VERSION 5.8 ;
BUSBITCHARS "[]" ;
DIVIDERCHAR "/" ;
UNITS
    DATABASE MICRONS 1000 ;
END UNITS

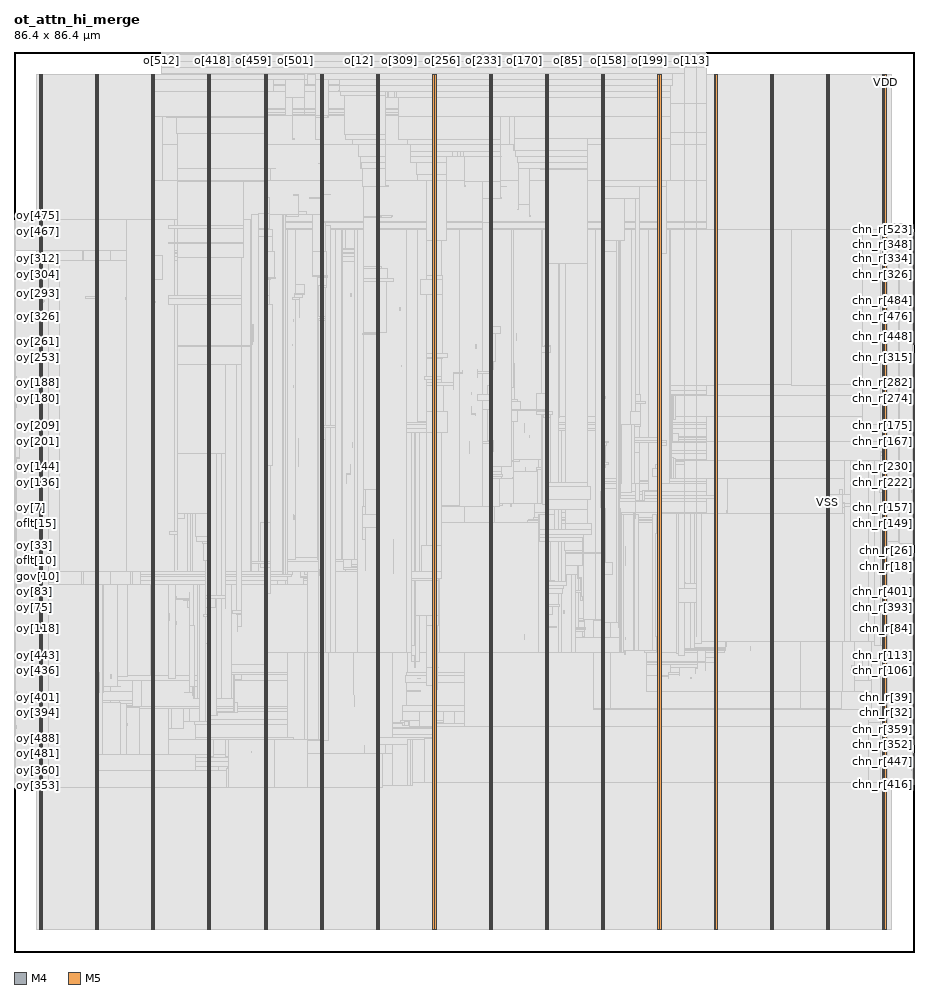
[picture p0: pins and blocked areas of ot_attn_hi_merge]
MACRO ot_attn_hi_merge
  FOREIGN ot_attn_hi_merge 0 0 ;
  CLASS BLOCK ;
  SIZE 86.4 BY 86.4 ;
  PIN chn_r[0]
    DIRECTION INPUT ;
    USE SIGNAL ;
    PORT
      LAYER M4 ;
        RECT  86.316 35.28 86.4 35.304 ;
    END
  END chn_r[0]
  PIN chn_r[100]
    DIRECTION INPUT ;
    USE SIGNAL ;
    PORT
      LAYER M4 ;
        RECT  86.316 26.448 86.4 26.472 ;
    END
  END chn_r[100]
  PIN chn_r[101]
    DIRECTION INPUT ;
    USE SIGNAL ;
    PORT
      LAYER M4 ;
        RECT  86.316 26.544 86.4 26.568 ;
    END
  END chn_r[101]
  PIN chn_r[102]
    DIRECTION INPUT ;
    USE SIGNAL ;
    PORT
      LAYER M4 ;
        RECT  86.316 26.64 86.4 26.664 ;
    END
  END chn_r[102]
  PIN chn_r[103]
    DIRECTION INPUT ;
    USE SIGNAL ;
    PORT
      LAYER M4 ;
        RECT  86.316 26.736 86.4 26.76 ;
    END
  END chn_r[103]
  PIN chn_r[104]
    DIRECTION INPUT ;
    USE SIGNAL ;
    PORT
      LAYER M4 ;
        RECT  86.316 26.832 86.4 26.856 ;
    END
  END chn_r[104]
  PIN chn_r[105]
    DIRECTION INPUT ;
    USE SIGNAL ;
    PORT
      LAYER M4 ;
        RECT  86.316 26.928 86.4 26.952 ;
    END
  END chn_r[105]
  PIN chn_r[106]
    DIRECTION INPUT ;
    USE SIGNAL ;
    PORT
      LAYER M4 ;
        RECT  86.316 27.024 86.4 27.048 ;
    END
  END chn_r[106]
  PIN chn_r[107]
    DIRECTION INPUT ;
    USE SIGNAL ;
    PORT
      LAYER M4 ;
        RECT  86.316 27.12 86.4 27.144 ;
    END
  END chn_r[107]
  PIN chn_r[108]
    DIRECTION INPUT ;
    USE SIGNAL ;
    PORT
      LAYER M4 ;
        RECT  86.316 27.216 86.4 27.24 ;
    END
  END chn_r[108]
  PIN chn_r[109]
    DIRECTION INPUT ;
    USE SIGNAL ;
    PORT
      LAYER M4 ;
        RECT  86.316 27.312 86.4 27.336 ;
    END
  END chn_r[109]
  PIN chn_r[10]
    DIRECTION INPUT ;
    USE SIGNAL ;
    PORT
      LAYER M4 ;
        RECT  86.316 36.24 86.4 36.264 ;
    END
  END chn_r[10]
  PIN chn_r[110]
    DIRECTION INPUT ;
    USE SIGNAL ;
    PORT
      LAYER M4 ;
        RECT  86.316 27.408 86.4 27.432 ;
    END
  END chn_r[110]
  PIN chn_r[111]
    DIRECTION INPUT ;
    USE SIGNAL ;
    PORT
      LAYER M4 ;
        RECT  86.316 27.504 86.4 27.528 ;
    END
  END chn_r[111]
  PIN chn_r[112]
    DIRECTION INPUT ;
    USE SIGNAL ;
    PORT
      LAYER M4 ;
        RECT  86.316 27.6 86.4 27.624 ;
    END
  END chn_r[112]
  PIN chn_r[113]
    DIRECTION INPUT ;
    USE SIGNAL ;
    PORT
      LAYER M4 ;
        RECT  86.316 27.696 86.4 27.72 ;
    END
  END chn_r[113]
  PIN chn_r[114]
    DIRECTION INPUT ;
    USE SIGNAL ;
    PORT
      LAYER M4 ;
        RECT  86.316 27.792 86.4 27.816 ;
    END
  END chn_r[114]
  PIN chn_r[115]
    DIRECTION INPUT ;
    USE SIGNAL ;
    PORT
      LAYER M4 ;
        RECT  86.316 27.888 86.4 27.912 ;
    END
  END chn_r[115]
  PIN chn_r[116]
    DIRECTION INPUT ;
    USE SIGNAL ;
    PORT
      LAYER M4 ;
        RECT  86.316 27.984 86.4 28.008 ;
    END
  END chn_r[116]
  PIN chn_r[117]
    DIRECTION INPUT ;
    USE SIGNAL ;
    PORT
      LAYER M4 ;
        RECT  86.316 28.08 86.4 28.104 ;
    END
  END chn_r[117]
  PIN chn_r[118]
    DIRECTION INPUT ;
    USE SIGNAL ;
    PORT
      LAYER M4 ;
        RECT  86.316 28.176 86.4 28.2 ;
    END
  END chn_r[118]
  PIN chn_r[119]
    DIRECTION INPUT ;
    USE SIGNAL ;
    PORT
      LAYER M4 ;
        RECT  86.316 28.272 86.4 28.296 ;
    END
  END chn_r[119]
  PIN chn_r[11]
    DIRECTION INPUT ;
    USE SIGNAL ;
    PORT
      LAYER M4 ;
        RECT  86.316 36.336 86.4 36.36 ;
    END
  END chn_r[11]
  PIN chn_r[120]
    DIRECTION INPUT ;
    USE SIGNAL ;
    PORT
      LAYER M4 ;
        RECT  86.316 28.368 86.4 28.392 ;
    END
  END chn_r[120]
  PIN chn_r[121]
    DIRECTION INPUT ;
    USE SIGNAL ;
    PORT
      LAYER M4 ;
        RECT  86.316 28.464 86.4 28.488 ;
    END
  END chn_r[121]
  PIN chn_r[122]
    DIRECTION INPUT ;
    USE SIGNAL ;
    PORT
      LAYER M4 ;
        RECT  86.316 28.56 86.4 28.584 ;
    END
  END chn_r[122]
  PIN chn_r[123]
    DIRECTION INPUT ;
    USE SIGNAL ;
    PORT
      LAYER M4 ;
        RECT  86.316 28.656 86.4 28.68 ;
    END
  END chn_r[123]
  PIN chn_r[124]
    DIRECTION INPUT ;
    USE SIGNAL ;
    PORT
      LAYER M4 ;
        RECT  86.316 28.752 86.4 28.776 ;
    END
  END chn_r[124]
  PIN chn_r[125]
    DIRECTION INPUT ;
    USE SIGNAL ;
    PORT
      LAYER M4 ;
        RECT  86.316 28.848 86.4 28.872 ;
    END
  END chn_r[125]
  PIN chn_r[126]
    DIRECTION INPUT ;
    USE SIGNAL ;
    PORT
      LAYER M4 ;
        RECT  86.316 28.944 86.4 28.968 ;
    END
  END chn_r[126]
  PIN chn_r[127]
    DIRECTION INPUT ;
    USE SIGNAL ;
    PORT
      LAYER M4 ;
        RECT  86.316 29.04 86.4 29.064 ;
    END
  END chn_r[127]
  PIN chn_r[128]
    DIRECTION INPUT ;
    USE SIGNAL ;
    PORT
      LAYER M4 ;
        RECT  86.316 39.12 86.4 39.144 ;
    END
  END chn_r[128]
  PIN chn_r[129]
    DIRECTION INPUT ;
    USE SIGNAL ;
    PORT
      LAYER M4 ;
        RECT  86.316 39.216 86.4 39.24 ;
    END
  END chn_r[129]
  PIN chn_r[12]
    DIRECTION INPUT ;
    USE SIGNAL ;
    PORT
      LAYER M4 ;
        RECT  86.316 36.432 86.4 36.456 ;
    END
  END chn_r[12]
  PIN chn_r[130]
    DIRECTION INPUT ;
    USE SIGNAL ;
    PORT
      LAYER M4 ;
        RECT  86.316 39.312 86.4 39.336 ;
    END
  END chn_r[130]
  PIN chn_r[131]
    DIRECTION INPUT ;
    USE SIGNAL ;
    PORT
      LAYER M4 ;
        RECT  86.316 39.408 86.4 39.432 ;
    END
  END chn_r[131]
  PIN chn_r[132]
    DIRECTION INPUT ;
    USE SIGNAL ;
    PORT
      LAYER M4 ;
        RECT  86.316 39.504 86.4 39.528 ;
    END
  END chn_r[132]
  PIN chn_r[133]
    DIRECTION INPUT ;
    USE SIGNAL ;
    PORT
      LAYER M4 ;
        RECT  86.316 39.6 86.4 39.624 ;
    END
  END chn_r[133]
  PIN chn_r[134]
    DIRECTION INPUT ;
    USE SIGNAL ;
    PORT
      LAYER M4 ;
        RECT  86.316 39.696 86.4 39.72 ;
    END
  END chn_r[134]
  PIN chn_r[135]
    DIRECTION INPUT ;
    USE SIGNAL ;
    PORT
      LAYER M4 ;
        RECT  86.316 39.792 86.4 39.816 ;
    END
  END chn_r[135]
  PIN chn_r[136]
    DIRECTION INPUT ;
    USE SIGNAL ;
    PORT
      LAYER M4 ;
        RECT  86.316 39.888 86.4 39.912 ;
    END
  END chn_r[136]
  PIN chn_r[137]
    DIRECTION INPUT ;
    USE SIGNAL ;
    PORT
      LAYER M4 ;
        RECT  86.316 39.984 86.4 40.008 ;
    END
  END chn_r[137]
  PIN chn_r[138]
    DIRECTION INPUT ;
    USE SIGNAL ;
    PORT
      LAYER M4 ;
        RECT  86.316 40.08 86.4 40.104 ;
    END
  END chn_r[138]
  PIN chn_r[139]
    DIRECTION INPUT ;
    USE SIGNAL ;
    PORT
      LAYER M4 ;
        RECT  86.316 40.176 86.4 40.2 ;
    END
  END chn_r[139]
  PIN chn_r[13]
    DIRECTION INPUT ;
    USE SIGNAL ;
    PORT
      LAYER M4 ;
        RECT  86.316 36.528 86.4 36.552 ;
    END
  END chn_r[13]
  PIN chn_r[140]
    DIRECTION INPUT ;
    USE SIGNAL ;
    PORT
      LAYER M4 ;
        RECT  86.316 40.272 86.4 40.296 ;
    END
  END chn_r[140]
  PIN chn_r[141]
    DIRECTION INPUT ;
    USE SIGNAL ;
    PORT
      LAYER M4 ;
        RECT  86.316 40.368 86.4 40.392 ;
    END
  END chn_r[141]
  PIN chn_r[142]
    DIRECTION INPUT ;
    USE SIGNAL ;
    PORT
      LAYER M4 ;
        RECT  86.316 40.464 86.4 40.488 ;
    END
  END chn_r[142]
  PIN chn_r[143]
    DIRECTION INPUT ;
    USE SIGNAL ;
    PORT
      LAYER M4 ;
        RECT  86.316 40.56 86.4 40.584 ;
    END
  END chn_r[143]
  PIN chn_r[144]
    DIRECTION INPUT ;
    USE SIGNAL ;
    PORT
      LAYER M4 ;
        RECT  86.316 40.656 86.4 40.68 ;
    END
  END chn_r[144]
  PIN chn_r[145]
    DIRECTION INPUT ;
    USE SIGNAL ;
    PORT
      LAYER M4 ;
        RECT  86.316 40.752 86.4 40.776 ;
    END
  END chn_r[145]
  PIN chn_r[146]
    DIRECTION INPUT ;
    USE SIGNAL ;
    PORT
      LAYER M4 ;
        RECT  86.316 40.848 86.4 40.872 ;
    END
  END chn_r[146]
  PIN chn_r[147]
    DIRECTION INPUT ;
    USE SIGNAL ;
    PORT
      LAYER M4 ;
        RECT  86.316 40.944 86.4 40.968 ;
    END
  END chn_r[147]
  PIN chn_r[148]
    DIRECTION INPUT ;
    USE SIGNAL ;
    PORT
      LAYER M4 ;
        RECT  86.316 41.04 86.4 41.064 ;
    END
  END chn_r[148]
  PIN chn_r[149]
    DIRECTION INPUT ;
    USE SIGNAL ;
    PORT
      LAYER M4 ;
        RECT  86.316 41.136 86.4 41.16 ;
    END
  END chn_r[149]
  PIN chn_r[14]
    DIRECTION INPUT ;
    USE SIGNAL ;
    PORT
      LAYER M4 ;
        RECT  86.316 36.624 86.4 36.648 ;
    END
  END chn_r[14]
  PIN chn_r[150]
    DIRECTION INPUT ;
    USE SIGNAL ;
    PORT
      LAYER M4 ;
        RECT  86.316 41.232 86.4 41.256 ;
    END
  END chn_r[150]
  PIN chn_r[151]
    DIRECTION INPUT ;
    USE SIGNAL ;
    PORT
      LAYER M4 ;
        RECT  86.316 41.328 86.4 41.352 ;
    END
  END chn_r[151]
  PIN chn_r[152]
    DIRECTION INPUT ;
    USE SIGNAL ;
    PORT
      LAYER M4 ;
        RECT  86.316 41.424 86.4 41.448 ;
    END
  END chn_r[152]
  PIN chn_r[153]
    DIRECTION INPUT ;
    USE SIGNAL ;
    PORT
      LAYER M4 ;
        RECT  86.316 41.52 86.4 41.544 ;
    END
  END chn_r[153]
  PIN chn_r[154]
    DIRECTION INPUT ;
    USE SIGNAL ;
    PORT
      LAYER M4 ;
        RECT  86.316 41.616 86.4 41.64 ;
    END
  END chn_r[154]
  PIN chn_r[155]
    DIRECTION INPUT ;
    USE SIGNAL ;
    PORT
      LAYER M4 ;
        RECT  86.316 41.712 86.4 41.736 ;
    END
  END chn_r[155]
  PIN chn_r[156]
    DIRECTION INPUT ;
    USE SIGNAL ;
    PORT
      LAYER M4 ;
        RECT  86.316 41.808 86.4 41.832 ;
    END
  END chn_r[156]
  PIN chn_r[157]
    DIRECTION INPUT ;
    USE SIGNAL ;
    PORT
      LAYER M4 ;
        RECT  86.316 41.904 86.4 41.928 ;
    END
  END chn_r[157]
  PIN chn_r[158]
    DIRECTION INPUT ;
    USE SIGNAL ;
    PORT
      LAYER M4 ;
        RECT  86.316 42 86.4 42.024 ;
    END
  END chn_r[158]
  PIN chn_r[159]
    DIRECTION INPUT ;
    USE SIGNAL ;
    PORT
      LAYER M4 ;
        RECT  86.316 42.096 86.4 42.12 ;
    END
  END chn_r[159]
  PIN chn_r[15]
    DIRECTION INPUT ;
    USE SIGNAL ;
    PORT
      LAYER M4 ;
        RECT  86.316 36.72 86.4 36.744 ;
    END
  END chn_r[15]
  PIN chn_r[160]
    DIRECTION INPUT ;
    USE SIGNAL ;
    PORT
      LAYER M4 ;
        RECT  86.316 48.336 86.4 48.36 ;
    END
  END chn_r[160]
  PIN chn_r[161]
    DIRECTION INPUT ;
    USE SIGNAL ;
    PORT
      LAYER M4 ;
        RECT  86.316 48.432 86.4 48.456 ;
    END
  END chn_r[161]
  PIN chn_r[162]
    DIRECTION INPUT ;
    USE SIGNAL ;
    PORT
      LAYER M4 ;
        RECT  86.316 48.528 86.4 48.552 ;
    END
  END chn_r[162]
  PIN chn_r[163]
    DIRECTION INPUT ;
    USE SIGNAL ;
    PORT
      LAYER M4 ;
        RECT  86.316 48.624 86.4 48.648 ;
    END
  END chn_r[163]
  PIN chn_r[164]
    DIRECTION INPUT ;
    USE SIGNAL ;
    PORT
      LAYER M4 ;
        RECT  86.316 48.72 86.4 48.744 ;
    END
  END chn_r[164]
  PIN chn_r[165]
    DIRECTION INPUT ;
    USE SIGNAL ;
    PORT
      LAYER M4 ;
        RECT  86.316 48.816 86.4 48.84 ;
    END
  END chn_r[165]
  PIN chn_r[166]
    DIRECTION INPUT ;
    USE SIGNAL ;
    PORT
      LAYER M4 ;
        RECT  86.316 48.912 86.4 48.936 ;
    END
  END chn_r[166]
  PIN chn_r[167]
    DIRECTION INPUT ;
    USE SIGNAL ;
    PORT
      LAYER M4 ;
        RECT  86.316 49.008 86.4 49.032 ;
    END
  END chn_r[167]
  PIN chn_r[168]
    DIRECTION INPUT ;
    USE SIGNAL ;
    PORT
      LAYER M4 ;
        RECT  86.316 49.104 86.4 49.128 ;
    END
  END chn_r[168]
  PIN chn_r[169]
    DIRECTION INPUT ;
    USE SIGNAL ;
    PORT
      LAYER M4 ;
        RECT  86.316 49.2 86.4 49.224 ;
    END
  END chn_r[169]
  PIN chn_r[16]
    DIRECTION INPUT ;
    USE SIGNAL ;
    PORT
      LAYER M4 ;
        RECT  86.316 36.816 86.4 36.84 ;
    END
  END chn_r[16]
  PIN chn_r[170]
    DIRECTION INPUT ;
    USE SIGNAL ;
    PORT
      LAYER M4 ;
        RECT  86.316 49.296 86.4 49.32 ;
    END
  END chn_r[170]
  PIN chn_r[171]
    DIRECTION INPUT ;
    USE SIGNAL ;
    PORT
      LAYER M4 ;
        RECT  86.316 49.392 86.4 49.416 ;
    END
  END chn_r[171]
  PIN chn_r[172]
    DIRECTION INPUT ;
    USE SIGNAL ;
    PORT
      LAYER M4 ;
        RECT  86.316 49.488 86.4 49.512 ;
    END
  END chn_r[172]
  PIN chn_r[173]
    DIRECTION INPUT ;
    USE SIGNAL ;
    PORT
      LAYER M4 ;
        RECT  86.316 49.584 86.4 49.608 ;
    END
  END chn_r[173]
  PIN chn_r[174]
    DIRECTION INPUT ;
    USE SIGNAL ;
    PORT
      LAYER M4 ;
        RECT  86.316 49.68 86.4 49.704 ;
    END
  END chn_r[174]
  PIN chn_r[175]
    DIRECTION INPUT ;
    USE SIGNAL ;
    PORT
      LAYER M4 ;
        RECT  86.316 49.776 86.4 49.8 ;
    END
  END chn_r[175]
  PIN chn_r[176]
    DIRECTION INPUT ;
    USE SIGNAL ;
    PORT
      LAYER M4 ;
        RECT  86.316 49.872 86.4 49.896 ;
    END
  END chn_r[176]
  PIN chn_r[177]
    DIRECTION INPUT ;
    USE SIGNAL ;
    PORT
      LAYER M4 ;
        RECT  86.316 49.968 86.4 49.992 ;
    END
  END chn_r[177]
  PIN chn_r[178]
    DIRECTION INPUT ;
    USE SIGNAL ;
    PORT
      LAYER M4 ;
        RECT  86.316 50.064 86.4 50.088 ;
    END
  END chn_r[178]
  PIN chn_r[179]
    DIRECTION INPUT ;
    USE SIGNAL ;
    PORT
      LAYER M4 ;
        RECT  86.316 50.16 86.4 50.184 ;
    END
  END chn_r[179]
  PIN chn_r[17]
    DIRECTION INPUT ;
    USE SIGNAL ;
    PORT
      LAYER M4 ;
        RECT  86.316 36.912 86.4 36.936 ;
    END
  END chn_r[17]
  PIN chn_r[180]
    DIRECTION INPUT ;
    USE SIGNAL ;
    PORT
      LAYER M4 ;
        RECT  86.316 50.256 86.4 50.28 ;
    END
  END chn_r[180]
  PIN chn_r[181]
    DIRECTION INPUT ;
    USE SIGNAL ;
    PORT
      LAYER M4 ;
        RECT  86.316 50.352 86.4 50.376 ;
    END
  END chn_r[181]
  PIN chn_r[182]
    DIRECTION INPUT ;
    USE SIGNAL ;
    PORT
      LAYER M4 ;
        RECT  86.316 50.448 86.4 50.472 ;
    END
  END chn_r[182]
  PIN chn_r[183]
    DIRECTION INPUT ;
    USE SIGNAL ;
    PORT
      LAYER M4 ;
        RECT  86.316 50.544 86.4 50.568 ;
    END
  END chn_r[183]
  PIN chn_r[184]
    DIRECTION INPUT ;
    USE SIGNAL ;
    PORT
      LAYER M4 ;
        RECT  86.316 50.64 86.4 50.664 ;
    END
  END chn_r[184]
  PIN chn_r[185]
    DIRECTION INPUT ;
    USE SIGNAL ;
    PORT
      LAYER M4 ;
        RECT  86.316 50.736 86.4 50.76 ;
    END
  END chn_r[185]
  PIN chn_r[186]
    DIRECTION INPUT ;
    USE SIGNAL ;
    PORT
      LAYER M4 ;
        RECT  86.316 50.832 86.4 50.856 ;
    END
  END chn_r[186]
  PIN chn_r[187]
    DIRECTION INPUT ;
    USE SIGNAL ;
    PORT
      LAYER M4 ;
        RECT  86.316 50.928 86.4 50.952 ;
    END
  END chn_r[187]
  PIN chn_r[188]
    DIRECTION INPUT ;
    USE SIGNAL ;
    PORT
      LAYER M4 ;
        RECT  86.316 51.024 86.4 51.048 ;
    END
  END chn_r[188]
  PIN chn_r[189]
    DIRECTION INPUT ;
    USE SIGNAL ;
    PORT
      LAYER M4 ;
        RECT  86.316 51.12 86.4 51.144 ;
    END
  END chn_r[189]
  PIN chn_r[18]
    DIRECTION INPUT ;
    USE SIGNAL ;
    PORT
      LAYER M4 ;
        RECT  86.316 37.008 86.4 37.032 ;
    END
  END chn_r[18]
  PIN chn_r[190]
    DIRECTION INPUT ;
    USE SIGNAL ;
    PORT
      LAYER M4 ;
        RECT  86.316 51.216 86.4 51.24 ;
    END
  END chn_r[190]
  PIN chn_r[191]
    DIRECTION INPUT ;
    USE SIGNAL ;
    PORT
      LAYER M4 ;
        RECT  86.316 51.312 86.4 51.336 ;
    END
  END chn_r[191]
  PIN chn_r[192]
    DIRECTION INPUT ;
    USE SIGNAL ;
    PORT
      LAYER M4 ;
        RECT  86.316 42.192 86.4 42.216 ;
    END
  END chn_r[192]
  PIN chn_r[193]
    DIRECTION INPUT ;
    USE SIGNAL ;
    PORT
      LAYER M4 ;
        RECT  86.316 42.288 86.4 42.312 ;
    END
  END chn_r[193]
  PIN chn_r[194]
    DIRECTION INPUT ;
    USE SIGNAL ;
    PORT
      LAYER M4 ;
        RECT  86.316 42.384 86.4 42.408 ;
    END
  END chn_r[194]
  PIN chn_r[195]
    DIRECTION INPUT ;
    USE SIGNAL ;
    PORT
      LAYER M4 ;
        RECT  86.316 42.48 86.4 42.504 ;
    END
  END chn_r[195]
  PIN chn_r[196]
    DIRECTION INPUT ;
    USE SIGNAL ;
    PORT
      LAYER M4 ;
        RECT  86.316 42.576 86.4 42.6 ;
    END
  END chn_r[196]
  PIN chn_r[197]
    DIRECTION INPUT ;
    USE SIGNAL ;
    PORT
      LAYER M4 ;
        RECT  86.316 42.672 86.4 42.696 ;
    END
  END chn_r[197]
  PIN chn_r[198]
    DIRECTION INPUT ;
    USE SIGNAL ;
    PORT
      LAYER M4 ;
        RECT  86.316 42.768 86.4 42.792 ;
    END
  END chn_r[198]
  PIN chn_r[199]
    DIRECTION INPUT ;
    USE SIGNAL ;
    PORT
      LAYER M4 ;
        RECT  86.316 42.864 86.4 42.888 ;
    END
  END chn_r[199]
  PIN chn_r[19]
    DIRECTION INPUT ;
    USE SIGNAL ;
    PORT
      LAYER M4 ;
        RECT  86.316 37.104 86.4 37.128 ;
    END
  END chn_r[19]
  PIN chn_r[1]
    DIRECTION INPUT ;
    USE SIGNAL ;
    PORT
      LAYER M4 ;
        RECT  86.316 35.376 86.4 35.4 ;
    END
  END chn_r[1]
  PIN chn_r[200]
    DIRECTION INPUT ;
    USE SIGNAL ;
    PORT
      LAYER M4 ;
        RECT  86.316 42.96 86.4 42.984 ;
    END
  END chn_r[200]
  PIN chn_r[201]
    DIRECTION INPUT ;
    USE SIGNAL ;
    PORT
      LAYER M4 ;
        RECT  86.316 43.056 86.4 43.08 ;
    END
  END chn_r[201]
  PIN chn_r[202]
    DIRECTION INPUT ;
    USE SIGNAL ;
    PORT
      LAYER M4 ;
        RECT  86.316 43.152 86.4 43.176 ;
    END
  END chn_r[202]
  PIN chn_r[203]
    DIRECTION INPUT ;
    USE SIGNAL ;
    PORT
      LAYER M4 ;
        RECT  86.316 43.248 86.4 43.272 ;
    END
  END chn_r[203]
  PIN chn_r[204]
    DIRECTION INPUT ;
    USE SIGNAL ;
    PORT
      LAYER M4 ;
        RECT  86.316 43.344 86.4 43.368 ;
    END
  END chn_r[204]
  PIN chn_r[205]
    DIRECTION INPUT ;
    USE SIGNAL ;
    PORT
      LAYER M4 ;
        RECT  86.316 43.44 86.4 43.464 ;
    END
  END chn_r[205]
  PIN chn_r[206]
    DIRECTION INPUT ;
    USE SIGNAL ;
    PORT
      LAYER M4 ;
        RECT  86.316 43.536 86.4 43.56 ;
    END
  END chn_r[206]
  PIN chn_r[207]
    DIRECTION INPUT ;
    USE SIGNAL ;
    PORT
      LAYER M4 ;
        RECT  86.316 43.632 86.4 43.656 ;
    END
  END chn_r[207]
  PIN chn_r[208]
    DIRECTION INPUT ;
    USE SIGNAL ;
    PORT
      LAYER M4 ;
        RECT  86.316 43.728 86.4 43.752 ;
    END
  END chn_r[208]
  PIN chn_r[209]
    DIRECTION INPUT ;
    USE SIGNAL ;
    PORT
      LAYER M4 ;
        RECT  86.316 43.824 86.4 43.848 ;
    END
  END chn_r[209]
  PIN chn_r[20]
    DIRECTION INPUT ;
    USE SIGNAL ;
    PORT
      LAYER M4 ;
        RECT  86.316 37.2 86.4 37.224 ;
    END
  END chn_r[20]
  PIN chn_r[210]
    DIRECTION INPUT ;
    USE SIGNAL ;
    PORT
      LAYER M4 ;
        RECT  86.316 43.92 86.4 43.944 ;
    END
  END chn_r[210]
  PIN chn_r[211]
    DIRECTION INPUT ;
    USE SIGNAL ;
    PORT
      LAYER M4 ;
        RECT  86.316 44.016 86.4 44.04 ;
    END
  END chn_r[211]
  PIN chn_r[212]
    DIRECTION INPUT ;
    USE SIGNAL ;
    PORT
      LAYER M4 ;
        RECT  86.316 44.112 86.4 44.136 ;
    END
  END chn_r[212]
  PIN chn_r[213]
    DIRECTION INPUT ;
    USE SIGNAL ;
    PORT
      LAYER M4 ;
        RECT  86.316 44.208 86.4 44.232 ;
    END
  END chn_r[213]
  PIN chn_r[214]
    DIRECTION INPUT ;
    USE SIGNAL ;
    PORT
      LAYER M4 ;
        RECT  86.316 44.304 86.4 44.328 ;
    END
  END chn_r[214]
  PIN chn_r[215]
    DIRECTION INPUT ;
    USE SIGNAL ;
    PORT
      LAYER M4 ;
        RECT  86.316 44.4 86.4 44.424 ;
    END
  END chn_r[215]
  PIN chn_r[216]
    DIRECTION INPUT ;
    USE SIGNAL ;
    PORT
      LAYER M4 ;
        RECT  86.316 44.496 86.4 44.52 ;
    END
  END chn_r[216]
  PIN chn_r[217]
    DIRECTION INPUT ;
    USE SIGNAL ;
    PORT
      LAYER M4 ;
        RECT  86.316 44.592 86.4 44.616 ;
    END
  END chn_r[217]
  PIN chn_r[218]
    DIRECTION INPUT ;
    USE SIGNAL ;
    PORT
      LAYER M4 ;
        RECT  86.316 44.688 86.4 44.712 ;
    END
  END chn_r[218]
  PIN chn_r[219]
    DIRECTION INPUT ;
    USE SIGNAL ;
    PORT
      LAYER M4 ;
        RECT  86.316 44.784 86.4 44.808 ;
    END
  END chn_r[219]
  PIN chn_r[21]
    DIRECTION INPUT ;
    USE SIGNAL ;
    PORT
      LAYER M4 ;
        RECT  86.316 37.296 86.4 37.32 ;
    END
  END chn_r[21]
  PIN chn_r[220]
    DIRECTION INPUT ;
    USE SIGNAL ;
    PORT
      LAYER M4 ;
        RECT  86.316 44.88 86.4 44.904 ;
    END
  END chn_r[220]
  PIN chn_r[221]
    DIRECTION INPUT ;
    USE SIGNAL ;
    PORT
      LAYER M4 ;
        RECT  86.316 44.976 86.4 45 ;
    END
  END chn_r[221]
  PIN chn_r[222]
    DIRECTION INPUT ;
    USE SIGNAL ;
    PORT
      LAYER M4 ;
        RECT  86.316 45.072 86.4 45.096 ;
    END
  END chn_r[222]
  PIN chn_r[223]
    DIRECTION INPUT ;
    USE SIGNAL ;
    PORT
      LAYER M4 ;
        RECT  86.316 45.168 86.4 45.192 ;
    END
  END chn_r[223]
  PIN chn_r[224]
    DIRECTION INPUT ;
    USE SIGNAL ;
    PORT
      LAYER M4 ;
        RECT  86.316 45.264 86.4 45.288 ;
    END
  END chn_r[224]
  PIN chn_r[225]
    DIRECTION INPUT ;
    USE SIGNAL ;
    PORT
      LAYER M4 ;
        RECT  86.316 45.36 86.4 45.384 ;
    END
  END chn_r[225]
  PIN chn_r[226]
    DIRECTION INPUT ;
    USE SIGNAL ;
    PORT
      LAYER M4 ;
        RECT  86.316 45.456 86.4 45.48 ;
    END
  END chn_r[226]
  PIN chn_r[227]
    DIRECTION INPUT ;
    USE SIGNAL ;
    PORT
      LAYER M4 ;
        RECT  86.316 45.552 86.4 45.576 ;
    END
  END chn_r[227]
  PIN chn_r[228]
    DIRECTION INPUT ;
    USE SIGNAL ;
    PORT
      LAYER M4 ;
        RECT  86.316 45.648 86.4 45.672 ;
    END
  END chn_r[228]
  PIN chn_r[229]
    DIRECTION INPUT ;
    USE SIGNAL ;
    PORT
      LAYER M4 ;
        RECT  86.316 45.744 86.4 45.768 ;
    END
  END chn_r[229]
  PIN chn_r[22]
    DIRECTION INPUT ;
    USE SIGNAL ;
    PORT
      LAYER M4 ;
        RECT  86.316 37.392 86.4 37.416 ;
    END
  END chn_r[22]
  PIN chn_r[230]
    DIRECTION INPUT ;
    USE SIGNAL ;
    PORT
      LAYER M4 ;
        RECT  86.316 45.84 86.4 45.864 ;
    END
  END chn_r[230]
  PIN chn_r[231]
    DIRECTION INPUT ;
    USE SIGNAL ;
    PORT
      LAYER M4 ;
        RECT  86.316 45.936 86.4 45.96 ;
    END
  END chn_r[231]
  PIN chn_r[232]
    DIRECTION INPUT ;
    USE SIGNAL ;
    PORT
      LAYER M4 ;
        RECT  86.316 46.032 86.4 46.056 ;
    END
  END chn_r[232]
  PIN chn_r[233]
    DIRECTION INPUT ;
    USE SIGNAL ;
    PORT
      LAYER M4 ;
        RECT  86.316 46.128 86.4 46.152 ;
    END
  END chn_r[233]
  PIN chn_r[234]
    DIRECTION INPUT ;
    USE SIGNAL ;
    PORT
      LAYER M4 ;
        RECT  86.316 46.224 86.4 46.248 ;
    END
  END chn_r[234]
  PIN chn_r[235]
    DIRECTION INPUT ;
    USE SIGNAL ;
    PORT
      LAYER M4 ;
        RECT  86.316 46.32 86.4 46.344 ;
    END
  END chn_r[235]
  PIN chn_r[236]
    DIRECTION INPUT ;
    USE SIGNAL ;
    PORT
      LAYER M4 ;
        RECT  86.316 46.416 86.4 46.44 ;
    END
  END chn_r[236]
  PIN chn_r[237]
    DIRECTION INPUT ;
    USE SIGNAL ;
    PORT
      LAYER M4 ;
        RECT  86.316 46.512 86.4 46.536 ;
    END
  END chn_r[237]
  PIN chn_r[238]
    DIRECTION INPUT ;
    USE SIGNAL ;
    PORT
      LAYER M4 ;
        RECT  86.316 46.608 86.4 46.632 ;
    END
  END chn_r[238]
  PIN chn_r[239]
    DIRECTION INPUT ;
    USE SIGNAL ;
    PORT
      LAYER M4 ;
        RECT  86.316 46.704 86.4 46.728 ;
    END
  END chn_r[239]
  PIN chn_r[23]
    DIRECTION INPUT ;
    USE SIGNAL ;
    PORT
      LAYER M4 ;
        RECT  86.316 37.488 86.4 37.512 ;
    END
  END chn_r[23]
  PIN chn_r[240]
    DIRECTION INPUT ;
    USE SIGNAL ;
    PORT
      LAYER M4 ;
        RECT  86.316 46.8 86.4 46.824 ;
    END
  END chn_r[240]
  PIN chn_r[241]
    DIRECTION INPUT ;
    USE SIGNAL ;
    PORT
      LAYER M4 ;
        RECT  86.316 46.896 86.4 46.92 ;
    END
  END chn_r[241]
  PIN chn_r[242]
    DIRECTION INPUT ;
    USE SIGNAL ;
    PORT
      LAYER M4 ;
        RECT  86.316 46.992 86.4 47.016 ;
    END
  END chn_r[242]
  PIN chn_r[243]
    DIRECTION INPUT ;
    USE SIGNAL ;
    PORT
      LAYER M4 ;
        RECT  86.316 47.088 86.4 47.112 ;
    END
  END chn_r[243]
  PIN chn_r[244]
    DIRECTION INPUT ;
    USE SIGNAL ;
    PORT
      LAYER M4 ;
        RECT  86.316 47.184 86.4 47.208 ;
    END
  END chn_r[244]
  PIN chn_r[245]
    DIRECTION INPUT ;
    USE SIGNAL ;
    PORT
      LAYER M4 ;
        RECT  86.316 47.28 86.4 47.304 ;
    END
  END chn_r[245]
  PIN chn_r[246]
    DIRECTION INPUT ;
    USE SIGNAL ;
    PORT
      LAYER M4 ;
        RECT  86.316 47.376 86.4 47.4 ;
    END
  END chn_r[246]
  PIN chn_r[247]
    DIRECTION INPUT ;
    USE SIGNAL ;
    PORT
      LAYER M4 ;
        RECT  86.316 47.472 86.4 47.496 ;
    END
  END chn_r[247]
  PIN chn_r[248]
    DIRECTION INPUT ;
    USE SIGNAL ;
    PORT
      LAYER M4 ;
        RECT  86.316 47.568 86.4 47.592 ;
    END
  END chn_r[248]
  PIN chn_r[249]
    DIRECTION INPUT ;
    USE SIGNAL ;
    PORT
      LAYER M4 ;
        RECT  86.316 47.664 86.4 47.688 ;
    END
  END chn_r[249]
  PIN chn_r[24]
    DIRECTION INPUT ;
    USE SIGNAL ;
    PORT
      LAYER M4 ;
        RECT  86.316 37.584 86.4 37.608 ;
    END
  END chn_r[24]
  PIN chn_r[250]
    DIRECTION INPUT ;
    USE SIGNAL ;
    PORT
      LAYER M4 ;
        RECT  86.316 47.76 86.4 47.784 ;
    END
  END chn_r[250]
  PIN chn_r[251]
    DIRECTION INPUT ;
    USE SIGNAL ;
    PORT
      LAYER M4 ;
        RECT  86.316 47.856 86.4 47.88 ;
    END
  END chn_r[251]
  PIN chn_r[252]
    DIRECTION INPUT ;
    USE SIGNAL ;
    PORT
      LAYER M4 ;
        RECT  86.316 47.952 86.4 47.976 ;
    END
  END chn_r[252]
  PIN chn_r[253]
    DIRECTION INPUT ;
    USE SIGNAL ;
    PORT
      LAYER M4 ;
        RECT  86.316 48.048 86.4 48.072 ;
    END
  END chn_r[253]
  PIN chn_r[254]
    DIRECTION INPUT ;
    USE SIGNAL ;
    PORT
      LAYER M4 ;
        RECT  86.316 48.144 86.4 48.168 ;
    END
  END chn_r[254]
  PIN chn_r[255]
    DIRECTION INPUT ;
    USE SIGNAL ;
    PORT
      LAYER M4 ;
        RECT  86.316 48.24 86.4 48.264 ;
    END
  END chn_r[255]
  PIN chn_r[256]
    DIRECTION INPUT ;
    USE SIGNAL ;
    PORT
      LAYER M4 ;
        RECT  86.316 51.408 86.4 51.432 ;
    END
  END chn_r[256]
  PIN chn_r[257]
    DIRECTION INPUT ;
    USE SIGNAL ;
    PORT
      LAYER M4 ;
        RECT  86.316 51.504 86.4 51.528 ;
    END
  END chn_r[257]
  PIN chn_r[258]
    DIRECTION INPUT ;
    USE SIGNAL ;
    PORT
      LAYER M4 ;
        RECT  86.316 51.6 86.4 51.624 ;
    END
  END chn_r[258]
  PIN chn_r[259]
    DIRECTION INPUT ;
    USE SIGNAL ;
    PORT
      LAYER M4 ;
        RECT  86.316 51.696 86.4 51.72 ;
    END
  END chn_r[259]
  PIN chn_r[25]
    DIRECTION INPUT ;
    USE SIGNAL ;
    PORT
      LAYER M4 ;
        RECT  86.316 37.68 86.4 37.704 ;
    END
  END chn_r[25]
  PIN chn_r[260]
    DIRECTION INPUT ;
    USE SIGNAL ;
    PORT
      LAYER M4 ;
        RECT  86.316 51.792 86.4 51.816 ;
    END
  END chn_r[260]
  PIN chn_r[261]
    DIRECTION INPUT ;
    USE SIGNAL ;
    PORT
      LAYER M4 ;
        RECT  86.316 51.888 86.4 51.912 ;
    END
  END chn_r[261]
  PIN chn_r[262]
    DIRECTION INPUT ;
    USE SIGNAL ;
    PORT
      LAYER M4 ;
        RECT  86.316 51.984 86.4 52.008 ;
    END
  END chn_r[262]
  PIN chn_r[263]
    DIRECTION INPUT ;
    USE SIGNAL ;
    PORT
      LAYER M4 ;
        RECT  86.316 52.08 86.4 52.104 ;
    END
  END chn_r[263]
  PIN chn_r[264]
    DIRECTION INPUT ;
    USE SIGNAL ;
    PORT
      LAYER M4 ;
        RECT  86.316 52.176 86.4 52.2 ;
    END
  END chn_r[264]
  PIN chn_r[265]
    DIRECTION INPUT ;
    USE SIGNAL ;
    PORT
      LAYER M4 ;
        RECT  86.316 52.272 86.4 52.296 ;
    END
  END chn_r[265]
  PIN chn_r[266]
    DIRECTION INPUT ;
    USE SIGNAL ;
    PORT
      LAYER M4 ;
        RECT  86.316 52.368 86.4 52.392 ;
    END
  END chn_r[266]
  PIN chn_r[267]
    DIRECTION INPUT ;
    USE SIGNAL ;
    PORT
      LAYER M4 ;
        RECT  86.316 52.464 86.4 52.488 ;
    END
  END chn_r[267]
  PIN chn_r[268]
    DIRECTION INPUT ;
    USE SIGNAL ;
    PORT
      LAYER M4 ;
        RECT  86.316 52.56 86.4 52.584 ;
    END
  END chn_r[268]
  PIN chn_r[269]
    DIRECTION INPUT ;
    USE SIGNAL ;
    PORT
      LAYER M4 ;
        RECT  86.316 52.656 86.4 52.68 ;
    END
  END chn_r[269]
  PIN chn_r[26]
    DIRECTION INPUT ;
    USE SIGNAL ;
    PORT
      LAYER M4 ;
        RECT  86.316 37.776 86.4 37.8 ;
    END
  END chn_r[26]
  PIN chn_r[270]
    DIRECTION INPUT ;
    USE SIGNAL ;
    PORT
      LAYER M4 ;
        RECT  86.316 52.752 86.4 52.776 ;
    END
  END chn_r[270]
  PIN chn_r[271]
    DIRECTION INPUT ;
    USE SIGNAL ;
    PORT
      LAYER M4 ;
        RECT  86.316 52.848 86.4 52.872 ;
    END
  END chn_r[271]
  PIN chn_r[272]
    DIRECTION INPUT ;
    USE SIGNAL ;
    PORT
      LAYER M4 ;
        RECT  86.316 52.944 86.4 52.968 ;
    END
  END chn_r[272]
  PIN chn_r[273]
    DIRECTION INPUT ;
    USE SIGNAL ;
    PORT
      LAYER M4 ;
        RECT  86.316 53.04 86.4 53.064 ;
    END
  END chn_r[273]
  PIN chn_r[274]
    DIRECTION INPUT ;
    USE SIGNAL ;
    PORT
      LAYER M4 ;
        RECT  86.316 53.136 86.4 53.16 ;
    END
  END chn_r[274]
  PIN chn_r[275]
    DIRECTION INPUT ;
    USE SIGNAL ;
    PORT
      LAYER M4 ;
        RECT  86.316 53.232 86.4 53.256 ;
    END
  END chn_r[275]
  PIN chn_r[276]
    DIRECTION INPUT ;
    USE SIGNAL ;
    PORT
      LAYER M4 ;
        RECT  86.316 53.328 86.4 53.352 ;
    END
  END chn_r[276]
  PIN chn_r[277]
    DIRECTION INPUT ;
    USE SIGNAL ;
    PORT
      LAYER M4 ;
        RECT  86.316 53.424 86.4 53.448 ;
    END
  END chn_r[277]
  PIN chn_r[278]
    DIRECTION INPUT ;
    USE SIGNAL ;
    PORT
      LAYER M4 ;
        RECT  86.316 53.52 86.4 53.544 ;
    END
  END chn_r[278]
  PIN chn_r[279]
    DIRECTION INPUT ;
    USE SIGNAL ;
    PORT
      LAYER M4 ;
        RECT  86.316 53.616 86.4 53.64 ;
    END
  END chn_r[279]
  PIN chn_r[27]
    DIRECTION INPUT ;
    USE SIGNAL ;
    PORT
      LAYER M4 ;
        RECT  86.316 37.872 86.4 37.896 ;
    END
  END chn_r[27]
  PIN chn_r[280]
    DIRECTION INPUT ;
    USE SIGNAL ;
    PORT
      LAYER M4 ;
        RECT  86.316 53.712 86.4 53.736 ;
    END
  END chn_r[280]
  PIN chn_r[281]
    DIRECTION INPUT ;
    USE SIGNAL ;
    PORT
      LAYER M4 ;
        RECT  86.316 53.808 86.4 53.832 ;
    END
  END chn_r[281]
  PIN chn_r[282]
    DIRECTION INPUT ;
    USE SIGNAL ;
    PORT
      LAYER M4 ;
        RECT  86.316 53.904 86.4 53.928 ;
    END
  END chn_r[282]
  PIN chn_r[283]
    DIRECTION INPUT ;
    USE SIGNAL ;
    PORT
      LAYER M4 ;
        RECT  86.316 54 86.4 54.024 ;
    END
  END chn_r[283]
  PIN chn_r[284]
    DIRECTION INPUT ;
    USE SIGNAL ;
    PORT
      LAYER M4 ;
        RECT  86.316 54.096 86.4 54.12 ;
    END
  END chn_r[284]
  PIN chn_r[285]
    DIRECTION INPUT ;
    USE SIGNAL ;
    PORT
      LAYER M4 ;
        RECT  86.316 54.192 86.4 54.216 ;
    END
  END chn_r[285]
  PIN chn_r[286]
    DIRECTION INPUT ;
    USE SIGNAL ;
    PORT
      LAYER M4 ;
        RECT  86.316 54.288 86.4 54.312 ;
    END
  END chn_r[286]
  PIN chn_r[287]
    DIRECTION INPUT ;
    USE SIGNAL ;
    PORT
      LAYER M4 ;
        RECT  86.316 54.384 86.4 54.408 ;
    END
  END chn_r[287]
  PIN chn_r[288]
    DIRECTION INPUT ;
    USE SIGNAL ;
    PORT
      LAYER M4 ;
        RECT  86.316 54.48 86.4 54.504 ;
    END
  END chn_r[288]
  PIN chn_r[289]
    DIRECTION INPUT ;
    USE SIGNAL ;
    PORT
      LAYER M4 ;
        RECT  86.316 54.576 86.4 54.6 ;
    END
  END chn_r[289]
  PIN chn_r[28]
    DIRECTION INPUT ;
    USE SIGNAL ;
    PORT
      LAYER M4 ;
        RECT  86.316 37.968 86.4 37.992 ;
    END
  END chn_r[28]
  PIN chn_r[290]
    DIRECTION INPUT ;
    USE SIGNAL ;
    PORT
      LAYER M4 ;
        RECT  86.316 54.672 86.4 54.696 ;
    END
  END chn_r[290]
  PIN chn_r[291]
    DIRECTION INPUT ;
    USE SIGNAL ;
    PORT
      LAYER M4 ;
        RECT  86.316 54.768 86.4 54.792 ;
    END
  END chn_r[291]
  PIN chn_r[292]
    DIRECTION INPUT ;
    USE SIGNAL ;
    PORT
      LAYER M4 ;
        RECT  86.316 54.864 86.4 54.888 ;
    END
  END chn_r[292]
  PIN chn_r[293]
    DIRECTION INPUT ;
    USE SIGNAL ;
    PORT
      LAYER M4 ;
        RECT  86.316 54.96 86.4 54.984 ;
    END
  END chn_r[293]
  PIN chn_r[294]
    DIRECTION INPUT ;
    USE SIGNAL ;
    PORT
      LAYER M4 ;
        RECT  86.316 55.056 86.4 55.08 ;
    END
  END chn_r[294]
  PIN chn_r[295]
    DIRECTION INPUT ;
    USE SIGNAL ;
    PORT
      LAYER M4 ;
        RECT  86.316 55.152 86.4 55.176 ;
    END
  END chn_r[295]
  PIN chn_r[296]
    DIRECTION INPUT ;
    USE SIGNAL ;
    PORT
      LAYER M4 ;
        RECT  86.316 55.248 86.4 55.272 ;
    END
  END chn_r[296]
  PIN chn_r[297]
    DIRECTION INPUT ;
    USE SIGNAL ;
    PORT
      LAYER M4 ;
        RECT  86.316 55.344 86.4 55.368 ;
    END
  END chn_r[297]
  PIN chn_r[298]
    DIRECTION INPUT ;
    USE SIGNAL ;
    PORT
      LAYER M4 ;
        RECT  86.316 55.44 86.4 55.464 ;
    END
  END chn_r[298]
  PIN chn_r[299]
    DIRECTION INPUT ;
    USE SIGNAL ;
    PORT
      LAYER M4 ;
        RECT  86.316 55.536 86.4 55.56 ;
    END
  END chn_r[299]
  PIN chn_r[29]
    DIRECTION INPUT ;
    USE SIGNAL ;
    PORT
      LAYER M4 ;
        RECT  86.316 38.064 86.4 38.088 ;
    END
  END chn_r[29]
  PIN chn_r[2]
    DIRECTION INPUT ;
    USE SIGNAL ;
    PORT
      LAYER M4 ;
        RECT  86.316 35.472 86.4 35.496 ;
    END
  END chn_r[2]
  PIN chn_r[300]
    DIRECTION INPUT ;
    USE SIGNAL ;
    PORT
      LAYER M4 ;
        RECT  86.316 55.632 86.4 55.656 ;
    END
  END chn_r[300]
  PIN chn_r[301]
    DIRECTION INPUT ;
    USE SIGNAL ;
    PORT
      LAYER M4 ;
        RECT  86.316 55.728 86.4 55.752 ;
    END
  END chn_r[301]
  PIN chn_r[302]
    DIRECTION INPUT ;
    USE SIGNAL ;
    PORT
      LAYER M4 ;
        RECT  86.316 55.824 86.4 55.848 ;
    END
  END chn_r[302]
  PIN chn_r[303]
    DIRECTION INPUT ;
    USE SIGNAL ;
    PORT
      LAYER M4 ;
        RECT  86.316 55.92 86.4 55.944 ;
    END
  END chn_r[303]
  PIN chn_r[304]
    DIRECTION INPUT ;
    USE SIGNAL ;
    PORT
      LAYER M4 ;
        RECT  86.316 56.016 86.4 56.04 ;
    END
  END chn_r[304]
  PIN chn_r[305]
    DIRECTION INPUT ;
    USE SIGNAL ;
    PORT
      LAYER M4 ;
        RECT  86.316 56.112 86.4 56.136 ;
    END
  END chn_r[305]
  PIN chn_r[306]
    DIRECTION INPUT ;
    USE SIGNAL ;
    PORT
      LAYER M4 ;
        RECT  86.316 56.208 86.4 56.232 ;
    END
  END chn_r[306]
  PIN chn_r[307]
    DIRECTION INPUT ;
    USE SIGNAL ;
    PORT
      LAYER M4 ;
        RECT  86.316 56.304 86.4 56.328 ;
    END
  END chn_r[307]
  PIN chn_r[308]
    DIRECTION INPUT ;
    USE SIGNAL ;
    PORT
      LAYER M4 ;
        RECT  86.316 56.4 86.4 56.424 ;
    END
  END chn_r[308]
  PIN chn_r[309]
    DIRECTION INPUT ;
    USE SIGNAL ;
    PORT
      LAYER M4 ;
        RECT  86.316 56.496 86.4 56.52 ;
    END
  END chn_r[309]
  PIN chn_r[30]
    DIRECTION INPUT ;
    USE SIGNAL ;
    PORT
      LAYER M4 ;
        RECT  86.316 38.16 86.4 38.184 ;
    END
  END chn_r[30]
  PIN chn_r[310]
    DIRECTION INPUT ;
    USE SIGNAL ;
    PORT
      LAYER M4 ;
        RECT  86.316 56.592 86.4 56.616 ;
    END
  END chn_r[310]
  PIN chn_r[311]
    DIRECTION INPUT ;
    USE SIGNAL ;
    PORT
      LAYER M4 ;
        RECT  86.316 56.688 86.4 56.712 ;
    END
  END chn_r[311]
  PIN chn_r[312]
    DIRECTION INPUT ;
    USE SIGNAL ;
    PORT
      LAYER M4 ;
        RECT  86.316 56.784 86.4 56.808 ;
    END
  END chn_r[312]
  PIN chn_r[313]
    DIRECTION INPUT ;
    USE SIGNAL ;
    PORT
      LAYER M4 ;
        RECT  86.316 56.88 86.4 56.904 ;
    END
  END chn_r[313]
  PIN chn_r[314]
    DIRECTION INPUT ;
    USE SIGNAL ;
    PORT
      LAYER M4 ;
        RECT  86.316 56.976 86.4 57 ;
    END
  END chn_r[314]
  PIN chn_r[315]
    DIRECTION INPUT ;
    USE SIGNAL ;
    PORT
      LAYER M4 ;
        RECT  86.316 57.072 86.4 57.096 ;
    END
  END chn_r[315]
  PIN chn_r[316]
    DIRECTION INPUT ;
    USE SIGNAL ;
    PORT
      LAYER M4 ;
        RECT  86.316 57.168 86.4 57.192 ;
    END
  END chn_r[316]
  PIN chn_r[317]
    DIRECTION INPUT ;
    USE SIGNAL ;
    PORT
      LAYER M4 ;
        RECT  86.316 57.264 86.4 57.288 ;
    END
  END chn_r[317]
  PIN chn_r[318]
    DIRECTION INPUT ;
    USE SIGNAL ;
    PORT
      LAYER M4 ;
        RECT  86.316 57.36 86.4 57.384 ;
    END
  END chn_r[318]
  PIN chn_r[319]
    DIRECTION INPUT ;
    USE SIGNAL ;
    PORT
      LAYER M4 ;
        RECT  86.316 57.456 86.4 57.48 ;
    END
  END chn_r[319]
  PIN chn_r[31]
    DIRECTION INPUT ;
    USE SIGNAL ;
    PORT
      LAYER M4 ;
        RECT  86.316 38.256 86.4 38.28 ;
    END
  END chn_r[31]
  PIN chn_r[320]
    DIRECTION INPUT ;
    USE SIGNAL ;
    PORT
      LAYER M4 ;
        RECT  86.316 64.464 86.4 64.488 ;
    END
  END chn_r[320]
  PIN chn_r[321]
    DIRECTION INPUT ;
    USE SIGNAL ;
    PORT
      LAYER M4 ;
        RECT  86.316 64.56 86.4 64.584 ;
    END
  END chn_r[321]
  PIN chn_r[322]
    DIRECTION INPUT ;
    USE SIGNAL ;
    PORT
      LAYER M4 ;
        RECT  86.316 64.656 86.4 64.68 ;
    END
  END chn_r[322]
  PIN chn_r[323]
    DIRECTION INPUT ;
    USE SIGNAL ;
    PORT
      LAYER M4 ;
        RECT  86.316 64.752 86.4 64.776 ;
    END
  END chn_r[323]
  PIN chn_r[324]
    DIRECTION INPUT ;
    USE SIGNAL ;
    PORT
      LAYER M4 ;
        RECT  86.316 64.848 86.4 64.872 ;
    END
  END chn_r[324]
  PIN chn_r[325]
    DIRECTION INPUT ;
    USE SIGNAL ;
    PORT
      LAYER M4 ;
        RECT  86.316 64.944 86.4 64.968 ;
    END
  END chn_r[325]
  PIN chn_r[326]
    DIRECTION INPUT ;
    USE SIGNAL ;
    PORT
      LAYER M4 ;
        RECT  86.316 65.04 86.4 65.064 ;
    END
  END chn_r[326]
  PIN chn_r[327]
    DIRECTION INPUT ;
    USE SIGNAL ;
    PORT
      LAYER M4 ;
        RECT  86.316 65.136 86.4 65.16 ;
    END
  END chn_r[327]
  PIN chn_r[328]
    DIRECTION INPUT ;
    USE SIGNAL ;
    PORT
      LAYER M4 ;
        RECT  86.316 65.232 86.4 65.256 ;
    END
  END chn_r[328]
  PIN chn_r[329]
    DIRECTION INPUT ;
    USE SIGNAL ;
    PORT
      LAYER M4 ;
        RECT  86.316 65.328 86.4 65.352 ;
    END
  END chn_r[329]
  PIN chn_r[32]
    DIRECTION INPUT ;
    USE SIGNAL ;
    PORT
      LAYER M4 ;
        RECT  86.316 22.992 86.4 23.016 ;
    END
  END chn_r[32]
  PIN chn_r[330]
    DIRECTION INPUT ;
    USE SIGNAL ;
    PORT
      LAYER M4 ;
        RECT  86.316 65.424 86.4 65.448 ;
    END
  END chn_r[330]
  PIN chn_r[331]
    DIRECTION INPUT ;
    USE SIGNAL ;
    PORT
      LAYER M4 ;
        RECT  86.316 65.52 86.4 65.544 ;
    END
  END chn_r[331]
  PIN chn_r[332]
    DIRECTION INPUT ;
    USE SIGNAL ;
    PORT
      LAYER M4 ;
        RECT  86.316 65.616 86.4 65.64 ;
    END
  END chn_r[332]
  PIN chn_r[333]
    DIRECTION INPUT ;
    USE SIGNAL ;
    PORT
      LAYER M4 ;
        RECT  86.316 65.712 86.4 65.736 ;
    END
  END chn_r[333]
  PIN chn_r[334]
    DIRECTION INPUT ;
    USE SIGNAL ;
    PORT
      LAYER M4 ;
        RECT  86.316 65.808 86.4 65.832 ;
    END
  END chn_r[334]
  PIN chn_r[335]
    DIRECTION INPUT ;
    USE SIGNAL ;
    PORT
      LAYER M4 ;
        RECT  86.316 65.904 86.4 65.928 ;
    END
  END chn_r[335]
  PIN chn_r[336]
    DIRECTION INPUT ;
    USE SIGNAL ;
    PORT
      LAYER M4 ;
        RECT  86.316 66 86.4 66.024 ;
    END
  END chn_r[336]
  PIN chn_r[337]
    DIRECTION INPUT ;
    USE SIGNAL ;
    PORT
      LAYER M4 ;
        RECT  86.316 66.096 86.4 66.12 ;
    END
  END chn_r[337]
  PIN chn_r[338]
    DIRECTION INPUT ;
    USE SIGNAL ;
    PORT
      LAYER M4 ;
        RECT  86.316 66.192 86.4 66.216 ;
    END
  END chn_r[338]
  PIN chn_r[339]
    DIRECTION INPUT ;
    USE SIGNAL ;
    PORT
      LAYER M4 ;
        RECT  86.316 66.288 86.4 66.312 ;
    END
  END chn_r[339]
  PIN chn_r[33]
    DIRECTION INPUT ;
    USE SIGNAL ;
    PORT
      LAYER M4 ;
        RECT  86.316 23.088 86.4 23.112 ;
    END
  END chn_r[33]
  PIN chn_r[340]
    DIRECTION INPUT ;
    USE SIGNAL ;
    PORT
      LAYER M4 ;
        RECT  86.316 66.384 86.4 66.408 ;
    END
  END chn_r[340]
  PIN chn_r[341]
    DIRECTION INPUT ;
    USE SIGNAL ;
    PORT
      LAYER M4 ;
        RECT  86.316 66.48 86.4 66.504 ;
    END
  END chn_r[341]
  PIN chn_r[342]
    DIRECTION INPUT ;
    USE SIGNAL ;
    PORT
      LAYER M4 ;
        RECT  86.316 66.576 86.4 66.6 ;
    END
  END chn_r[342]
  PIN chn_r[343]
    DIRECTION INPUT ;
    USE SIGNAL ;
    PORT
      LAYER M4 ;
        RECT  86.316 66.672 86.4 66.696 ;
    END
  END chn_r[343]
  PIN chn_r[344]
    DIRECTION INPUT ;
    USE SIGNAL ;
    PORT
      LAYER M4 ;
        RECT  86.316 66.768 86.4 66.792 ;
    END
  END chn_r[344]
  PIN chn_r[345]
    DIRECTION INPUT ;
    USE SIGNAL ;
    PORT
      LAYER M4 ;
        RECT  86.316 66.864 86.4 66.888 ;
    END
  END chn_r[345]
  PIN chn_r[346]
    DIRECTION INPUT ;
    USE SIGNAL ;
    PORT
      LAYER M4 ;
        RECT  86.316 66.96 86.4 66.984 ;
    END
  END chn_r[346]
  PIN chn_r[347]
    DIRECTION INPUT ;
    USE SIGNAL ;
    PORT
      LAYER M4 ;
        RECT  86.316 67.056 86.4 67.08 ;
    END
  END chn_r[347]
  PIN chn_r[348]
    DIRECTION INPUT ;
    USE SIGNAL ;
    PORT
      LAYER M4 ;
        RECT  86.316 67.152 86.4 67.176 ;
    END
  END chn_r[348]
  PIN chn_r[349]
    DIRECTION INPUT ;
    USE SIGNAL ;
    PORT
      LAYER M4 ;
        RECT  86.316 67.248 86.4 67.272 ;
    END
  END chn_r[349]
  PIN chn_r[34]
    DIRECTION INPUT ;
    USE SIGNAL ;
    PORT
      LAYER M4 ;
        RECT  86.316 23.184 86.4 23.208 ;
    END
  END chn_r[34]
  PIN chn_r[350]
    DIRECTION INPUT ;
    USE SIGNAL ;
    PORT
      LAYER M4 ;
        RECT  86.316 67.344 86.4 67.368 ;
    END
  END chn_r[350]
  PIN chn_r[351]
    DIRECTION INPUT ;
    USE SIGNAL ;
    PORT
      LAYER M4 ;
        RECT  86.316 67.44 86.4 67.464 ;
    END
  END chn_r[351]
  PIN chn_r[352]
    DIRECTION INPUT ;
    USE SIGNAL ;
    PORT
      LAYER M4 ;
        RECT  86.316 19.92 86.4 19.944 ;
    END
  END chn_r[352]
  PIN chn_r[353]
    DIRECTION INPUT ;
    USE SIGNAL ;
    PORT
      LAYER M4 ;
        RECT  86.316 20.016 86.4 20.04 ;
    END
  END chn_r[353]
  PIN chn_r[354]
    DIRECTION INPUT ;
    USE SIGNAL ;
    PORT
      LAYER M4 ;
        RECT  86.316 20.112 86.4 20.136 ;
    END
  END chn_r[354]
  PIN chn_r[355]
    DIRECTION INPUT ;
    USE SIGNAL ;
    PORT
      LAYER M4 ;
        RECT  86.316 20.208 86.4 20.232 ;
    END
  END chn_r[355]
  PIN chn_r[356]
    DIRECTION INPUT ;
    USE SIGNAL ;
    PORT
      LAYER M4 ;
        RECT  86.316 20.304 86.4 20.328 ;
    END
  END chn_r[356]
  PIN chn_r[357]
    DIRECTION INPUT ;
    USE SIGNAL ;
    PORT
      LAYER M4 ;
        RECT  86.316 20.4 86.4 20.424 ;
    END
  END chn_r[357]
  PIN chn_r[358]
    DIRECTION INPUT ;
    USE SIGNAL ;
    PORT
      LAYER M4 ;
        RECT  86.316 20.496 86.4 20.52 ;
    END
  END chn_r[358]
  PIN chn_r[359]
    DIRECTION INPUT ;
    USE SIGNAL ;
    PORT
      LAYER M4 ;
        RECT  86.316 20.592 86.4 20.616 ;
    END
  END chn_r[359]
  PIN chn_r[35]
    DIRECTION INPUT ;
    USE SIGNAL ;
    PORT
      LAYER M4 ;
        RECT  86.316 23.28 86.4 23.304 ;
    END
  END chn_r[35]
  PIN chn_r[360]
    DIRECTION INPUT ;
    USE SIGNAL ;
    PORT
      LAYER M4 ;
        RECT  86.316 20.688 86.4 20.712 ;
    END
  END chn_r[360]
  PIN chn_r[361]
    DIRECTION INPUT ;
    USE SIGNAL ;
    PORT
      LAYER M4 ;
        RECT  86.316 20.784 86.4 20.808 ;
    END
  END chn_r[361]
  PIN chn_r[362]
    DIRECTION INPUT ;
    USE SIGNAL ;
    PORT
      LAYER M4 ;
        RECT  86.316 20.88 86.4 20.904 ;
    END
  END chn_r[362]
  PIN chn_r[363]
    DIRECTION INPUT ;
    USE SIGNAL ;
    PORT
      LAYER M4 ;
        RECT  86.316 20.976 86.4 21 ;
    END
  END chn_r[363]
  PIN chn_r[364]
    DIRECTION INPUT ;
    USE SIGNAL ;
    PORT
      LAYER M4 ;
        RECT  86.316 21.072 86.4 21.096 ;
    END
  END chn_r[364]
  PIN chn_r[365]
    DIRECTION INPUT ;
    USE SIGNAL ;
    PORT
      LAYER M4 ;
        RECT  86.316 21.168 86.4 21.192 ;
    END
  END chn_r[365]
  PIN chn_r[366]
    DIRECTION INPUT ;
    USE SIGNAL ;
    PORT
      LAYER M4 ;
        RECT  86.316 21.264 86.4 21.288 ;
    END
  END chn_r[366]
  PIN chn_r[367]
    DIRECTION INPUT ;
    USE SIGNAL ;
    PORT
      LAYER M4 ;
        RECT  86.316 21.36 86.4 21.384 ;
    END
  END chn_r[367]
  PIN chn_r[368]
    DIRECTION INPUT ;
    USE SIGNAL ;
    PORT
      LAYER M4 ;
        RECT  86.316 21.456 86.4 21.48 ;
    END
  END chn_r[368]
  PIN chn_r[369]
    DIRECTION INPUT ;
    USE SIGNAL ;
    PORT
      LAYER M4 ;
        RECT  86.316 21.552 86.4 21.576 ;
    END
  END chn_r[369]
  PIN chn_r[36]
    DIRECTION INPUT ;
    USE SIGNAL ;
    PORT
      LAYER M4 ;
        RECT  86.316 23.376 86.4 23.4 ;
    END
  END chn_r[36]
  PIN chn_r[370]
    DIRECTION INPUT ;
    USE SIGNAL ;
    PORT
      LAYER M4 ;
        RECT  86.316 21.648 86.4 21.672 ;
    END
  END chn_r[370]
  PIN chn_r[371]
    DIRECTION INPUT ;
    USE SIGNAL ;
    PORT
      LAYER M4 ;
        RECT  86.316 21.744 86.4 21.768 ;
    END
  END chn_r[371]
  PIN chn_r[372]
    DIRECTION INPUT ;
    USE SIGNAL ;
    PORT
      LAYER M4 ;
        RECT  86.316 21.84 86.4 21.864 ;
    END
  END chn_r[372]
  PIN chn_r[373]
    DIRECTION INPUT ;
    USE SIGNAL ;
    PORT
      LAYER M4 ;
        RECT  86.316 21.936 86.4 21.96 ;
    END
  END chn_r[373]
  PIN chn_r[374]
    DIRECTION INPUT ;
    USE SIGNAL ;
    PORT
      LAYER M4 ;
        RECT  86.316 22.032 86.4 22.056 ;
    END
  END chn_r[374]
  PIN chn_r[375]
    DIRECTION INPUT ;
    USE SIGNAL ;
    PORT
      LAYER M4 ;
        RECT  86.316 22.128 86.4 22.152 ;
    END
  END chn_r[375]
  PIN chn_r[376]
    DIRECTION INPUT ;
    USE SIGNAL ;
    PORT
      LAYER M4 ;
        RECT  86.316 22.224 86.4 22.248 ;
    END
  END chn_r[376]
  PIN chn_r[377]
    DIRECTION INPUT ;
    USE SIGNAL ;
    PORT
      LAYER M4 ;
        RECT  86.316 22.32 86.4 22.344 ;
    END
  END chn_r[377]
  PIN chn_r[378]
    DIRECTION INPUT ;
    USE SIGNAL ;
    PORT
      LAYER M4 ;
        RECT  86.316 22.416 86.4 22.44 ;
    END
  END chn_r[378]
  PIN chn_r[379]
    DIRECTION INPUT ;
    USE SIGNAL ;
    PORT
      LAYER M4 ;
        RECT  86.316 22.512 86.4 22.536 ;
    END
  END chn_r[379]
  PIN chn_r[37]
    DIRECTION INPUT ;
    USE SIGNAL ;
    PORT
      LAYER M4 ;
        RECT  86.316 23.472 86.4 23.496 ;
    END
  END chn_r[37]
  PIN chn_r[380]
    DIRECTION INPUT ;
    USE SIGNAL ;
    PORT
      LAYER M4 ;
        RECT  86.316 22.608 86.4 22.632 ;
    END
  END chn_r[380]
  PIN chn_r[381]
    DIRECTION INPUT ;
    USE SIGNAL ;
    PORT
      LAYER M4 ;
        RECT  86.316 22.704 86.4 22.728 ;
    END
  END chn_r[381]
  PIN chn_r[382]
    DIRECTION INPUT ;
    USE SIGNAL ;
    PORT
      LAYER M4 ;
        RECT  86.316 22.8 86.4 22.824 ;
    END
  END chn_r[382]
  PIN chn_r[383]
    DIRECTION INPUT ;
    USE SIGNAL ;
    PORT
      LAYER M4 ;
        RECT  86.316 22.896 86.4 22.92 ;
    END
  END chn_r[383]
  PIN chn_r[384]
    DIRECTION INPUT ;
    USE SIGNAL ;
    PORT
      LAYER M4 ;
        RECT  86.316 32.208 86.4 32.232 ;
    END
  END chn_r[384]
  PIN chn_r[385]
    DIRECTION INPUT ;
    USE SIGNAL ;
    PORT
      LAYER M4 ;
        RECT  86.316 32.304 86.4 32.328 ;
    END
  END chn_r[385]
  PIN chn_r[386]
    DIRECTION INPUT ;
    USE SIGNAL ;
    PORT
      LAYER M4 ;
        RECT  86.316 32.4 86.4 32.424 ;
    END
  END chn_r[386]
  PIN chn_r[387]
    DIRECTION INPUT ;
    USE SIGNAL ;
    PORT
      LAYER M4 ;
        RECT  86.316 32.496 86.4 32.52 ;
    END
  END chn_r[387]
  PIN chn_r[388]
    DIRECTION INPUT ;
    USE SIGNAL ;
    PORT
      LAYER M4 ;
        RECT  86.316 32.592 86.4 32.616 ;
    END
  END chn_r[388]
  PIN chn_r[389]
    DIRECTION INPUT ;
    USE SIGNAL ;
    PORT
      LAYER M4 ;
        RECT  86.316 32.688 86.4 32.712 ;
    END
  END chn_r[389]
  PIN chn_r[38]
    DIRECTION INPUT ;
    USE SIGNAL ;
    PORT
      LAYER M4 ;
        RECT  86.316 23.568 86.4 23.592 ;
    END
  END chn_r[38]
  PIN chn_r[390]
    DIRECTION INPUT ;
    USE SIGNAL ;
    PORT
      LAYER M4 ;
        RECT  86.316 32.784 86.4 32.808 ;
    END
  END chn_r[390]
  PIN chn_r[391]
    DIRECTION INPUT ;
    USE SIGNAL ;
    PORT
      LAYER M4 ;
        RECT  86.316 32.88 86.4 32.904 ;
    END
  END chn_r[391]
  PIN chn_r[392]
    DIRECTION INPUT ;
    USE SIGNAL ;
    PORT
      LAYER M4 ;
        RECT  86.316 32.976 86.4 33 ;
    END
  END chn_r[392]
  PIN chn_r[393]
    DIRECTION INPUT ;
    USE SIGNAL ;
    PORT
      LAYER M4 ;
        RECT  86.316 33.072 86.4 33.096 ;
    END
  END chn_r[393]
  PIN chn_r[394]
    DIRECTION INPUT ;
    USE SIGNAL ;
    PORT
      LAYER M4 ;
        RECT  86.316 33.168 86.4 33.192 ;
    END
  END chn_r[394]
  PIN chn_r[395]
    DIRECTION INPUT ;
    USE SIGNAL ;
    PORT
      LAYER M4 ;
        RECT  86.316 33.264 86.4 33.288 ;
    END
  END chn_r[395]
  PIN chn_r[396]
    DIRECTION INPUT ;
    USE SIGNAL ;
    PORT
      LAYER M4 ;
        RECT  86.316 33.36 86.4 33.384 ;
    END
  END chn_r[396]
  PIN chn_r[397]
    DIRECTION INPUT ;
    USE SIGNAL ;
    PORT
      LAYER M4 ;
        RECT  86.316 33.456 86.4 33.48 ;
    END
  END chn_r[397]
  PIN chn_r[398]
    DIRECTION INPUT ;
    USE SIGNAL ;
    PORT
      LAYER M4 ;
        RECT  86.316 33.552 86.4 33.576 ;
    END
  END chn_r[398]
  PIN chn_r[399]
    DIRECTION INPUT ;
    USE SIGNAL ;
    PORT
      LAYER M4 ;
        RECT  86.316 33.648 86.4 33.672 ;
    END
  END chn_r[399]
  PIN chn_r[39]
    DIRECTION INPUT ;
    USE SIGNAL ;
    PORT
      LAYER M4 ;
        RECT  86.316 23.664 86.4 23.688 ;
    END
  END chn_r[39]
  PIN chn_r[3]
    DIRECTION INPUT ;
    USE SIGNAL ;
    PORT
      LAYER M4 ;
        RECT  86.316 35.568 86.4 35.592 ;
    END
  END chn_r[3]
  PIN chn_r[400]
    DIRECTION INPUT ;
    USE SIGNAL ;
    PORT
      LAYER M4 ;
        RECT  86.316 33.744 86.4 33.768 ;
    END
  END chn_r[400]
  PIN chn_r[401]
    DIRECTION INPUT ;
    USE SIGNAL ;
    PORT
      LAYER M4 ;
        RECT  86.316 33.84 86.4 33.864 ;
    END
  END chn_r[401]
  PIN chn_r[402]
    DIRECTION INPUT ;
    USE SIGNAL ;
    PORT
      LAYER M4 ;
        RECT  86.316 33.936 86.4 33.96 ;
    END
  END chn_r[402]
  PIN chn_r[403]
    DIRECTION INPUT ;
    USE SIGNAL ;
    PORT
      LAYER M4 ;
        RECT  86.316 34.032 86.4 34.056 ;
    END
  END chn_r[403]
  PIN chn_r[404]
    DIRECTION INPUT ;
    USE SIGNAL ;
    PORT
      LAYER M4 ;
        RECT  86.316 34.128 86.4 34.152 ;
    END
  END chn_r[404]
  PIN chn_r[405]
    DIRECTION INPUT ;
    USE SIGNAL ;
    PORT
      LAYER M4 ;
        RECT  86.316 34.224 86.4 34.248 ;
    END
  END chn_r[405]
  PIN chn_r[406]
    DIRECTION INPUT ;
    USE SIGNAL ;
    PORT
      LAYER M4 ;
        RECT  86.316 34.32 86.4 34.344 ;
    END
  END chn_r[406]
  PIN chn_r[407]
    DIRECTION INPUT ;
    USE SIGNAL ;
    PORT
      LAYER M4 ;
        RECT  86.316 34.416 86.4 34.44 ;
    END
  END chn_r[407]
  PIN chn_r[408]
    DIRECTION INPUT ;
    USE SIGNAL ;
    PORT
      LAYER M4 ;
        RECT  86.316 34.512 86.4 34.536 ;
    END
  END chn_r[408]
  PIN chn_r[409]
    DIRECTION INPUT ;
    USE SIGNAL ;
    PORT
      LAYER M4 ;
        RECT  86.316 34.608 86.4 34.632 ;
    END
  END chn_r[409]
  PIN chn_r[40]
    DIRECTION INPUT ;
    USE SIGNAL ;
    PORT
      LAYER M4 ;
        RECT  86.316 23.76 86.4 23.784 ;
    END
  END chn_r[40]
  PIN chn_r[410]
    DIRECTION INPUT ;
    USE SIGNAL ;
    PORT
      LAYER M4 ;
        RECT  86.316 34.704 86.4 34.728 ;
    END
  END chn_r[410]
  PIN chn_r[411]
    DIRECTION INPUT ;
    USE SIGNAL ;
    PORT
      LAYER M4 ;
        RECT  86.316 34.8 86.4 34.824 ;
    END
  END chn_r[411]
  PIN chn_r[412]
    DIRECTION INPUT ;
    USE SIGNAL ;
    PORT
      LAYER M4 ;
        RECT  86.316 34.896 86.4 34.92 ;
    END
  END chn_r[412]
  PIN chn_r[413]
    DIRECTION INPUT ;
    USE SIGNAL ;
    PORT
      LAYER M4 ;
        RECT  86.316 34.992 86.4 35.016 ;
    END
  END chn_r[413]
  PIN chn_r[414]
    DIRECTION INPUT ;
    USE SIGNAL ;
    PORT
      LAYER M4 ;
        RECT  86.316 35.088 86.4 35.112 ;
    END
  END chn_r[414]
  PIN chn_r[415]
    DIRECTION INPUT ;
    USE SIGNAL ;
    PORT
      LAYER M4 ;
        RECT  86.316 35.184 86.4 35.208 ;
    END
  END chn_r[415]
  PIN chn_r[416]
    DIRECTION INPUT ;
    USE SIGNAL ;
    PORT
      LAYER M4 ;
        RECT  86.316 16.08 86.4 16.104 ;
    END
  END chn_r[416]
  PIN chn_r[417]
    DIRECTION INPUT ;
    USE SIGNAL ;
    PORT
      LAYER M4 ;
        RECT  86.316 16.176 86.4 16.2 ;
    END
  END chn_r[417]
  PIN chn_r[418]
    DIRECTION INPUT ;
    USE SIGNAL ;
    PORT
      LAYER M4 ;
        RECT  86.316 16.272 86.4 16.296 ;
    END
  END chn_r[418]
  PIN chn_r[419]
    DIRECTION INPUT ;
    USE SIGNAL ;
    PORT
      LAYER M4 ;
        RECT  86.316 16.368 86.4 16.392 ;
    END
  END chn_r[419]
  PIN chn_r[41]
    DIRECTION INPUT ;
    USE SIGNAL ;
    PORT
      LAYER M4 ;
        RECT  86.316 23.856 86.4 23.88 ;
    END
  END chn_r[41]
  PIN chn_r[420]
    DIRECTION INPUT ;
    USE SIGNAL ;
    PORT
      LAYER M4 ;
        RECT  86.316 16.464 86.4 16.488 ;
    END
  END chn_r[420]
  PIN chn_r[421]
    DIRECTION INPUT ;
    USE SIGNAL ;
    PORT
      LAYER M4 ;
        RECT  86.316 16.56 86.4 16.584 ;
    END
  END chn_r[421]
  PIN chn_r[422]
    DIRECTION INPUT ;
    USE SIGNAL ;
    PORT
      LAYER M4 ;
        RECT  86.316 16.656 86.4 16.68 ;
    END
  END chn_r[422]
  PIN chn_r[423]
    DIRECTION INPUT ;
    USE SIGNAL ;
    PORT
      LAYER M4 ;
        RECT  86.316 16.752 86.4 16.776 ;
    END
  END chn_r[423]
  PIN chn_r[424]
    DIRECTION INPUT ;
    USE SIGNAL ;
    PORT
      LAYER M4 ;
        RECT  86.316 16.848 86.4 16.872 ;
    END
  END chn_r[424]
  PIN chn_r[425]
    DIRECTION INPUT ;
    USE SIGNAL ;
    PORT
      LAYER M4 ;
        RECT  86.316 16.944 86.4 16.968 ;
    END
  END chn_r[425]
  PIN chn_r[426]
    DIRECTION INPUT ;
    USE SIGNAL ;
    PORT
      LAYER M4 ;
        RECT  86.316 17.04 86.4 17.064 ;
    END
  END chn_r[426]
  PIN chn_r[427]
    DIRECTION INPUT ;
    USE SIGNAL ;
    PORT
      LAYER M4 ;
        RECT  86.316 17.136 86.4 17.16 ;
    END
  END chn_r[427]
  PIN chn_r[428]
    DIRECTION INPUT ;
    USE SIGNAL ;
    PORT
      LAYER M4 ;
        RECT  86.316 17.232 86.4 17.256 ;
    END
  END chn_r[428]
  PIN chn_r[429]
    DIRECTION INPUT ;
    USE SIGNAL ;
    PORT
      LAYER M4 ;
        RECT  86.316 17.328 86.4 17.352 ;
    END
  END chn_r[429]
  PIN chn_r[42]
    DIRECTION INPUT ;
    USE SIGNAL ;
    PORT
      LAYER M4 ;
        RECT  86.316 23.952 86.4 23.976 ;
    END
  END chn_r[42]
  PIN chn_r[430]
    DIRECTION INPUT ;
    USE SIGNAL ;
    PORT
      LAYER M4 ;
        RECT  86.316 17.424 86.4 17.448 ;
    END
  END chn_r[430]
  PIN chn_r[431]
    DIRECTION INPUT ;
    USE SIGNAL ;
    PORT
      LAYER M4 ;
        RECT  86.316 17.52 86.4 17.544 ;
    END
  END chn_r[431]
  PIN chn_r[432]
    DIRECTION INPUT ;
    USE SIGNAL ;
    PORT
      LAYER M4 ;
        RECT  86.316 17.616 86.4 17.64 ;
    END
  END chn_r[432]
  PIN chn_r[433]
    DIRECTION INPUT ;
    USE SIGNAL ;
    PORT
      LAYER M4 ;
        RECT  86.316 17.712 86.4 17.736 ;
    END
  END chn_r[433]
  PIN chn_r[434]
    DIRECTION INPUT ;
    USE SIGNAL ;
    PORT
      LAYER M4 ;
        RECT  86.316 17.808 86.4 17.832 ;
    END
  END chn_r[434]
  PIN chn_r[435]
    DIRECTION INPUT ;
    USE SIGNAL ;
    PORT
      LAYER M4 ;
        RECT  86.316 17.904 86.4 17.928 ;
    END
  END chn_r[435]
  PIN chn_r[436]
    DIRECTION INPUT ;
    USE SIGNAL ;
    PORT
      LAYER M4 ;
        RECT  86.316 18 86.4 18.024 ;
    END
  END chn_r[436]
  PIN chn_r[437]
    DIRECTION INPUT ;
    USE SIGNAL ;
    PORT
      LAYER M4 ;
        RECT  86.316 18.096 86.4 18.12 ;
    END
  END chn_r[437]
  PIN chn_r[438]
    DIRECTION INPUT ;
    USE SIGNAL ;
    PORT
      LAYER M4 ;
        RECT  86.316 18.192 86.4 18.216 ;
    END
  END chn_r[438]
  PIN chn_r[439]
    DIRECTION INPUT ;
    USE SIGNAL ;
    PORT
      LAYER M4 ;
        RECT  86.316 18.288 86.4 18.312 ;
    END
  END chn_r[439]
  PIN chn_r[43]
    DIRECTION INPUT ;
    USE SIGNAL ;
    PORT
      LAYER M4 ;
        RECT  86.316 24.048 86.4 24.072 ;
    END
  END chn_r[43]
  PIN chn_r[440]
    DIRECTION INPUT ;
    USE SIGNAL ;
    PORT
      LAYER M4 ;
        RECT  86.316 18.384 86.4 18.408 ;
    END
  END chn_r[440]
  PIN chn_r[441]
    DIRECTION INPUT ;
    USE SIGNAL ;
    PORT
      LAYER M4 ;
        RECT  86.316 18.48 86.4 18.504 ;
    END
  END chn_r[441]
  PIN chn_r[442]
    DIRECTION INPUT ;
    USE SIGNAL ;
    PORT
      LAYER M4 ;
        RECT  86.316 18.576 86.4 18.6 ;
    END
  END chn_r[442]
  PIN chn_r[443]
    DIRECTION INPUT ;
    USE SIGNAL ;
    PORT
      LAYER M4 ;
        RECT  86.316 18.672 86.4 18.696 ;
    END
  END chn_r[443]
  PIN chn_r[444]
    DIRECTION INPUT ;
    USE SIGNAL ;
    PORT
      LAYER M4 ;
        RECT  86.316 18.768 86.4 18.792 ;
    END
  END chn_r[444]
  PIN chn_r[445]
    DIRECTION INPUT ;
    USE SIGNAL ;
    PORT
      LAYER M4 ;
        RECT  86.316 18.864 86.4 18.888 ;
    END
  END chn_r[445]
  PIN chn_r[446]
    DIRECTION INPUT ;
    USE SIGNAL ;
    PORT
      LAYER M4 ;
        RECT  86.316 18.96 86.4 18.984 ;
    END
  END chn_r[446]
  PIN chn_r[447]
    DIRECTION INPUT ;
    USE SIGNAL ;
    PORT
      LAYER M4 ;
        RECT  86.316 19.056 86.4 19.08 ;
    END
  END chn_r[447]
  PIN chn_r[448]
    DIRECTION INPUT ;
    USE SIGNAL ;
    PORT
      LAYER M4 ;
        RECT  86.316 58.32 86.4 58.344 ;
    END
  END chn_r[448]
  PIN chn_r[449]
    DIRECTION INPUT ;
    USE SIGNAL ;
    PORT
      LAYER M4 ;
        RECT  86.316 58.416 86.4 58.44 ;
    END
  END chn_r[449]
  PIN chn_r[44]
    DIRECTION INPUT ;
    USE SIGNAL ;
    PORT
      LAYER M4 ;
        RECT  86.316 24.144 86.4 24.168 ;
    END
  END chn_r[44]
  PIN chn_r[450]
    DIRECTION INPUT ;
    USE SIGNAL ;
    PORT
      LAYER M4 ;
        RECT  86.316 58.512 86.4 58.536 ;
    END
  END chn_r[450]
  PIN chn_r[451]
    DIRECTION INPUT ;
    USE SIGNAL ;
    PORT
      LAYER M4 ;
        RECT  86.316 58.608 86.4 58.632 ;
    END
  END chn_r[451]
  PIN chn_r[452]
    DIRECTION INPUT ;
    USE SIGNAL ;
    PORT
      LAYER M4 ;
        RECT  86.316 58.704 86.4 58.728 ;
    END
  END chn_r[452]
  PIN chn_r[453]
    DIRECTION INPUT ;
    USE SIGNAL ;
    PORT
      LAYER M4 ;
        RECT  86.316 58.8 86.4 58.824 ;
    END
  END chn_r[453]
  PIN chn_r[454]
    DIRECTION INPUT ;
    USE SIGNAL ;
    PORT
      LAYER M4 ;
        RECT  86.316 58.896 86.4 58.92 ;
    END
  END chn_r[454]
  PIN chn_r[455]
    DIRECTION INPUT ;
    USE SIGNAL ;
    PORT
      LAYER M4 ;
        RECT  86.316 58.992 86.4 59.016 ;
    END
  END chn_r[455]
  PIN chn_r[456]
    DIRECTION INPUT ;
    USE SIGNAL ;
    PORT
      LAYER M4 ;
        RECT  86.316 59.088 86.4 59.112 ;
    END
  END chn_r[456]
  PIN chn_r[457]
    DIRECTION INPUT ;
    USE SIGNAL ;
    PORT
      LAYER M4 ;
        RECT  86.316 59.184 86.4 59.208 ;
    END
  END chn_r[457]
  PIN chn_r[458]
    DIRECTION INPUT ;
    USE SIGNAL ;
    PORT
      LAYER M4 ;
        RECT  86.316 59.28 86.4 59.304 ;
    END
  END chn_r[458]
  PIN chn_r[459]
    DIRECTION INPUT ;
    USE SIGNAL ;
    PORT
      LAYER M4 ;
        RECT  86.316 59.376 86.4 59.4 ;
    END
  END chn_r[459]
  PIN chn_r[45]
    DIRECTION INPUT ;
    USE SIGNAL ;
    PORT
      LAYER M4 ;
        RECT  86.316 24.24 86.4 24.264 ;
    END
  END chn_r[45]
  PIN chn_r[460]
    DIRECTION INPUT ;
    USE SIGNAL ;
    PORT
      LAYER M4 ;
        RECT  86.316 59.472 86.4 59.496 ;
    END
  END chn_r[460]
  PIN chn_r[461]
    DIRECTION INPUT ;
    USE SIGNAL ;
    PORT
      LAYER M4 ;
        RECT  86.316 59.568 86.4 59.592 ;
    END
  END chn_r[461]
  PIN chn_r[462]
    DIRECTION INPUT ;
    USE SIGNAL ;
    PORT
      LAYER M4 ;
        RECT  86.316 59.664 86.4 59.688 ;
    END
  END chn_r[462]
  PIN chn_r[463]
    DIRECTION INPUT ;
    USE SIGNAL ;
    PORT
      LAYER M4 ;
        RECT  86.316 59.76 86.4 59.784 ;
    END
  END chn_r[463]
  PIN chn_r[464]
    DIRECTION INPUT ;
    USE SIGNAL ;
    PORT
      LAYER M4 ;
        RECT  86.316 59.856 86.4 59.88 ;
    END
  END chn_r[464]
  PIN chn_r[465]
    DIRECTION INPUT ;
    USE SIGNAL ;
    PORT
      LAYER M4 ;
        RECT  86.316 59.952 86.4 59.976 ;
    END
  END chn_r[465]
  PIN chn_r[466]
    DIRECTION INPUT ;
    USE SIGNAL ;
    PORT
      LAYER M4 ;
        RECT  86.316 60.048 86.4 60.072 ;
    END
  END chn_r[466]
  PIN chn_r[467]
    DIRECTION INPUT ;
    USE SIGNAL ;
    PORT
      LAYER M4 ;
        RECT  86.316 60.144 86.4 60.168 ;
    END
  END chn_r[467]
  PIN chn_r[468]
    DIRECTION INPUT ;
    USE SIGNAL ;
    PORT
      LAYER M4 ;
        RECT  86.316 60.24 86.4 60.264 ;
    END
  END chn_r[468]
  PIN chn_r[469]
    DIRECTION INPUT ;
    USE SIGNAL ;
    PORT
      LAYER M4 ;
        RECT  86.316 60.336 86.4 60.36 ;
    END
  END chn_r[469]
  PIN chn_r[46]
    DIRECTION INPUT ;
    USE SIGNAL ;
    PORT
      LAYER M4 ;
        RECT  86.316 24.336 86.4 24.36 ;
    END
  END chn_r[46]
  PIN chn_r[470]
    DIRECTION INPUT ;
    USE SIGNAL ;
    PORT
      LAYER M4 ;
        RECT  86.316 60.432 86.4 60.456 ;
    END
  END chn_r[470]
  PIN chn_r[471]
    DIRECTION INPUT ;
    USE SIGNAL ;
    PORT
      LAYER M4 ;
        RECT  86.316 60.528 86.4 60.552 ;
    END
  END chn_r[471]
  PIN chn_r[472]
    DIRECTION INPUT ;
    USE SIGNAL ;
    PORT
      LAYER M4 ;
        RECT  86.316 60.624 86.4 60.648 ;
    END
  END chn_r[472]
  PIN chn_r[473]
    DIRECTION INPUT ;
    USE SIGNAL ;
    PORT
      LAYER M4 ;
        RECT  86.316 60.72 86.4 60.744 ;
    END
  END chn_r[473]
  PIN chn_r[474]
    DIRECTION INPUT ;
    USE SIGNAL ;
    PORT
      LAYER M4 ;
        RECT  86.316 60.816 86.4 60.84 ;
    END
  END chn_r[474]
  PIN chn_r[475]
    DIRECTION INPUT ;
    USE SIGNAL ;
    PORT
      LAYER M4 ;
        RECT  86.316 60.912 86.4 60.936 ;
    END
  END chn_r[475]
  PIN chn_r[476]
    DIRECTION INPUT ;
    USE SIGNAL ;
    PORT
      LAYER M4 ;
        RECT  86.316 61.008 86.4 61.032 ;
    END
  END chn_r[476]
  PIN chn_r[477]
    DIRECTION INPUT ;
    USE SIGNAL ;
    PORT
      LAYER M4 ;
        RECT  86.316 61.104 86.4 61.128 ;
    END
  END chn_r[477]
  PIN chn_r[478]
    DIRECTION INPUT ;
    USE SIGNAL ;
    PORT
      LAYER M4 ;
        RECT  86.316 61.2 86.4 61.224 ;
    END
  END chn_r[478]
  PIN chn_r[479]
    DIRECTION INPUT ;
    USE SIGNAL ;
    PORT
      LAYER M4 ;
        RECT  86.316 61.296 86.4 61.32 ;
    END
  END chn_r[479]
  PIN chn_r[47]
    DIRECTION INPUT ;
    USE SIGNAL ;
    PORT
      LAYER M4 ;
        RECT  86.316 24.432 86.4 24.456 ;
    END
  END chn_r[47]
  PIN chn_r[480]
    DIRECTION INPUT ;
    USE SIGNAL ;
    PORT
      LAYER M4 ;
        RECT  86.316 61.392 86.4 61.416 ;
    END
  END chn_r[480]
  PIN chn_r[481]
    DIRECTION INPUT ;
    USE SIGNAL ;
    PORT
      LAYER M4 ;
        RECT  86.316 61.488 86.4 61.512 ;
    END
  END chn_r[481]
  PIN chn_r[482]
    DIRECTION INPUT ;
    USE SIGNAL ;
    PORT
      LAYER M4 ;
        RECT  86.316 61.584 86.4 61.608 ;
    END
  END chn_r[482]
  PIN chn_r[483]
    DIRECTION INPUT ;
    USE SIGNAL ;
    PORT
      LAYER M4 ;
        RECT  86.316 61.68 86.4 61.704 ;
    END
  END chn_r[483]
  PIN chn_r[484]
    DIRECTION INPUT ;
    USE SIGNAL ;
    PORT
      LAYER M4 ;
        RECT  86.316 61.776 86.4 61.8 ;
    END
  END chn_r[484]
  PIN chn_r[485]
    DIRECTION INPUT ;
    USE SIGNAL ;
    PORT
      LAYER M4 ;
        RECT  86.316 61.872 86.4 61.896 ;
    END
  END chn_r[485]
  PIN chn_r[486]
    DIRECTION INPUT ;
    USE SIGNAL ;
    PORT
      LAYER M4 ;
        RECT  86.316 61.968 86.4 61.992 ;
    END
  END chn_r[486]
  PIN chn_r[487]
    DIRECTION INPUT ;
    USE SIGNAL ;
    PORT
      LAYER M4 ;
        RECT  86.316 62.064 86.4 62.088 ;
    END
  END chn_r[487]
  PIN chn_r[488]
    DIRECTION INPUT ;
    USE SIGNAL ;
    PORT
      LAYER M4 ;
        RECT  86.316 62.16 86.4 62.184 ;
    END
  END chn_r[488]
  PIN chn_r[489]
    DIRECTION INPUT ;
    USE SIGNAL ;
    PORT
      LAYER M4 ;
        RECT  86.316 62.256 86.4 62.28 ;
    END
  END chn_r[489]
  PIN chn_r[48]
    DIRECTION INPUT ;
    USE SIGNAL ;
    PORT
      LAYER M4 ;
        RECT  86.316 24.528 86.4 24.552 ;
    END
  END chn_r[48]
  PIN chn_r[490]
    DIRECTION INPUT ;
    USE SIGNAL ;
    PORT
      LAYER M4 ;
        RECT  86.316 62.352 86.4 62.376 ;
    END
  END chn_r[490]
  PIN chn_r[491]
    DIRECTION INPUT ;
    USE SIGNAL ;
    PORT
      LAYER M4 ;
        RECT  86.316 62.448 86.4 62.472 ;
    END
  END chn_r[491]
  PIN chn_r[492]
    DIRECTION INPUT ;
    USE SIGNAL ;
    PORT
      LAYER M4 ;
        RECT  86.316 62.544 86.4 62.568 ;
    END
  END chn_r[492]
  PIN chn_r[493]
    DIRECTION INPUT ;
    USE SIGNAL ;
    PORT
      LAYER M4 ;
        RECT  86.316 62.64 86.4 62.664 ;
    END
  END chn_r[493]
  PIN chn_r[494]
    DIRECTION INPUT ;
    USE SIGNAL ;
    PORT
      LAYER M4 ;
        RECT  86.316 62.736 86.4 62.76 ;
    END
  END chn_r[494]
  PIN chn_r[495]
    DIRECTION INPUT ;
    USE SIGNAL ;
    PORT
      LAYER M4 ;
        RECT  86.316 62.832 86.4 62.856 ;
    END
  END chn_r[495]
  PIN chn_r[496]
    DIRECTION INPUT ;
    USE SIGNAL ;
    PORT
      LAYER M4 ;
        RECT  86.316 62.928 86.4 62.952 ;
    END
  END chn_r[496]
  PIN chn_r[497]
    DIRECTION INPUT ;
    USE SIGNAL ;
    PORT
      LAYER M4 ;
        RECT  86.316 63.024 86.4 63.048 ;
    END
  END chn_r[497]
  PIN chn_r[498]
    DIRECTION INPUT ;
    USE SIGNAL ;
    PORT
      LAYER M4 ;
        RECT  86.316 63.12 86.4 63.144 ;
    END
  END chn_r[498]
  PIN chn_r[499]
    DIRECTION INPUT ;
    USE SIGNAL ;
    PORT
      LAYER M4 ;
        RECT  86.316 63.216 86.4 63.24 ;
    END
  END chn_r[499]
  PIN chn_r[49]
    DIRECTION INPUT ;
    USE SIGNAL ;
    PORT
      LAYER M4 ;
        RECT  86.316 24.624 86.4 24.648 ;
    END
  END chn_r[49]
  PIN chn_r[4]
    DIRECTION INPUT ;
    USE SIGNAL ;
    PORT
      LAYER M4 ;
        RECT  86.316 35.664 86.4 35.688 ;
    END
  END chn_r[4]
  PIN chn_r[500]
    DIRECTION INPUT ;
    USE SIGNAL ;
    PORT
      LAYER M4 ;
        RECT  86.316 63.312 86.4 63.336 ;
    END
  END chn_r[500]
  PIN chn_r[501]
    DIRECTION INPUT ;
    USE SIGNAL ;
    PORT
      LAYER M4 ;
        RECT  86.316 63.408 86.4 63.432 ;
    END
  END chn_r[501]
  PIN chn_r[502]
    DIRECTION INPUT ;
    USE SIGNAL ;
    PORT
      LAYER M4 ;
        RECT  86.316 63.504 86.4 63.528 ;
    END
  END chn_r[502]
  PIN chn_r[503]
    DIRECTION INPUT ;
    USE SIGNAL ;
    PORT
      LAYER M4 ;
        RECT  86.316 63.6 86.4 63.624 ;
    END
  END chn_r[503]
  PIN chn_r[504]
    DIRECTION INPUT ;
    USE SIGNAL ;
    PORT
      LAYER M4 ;
        RECT  86.316 63.696 86.4 63.72 ;
    END
  END chn_r[504]
  PIN chn_r[505]
    DIRECTION INPUT ;
    USE SIGNAL ;
    PORT
      LAYER M4 ;
        RECT  86.316 63.792 86.4 63.816 ;
    END
  END chn_r[505]
  PIN chn_r[506]
    DIRECTION INPUT ;
    USE SIGNAL ;
    PORT
      LAYER M4 ;
        RECT  86.316 63.888 86.4 63.912 ;
    END
  END chn_r[506]
  PIN chn_r[507]
    DIRECTION INPUT ;
    USE SIGNAL ;
    PORT
      LAYER M4 ;
        RECT  86.316 63.984 86.4 64.008 ;
    END
  END chn_r[507]
  PIN chn_r[508]
    DIRECTION INPUT ;
    USE SIGNAL ;
    PORT
      LAYER M4 ;
        RECT  86.316 64.08 86.4 64.104 ;
    END
  END chn_r[508]
  PIN chn_r[509]
    DIRECTION INPUT ;
    USE SIGNAL ;
    PORT
      LAYER M4 ;
        RECT  86.316 64.176 86.4 64.2 ;
    END
  END chn_r[509]
  PIN chn_r[50]
    DIRECTION INPUT ;
    USE SIGNAL ;
    PORT
      LAYER M4 ;
        RECT  86.316 24.72 86.4 24.744 ;
    END
  END chn_r[50]
  PIN chn_r[510]
    DIRECTION INPUT ;
    USE SIGNAL ;
    PORT
      LAYER M4 ;
        RECT  86.316 64.272 86.4 64.296 ;
    END
  END chn_r[510]
  PIN chn_r[511]
    DIRECTION INPUT ;
    USE SIGNAL ;
    PORT
      LAYER M4 ;
        RECT  86.316 64.368 86.4 64.392 ;
    END
  END chn_r[511]
  PIN chn_r[512]
    DIRECTION INPUT ;
    USE SIGNAL ;
    PORT
      LAYER M4 ;
        RECT  86.316 67.536 86.4 67.56 ;
    END
  END chn_r[512]
  PIN chn_r[513]
    DIRECTION INPUT ;
    USE SIGNAL ;
    PORT
      LAYER M4 ;
        RECT  86.316 67.632 86.4 67.656 ;
    END
  END chn_r[513]
  PIN chn_r[514]
    DIRECTION INPUT ;
    USE SIGNAL ;
    PORT
      LAYER M4 ;
        RECT  86.316 67.728 86.4 67.752 ;
    END
  END chn_r[514]
  PIN chn_r[515]
    DIRECTION INPUT ;
    USE SIGNAL ;
    PORT
      LAYER M4 ;
        RECT  86.316 67.824 86.4 67.848 ;
    END
  END chn_r[515]
  PIN chn_r[516]
    DIRECTION INPUT ;
    USE SIGNAL ;
    PORT
      LAYER M4 ;
        RECT  86.316 67.92 86.4 67.944 ;
    END
  END chn_r[516]
  PIN chn_r[517]
    DIRECTION INPUT ;
    USE SIGNAL ;
    PORT
      LAYER M4 ;
        RECT  86.316 68.016 86.4 68.04 ;
    END
  END chn_r[517]
  PIN chn_r[518]
    DIRECTION INPUT ;
    USE SIGNAL ;
    PORT
      LAYER M4 ;
        RECT  86.316 68.112 86.4 68.136 ;
    END
  END chn_r[518]
  PIN chn_r[519]
    DIRECTION INPUT ;
    USE SIGNAL ;
    PORT
      LAYER M4 ;
        RECT  86.316 68.208 86.4 68.232 ;
    END
  END chn_r[519]
  PIN chn_r[51]
    DIRECTION INPUT ;
    USE SIGNAL ;
    PORT
      LAYER M4 ;
        RECT  86.316 24.816 86.4 24.84 ;
    END
  END chn_r[51]
  PIN chn_r[520]
    DIRECTION INPUT ;
    USE SIGNAL ;
    PORT
      LAYER M4 ;
        RECT  86.316 68.304 86.4 68.328 ;
    END
  END chn_r[520]
  PIN chn_r[521]
    DIRECTION INPUT ;
    USE SIGNAL ;
    PORT
      LAYER M4 ;
        RECT  86.316 68.4 86.4 68.424 ;
    END
  END chn_r[521]
  PIN chn_r[522]
    DIRECTION INPUT ;
    USE SIGNAL ;
    PORT
      LAYER M4 ;
        RECT  86.316 68.496 86.4 68.52 ;
    END
  END chn_r[522]
  PIN chn_r[523]
    DIRECTION INPUT ;
    USE SIGNAL ;
    PORT
      LAYER M4 ;
        RECT  86.316 68.592 86.4 68.616 ;
    END
  END chn_r[523]
  PIN chn_r[524]
    DIRECTION INPUT ;
    USE SIGNAL ;
    PORT
      LAYER M4 ;
        RECT  86.316 68.688 86.4 68.712 ;
    END
  END chn_r[524]
  PIN chn_r[525]
    DIRECTION INPUT ;
    USE SIGNAL ;
    PORT
      LAYER M4 ;
        RECT  86.316 68.784 86.4 68.808 ;
    END
  END chn_r[525]
  PIN chn_r[526]
    DIRECTION INPUT ;
    USE SIGNAL ;
    PORT
      LAYER M4 ;
        RECT  86.316 68.88 86.4 68.904 ;
    END
  END chn_r[526]
  PIN chn_r[527]
    DIRECTION INPUT ;
    USE SIGNAL ;
    PORT
      LAYER M4 ;
        RECT  86.316 68.976 86.4 69 ;
    END
  END chn_r[527]
  PIN chn_r[528]
    DIRECTION INPUT ;
    USE SIGNAL ;
    PORT
      LAYER M4 ;
        RECT  86.316 69.072 86.4 69.096 ;
    END
  END chn_r[528]
  PIN chn_r[52]
    DIRECTION INPUT ;
    USE SIGNAL ;
    PORT
      LAYER M4 ;
        RECT  86.316 24.912 86.4 24.936 ;
    END
  END chn_r[52]
  PIN chn_r[53]
    DIRECTION INPUT ;
    USE SIGNAL ;
    PORT
      LAYER M4 ;
        RECT  86.316 25.008 86.4 25.032 ;
    END
  END chn_r[53]
  PIN chn_r[54]
    DIRECTION INPUT ;
    USE SIGNAL ;
    PORT
      LAYER M4 ;
        RECT  86.316 25.104 86.4 25.128 ;
    END
  END chn_r[54]
  PIN chn_r[55]
    DIRECTION INPUT ;
    USE SIGNAL ;
    PORT
      LAYER M4 ;
        RECT  86.316 25.2 86.4 25.224 ;
    END
  END chn_r[55]
  PIN chn_r[56]
    DIRECTION INPUT ;
    USE SIGNAL ;
    PORT
      LAYER M4 ;
        RECT  86.316 25.296 86.4 25.32 ;
    END
  END chn_r[56]
  PIN chn_r[57]
    DIRECTION INPUT ;
    USE SIGNAL ;
    PORT
      LAYER M4 ;
        RECT  86.316 25.392 86.4 25.416 ;
    END
  END chn_r[57]
  PIN chn_r[58]
    DIRECTION INPUT ;
    USE SIGNAL ;
    PORT
      LAYER M4 ;
        RECT  86.316 25.488 86.4 25.512 ;
    END
  END chn_r[58]
  PIN chn_r[59]
    DIRECTION INPUT ;
    USE SIGNAL ;
    PORT
      LAYER M4 ;
        RECT  86.316 25.584 86.4 25.608 ;
    END
  END chn_r[59]
  PIN chn_r[5]
    DIRECTION INPUT ;
    USE SIGNAL ;
    PORT
      LAYER M4 ;
        RECT  86.316 35.76 86.4 35.784 ;
    END
  END chn_r[5]
  PIN chn_r[60]
    DIRECTION INPUT ;
    USE SIGNAL ;
    PORT
      LAYER M4 ;
        RECT  86.316 25.68 86.4 25.704 ;
    END
  END chn_r[60]
  PIN chn_r[61]
    DIRECTION INPUT ;
    USE SIGNAL ;
    PORT
      LAYER M4 ;
        RECT  86.316 25.776 86.4 25.8 ;
    END
  END chn_r[61]
  PIN chn_r[62]
    DIRECTION INPUT ;
    USE SIGNAL ;
    PORT
      LAYER M4 ;
        RECT  86.316 25.872 86.4 25.896 ;
    END
  END chn_r[62]
  PIN chn_r[63]
    DIRECTION INPUT ;
    USE SIGNAL ;
    PORT
      LAYER M4 ;
        RECT  86.316 25.968 86.4 25.992 ;
    END
  END chn_r[63]
  PIN chn_r[64]
    DIRECTION INPUT ;
    USE SIGNAL ;
    PORT
      LAYER M4 ;
        RECT  86.316 29.136 86.4 29.16 ;
    END
  END chn_r[64]
  PIN chn_r[65]
    DIRECTION INPUT ;
    USE SIGNAL ;
    PORT
      LAYER M4 ;
        RECT  86.316 29.232 86.4 29.256 ;
    END
  END chn_r[65]
  PIN chn_r[66]
    DIRECTION INPUT ;
    USE SIGNAL ;
    PORT
      LAYER M4 ;
        RECT  86.316 29.328 86.4 29.352 ;
    END
  END chn_r[66]
  PIN chn_r[67]
    DIRECTION INPUT ;
    USE SIGNAL ;
    PORT
      LAYER M4 ;
        RECT  86.316 29.424 86.4 29.448 ;
    END
  END chn_r[67]
  PIN chn_r[68]
    DIRECTION INPUT ;
    USE SIGNAL ;
    PORT
      LAYER M4 ;
        RECT  86.316 29.52 86.4 29.544 ;
    END
  END chn_r[68]
  PIN chn_r[69]
    DIRECTION INPUT ;
    USE SIGNAL ;
    PORT
      LAYER M4 ;
        RECT  86.316 29.616 86.4 29.64 ;
    END
  END chn_r[69]
  PIN chn_r[6]
    DIRECTION INPUT ;
    USE SIGNAL ;
    PORT
      LAYER M4 ;
        RECT  86.316 35.856 86.4 35.88 ;
    END
  END chn_r[6]
  PIN chn_r[70]
    DIRECTION INPUT ;
    USE SIGNAL ;
    PORT
      LAYER M4 ;
        RECT  86.316 29.712 86.4 29.736 ;
    END
  END chn_r[70]
  PIN chn_r[71]
    DIRECTION INPUT ;
    USE SIGNAL ;
    PORT
      LAYER M4 ;
        RECT  86.316 29.808 86.4 29.832 ;
    END
  END chn_r[71]
  PIN chn_r[72]
    DIRECTION INPUT ;
    USE SIGNAL ;
    PORT
      LAYER M4 ;
        RECT  86.316 29.904 86.4 29.928 ;
    END
  END chn_r[72]
  PIN chn_r[73]
    DIRECTION INPUT ;
    USE SIGNAL ;
    PORT
      LAYER M4 ;
        RECT  86.316 30 86.4 30.024 ;
    END
  END chn_r[73]
  PIN chn_r[74]
    DIRECTION INPUT ;
    USE SIGNAL ;
    PORT
      LAYER M4 ;
        RECT  86.316 30.096 86.4 30.12 ;
    END
  END chn_r[74]
  PIN chn_r[75]
    DIRECTION INPUT ;
    USE SIGNAL ;
    PORT
      LAYER M4 ;
        RECT  86.316 30.192 86.4 30.216 ;
    END
  END chn_r[75]
  PIN chn_r[76]
    DIRECTION INPUT ;
    USE SIGNAL ;
    PORT
      LAYER M4 ;
        RECT  86.316 30.288 86.4 30.312 ;
    END
  END chn_r[76]
  PIN chn_r[77]
    DIRECTION INPUT ;
    USE SIGNAL ;
    PORT
      LAYER M4 ;
        RECT  86.316 30.384 86.4 30.408 ;
    END
  END chn_r[77]
  PIN chn_r[78]
    DIRECTION INPUT ;
    USE SIGNAL ;
    PORT
      LAYER M4 ;
        RECT  86.316 30.48 86.4 30.504 ;
    END
  END chn_r[78]
  PIN chn_r[79]
    DIRECTION INPUT ;
    USE SIGNAL ;
    PORT
      LAYER M4 ;
        RECT  86.316 30.576 86.4 30.6 ;
    END
  END chn_r[79]
  PIN chn_r[7]
    DIRECTION INPUT ;
    USE SIGNAL ;
    PORT
      LAYER M4 ;
        RECT  86.316 35.952 86.4 35.976 ;
    END
  END chn_r[7]
  PIN chn_r[80]
    DIRECTION INPUT ;
    USE SIGNAL ;
    PORT
      LAYER M4 ;
        RECT  86.316 30.672 86.4 30.696 ;
    END
  END chn_r[80]
  PIN chn_r[81]
    DIRECTION INPUT ;
    USE SIGNAL ;
    PORT
      LAYER M4 ;
        RECT  86.316 30.768 86.4 30.792 ;
    END
  END chn_r[81]
  PIN chn_r[82]
    DIRECTION INPUT ;
    USE SIGNAL ;
    PORT
      LAYER M4 ;
        RECT  86.316 30.864 86.4 30.888 ;
    END
  END chn_r[82]
  PIN chn_r[83]
    DIRECTION INPUT ;
    USE SIGNAL ;
    PORT
      LAYER M4 ;
        RECT  86.316 30.96 86.4 30.984 ;
    END
  END chn_r[83]
  PIN chn_r[84]
    DIRECTION INPUT ;
    USE SIGNAL ;
    PORT
      LAYER M4 ;
        RECT  86.316 31.056 86.4 31.08 ;
    END
  END chn_r[84]
  PIN chn_r[85]
    DIRECTION INPUT ;
    USE SIGNAL ;
    PORT
      LAYER M4 ;
        RECT  86.316 31.152 86.4 31.176 ;
    END
  END chn_r[85]
  PIN chn_r[86]
    DIRECTION INPUT ;
    USE SIGNAL ;
    PORT
      LAYER M4 ;
        RECT  86.316 31.248 86.4 31.272 ;
    END
  END chn_r[86]
  PIN chn_r[87]
    DIRECTION INPUT ;
    USE SIGNAL ;
    PORT
      LAYER M4 ;
        RECT  86.316 31.344 86.4 31.368 ;
    END
  END chn_r[87]
  PIN chn_r[88]
    DIRECTION INPUT ;
    USE SIGNAL ;
    PORT
      LAYER M4 ;
        RECT  86.316 31.44 86.4 31.464 ;
    END
  END chn_r[88]
  PIN chn_r[89]
    DIRECTION INPUT ;
    USE SIGNAL ;
    PORT
      LAYER M4 ;
        RECT  86.316 31.536 86.4 31.56 ;
    END
  END chn_r[89]
  PIN chn_r[8]
    DIRECTION INPUT ;
    USE SIGNAL ;
    PORT
      LAYER M4 ;
        RECT  86.316 36.048 86.4 36.072 ;
    END
  END chn_r[8]
  PIN chn_r[90]
    DIRECTION INPUT ;
    USE SIGNAL ;
    PORT
      LAYER M4 ;
        RECT  86.316 31.632 86.4 31.656 ;
    END
  END chn_r[90]
  PIN chn_r[91]
    DIRECTION INPUT ;
    USE SIGNAL ;
    PORT
      LAYER M4 ;
        RECT  86.316 31.728 86.4 31.752 ;
    END
  END chn_r[91]
  PIN chn_r[92]
    DIRECTION INPUT ;
    USE SIGNAL ;
    PORT
      LAYER M4 ;
        RECT  86.316 31.824 86.4 31.848 ;
    END
  END chn_r[92]
  PIN chn_r[93]
    DIRECTION INPUT ;
    USE SIGNAL ;
    PORT
      LAYER M4 ;
        RECT  86.316 31.92 86.4 31.944 ;
    END
  END chn_r[93]
  PIN chn_r[94]
    DIRECTION INPUT ;
    USE SIGNAL ;
    PORT
      LAYER M4 ;
        RECT  86.316 32.016 86.4 32.04 ;
    END
  END chn_r[94]
  PIN chn_r[95]
    DIRECTION INPUT ;
    USE SIGNAL ;
    PORT
      LAYER M4 ;
        RECT  86.316 32.112 86.4 32.136 ;
    END
  END chn_r[95]
  PIN chn_r[96]
    DIRECTION INPUT ;
    USE SIGNAL ;
    PORT
      LAYER M4 ;
        RECT  86.316 26.064 86.4 26.088 ;
    END
  END chn_r[96]
  PIN chn_r[97]
    DIRECTION INPUT ;
    USE SIGNAL ;
    PORT
      LAYER M4 ;
        RECT  86.316 26.16 86.4 26.184 ;
    END
  END chn_r[97]
  PIN chn_r[98]
    DIRECTION INPUT ;
    USE SIGNAL ;
    PORT
      LAYER M4 ;
        RECT  86.316 26.256 86.4 26.28 ;
    END
  END chn_r[98]
  PIN chn_r[99]
    DIRECTION INPUT ;
    USE SIGNAL ;
    PORT
      LAYER M4 ;
        RECT  86.316 26.352 86.4 26.376 ;
    END
  END chn_r[99]
  PIN chn_r[9]
    DIRECTION INPUT ;
    USE SIGNAL ;
    PORT
      LAYER M4 ;
        RECT  86.316 36.144 86.4 36.168 ;
    END
  END chn_r[9]
  PIN clk
    DIRECTION INPUT ;
    USE SIGNAL ;
    PORT
      LAYER M4 ;
        RECT  0 34.992 0.084 35.016 ;
    END
  END clk
  PIN gov[0]
    DIRECTION INPUT ;
    USE SIGNAL ;
    PORT
      LAYER M4 ;
        RECT  0 35.088 0.084 35.112 ;
    END
  END gov[0]
  PIN gov[10]
    DIRECTION INPUT ;
    USE SIGNAL ;
    PORT
      LAYER M4 ;
        RECT  0 36.048 0.084 36.072 ;
    END
  END gov[10]
  PIN gov[11]
    DIRECTION INPUT ;
    USE SIGNAL ;
    PORT
      LAYER M4 ;
        RECT  0 36.144 0.084 36.168 ;
    END
  END gov[11]
  PIN gov[12]
    DIRECTION INPUT ;
    USE SIGNAL ;
    PORT
      LAYER M4 ;
        RECT  0 36.24 0.084 36.264 ;
    END
  END gov[12]
  PIN gov[13]
    DIRECTION INPUT ;
    USE SIGNAL ;
    PORT
      LAYER M4 ;
        RECT  0 36.336 0.084 36.36 ;
    END
  END gov[13]
  PIN gov[14]
    DIRECTION INPUT ;
    USE SIGNAL ;
    PORT
      LAYER M4 ;
        RECT  0 36.432 0.084 36.456 ;
    END
  END gov[14]
  PIN gov[15]
    DIRECTION INPUT ;
    USE SIGNAL ;
    PORT
      LAYER M4 ;
        RECT  0 36.528 0.084 36.552 ;
    END
  END gov[15]
  PIN gov[1]
    DIRECTION INPUT ;
    USE SIGNAL ;
    PORT
      LAYER M4 ;
        RECT  0 35.184 0.084 35.208 ;
    END
  END gov[1]
  PIN gov[2]
    DIRECTION INPUT ;
    USE SIGNAL ;
    PORT
      LAYER M4 ;
        RECT  0 35.28 0.084 35.304 ;
    END
  END gov[2]
  PIN gov[3]
    DIRECTION INPUT ;
    USE SIGNAL ;
    PORT
      LAYER M4 ;
        RECT  0 35.376 0.084 35.4 ;
    END
  END gov[3]
  PIN gov[4]
    DIRECTION INPUT ;
    USE SIGNAL ;
    PORT
      LAYER M4 ;
        RECT  0 35.472 0.084 35.496 ;
    END
  END gov[4]
  PIN gov[5]
    DIRECTION INPUT ;
    USE SIGNAL ;
    PORT
      LAYER M4 ;
        RECT  0 35.568 0.084 35.592 ;
    END
  END gov[5]
  PIN gov[6]
    DIRECTION INPUT ;
    USE SIGNAL ;
    PORT
      LAYER M4 ;
        RECT  0 35.664 0.084 35.688 ;
    END
  END gov[6]
  PIN gov[7]
    DIRECTION INPUT ;
    USE SIGNAL ;
    PORT
      LAYER M4 ;
        RECT  0 35.76 0.084 35.784 ;
    END
  END gov[7]
  PIN gov[8]
    DIRECTION INPUT ;
    USE SIGNAL ;
    PORT
      LAYER M4 ;
        RECT  0 35.856 0.084 35.88 ;
    END
  END gov[8]
  PIN gov[9]
    DIRECTION INPUT ;
    USE SIGNAL ;
    PORT
      LAYER M4 ;
        RECT  0 35.952 0.084 35.976 ;
    END
  END gov[9]
  PIN o[0]
    DIRECTION OUTPUT ;
    USE SIGNAL ;
    PORT
      LAYER M5 ;
        RECT  31.92 86.316 31.944 86.4 ;
    END
  END o[0]
  PIN o[100]
    DIRECTION OUTPUT ;
    USE SIGNAL ;
    PORT
      LAYER M5 ;
        RECT  63.792 86.316 63.816 86.4 ;
    END
  END o[100]
  PIN o[101]
    DIRECTION OUTPUT ;
    USE SIGNAL ;
    PORT
      LAYER M5 ;
        RECT  63.888 86.316 63.912 86.4 ;
    END
  END o[101]
  PIN o[102]
    DIRECTION OUTPUT ;
    USE SIGNAL ;
    PORT
      LAYER M5 ;
        RECT  63.984 86.316 64.008 86.4 ;
    END
  END o[102]
  PIN o[103]
    DIRECTION OUTPUT ;
    USE SIGNAL ;
    PORT
      LAYER M5 ;
        RECT  64.08 86.316 64.104 86.4 ;
    END
  END o[103]
  PIN o[104]
    DIRECTION OUTPUT ;
    USE SIGNAL ;
    PORT
      LAYER M5 ;
        RECT  64.176 86.316 64.2 86.4 ;
    END
  END o[104]
  PIN o[105]
    DIRECTION OUTPUT ;
    USE SIGNAL ;
    PORT
      LAYER M5 ;
        RECT  64.272 86.316 64.296 86.4 ;
    END
  END o[105]
  PIN o[106]
    DIRECTION OUTPUT ;
    USE SIGNAL ;
    PORT
      LAYER M5 ;
        RECT  64.368 86.316 64.392 86.4 ;
    END
  END o[106]
  PIN o[107]
    DIRECTION OUTPUT ;
    USE SIGNAL ;
    PORT
      LAYER M5 ;
        RECT  64.464 86.316 64.488 86.4 ;
    END
  END o[107]
  PIN o[108]
    DIRECTION OUTPUT ;
    USE SIGNAL ;
    PORT
      LAYER M5 ;
        RECT  64.56 86.316 64.584 86.4 ;
    END
  END o[108]
  PIN o[109]
    DIRECTION OUTPUT ;
    USE SIGNAL ;
    PORT
      LAYER M5 ;
        RECT  64.656 86.316 64.68 86.4 ;
    END
  END o[109]
  PIN o[10]
    DIRECTION OUTPUT ;
    USE SIGNAL ;
    PORT
      LAYER M5 ;
        RECT  32.88 86.316 32.904 86.4 ;
    END
  END o[10]
  PIN o[110]
    DIRECTION OUTPUT ;
    USE SIGNAL ;
    PORT
      LAYER M5 ;
        RECT  64.752 86.316 64.776 86.4 ;
    END
  END o[110]
  PIN o[111]
    DIRECTION OUTPUT ;
    USE SIGNAL ;
    PORT
      LAYER M5 ;
        RECT  64.848 86.316 64.872 86.4 ;
    END
  END o[111]
  PIN o[112]
    DIRECTION OUTPUT ;
    USE SIGNAL ;
    PORT
      LAYER M5 ;
        RECT  64.944 86.316 64.968 86.4 ;
    END
  END o[112]
  PIN o[113]
    DIRECTION OUTPUT ;
    USE SIGNAL ;
    PORT
      LAYER M5 ;
        RECT  65.04 86.316 65.064 86.4 ;
    END
  END o[113]
  PIN o[114]
    DIRECTION OUTPUT ;
    USE SIGNAL ;
    PORT
      LAYER M5 ;
        RECT  65.136 86.316 65.16 86.4 ;
    END
  END o[114]
  PIN o[115]
    DIRECTION OUTPUT ;
    USE SIGNAL ;
    PORT
      LAYER M5 ;
        RECT  65.232 86.316 65.256 86.4 ;
    END
  END o[115]
  PIN o[116]
    DIRECTION OUTPUT ;
    USE SIGNAL ;
    PORT
      LAYER M5 ;
        RECT  65.328 86.316 65.352 86.4 ;
    END
  END o[116]
  PIN o[117]
    DIRECTION OUTPUT ;
    USE SIGNAL ;
    PORT
      LAYER M5 ;
        RECT  65.424 86.316 65.448 86.4 ;
    END
  END o[117]
  PIN o[118]
    DIRECTION OUTPUT ;
    USE SIGNAL ;
    PORT
      LAYER M5 ;
        RECT  65.52 86.316 65.544 86.4 ;
    END
  END o[118]
  PIN o[119]
    DIRECTION OUTPUT ;
    USE SIGNAL ;
    PORT
      LAYER M5 ;
        RECT  65.616 86.316 65.64 86.4 ;
    END
  END o[119]
  PIN o[11]
    DIRECTION OUTPUT ;
    USE SIGNAL ;
    PORT
      LAYER M5 ;
        RECT  32.976 86.316 33 86.4 ;
    END
  END o[11]
  PIN o[120]
    DIRECTION OUTPUT ;
    USE SIGNAL ;
    PORT
      LAYER M5 ;
        RECT  65.712 86.316 65.736 86.4 ;
    END
  END o[120]
  PIN o[121]
    DIRECTION OUTPUT ;
    USE SIGNAL ;
    PORT
      LAYER M5 ;
        RECT  65.808 86.316 65.832 86.4 ;
    END
  END o[121]
  PIN o[122]
    DIRECTION OUTPUT ;
    USE SIGNAL ;
    PORT
      LAYER M5 ;
        RECT  65.904 86.316 65.928 86.4 ;
    END
  END o[122]
  PIN o[123]
    DIRECTION OUTPUT ;
    USE SIGNAL ;
    PORT
      LAYER M5 ;
        RECT  66 86.316 66.024 86.4 ;
    END
  END o[123]
  PIN o[124]
    DIRECTION OUTPUT ;
    USE SIGNAL ;
    PORT
      LAYER M5 ;
        RECT  66.096 86.316 66.12 86.4 ;
    END
  END o[124]
  PIN o[125]
    DIRECTION OUTPUT ;
    USE SIGNAL ;
    PORT
      LAYER M5 ;
        RECT  66.192 86.316 66.216 86.4 ;
    END
  END o[125]
  PIN o[126]
    DIRECTION OUTPUT ;
    USE SIGNAL ;
    PORT
      LAYER M5 ;
        RECT  66.288 86.316 66.312 86.4 ;
    END
  END o[126]
  PIN o[127]
    DIRECTION OUTPUT ;
    USE SIGNAL ;
    PORT
      LAYER M5 ;
        RECT  66.384 86.316 66.408 86.4 ;
    END
  END o[127]
  PIN o[128]
    DIRECTION OUTPUT ;
    USE SIGNAL ;
    PORT
      LAYER M5 ;
        RECT  54.192 86.316 54.216 86.4 ;
    END
  END o[128]
  PIN o[129]
    DIRECTION OUTPUT ;
    USE SIGNAL ;
    PORT
      LAYER M5 ;
        RECT  54.288 86.316 54.312 86.4 ;
    END
  END o[129]
  PIN o[12]
    DIRECTION OUTPUT ;
    USE SIGNAL ;
    PORT
      LAYER M5 ;
        RECT  33.072 86.316 33.096 86.4 ;
    END
  END o[12]
  PIN o[130]
    DIRECTION OUTPUT ;
    USE SIGNAL ;
    PORT
      LAYER M5 ;
        RECT  54.384 86.316 54.408 86.4 ;
    END
  END o[130]
  PIN o[131]
    DIRECTION OUTPUT ;
    USE SIGNAL ;
    PORT
      LAYER M5 ;
        RECT  54.48 86.316 54.504 86.4 ;
    END
  END o[131]
  PIN o[132]
    DIRECTION OUTPUT ;
    USE SIGNAL ;
    PORT
      LAYER M5 ;
        RECT  54.576 86.316 54.6 86.4 ;
    END
  END o[132]
  PIN o[133]
    DIRECTION OUTPUT ;
    USE SIGNAL ;
    PORT
      LAYER M5 ;
        RECT  54.672 86.316 54.696 86.4 ;
    END
  END o[133]
  PIN o[134]
    DIRECTION OUTPUT ;
    USE SIGNAL ;
    PORT
      LAYER M5 ;
        RECT  54.768 86.316 54.792 86.4 ;
    END
  END o[134]
  PIN o[135]
    DIRECTION OUTPUT ;
    USE SIGNAL ;
    PORT
      LAYER M5 ;
        RECT  54.864 86.316 54.888 86.4 ;
    END
  END o[135]
  PIN o[136]
    DIRECTION OUTPUT ;
    USE SIGNAL ;
    PORT
      LAYER M5 ;
        RECT  54.96 86.316 54.984 86.4 ;
    END
  END o[136]
  PIN o[137]
    DIRECTION OUTPUT ;
    USE SIGNAL ;
    PORT
      LAYER M5 ;
        RECT  55.056 86.316 55.08 86.4 ;
    END
  END o[137]
  PIN o[138]
    DIRECTION OUTPUT ;
    USE SIGNAL ;
    PORT
      LAYER M5 ;
        RECT  55.152 86.316 55.176 86.4 ;
    END
  END o[138]
  PIN o[139]
    DIRECTION OUTPUT ;
    USE SIGNAL ;
    PORT
      LAYER M5 ;
        RECT  55.248 86.316 55.272 86.4 ;
    END
  END o[139]
  PIN o[13]
    DIRECTION OUTPUT ;
    USE SIGNAL ;
    PORT
      LAYER M5 ;
        RECT  33.168 86.316 33.192 86.4 ;
    END
  END o[13]
  PIN o[140]
    DIRECTION OUTPUT ;
    USE SIGNAL ;
    PORT
      LAYER M5 ;
        RECT  55.344 86.316 55.368 86.4 ;
    END
  END o[140]
  PIN o[141]
    DIRECTION OUTPUT ;
    USE SIGNAL ;
    PORT
      LAYER M5 ;
        RECT  55.44 86.316 55.464 86.4 ;
    END
  END o[141]
  PIN o[142]
    DIRECTION OUTPUT ;
    USE SIGNAL ;
    PORT
      LAYER M5 ;
        RECT  55.536 86.316 55.56 86.4 ;
    END
  END o[142]
  PIN o[143]
    DIRECTION OUTPUT ;
    USE SIGNAL ;
    PORT
      LAYER M5 ;
        RECT  55.632 86.316 55.656 86.4 ;
    END
  END o[143]
  PIN o[144]
    DIRECTION OUTPUT ;
    USE SIGNAL ;
    PORT
      LAYER M5 ;
        RECT  55.728 86.316 55.752 86.4 ;
    END
  END o[144]
  PIN o[145]
    DIRECTION OUTPUT ;
    USE SIGNAL ;
    PORT
      LAYER M5 ;
        RECT  55.824 86.316 55.848 86.4 ;
    END
  END o[145]
  PIN o[146]
    DIRECTION OUTPUT ;
    USE SIGNAL ;
    PORT
      LAYER M5 ;
        RECT  55.92 86.316 55.944 86.4 ;
    END
  END o[146]
  PIN o[147]
    DIRECTION OUTPUT ;
    USE SIGNAL ;
    PORT
      LAYER M5 ;
        RECT  56.016 86.316 56.04 86.4 ;
    END
  END o[147]
  PIN o[148]
    DIRECTION OUTPUT ;
    USE SIGNAL ;
    PORT
      LAYER M5 ;
        RECT  56.112 86.316 56.136 86.4 ;
    END
  END o[148]
  PIN o[149]
    DIRECTION OUTPUT ;
    USE SIGNAL ;
    PORT
      LAYER M5 ;
        RECT  56.208 86.316 56.232 86.4 ;
    END
  END o[149]
  PIN o[14]
    DIRECTION OUTPUT ;
    USE SIGNAL ;
    PORT
      LAYER M5 ;
        RECT  33.264 86.316 33.288 86.4 ;
    END
  END o[14]
  PIN o[150]
    DIRECTION OUTPUT ;
    USE SIGNAL ;
    PORT
      LAYER M5 ;
        RECT  56.304 86.316 56.328 86.4 ;
    END
  END o[150]
  PIN o[151]
    DIRECTION OUTPUT ;
    USE SIGNAL ;
    PORT
      LAYER M5 ;
        RECT  56.4 86.316 56.424 86.4 ;
    END
  END o[151]
  PIN o[152]
    DIRECTION OUTPUT ;
    USE SIGNAL ;
    PORT
      LAYER M5 ;
        RECT  56.496 86.316 56.52 86.4 ;
    END
  END o[152]
  PIN o[153]
    DIRECTION OUTPUT ;
    USE SIGNAL ;
    PORT
      LAYER M5 ;
        RECT  56.592 86.316 56.616 86.4 ;
    END
  END o[153]
  PIN o[154]
    DIRECTION OUTPUT ;
    USE SIGNAL ;
    PORT
      LAYER M5 ;
        RECT  56.688 86.316 56.712 86.4 ;
    END
  END o[154]
  PIN o[155]
    DIRECTION OUTPUT ;
    USE SIGNAL ;
    PORT
      LAYER M5 ;
        RECT  56.784 86.316 56.808 86.4 ;
    END
  END o[155]
  PIN o[156]
    DIRECTION OUTPUT ;
    USE SIGNAL ;
    PORT
      LAYER M5 ;
        RECT  56.88 86.316 56.904 86.4 ;
    END
  END o[156]
  PIN o[157]
    DIRECTION OUTPUT ;
    USE SIGNAL ;
    PORT
      LAYER M5 ;
        RECT  56.976 86.316 57 86.4 ;
    END
  END o[157]
  PIN o[158]
    DIRECTION OUTPUT ;
    USE SIGNAL ;
    PORT
      LAYER M5 ;
        RECT  57.072 86.316 57.096 86.4 ;
    END
  END o[158]
  PIN o[159]
    DIRECTION OUTPUT ;
    USE SIGNAL ;
    PORT
      LAYER M5 ;
        RECT  57.168 86.316 57.192 86.4 ;
    END
  END o[159]
  PIN o[15]
    DIRECTION OUTPUT ;
    USE SIGNAL ;
    PORT
      LAYER M5 ;
        RECT  33.36 86.316 33.384 86.4 ;
    END
  END o[15]
  PIN o[160]
    DIRECTION OUTPUT ;
    USE SIGNAL ;
    PORT
      LAYER M5 ;
        RECT  48.048 86.316 48.072 86.4 ;
    END
  END o[160]
  PIN o[161]
    DIRECTION OUTPUT ;
    USE SIGNAL ;
    PORT
      LAYER M5 ;
        RECT  48.144 86.316 48.168 86.4 ;
    END
  END o[161]
  PIN o[162]
    DIRECTION OUTPUT ;
    USE SIGNAL ;
    PORT
      LAYER M5 ;
        RECT  48.24 86.316 48.264 86.4 ;
    END
  END o[162]
  PIN o[163]
    DIRECTION OUTPUT ;
    USE SIGNAL ;
    PORT
      LAYER M5 ;
        RECT  48.336 86.316 48.36 86.4 ;
    END
  END o[163]
  PIN o[164]
    DIRECTION OUTPUT ;
    USE SIGNAL ;
    PORT
      LAYER M5 ;
        RECT  48.432 86.316 48.456 86.4 ;
    END
  END o[164]
  PIN o[165]
    DIRECTION OUTPUT ;
    USE SIGNAL ;
    PORT
      LAYER M5 ;
        RECT  48.528 86.316 48.552 86.4 ;
    END
  END o[165]
  PIN o[166]
    DIRECTION OUTPUT ;
    USE SIGNAL ;
    PORT
      LAYER M5 ;
        RECT  48.624 86.316 48.648 86.4 ;
    END
  END o[166]
  PIN o[167]
    DIRECTION OUTPUT ;
    USE SIGNAL ;
    PORT
      LAYER M5 ;
        RECT  48.72 86.316 48.744 86.4 ;
    END
  END o[167]
  PIN o[168]
    DIRECTION OUTPUT ;
    USE SIGNAL ;
    PORT
      LAYER M5 ;
        RECT  48.816 86.316 48.84 86.4 ;
    END
  END o[168]
  PIN o[169]
    DIRECTION OUTPUT ;
    USE SIGNAL ;
    PORT
      LAYER M5 ;
        RECT  48.912 86.316 48.936 86.4 ;
    END
  END o[169]
  PIN o[16]
    DIRECTION OUTPUT ;
    USE SIGNAL ;
    PORT
      LAYER M5 ;
        RECT  33.456 86.316 33.48 86.4 ;
    END
  END o[16]
  PIN o[170]
    DIRECTION OUTPUT ;
    USE SIGNAL ;
    PORT
      LAYER M5 ;
        RECT  49.008 86.316 49.032 86.4 ;
    END
  END o[170]
  PIN o[171]
    DIRECTION OUTPUT ;
    USE SIGNAL ;
    PORT
      LAYER M5 ;
        RECT  49.104 86.316 49.128 86.4 ;
    END
  END o[171]
  PIN o[172]
    DIRECTION OUTPUT ;
    USE SIGNAL ;
    PORT
      LAYER M5 ;
        RECT  49.2 86.316 49.224 86.4 ;
    END
  END o[172]
  PIN o[173]
    DIRECTION OUTPUT ;
    USE SIGNAL ;
    PORT
      LAYER M5 ;
        RECT  49.296 86.316 49.32 86.4 ;
    END
  END o[173]
  PIN o[174]
    DIRECTION OUTPUT ;
    USE SIGNAL ;
    PORT
      LAYER M5 ;
        RECT  49.392 86.316 49.416 86.4 ;
    END
  END o[174]
  PIN o[175]
    DIRECTION OUTPUT ;
    USE SIGNAL ;
    PORT
      LAYER M5 ;
        RECT  49.488 86.316 49.512 86.4 ;
    END
  END o[175]
  PIN o[176]
    DIRECTION OUTPUT ;
    USE SIGNAL ;
    PORT
      LAYER M5 ;
        RECT  49.584 86.316 49.608 86.4 ;
    END
  END o[176]
  PIN o[177]
    DIRECTION OUTPUT ;
    USE SIGNAL ;
    PORT
      LAYER M5 ;
        RECT  49.68 86.316 49.704 86.4 ;
    END
  END o[177]
  PIN o[178]
    DIRECTION OUTPUT ;
    USE SIGNAL ;
    PORT
      LAYER M5 ;
        RECT  49.776 86.316 49.8 86.4 ;
    END
  END o[178]
  PIN o[179]
    DIRECTION OUTPUT ;
    USE SIGNAL ;
    PORT
      LAYER M5 ;
        RECT  49.872 86.316 49.896 86.4 ;
    END
  END o[179]
  PIN o[17]
    DIRECTION OUTPUT ;
    USE SIGNAL ;
    PORT
      LAYER M5 ;
        RECT  33.552 86.316 33.576 86.4 ;
    END
  END o[17]
  PIN o[180]
    DIRECTION OUTPUT ;
    USE SIGNAL ;
    PORT
      LAYER M5 ;
        RECT  49.968 86.316 49.992 86.4 ;
    END
  END o[180]
  PIN o[181]
    DIRECTION OUTPUT ;
    USE SIGNAL ;
    PORT
      LAYER M5 ;
        RECT  50.064 86.316 50.088 86.4 ;
    END
  END o[181]
  PIN o[182]
    DIRECTION OUTPUT ;
    USE SIGNAL ;
    PORT
      LAYER M5 ;
        RECT  50.16 86.316 50.184 86.4 ;
    END
  END o[182]
  PIN o[183]
    DIRECTION OUTPUT ;
    USE SIGNAL ;
    PORT
      LAYER M5 ;
        RECT  50.256 86.316 50.28 86.4 ;
    END
  END o[183]
  PIN o[184]
    DIRECTION OUTPUT ;
    USE SIGNAL ;
    PORT
      LAYER M5 ;
        RECT  50.352 86.316 50.376 86.4 ;
    END
  END o[184]
  PIN o[185]
    DIRECTION OUTPUT ;
    USE SIGNAL ;
    PORT
      LAYER M5 ;
        RECT  50.448 86.316 50.472 86.4 ;
    END
  END o[185]
  PIN o[186]
    DIRECTION OUTPUT ;
    USE SIGNAL ;
    PORT
      LAYER M5 ;
        RECT  50.544 86.316 50.568 86.4 ;
    END
  END o[186]
  PIN o[187]
    DIRECTION OUTPUT ;
    USE SIGNAL ;
    PORT
      LAYER M5 ;
        RECT  50.64 86.316 50.664 86.4 ;
    END
  END o[187]
  PIN o[188]
    DIRECTION OUTPUT ;
    USE SIGNAL ;
    PORT
      LAYER M5 ;
        RECT  50.736 86.316 50.76 86.4 ;
    END
  END o[188]
  PIN o[189]
    DIRECTION OUTPUT ;
    USE SIGNAL ;
    PORT
      LAYER M5 ;
        RECT  50.832 86.316 50.856 86.4 ;
    END
  END o[189]
  PIN o[18]
    DIRECTION OUTPUT ;
    USE SIGNAL ;
    PORT
      LAYER M5 ;
        RECT  33.648 86.316 33.672 86.4 ;
    END
  END o[18]
  PIN o[190]
    DIRECTION OUTPUT ;
    USE SIGNAL ;
    PORT
      LAYER M5 ;
        RECT  50.928 86.316 50.952 86.4 ;
    END
  END o[190]
  PIN o[191]
    DIRECTION OUTPUT ;
    USE SIGNAL ;
    PORT
      LAYER M5 ;
        RECT  51.024 86.316 51.048 86.4 ;
    END
  END o[191]
  PIN o[192]
    DIRECTION OUTPUT ;
    USE SIGNAL ;
    PORT
      LAYER M5 ;
        RECT  60.336 86.316 60.36 86.4 ;
    END
  END o[192]
  PIN o[193]
    DIRECTION OUTPUT ;
    USE SIGNAL ;
    PORT
      LAYER M5 ;
        RECT  60.432 86.316 60.456 86.4 ;
    END
  END o[193]
  PIN o[194]
    DIRECTION OUTPUT ;
    USE SIGNAL ;
    PORT
      LAYER M5 ;
        RECT  60.528 86.316 60.552 86.4 ;
    END
  END o[194]
  PIN o[195]
    DIRECTION OUTPUT ;
    USE SIGNAL ;
    PORT
      LAYER M5 ;
        RECT  60.624 86.316 60.648 86.4 ;
    END
  END o[195]
  PIN o[196]
    DIRECTION OUTPUT ;
    USE SIGNAL ;
    PORT
      LAYER M5 ;
        RECT  60.72 86.316 60.744 86.4 ;
    END
  END o[196]
  PIN o[197]
    DIRECTION OUTPUT ;
    USE SIGNAL ;
    PORT
      LAYER M5 ;
        RECT  60.816 86.316 60.84 86.4 ;
    END
  END o[197]
  PIN o[198]
    DIRECTION OUTPUT ;
    USE SIGNAL ;
    PORT
      LAYER M5 ;
        RECT  60.912 86.316 60.936 86.4 ;
    END
  END o[198]
  PIN o[199]
    DIRECTION OUTPUT ;
    USE SIGNAL ;
    PORT
      LAYER M5 ;
        RECT  61.008 86.316 61.032 86.4 ;
    END
  END o[199]
  PIN o[19]
    DIRECTION OUTPUT ;
    USE SIGNAL ;
    PORT
      LAYER M5 ;
        RECT  33.744 86.316 33.768 86.4 ;
    END
  END o[19]
  PIN o[1]
    DIRECTION OUTPUT ;
    USE SIGNAL ;
    PORT
      LAYER M5 ;
        RECT  32.016 86.316 32.04 86.4 ;
    END
  END o[1]
  PIN o[200]
    DIRECTION OUTPUT ;
    USE SIGNAL ;
    PORT
      LAYER M5 ;
        RECT  61.104 86.316 61.128 86.4 ;
    END
  END o[200]
  PIN o[201]
    DIRECTION OUTPUT ;
    USE SIGNAL ;
    PORT
      LAYER M5 ;
        RECT  61.2 86.316 61.224 86.4 ;
    END
  END o[201]
  PIN o[202]
    DIRECTION OUTPUT ;
    USE SIGNAL ;
    PORT
      LAYER M5 ;
        RECT  61.296 86.316 61.32 86.4 ;
    END
  END o[202]
  PIN o[203]
    DIRECTION OUTPUT ;
    USE SIGNAL ;
    PORT
      LAYER M5 ;
        RECT  61.392 86.316 61.416 86.4 ;
    END
  END o[203]
  PIN o[204]
    DIRECTION OUTPUT ;
    USE SIGNAL ;
    PORT
      LAYER M5 ;
        RECT  61.488 86.316 61.512 86.4 ;
    END
  END o[204]
  PIN o[205]
    DIRECTION OUTPUT ;
    USE SIGNAL ;
    PORT
      LAYER M5 ;
        RECT  61.584 86.316 61.608 86.4 ;
    END
  END o[205]
  PIN o[206]
    DIRECTION OUTPUT ;
    USE SIGNAL ;
    PORT
      LAYER M5 ;
        RECT  61.68 86.316 61.704 86.4 ;
    END
  END o[206]
  PIN o[207]
    DIRECTION OUTPUT ;
    USE SIGNAL ;
    PORT
      LAYER M5 ;
        RECT  61.776 86.316 61.8 86.4 ;
    END
  END o[207]
  PIN o[208]
    DIRECTION OUTPUT ;
    USE SIGNAL ;
    PORT
      LAYER M5 ;
        RECT  61.872 86.316 61.896 86.4 ;
    END
  END o[208]
  PIN o[209]
    DIRECTION OUTPUT ;
    USE SIGNAL ;
    PORT
      LAYER M5 ;
        RECT  61.968 86.316 61.992 86.4 ;
    END
  END o[209]
  PIN o[20]
    DIRECTION OUTPUT ;
    USE SIGNAL ;
    PORT
      LAYER M5 ;
        RECT  33.84 86.316 33.864 86.4 ;
    END
  END o[20]
  PIN o[210]
    DIRECTION OUTPUT ;
    USE SIGNAL ;
    PORT
      LAYER M5 ;
        RECT  62.064 86.316 62.088 86.4 ;
    END
  END o[210]
  PIN o[211]
    DIRECTION OUTPUT ;
    USE SIGNAL ;
    PORT
      LAYER M5 ;
        RECT  62.16 86.316 62.184 86.4 ;
    END
  END o[211]
  PIN o[212]
    DIRECTION OUTPUT ;
    USE SIGNAL ;
    PORT
      LAYER M5 ;
        RECT  62.256 86.316 62.28 86.4 ;
    END
  END o[212]
  PIN o[213]
    DIRECTION OUTPUT ;
    USE SIGNAL ;
    PORT
      LAYER M5 ;
        RECT  62.352 86.316 62.376 86.4 ;
    END
  END o[213]
  PIN o[214]
    DIRECTION OUTPUT ;
    USE SIGNAL ;
    PORT
      LAYER M5 ;
        RECT  62.448 86.316 62.472 86.4 ;
    END
  END o[214]
  PIN o[215]
    DIRECTION OUTPUT ;
    USE SIGNAL ;
    PORT
      LAYER M5 ;
        RECT  62.544 86.316 62.568 86.4 ;
    END
  END o[215]
  PIN o[216]
    DIRECTION OUTPUT ;
    USE SIGNAL ;
    PORT
      LAYER M5 ;
        RECT  62.64 86.316 62.664 86.4 ;
    END
  END o[216]
  PIN o[217]
    DIRECTION OUTPUT ;
    USE SIGNAL ;
    PORT
      LAYER M5 ;
        RECT  62.736 86.316 62.76 86.4 ;
    END
  END o[217]
  PIN o[218]
    DIRECTION OUTPUT ;
    USE SIGNAL ;
    PORT
      LAYER M5 ;
        RECT  62.832 86.316 62.856 86.4 ;
    END
  END o[218]
  PIN o[219]
    DIRECTION OUTPUT ;
    USE SIGNAL ;
    PORT
      LAYER M5 ;
        RECT  62.928 86.316 62.952 86.4 ;
    END
  END o[219]
  PIN o[21]
    DIRECTION OUTPUT ;
    USE SIGNAL ;
    PORT
      LAYER M5 ;
        RECT  33.936 86.316 33.96 86.4 ;
    END
  END o[21]
  PIN o[220]
    DIRECTION OUTPUT ;
    USE SIGNAL ;
    PORT
      LAYER M5 ;
        RECT  63.024 86.316 63.048 86.4 ;
    END
  END o[220]
  PIN o[221]
    DIRECTION OUTPUT ;
    USE SIGNAL ;
    PORT
      LAYER M5 ;
        RECT  63.12 86.316 63.144 86.4 ;
    END
  END o[221]
  PIN o[222]
    DIRECTION OUTPUT ;
    USE SIGNAL ;
    PORT
      LAYER M5 ;
        RECT  63.216 86.316 63.24 86.4 ;
    END
  END o[222]
  PIN o[223]
    DIRECTION OUTPUT ;
    USE SIGNAL ;
    PORT
      LAYER M5 ;
        RECT  63.312 86.316 63.336 86.4 ;
    END
  END o[223]
  PIN o[224]
    DIRECTION OUTPUT ;
    USE SIGNAL ;
    PORT
      LAYER M5 ;
        RECT  44.208 86.316 44.232 86.4 ;
    END
  END o[224]
  PIN o[225]
    DIRECTION OUTPUT ;
    USE SIGNAL ;
    PORT
      LAYER M5 ;
        RECT  44.304 86.316 44.328 86.4 ;
    END
  END o[225]
  PIN o[226]
    DIRECTION OUTPUT ;
    USE SIGNAL ;
    PORT
      LAYER M5 ;
        RECT  44.4 86.316 44.424 86.4 ;
    END
  END o[226]
  PIN o[227]
    DIRECTION OUTPUT ;
    USE SIGNAL ;
    PORT
      LAYER M5 ;
        RECT  44.496 86.316 44.52 86.4 ;
    END
  END o[227]
  PIN o[228]
    DIRECTION OUTPUT ;
    USE SIGNAL ;
    PORT
      LAYER M5 ;
        RECT  44.592 86.316 44.616 86.4 ;
    END
  END o[228]
  PIN o[229]
    DIRECTION OUTPUT ;
    USE SIGNAL ;
    PORT
      LAYER M5 ;
        RECT  44.688 86.316 44.712 86.4 ;
    END
  END o[229]
  PIN o[22]
    DIRECTION OUTPUT ;
    USE SIGNAL ;
    PORT
      LAYER M5 ;
        RECT  34.032 86.316 34.056 86.4 ;
    END
  END o[22]
  PIN o[230]
    DIRECTION OUTPUT ;
    USE SIGNAL ;
    PORT
      LAYER M5 ;
        RECT  44.784 86.316 44.808 86.4 ;
    END
  END o[230]
  PIN o[231]
    DIRECTION OUTPUT ;
    USE SIGNAL ;
    PORT
      LAYER M5 ;
        RECT  44.88 86.316 44.904 86.4 ;
    END
  END o[231]
  PIN o[232]
    DIRECTION OUTPUT ;
    USE SIGNAL ;
    PORT
      LAYER M5 ;
        RECT  44.976 86.316 45 86.4 ;
    END
  END o[232]
  PIN o[233]
    DIRECTION OUTPUT ;
    USE SIGNAL ;
    PORT
      LAYER M5 ;
        RECT  45.072 86.316 45.096 86.4 ;
    END
  END o[233]
  PIN o[234]
    DIRECTION OUTPUT ;
    USE SIGNAL ;
    PORT
      LAYER M5 ;
        RECT  45.168 86.316 45.192 86.4 ;
    END
  END o[234]
  PIN o[235]
    DIRECTION OUTPUT ;
    USE SIGNAL ;
    PORT
      LAYER M5 ;
        RECT  45.264 86.316 45.288 86.4 ;
    END
  END o[235]
  PIN o[236]
    DIRECTION OUTPUT ;
    USE SIGNAL ;
    PORT
      LAYER M5 ;
        RECT  45.36 86.316 45.384 86.4 ;
    END
  END o[236]
  PIN o[237]
    DIRECTION OUTPUT ;
    USE SIGNAL ;
    PORT
      LAYER M5 ;
        RECT  45.456 86.316 45.48 86.4 ;
    END
  END o[237]
  PIN o[238]
    DIRECTION OUTPUT ;
    USE SIGNAL ;
    PORT
      LAYER M5 ;
        RECT  45.552 86.316 45.576 86.4 ;
    END
  END o[238]
  PIN o[239]
    DIRECTION OUTPUT ;
    USE SIGNAL ;
    PORT
      LAYER M5 ;
        RECT  45.648 86.316 45.672 86.4 ;
    END
  END o[239]
  PIN o[23]
    DIRECTION OUTPUT ;
    USE SIGNAL ;
    PORT
      LAYER M5 ;
        RECT  34.128 86.316 34.152 86.4 ;
    END
  END o[23]
  PIN o[240]
    DIRECTION OUTPUT ;
    USE SIGNAL ;
    PORT
      LAYER M5 ;
        RECT  45.744 86.316 45.768 86.4 ;
    END
  END o[240]
  PIN o[241]
    DIRECTION OUTPUT ;
    USE SIGNAL ;
    PORT
      LAYER M5 ;
        RECT  45.84 86.316 45.864 86.4 ;
    END
  END o[241]
  PIN o[242]
    DIRECTION OUTPUT ;
    USE SIGNAL ;
    PORT
      LAYER M5 ;
        RECT  45.936 86.316 45.96 86.4 ;
    END
  END o[242]
  PIN o[243]
    DIRECTION OUTPUT ;
    USE SIGNAL ;
    PORT
      LAYER M5 ;
        RECT  46.032 86.316 46.056 86.4 ;
    END
  END o[243]
  PIN o[244]
    DIRECTION OUTPUT ;
    USE SIGNAL ;
    PORT
      LAYER M5 ;
        RECT  46.128 86.316 46.152 86.4 ;
    END
  END o[244]
  PIN o[245]
    DIRECTION OUTPUT ;
    USE SIGNAL ;
    PORT
      LAYER M5 ;
        RECT  46.224 86.316 46.248 86.4 ;
    END
  END o[245]
  PIN o[246]
    DIRECTION OUTPUT ;
    USE SIGNAL ;
    PORT
      LAYER M5 ;
        RECT  46.32 86.316 46.344 86.4 ;
    END
  END o[246]
  PIN o[247]
    DIRECTION OUTPUT ;
    USE SIGNAL ;
    PORT
      LAYER M5 ;
        RECT  46.416 86.316 46.44 86.4 ;
    END
  END o[247]
  PIN o[248]
    DIRECTION OUTPUT ;
    USE SIGNAL ;
    PORT
      LAYER M5 ;
        RECT  46.512 86.316 46.536 86.4 ;
    END
  END o[248]
  PIN o[249]
    DIRECTION OUTPUT ;
    USE SIGNAL ;
    PORT
      LAYER M5 ;
        RECT  46.608 86.316 46.632 86.4 ;
    END
  END o[249]
  PIN o[24]
    DIRECTION OUTPUT ;
    USE SIGNAL ;
    PORT
      LAYER M5 ;
        RECT  34.224 86.316 34.248 86.4 ;
    END
  END o[24]
  PIN o[250]
    DIRECTION OUTPUT ;
    USE SIGNAL ;
    PORT
      LAYER M5 ;
        RECT  46.704 86.316 46.728 86.4 ;
    END
  END o[250]
  PIN o[251]
    DIRECTION OUTPUT ;
    USE SIGNAL ;
    PORT
      LAYER M5 ;
        RECT  46.8 86.316 46.824 86.4 ;
    END
  END o[251]
  PIN o[252]
    DIRECTION OUTPUT ;
    USE SIGNAL ;
    PORT
      LAYER M5 ;
        RECT  46.896 86.316 46.92 86.4 ;
    END
  END o[252]
  PIN o[253]
    DIRECTION OUTPUT ;
    USE SIGNAL ;
    PORT
      LAYER M5 ;
        RECT  46.992 86.316 47.016 86.4 ;
    END
  END o[253]
  PIN o[254]
    DIRECTION OUTPUT ;
    USE SIGNAL ;
    PORT
      LAYER M5 ;
        RECT  47.088 86.316 47.112 86.4 ;
    END
  END o[254]
  PIN o[255]
    DIRECTION OUTPUT ;
    USE SIGNAL ;
    PORT
      LAYER M5 ;
        RECT  47.184 86.316 47.208 86.4 ;
    END
  END o[255]
  PIN o[256]
    DIRECTION OUTPUT ;
    USE SIGNAL ;
    PORT
      LAYER M5 ;
        RECT  41.136 86.316 41.16 86.4 ;
    END
  END o[256]
  PIN o[257]
    DIRECTION OUTPUT ;
    USE SIGNAL ;
    PORT
      LAYER M5 ;
        RECT  41.232 86.316 41.256 86.4 ;
    END
  END o[257]
  PIN o[258]
    DIRECTION OUTPUT ;
    USE SIGNAL ;
    PORT
      LAYER M5 ;
        RECT  41.328 86.316 41.352 86.4 ;
    END
  END o[258]
  PIN o[259]
    DIRECTION OUTPUT ;
    USE SIGNAL ;
    PORT
      LAYER M5 ;
        RECT  41.424 86.316 41.448 86.4 ;
    END
  END o[259]
  PIN o[25]
    DIRECTION OUTPUT ;
    USE SIGNAL ;
    PORT
      LAYER M5 ;
        RECT  34.32 86.316 34.344 86.4 ;
    END
  END o[25]
  PIN o[260]
    DIRECTION OUTPUT ;
    USE SIGNAL ;
    PORT
      LAYER M5 ;
        RECT  41.52 86.316 41.544 86.4 ;
    END
  END o[260]
  PIN o[261]
    DIRECTION OUTPUT ;
    USE SIGNAL ;
    PORT
      LAYER M5 ;
        RECT  41.616 86.316 41.64 86.4 ;
    END
  END o[261]
  PIN o[262]
    DIRECTION OUTPUT ;
    USE SIGNAL ;
    PORT
      LAYER M5 ;
        RECT  41.712 86.316 41.736 86.4 ;
    END
  END o[262]
  PIN o[263]
    DIRECTION OUTPUT ;
    USE SIGNAL ;
    PORT
      LAYER M5 ;
        RECT  41.808 86.316 41.832 86.4 ;
    END
  END o[263]
  PIN o[264]
    DIRECTION OUTPUT ;
    USE SIGNAL ;
    PORT
      LAYER M5 ;
        RECT  41.904 86.316 41.928 86.4 ;
    END
  END o[264]
  PIN o[265]
    DIRECTION OUTPUT ;
    USE SIGNAL ;
    PORT
      LAYER M5 ;
        RECT  42 86.316 42.024 86.4 ;
    END
  END o[265]
  PIN o[266]
    DIRECTION OUTPUT ;
    USE SIGNAL ;
    PORT
      LAYER M5 ;
        RECT  42.096 86.316 42.12 86.4 ;
    END
  END o[266]
  PIN o[267]
    DIRECTION OUTPUT ;
    USE SIGNAL ;
    PORT
      LAYER M5 ;
        RECT  42.192 86.316 42.216 86.4 ;
    END
  END o[267]
  PIN o[268]
    DIRECTION OUTPUT ;
    USE SIGNAL ;
    PORT
      LAYER M5 ;
        RECT  42.288 86.316 42.312 86.4 ;
    END
  END o[268]
  PIN o[269]
    DIRECTION OUTPUT ;
    USE SIGNAL ;
    PORT
      LAYER M5 ;
        RECT  42.384 86.316 42.408 86.4 ;
    END
  END o[269]
  PIN o[26]
    DIRECTION OUTPUT ;
    USE SIGNAL ;
    PORT
      LAYER M5 ;
        RECT  34.416 86.316 34.44 86.4 ;
    END
  END o[26]
  PIN o[270]
    DIRECTION OUTPUT ;
    USE SIGNAL ;
    PORT
      LAYER M5 ;
        RECT  42.48 86.316 42.504 86.4 ;
    END
  END o[270]
  PIN o[271]
    DIRECTION OUTPUT ;
    USE SIGNAL ;
    PORT
      LAYER M5 ;
        RECT  42.576 86.316 42.6 86.4 ;
    END
  END o[271]
  PIN o[272]
    DIRECTION OUTPUT ;
    USE SIGNAL ;
    PORT
      LAYER M5 ;
        RECT  42.672 86.316 42.696 86.4 ;
    END
  END o[272]
  PIN o[273]
    DIRECTION OUTPUT ;
    USE SIGNAL ;
    PORT
      LAYER M5 ;
        RECT  42.768 86.316 42.792 86.4 ;
    END
  END o[273]
  PIN o[274]
    DIRECTION OUTPUT ;
    USE SIGNAL ;
    PORT
      LAYER M5 ;
        RECT  42.864 86.316 42.888 86.4 ;
    END
  END o[274]
  PIN o[275]
    DIRECTION OUTPUT ;
    USE SIGNAL ;
    PORT
      LAYER M5 ;
        RECT  42.96 86.316 42.984 86.4 ;
    END
  END o[275]
  PIN o[276]
    DIRECTION OUTPUT ;
    USE SIGNAL ;
    PORT
      LAYER M5 ;
        RECT  43.056 86.316 43.08 86.4 ;
    END
  END o[276]
  PIN o[277]
    DIRECTION OUTPUT ;
    USE SIGNAL ;
    PORT
      LAYER M5 ;
        RECT  43.152 86.316 43.176 86.4 ;
    END
  END o[277]
  PIN o[278]
    DIRECTION OUTPUT ;
    USE SIGNAL ;
    PORT
      LAYER M5 ;
        RECT  43.248 86.316 43.272 86.4 ;
    END
  END o[278]
  PIN o[279]
    DIRECTION OUTPUT ;
    USE SIGNAL ;
    PORT
      LAYER M5 ;
        RECT  43.344 86.316 43.368 86.4 ;
    END
  END o[279]
  PIN o[27]
    DIRECTION OUTPUT ;
    USE SIGNAL ;
    PORT
      LAYER M5 ;
        RECT  34.512 86.316 34.536 86.4 ;
    END
  END o[27]
  PIN o[280]
    DIRECTION OUTPUT ;
    USE SIGNAL ;
    PORT
      LAYER M5 ;
        RECT  43.44 86.316 43.464 86.4 ;
    END
  END o[280]
  PIN o[281]
    DIRECTION OUTPUT ;
    USE SIGNAL ;
    PORT
      LAYER M5 ;
        RECT  43.536 86.316 43.56 86.4 ;
    END
  END o[281]
  PIN o[282]
    DIRECTION OUTPUT ;
    USE SIGNAL ;
    PORT
      LAYER M5 ;
        RECT  43.632 86.316 43.656 86.4 ;
    END
  END o[282]
  PIN o[283]
    DIRECTION OUTPUT ;
    USE SIGNAL ;
    PORT
      LAYER M5 ;
        RECT  43.728 86.316 43.752 86.4 ;
    END
  END o[283]
  PIN o[284]
    DIRECTION OUTPUT ;
    USE SIGNAL ;
    PORT
      LAYER M5 ;
        RECT  43.824 86.316 43.848 86.4 ;
    END
  END o[284]
  PIN o[285]
    DIRECTION OUTPUT ;
    USE SIGNAL ;
    PORT
      LAYER M5 ;
        RECT  43.92 86.316 43.944 86.4 ;
    END
  END o[285]
  PIN o[286]
    DIRECTION OUTPUT ;
    USE SIGNAL ;
    PORT
      LAYER M5 ;
        RECT  44.016 86.316 44.04 86.4 ;
    END
  END o[286]
  PIN o[287]
    DIRECTION OUTPUT ;
    USE SIGNAL ;
    PORT
      LAYER M5 ;
        RECT  44.112 86.316 44.136 86.4 ;
    END
  END o[287]
  PIN o[288]
    DIRECTION OUTPUT ;
    USE SIGNAL ;
    PORT
      LAYER M5 ;
        RECT  34.992 86.316 35.016 86.4 ;
    END
  END o[288]
  PIN o[289]
    DIRECTION OUTPUT ;
    USE SIGNAL ;
    PORT
      LAYER M5 ;
        RECT  35.088 86.316 35.112 86.4 ;
    END
  END o[289]
  PIN o[28]
    DIRECTION OUTPUT ;
    USE SIGNAL ;
    PORT
      LAYER M5 ;
        RECT  34.608 86.316 34.632 86.4 ;
    END
  END o[28]
  PIN o[290]
    DIRECTION OUTPUT ;
    USE SIGNAL ;
    PORT
      LAYER M5 ;
        RECT  35.184 86.316 35.208 86.4 ;
    END
  END o[290]
  PIN o[291]
    DIRECTION OUTPUT ;
    USE SIGNAL ;
    PORT
      LAYER M5 ;
        RECT  35.28 86.316 35.304 86.4 ;
    END
  END o[291]
  PIN o[292]
    DIRECTION OUTPUT ;
    USE SIGNAL ;
    PORT
      LAYER M5 ;
        RECT  35.376 86.316 35.4 86.4 ;
    END
  END o[292]
  PIN o[293]
    DIRECTION OUTPUT ;
    USE SIGNAL ;
    PORT
      LAYER M5 ;
        RECT  35.472 86.316 35.496 86.4 ;
    END
  END o[293]
  PIN o[294]
    DIRECTION OUTPUT ;
    USE SIGNAL ;
    PORT
      LAYER M5 ;
        RECT  35.568 86.316 35.592 86.4 ;
    END
  END o[294]
  PIN o[295]
    DIRECTION OUTPUT ;
    USE SIGNAL ;
    PORT
      LAYER M5 ;
        RECT  35.664 86.316 35.688 86.4 ;
    END
  END o[295]
  PIN o[296]
    DIRECTION OUTPUT ;
    USE SIGNAL ;
    PORT
      LAYER M5 ;
        RECT  35.76 86.316 35.784 86.4 ;
    END
  END o[296]
  PIN o[297]
    DIRECTION OUTPUT ;
    USE SIGNAL ;
    PORT
      LAYER M5 ;
        RECT  35.856 86.316 35.88 86.4 ;
    END
  END o[297]
  PIN o[298]
    DIRECTION OUTPUT ;
    USE SIGNAL ;
    PORT
      LAYER M5 ;
        RECT  35.952 86.316 35.976 86.4 ;
    END
  END o[298]
  PIN o[299]
    DIRECTION OUTPUT ;
    USE SIGNAL ;
    PORT
      LAYER M5 ;
        RECT  36.048 86.316 36.072 86.4 ;
    END
  END o[299]
  PIN o[29]
    DIRECTION OUTPUT ;
    USE SIGNAL ;
    PORT
      LAYER M5 ;
        RECT  34.704 86.316 34.728 86.4 ;
    END
  END o[29]
  PIN o[2]
    DIRECTION OUTPUT ;
    USE SIGNAL ;
    PORT
      LAYER M5 ;
        RECT  32.112 86.316 32.136 86.4 ;
    END
  END o[2]
  PIN o[300]
    DIRECTION OUTPUT ;
    USE SIGNAL ;
    PORT
      LAYER M5 ;
        RECT  36.144 86.316 36.168 86.4 ;
    END
  END o[300]
  PIN o[301]
    DIRECTION OUTPUT ;
    USE SIGNAL ;
    PORT
      LAYER M5 ;
        RECT  36.24 86.316 36.264 86.4 ;
    END
  END o[301]
  PIN o[302]
    DIRECTION OUTPUT ;
    USE SIGNAL ;
    PORT
      LAYER M5 ;
        RECT  36.336 86.316 36.36 86.4 ;
    END
  END o[302]
  PIN o[303]
    DIRECTION OUTPUT ;
    USE SIGNAL ;
    PORT
      LAYER M5 ;
        RECT  36.432 86.316 36.456 86.4 ;
    END
  END o[303]
  PIN o[304]
    DIRECTION OUTPUT ;
    USE SIGNAL ;
    PORT
      LAYER M5 ;
        RECT  36.528 86.316 36.552 86.4 ;
    END
  END o[304]
  PIN o[305]
    DIRECTION OUTPUT ;
    USE SIGNAL ;
    PORT
      LAYER M5 ;
        RECT  36.624 86.316 36.648 86.4 ;
    END
  END o[305]
  PIN o[306]
    DIRECTION OUTPUT ;
    USE SIGNAL ;
    PORT
      LAYER M5 ;
        RECT  36.72 86.316 36.744 86.4 ;
    END
  END o[306]
  PIN o[307]
    DIRECTION OUTPUT ;
    USE SIGNAL ;
    PORT
      LAYER M5 ;
        RECT  36.816 86.316 36.84 86.4 ;
    END
  END o[307]
  PIN o[308]
    DIRECTION OUTPUT ;
    USE SIGNAL ;
    PORT
      LAYER M5 ;
        RECT  36.912 86.316 36.936 86.4 ;
    END
  END o[308]
  PIN o[309]
    DIRECTION OUTPUT ;
    USE SIGNAL ;
    PORT
      LAYER M5 ;
        RECT  37.008 86.316 37.032 86.4 ;
    END
  END o[309]
  PIN o[30]
    DIRECTION OUTPUT ;
    USE SIGNAL ;
    PORT
      LAYER M5 ;
        RECT  34.8 86.316 34.824 86.4 ;
    END
  END o[30]
  PIN o[310]
    DIRECTION OUTPUT ;
    USE SIGNAL ;
    PORT
      LAYER M5 ;
        RECT  37.104 86.316 37.128 86.4 ;
    END
  END o[310]
  PIN o[311]
    DIRECTION OUTPUT ;
    USE SIGNAL ;
    PORT
      LAYER M5 ;
        RECT  37.2 86.316 37.224 86.4 ;
    END
  END o[311]
  PIN o[312]
    DIRECTION OUTPUT ;
    USE SIGNAL ;
    PORT
      LAYER M5 ;
        RECT  37.296 86.316 37.32 86.4 ;
    END
  END o[312]
  PIN o[313]
    DIRECTION OUTPUT ;
    USE SIGNAL ;
    PORT
      LAYER M5 ;
        RECT  37.392 86.316 37.416 86.4 ;
    END
  END o[313]
  PIN o[314]
    DIRECTION OUTPUT ;
    USE SIGNAL ;
    PORT
      LAYER M5 ;
        RECT  37.488 86.316 37.512 86.4 ;
    END
  END o[314]
  PIN o[315]
    DIRECTION OUTPUT ;
    USE SIGNAL ;
    PORT
      LAYER M5 ;
        RECT  37.584 86.316 37.608 86.4 ;
    END
  END o[315]
  PIN o[316]
    DIRECTION OUTPUT ;
    USE SIGNAL ;
    PORT
      LAYER M5 ;
        RECT  37.68 86.316 37.704 86.4 ;
    END
  END o[316]
  PIN o[317]
    DIRECTION OUTPUT ;
    USE SIGNAL ;
    PORT
      LAYER M5 ;
        RECT  37.776 86.316 37.8 86.4 ;
    END
  END o[317]
  PIN o[318]
    DIRECTION OUTPUT ;
    USE SIGNAL ;
    PORT
      LAYER M5 ;
        RECT  37.872 86.316 37.896 86.4 ;
    END
  END o[318]
  PIN o[319]
    DIRECTION OUTPUT ;
    USE SIGNAL ;
    PORT
      LAYER M5 ;
        RECT  37.968 86.316 37.992 86.4 ;
    END
  END o[319]
  PIN o[31]
    DIRECTION OUTPUT ;
    USE SIGNAL ;
    PORT
      LAYER M5 ;
        RECT  34.896 86.316 34.92 86.4 ;
    END
  END o[31]
  PIN o[320]
    DIRECTION OUTPUT ;
    USE SIGNAL ;
    PORT
      LAYER M5 ;
        RECT  28.848 86.316 28.872 86.4 ;
    END
  END o[320]
  PIN o[321]
    DIRECTION OUTPUT ;
    USE SIGNAL ;
    PORT
      LAYER M5 ;
        RECT  28.944 86.316 28.968 86.4 ;
    END
  END o[321]
  PIN o[322]
    DIRECTION OUTPUT ;
    USE SIGNAL ;
    PORT
      LAYER M5 ;
        RECT  29.04 86.316 29.064 86.4 ;
    END
  END o[322]
  PIN o[323]
    DIRECTION OUTPUT ;
    USE SIGNAL ;
    PORT
      LAYER M5 ;
        RECT  29.136 86.316 29.16 86.4 ;
    END
  END o[323]
  PIN o[324]
    DIRECTION OUTPUT ;
    USE SIGNAL ;
    PORT
      LAYER M5 ;
        RECT  29.232 86.316 29.256 86.4 ;
    END
  END o[324]
  PIN o[325]
    DIRECTION OUTPUT ;
    USE SIGNAL ;
    PORT
      LAYER M5 ;
        RECT  29.328 86.316 29.352 86.4 ;
    END
  END o[325]
  PIN o[326]
    DIRECTION OUTPUT ;
    USE SIGNAL ;
    PORT
      LAYER M5 ;
        RECT  29.424 86.316 29.448 86.4 ;
    END
  END o[326]
  PIN o[327]
    DIRECTION OUTPUT ;
    USE SIGNAL ;
    PORT
      LAYER M5 ;
        RECT  29.52 86.316 29.544 86.4 ;
    END
  END o[327]
  PIN o[328]
    DIRECTION OUTPUT ;
    USE SIGNAL ;
    PORT
      LAYER M5 ;
        RECT  29.616 86.316 29.64 86.4 ;
    END
  END o[328]
  PIN o[329]
    DIRECTION OUTPUT ;
    USE SIGNAL ;
    PORT
      LAYER M5 ;
        RECT  29.712 86.316 29.736 86.4 ;
    END
  END o[329]
  PIN o[32]
    DIRECTION OUTPUT ;
    USE SIGNAL ;
    PORT
      LAYER M5 ;
        RECT  57.264 86.316 57.288 86.4 ;
    END
  END o[32]
  PIN o[330]
    DIRECTION OUTPUT ;
    USE SIGNAL ;
    PORT
      LAYER M5 ;
        RECT  29.808 86.316 29.832 86.4 ;
    END
  END o[330]
  PIN o[331]
    DIRECTION OUTPUT ;
    USE SIGNAL ;
    PORT
      LAYER M5 ;
        RECT  29.904 86.316 29.928 86.4 ;
    END
  END o[331]
  PIN o[332]
    DIRECTION OUTPUT ;
    USE SIGNAL ;
    PORT
      LAYER M5 ;
        RECT  30 86.316 30.024 86.4 ;
    END
  END o[332]
  PIN o[333]
    DIRECTION OUTPUT ;
    USE SIGNAL ;
    PORT
      LAYER M5 ;
        RECT  30.096 86.316 30.12 86.4 ;
    END
  END o[333]
  PIN o[334]
    DIRECTION OUTPUT ;
    USE SIGNAL ;
    PORT
      LAYER M5 ;
        RECT  30.192 86.316 30.216 86.4 ;
    END
  END o[334]
  PIN o[335]
    DIRECTION OUTPUT ;
    USE SIGNAL ;
    PORT
      LAYER M5 ;
        RECT  30.288 86.316 30.312 86.4 ;
    END
  END o[335]
  PIN o[336]
    DIRECTION OUTPUT ;
    USE SIGNAL ;
    PORT
      LAYER M5 ;
        RECT  30.384 86.316 30.408 86.4 ;
    END
  END o[336]
  PIN o[337]
    DIRECTION OUTPUT ;
    USE SIGNAL ;
    PORT
      LAYER M5 ;
        RECT  30.48 86.316 30.504 86.4 ;
    END
  END o[337]
  PIN o[338]
    DIRECTION OUTPUT ;
    USE SIGNAL ;
    PORT
      LAYER M5 ;
        RECT  30.576 86.316 30.6 86.4 ;
    END
  END o[338]
  PIN o[339]
    DIRECTION OUTPUT ;
    USE SIGNAL ;
    PORT
      LAYER M5 ;
        RECT  30.672 86.316 30.696 86.4 ;
    END
  END o[339]
  PIN o[33]
    DIRECTION OUTPUT ;
    USE SIGNAL ;
    PORT
      LAYER M5 ;
        RECT  57.36 86.316 57.384 86.4 ;
    END
  END o[33]
  PIN o[340]
    DIRECTION OUTPUT ;
    USE SIGNAL ;
    PORT
      LAYER M5 ;
        RECT  30.768 86.316 30.792 86.4 ;
    END
  END o[340]
  PIN o[341]
    DIRECTION OUTPUT ;
    USE SIGNAL ;
    PORT
      LAYER M5 ;
        RECT  30.864 86.316 30.888 86.4 ;
    END
  END o[341]
  PIN o[342]
    DIRECTION OUTPUT ;
    USE SIGNAL ;
    PORT
      LAYER M5 ;
        RECT  30.96 86.316 30.984 86.4 ;
    END
  END o[342]
  PIN o[343]
    DIRECTION OUTPUT ;
    USE SIGNAL ;
    PORT
      LAYER M5 ;
        RECT  31.056 86.316 31.08 86.4 ;
    END
  END o[343]
  PIN o[344]
    DIRECTION OUTPUT ;
    USE SIGNAL ;
    PORT
      LAYER M5 ;
        RECT  31.152 86.316 31.176 86.4 ;
    END
  END o[344]
  PIN o[345]
    DIRECTION OUTPUT ;
    USE SIGNAL ;
    PORT
      LAYER M5 ;
        RECT  31.248 86.316 31.272 86.4 ;
    END
  END o[345]
  PIN o[346]
    DIRECTION OUTPUT ;
    USE SIGNAL ;
    PORT
      LAYER M5 ;
        RECT  31.344 86.316 31.368 86.4 ;
    END
  END o[346]
  PIN o[347]
    DIRECTION OUTPUT ;
    USE SIGNAL ;
    PORT
      LAYER M5 ;
        RECT  31.44 86.316 31.464 86.4 ;
    END
  END o[347]
  PIN o[348]
    DIRECTION OUTPUT ;
    USE SIGNAL ;
    PORT
      LAYER M5 ;
        RECT  31.536 86.316 31.56 86.4 ;
    END
  END o[348]
  PIN o[349]
    DIRECTION OUTPUT ;
    USE SIGNAL ;
    PORT
      LAYER M5 ;
        RECT  31.632 86.316 31.656 86.4 ;
    END
  END o[349]
  PIN o[34]
    DIRECTION OUTPUT ;
    USE SIGNAL ;
    PORT
      LAYER M5 ;
        RECT  57.456 86.316 57.48 86.4 ;
    END
  END o[34]
  PIN o[350]
    DIRECTION OUTPUT ;
    USE SIGNAL ;
    PORT
      LAYER M5 ;
        RECT  31.728 86.316 31.752 86.4 ;
    END
  END o[350]
  PIN o[351]
    DIRECTION OUTPUT ;
    USE SIGNAL ;
    PORT
      LAYER M5 ;
        RECT  31.824 86.316 31.848 86.4 ;
    END
  END o[351]
  PIN o[352]
    DIRECTION OUTPUT ;
    USE SIGNAL ;
    PORT
      LAYER M5 ;
        RECT  38.064 86.316 38.088 86.4 ;
    END
  END o[352]
  PIN o[353]
    DIRECTION OUTPUT ;
    USE SIGNAL ;
    PORT
      LAYER M5 ;
        RECT  38.16 86.316 38.184 86.4 ;
    END
  END o[353]
  PIN o[354]
    DIRECTION OUTPUT ;
    USE SIGNAL ;
    PORT
      LAYER M5 ;
        RECT  38.256 86.316 38.28 86.4 ;
    END
  END o[354]
  PIN o[355]
    DIRECTION OUTPUT ;
    USE SIGNAL ;
    PORT
      LAYER M5 ;
        RECT  38.352 86.316 38.376 86.4 ;
    END
  END o[355]
  PIN o[356]
    DIRECTION OUTPUT ;
    USE SIGNAL ;
    PORT
      LAYER M5 ;
        RECT  38.448 86.316 38.472 86.4 ;
    END
  END o[356]
  PIN o[357]
    DIRECTION OUTPUT ;
    USE SIGNAL ;
    PORT
      LAYER M5 ;
        RECT  38.544 86.316 38.568 86.4 ;
    END
  END o[357]
  PIN o[358]
    DIRECTION OUTPUT ;
    USE SIGNAL ;
    PORT
      LAYER M5 ;
        RECT  38.64 86.316 38.664 86.4 ;
    END
  END o[358]
  PIN o[359]
    DIRECTION OUTPUT ;
    USE SIGNAL ;
    PORT
      LAYER M5 ;
        RECT  38.736 86.316 38.76 86.4 ;
    END
  END o[359]
  PIN o[35]
    DIRECTION OUTPUT ;
    USE SIGNAL ;
    PORT
      LAYER M5 ;
        RECT  57.552 86.316 57.576 86.4 ;
    END
  END o[35]
  PIN o[360]
    DIRECTION OUTPUT ;
    USE SIGNAL ;
    PORT
      LAYER M5 ;
        RECT  38.832 86.316 38.856 86.4 ;
    END
  END o[360]
  PIN o[361]
    DIRECTION OUTPUT ;
    USE SIGNAL ;
    PORT
      LAYER M5 ;
        RECT  38.928 86.316 38.952 86.4 ;
    END
  END o[361]
  PIN o[362]
    DIRECTION OUTPUT ;
    USE SIGNAL ;
    PORT
      LAYER M5 ;
        RECT  39.024 86.316 39.048 86.4 ;
    END
  END o[362]
  PIN o[363]
    DIRECTION OUTPUT ;
    USE SIGNAL ;
    PORT
      LAYER M5 ;
        RECT  39.12 86.316 39.144 86.4 ;
    END
  END o[363]
  PIN o[364]
    DIRECTION OUTPUT ;
    USE SIGNAL ;
    PORT
      LAYER M5 ;
        RECT  39.216 86.316 39.24 86.4 ;
    END
  END o[364]
  PIN o[365]
    DIRECTION OUTPUT ;
    USE SIGNAL ;
    PORT
      LAYER M5 ;
        RECT  39.312 86.316 39.336 86.4 ;
    END
  END o[365]
  PIN o[366]
    DIRECTION OUTPUT ;
    USE SIGNAL ;
    PORT
      LAYER M5 ;
        RECT  39.408 86.316 39.432 86.4 ;
    END
  END o[366]
  PIN o[367]
    DIRECTION OUTPUT ;
    USE SIGNAL ;
    PORT
      LAYER M5 ;
        RECT  39.504 86.316 39.528 86.4 ;
    END
  END o[367]
  PIN o[368]
    DIRECTION OUTPUT ;
    USE SIGNAL ;
    PORT
      LAYER M5 ;
        RECT  39.6 86.316 39.624 86.4 ;
    END
  END o[368]
  PIN o[369]
    DIRECTION OUTPUT ;
    USE SIGNAL ;
    PORT
      LAYER M5 ;
        RECT  39.696 86.316 39.72 86.4 ;
    END
  END o[369]
  PIN o[36]
    DIRECTION OUTPUT ;
    USE SIGNAL ;
    PORT
      LAYER M5 ;
        RECT  57.648 86.316 57.672 86.4 ;
    END
  END o[36]
  PIN o[370]
    DIRECTION OUTPUT ;
    USE SIGNAL ;
    PORT
      LAYER M5 ;
        RECT  39.792 86.316 39.816 86.4 ;
    END
  END o[370]
  PIN o[371]
    DIRECTION OUTPUT ;
    USE SIGNAL ;
    PORT
      LAYER M5 ;
        RECT  39.888 86.316 39.912 86.4 ;
    END
  END o[371]
  PIN o[372]
    DIRECTION OUTPUT ;
    USE SIGNAL ;
    PORT
      LAYER M5 ;
        RECT  39.984 86.316 40.008 86.4 ;
    END
  END o[372]
  PIN o[373]
    DIRECTION OUTPUT ;
    USE SIGNAL ;
    PORT
      LAYER M5 ;
        RECT  40.08 86.316 40.104 86.4 ;
    END
  END o[373]
  PIN o[374]
    DIRECTION OUTPUT ;
    USE SIGNAL ;
    PORT
      LAYER M5 ;
        RECT  40.176 86.316 40.2 86.4 ;
    END
  END o[374]
  PIN o[375]
    DIRECTION OUTPUT ;
    USE SIGNAL ;
    PORT
      LAYER M5 ;
        RECT  40.272 86.316 40.296 86.4 ;
    END
  END o[375]
  PIN o[376]
    DIRECTION OUTPUT ;
    USE SIGNAL ;
    PORT
      LAYER M5 ;
        RECT  40.368 86.316 40.392 86.4 ;
    END
  END o[376]
  PIN o[377]
    DIRECTION OUTPUT ;
    USE SIGNAL ;
    PORT
      LAYER M5 ;
        RECT  40.464 86.316 40.488 86.4 ;
    END
  END o[377]
  PIN o[378]
    DIRECTION OUTPUT ;
    USE SIGNAL ;
    PORT
      LAYER M5 ;
        RECT  40.56 86.316 40.584 86.4 ;
    END
  END o[378]
  PIN o[379]
    DIRECTION OUTPUT ;
    USE SIGNAL ;
    PORT
      LAYER M5 ;
        RECT  40.656 86.316 40.68 86.4 ;
    END
  END o[379]
  PIN o[37]
    DIRECTION OUTPUT ;
    USE SIGNAL ;
    PORT
      LAYER M5 ;
        RECT  57.744 86.316 57.768 86.4 ;
    END
  END o[37]
  PIN o[380]
    DIRECTION OUTPUT ;
    USE SIGNAL ;
    PORT
      LAYER M5 ;
        RECT  40.752 86.316 40.776 86.4 ;
    END
  END o[380]
  PIN o[381]
    DIRECTION OUTPUT ;
    USE SIGNAL ;
    PORT
      LAYER M5 ;
        RECT  40.848 86.316 40.872 86.4 ;
    END
  END o[381]
  PIN o[382]
    DIRECTION OUTPUT ;
    USE SIGNAL ;
    PORT
      LAYER M5 ;
        RECT  40.944 86.316 40.968 86.4 ;
    END
  END o[382]
  PIN o[383]
    DIRECTION OUTPUT ;
    USE SIGNAL ;
    PORT
      LAYER M5 ;
        RECT  41.04 86.316 41.064 86.4 ;
    END
  END o[383]
  PIN o[384]
    DIRECTION OUTPUT ;
    USE SIGNAL ;
    PORT
      LAYER M5 ;
        RECT  15.792 86.316 15.816 86.4 ;
    END
  END o[384]
  PIN o[385]
    DIRECTION OUTPUT ;
    USE SIGNAL ;
    PORT
      LAYER M5 ;
        RECT  15.888 86.316 15.912 86.4 ;
    END
  END o[385]
  PIN o[386]
    DIRECTION OUTPUT ;
    USE SIGNAL ;
    PORT
      LAYER M5 ;
        RECT  15.984 86.316 16.008 86.4 ;
    END
  END o[386]
  PIN o[387]
    DIRECTION OUTPUT ;
    USE SIGNAL ;
    PORT
      LAYER M5 ;
        RECT  16.08 86.316 16.104 86.4 ;
    END
  END o[387]
  PIN o[388]
    DIRECTION OUTPUT ;
    USE SIGNAL ;
    PORT
      LAYER M5 ;
        RECT  16.176 86.316 16.2 86.4 ;
    END
  END o[388]
  PIN o[389]
    DIRECTION OUTPUT ;
    USE SIGNAL ;
    PORT
      LAYER M5 ;
        RECT  16.272 86.316 16.296 86.4 ;
    END
  END o[389]
  PIN o[38]
    DIRECTION OUTPUT ;
    USE SIGNAL ;
    PORT
      LAYER M5 ;
        RECT  57.84 86.316 57.864 86.4 ;
    END
  END o[38]
  PIN o[390]
    DIRECTION OUTPUT ;
    USE SIGNAL ;
    PORT
      LAYER M5 ;
        RECT  16.368 86.316 16.392 86.4 ;
    END
  END o[390]
  PIN o[391]
    DIRECTION OUTPUT ;
    USE SIGNAL ;
    PORT
      LAYER M5 ;
        RECT  16.464 86.316 16.488 86.4 ;
    END
  END o[391]
  PIN o[392]
    DIRECTION OUTPUT ;
    USE SIGNAL ;
    PORT
      LAYER M5 ;
        RECT  16.56 86.316 16.584 86.4 ;
    END
  END o[392]
  PIN o[393]
    DIRECTION OUTPUT ;
    USE SIGNAL ;
    PORT
      LAYER M5 ;
        RECT  16.656 86.316 16.68 86.4 ;
    END
  END o[393]
  PIN o[394]
    DIRECTION OUTPUT ;
    USE SIGNAL ;
    PORT
      LAYER M5 ;
        RECT  16.752 86.316 16.776 86.4 ;
    END
  END o[394]
  PIN o[395]
    DIRECTION OUTPUT ;
    USE SIGNAL ;
    PORT
      LAYER M5 ;
        RECT  16.848 86.316 16.872 86.4 ;
    END
  END o[395]
  PIN o[396]
    DIRECTION OUTPUT ;
    USE SIGNAL ;
    PORT
      LAYER M5 ;
        RECT  16.944 86.316 16.968 86.4 ;
    END
  END o[396]
  PIN o[397]
    DIRECTION OUTPUT ;
    USE SIGNAL ;
    PORT
      LAYER M5 ;
        RECT  17.04 86.316 17.064 86.4 ;
    END
  END o[397]
  PIN o[398]
    DIRECTION OUTPUT ;
    USE SIGNAL ;
    PORT
      LAYER M5 ;
        RECT  17.136 86.316 17.16 86.4 ;
    END
  END o[398]
  PIN o[399]
    DIRECTION OUTPUT ;
    USE SIGNAL ;
    PORT
      LAYER M5 ;
        RECT  17.232 86.316 17.256 86.4 ;
    END
  END o[399]
  PIN o[39]
    DIRECTION OUTPUT ;
    USE SIGNAL ;
    PORT
      LAYER M5 ;
        RECT  57.936 86.316 57.96 86.4 ;
    END
  END o[39]
  PIN o[3]
    DIRECTION OUTPUT ;
    USE SIGNAL ;
    PORT
      LAYER M5 ;
        RECT  32.208 86.316 32.232 86.4 ;
    END
  END o[3]
  PIN o[400]
    DIRECTION OUTPUT ;
    USE SIGNAL ;
    PORT
      LAYER M5 ;
        RECT  17.328 86.316 17.352 86.4 ;
    END
  END o[400]
  PIN o[401]
    DIRECTION OUTPUT ;
    USE SIGNAL ;
    PORT
      LAYER M5 ;
        RECT  17.424 86.316 17.448 86.4 ;
    END
  END o[401]
  PIN o[402]
    DIRECTION OUTPUT ;
    USE SIGNAL ;
    PORT
      LAYER M5 ;
        RECT  17.52 86.316 17.544 86.4 ;
    END
  END o[402]
  PIN o[403]
    DIRECTION OUTPUT ;
    USE SIGNAL ;
    PORT
      LAYER M5 ;
        RECT  17.616 86.316 17.64 86.4 ;
    END
  END o[403]
  PIN o[404]
    DIRECTION OUTPUT ;
    USE SIGNAL ;
    PORT
      LAYER M5 ;
        RECT  17.712 86.316 17.736 86.4 ;
    END
  END o[404]
  PIN o[405]
    DIRECTION OUTPUT ;
    USE SIGNAL ;
    PORT
      LAYER M5 ;
        RECT  17.808 86.316 17.832 86.4 ;
    END
  END o[405]
  PIN o[406]
    DIRECTION OUTPUT ;
    USE SIGNAL ;
    PORT
      LAYER M5 ;
        RECT  17.904 86.316 17.928 86.4 ;
    END
  END o[406]
  PIN o[407]
    DIRECTION OUTPUT ;
    USE SIGNAL ;
    PORT
      LAYER M5 ;
        RECT  18 86.316 18.024 86.4 ;
    END
  END o[407]
  PIN o[408]
    DIRECTION OUTPUT ;
    USE SIGNAL ;
    PORT
      LAYER M5 ;
        RECT  18.096 86.316 18.12 86.4 ;
    END
  END o[408]
  PIN o[409]
    DIRECTION OUTPUT ;
    USE SIGNAL ;
    PORT
      LAYER M5 ;
        RECT  18.192 86.316 18.216 86.4 ;
    END
  END o[409]
  PIN o[40]
    DIRECTION OUTPUT ;
    USE SIGNAL ;
    PORT
      LAYER M5 ;
        RECT  58.032 86.316 58.056 86.4 ;
    END
  END o[40]
  PIN o[410]
    DIRECTION OUTPUT ;
    USE SIGNAL ;
    PORT
      LAYER M5 ;
        RECT  18.288 86.316 18.312 86.4 ;
    END
  END o[410]
  PIN o[411]
    DIRECTION OUTPUT ;
    USE SIGNAL ;
    PORT
      LAYER M5 ;
        RECT  18.384 86.316 18.408 86.4 ;
    END
  END o[411]
  PIN o[412]
    DIRECTION OUTPUT ;
    USE SIGNAL ;
    PORT
      LAYER M5 ;
        RECT  18.48 86.316 18.504 86.4 ;
    END
  END o[412]
  PIN o[413]
    DIRECTION OUTPUT ;
    USE SIGNAL ;
    PORT
      LAYER M5 ;
        RECT  18.576 86.316 18.6 86.4 ;
    END
  END o[413]
  PIN o[414]
    DIRECTION OUTPUT ;
    USE SIGNAL ;
    PORT
      LAYER M5 ;
        RECT  18.672 86.316 18.696 86.4 ;
    END
  END o[414]
  PIN o[415]
    DIRECTION OUTPUT ;
    USE SIGNAL ;
    PORT
      LAYER M5 ;
        RECT  18.768 86.316 18.792 86.4 ;
    END
  END o[415]
  PIN o[416]
    DIRECTION OUTPUT ;
    USE SIGNAL ;
    PORT
      LAYER M5 ;
        RECT  18.864 86.316 18.888 86.4 ;
    END
  END o[416]
  PIN o[417]
    DIRECTION OUTPUT ;
    USE SIGNAL ;
    PORT
      LAYER M5 ;
        RECT  18.96 86.316 18.984 86.4 ;
    END
  END o[417]
  PIN o[418]
    DIRECTION OUTPUT ;
    USE SIGNAL ;
    PORT
      LAYER M5 ;
        RECT  19.056 86.316 19.08 86.4 ;
    END
  END o[418]
  PIN o[419]
    DIRECTION OUTPUT ;
    USE SIGNAL ;
    PORT
      LAYER M5 ;
        RECT  19.152 86.316 19.176 86.4 ;
    END
  END o[419]
  PIN o[41]
    DIRECTION OUTPUT ;
    USE SIGNAL ;
    PORT
      LAYER M5 ;
        RECT  58.128 86.316 58.152 86.4 ;
    END
  END o[41]
  PIN o[420]
    DIRECTION OUTPUT ;
    USE SIGNAL ;
    PORT
      LAYER M5 ;
        RECT  19.248 86.316 19.272 86.4 ;
    END
  END o[420]
  PIN o[421]
    DIRECTION OUTPUT ;
    USE SIGNAL ;
    PORT
      LAYER M5 ;
        RECT  19.344 86.316 19.368 86.4 ;
    END
  END o[421]
  PIN o[422]
    DIRECTION OUTPUT ;
    USE SIGNAL ;
    PORT
      LAYER M5 ;
        RECT  19.44 86.316 19.464 86.4 ;
    END
  END o[422]
  PIN o[423]
    DIRECTION OUTPUT ;
    USE SIGNAL ;
    PORT
      LAYER M5 ;
        RECT  19.536 86.316 19.56 86.4 ;
    END
  END o[423]
  PIN o[424]
    DIRECTION OUTPUT ;
    USE SIGNAL ;
    PORT
      LAYER M5 ;
        RECT  19.632 86.316 19.656 86.4 ;
    END
  END o[424]
  PIN o[425]
    DIRECTION OUTPUT ;
    USE SIGNAL ;
    PORT
      LAYER M5 ;
        RECT  19.728 86.316 19.752 86.4 ;
    END
  END o[425]
  PIN o[426]
    DIRECTION OUTPUT ;
    USE SIGNAL ;
    PORT
      LAYER M5 ;
        RECT  19.824 86.316 19.848 86.4 ;
    END
  END o[426]
  PIN o[427]
    DIRECTION OUTPUT ;
    USE SIGNAL ;
    PORT
      LAYER M5 ;
        RECT  19.92 86.316 19.944 86.4 ;
    END
  END o[427]
  PIN o[428]
    DIRECTION OUTPUT ;
    USE SIGNAL ;
    PORT
      LAYER M5 ;
        RECT  20.016 86.316 20.04 86.4 ;
    END
  END o[428]
  PIN o[429]
    DIRECTION OUTPUT ;
    USE SIGNAL ;
    PORT
      LAYER M5 ;
        RECT  20.112 86.316 20.136 86.4 ;
    END
  END o[429]
  PIN o[42]
    DIRECTION OUTPUT ;
    USE SIGNAL ;
    PORT
      LAYER M5 ;
        RECT  58.224 86.316 58.248 86.4 ;
    END
  END o[42]
  PIN o[430]
    DIRECTION OUTPUT ;
    USE SIGNAL ;
    PORT
      LAYER M5 ;
        RECT  20.208 86.316 20.232 86.4 ;
    END
  END o[430]
  PIN o[431]
    DIRECTION OUTPUT ;
    USE SIGNAL ;
    PORT
      LAYER M5 ;
        RECT  20.304 86.316 20.328 86.4 ;
    END
  END o[431]
  PIN o[432]
    DIRECTION OUTPUT ;
    USE SIGNAL ;
    PORT
      LAYER M5 ;
        RECT  20.4 86.316 20.424 86.4 ;
    END
  END o[432]
  PIN o[433]
    DIRECTION OUTPUT ;
    USE SIGNAL ;
    PORT
      LAYER M5 ;
        RECT  20.496 86.316 20.52 86.4 ;
    END
  END o[433]
  PIN o[434]
    DIRECTION OUTPUT ;
    USE SIGNAL ;
    PORT
      LAYER M5 ;
        RECT  20.592 86.316 20.616 86.4 ;
    END
  END o[434]
  PIN o[435]
    DIRECTION OUTPUT ;
    USE SIGNAL ;
    PORT
      LAYER M5 ;
        RECT  20.688 86.316 20.712 86.4 ;
    END
  END o[435]
  PIN o[436]
    DIRECTION OUTPUT ;
    USE SIGNAL ;
    PORT
      LAYER M5 ;
        RECT  20.784 86.316 20.808 86.4 ;
    END
  END o[436]
  PIN o[437]
    DIRECTION OUTPUT ;
    USE SIGNAL ;
    PORT
      LAYER M5 ;
        RECT  20.88 86.316 20.904 86.4 ;
    END
  END o[437]
  PIN o[438]
    DIRECTION OUTPUT ;
    USE SIGNAL ;
    PORT
      LAYER M5 ;
        RECT  20.976 86.316 21 86.4 ;
    END
  END o[438]
  PIN o[439]
    DIRECTION OUTPUT ;
    USE SIGNAL ;
    PORT
      LAYER M5 ;
        RECT  21.072 86.316 21.096 86.4 ;
    END
  END o[439]
  PIN o[43]
    DIRECTION OUTPUT ;
    USE SIGNAL ;
    PORT
      LAYER M5 ;
        RECT  58.32 86.316 58.344 86.4 ;
    END
  END o[43]
  PIN o[440]
    DIRECTION OUTPUT ;
    USE SIGNAL ;
    PORT
      LAYER M5 ;
        RECT  21.168 86.316 21.192 86.4 ;
    END
  END o[440]
  PIN o[441]
    DIRECTION OUTPUT ;
    USE SIGNAL ;
    PORT
      LAYER M5 ;
        RECT  21.264 86.316 21.288 86.4 ;
    END
  END o[441]
  PIN o[442]
    DIRECTION OUTPUT ;
    USE SIGNAL ;
    PORT
      LAYER M5 ;
        RECT  21.36 86.316 21.384 86.4 ;
    END
  END o[442]
  PIN o[443]
    DIRECTION OUTPUT ;
    USE SIGNAL ;
    PORT
      LAYER M5 ;
        RECT  21.456 86.316 21.48 86.4 ;
    END
  END o[443]
  PIN o[444]
    DIRECTION OUTPUT ;
    USE SIGNAL ;
    PORT
      LAYER M5 ;
        RECT  21.552 86.316 21.576 86.4 ;
    END
  END o[444]
  PIN o[445]
    DIRECTION OUTPUT ;
    USE SIGNAL ;
    PORT
      LAYER M5 ;
        RECT  21.648 86.316 21.672 86.4 ;
    END
  END o[445]
  PIN o[446]
    DIRECTION OUTPUT ;
    USE SIGNAL ;
    PORT
      LAYER M5 ;
        RECT  21.744 86.316 21.768 86.4 ;
    END
  END o[446]
  PIN o[447]
    DIRECTION OUTPUT ;
    USE SIGNAL ;
    PORT
      LAYER M5 ;
        RECT  21.84 86.316 21.864 86.4 ;
    END
  END o[447]
  PIN o[448]
    DIRECTION OUTPUT ;
    USE SIGNAL ;
    PORT
      LAYER M5 ;
        RECT  21.936 86.316 21.96 86.4 ;
    END
  END o[448]
  PIN o[449]
    DIRECTION OUTPUT ;
    USE SIGNAL ;
    PORT
      LAYER M5 ;
        RECT  22.032 86.316 22.056 86.4 ;
    END
  END o[449]
  PIN o[44]
    DIRECTION OUTPUT ;
    USE SIGNAL ;
    PORT
      LAYER M5 ;
        RECT  58.416 86.316 58.44 86.4 ;
    END
  END o[44]
  PIN o[450]
    DIRECTION OUTPUT ;
    USE SIGNAL ;
    PORT
      LAYER M5 ;
        RECT  22.128 86.316 22.152 86.4 ;
    END
  END o[450]
  PIN o[451]
    DIRECTION OUTPUT ;
    USE SIGNAL ;
    PORT
      LAYER M5 ;
        RECT  22.224 86.316 22.248 86.4 ;
    END
  END o[451]
  PIN o[452]
    DIRECTION OUTPUT ;
    USE SIGNAL ;
    PORT
      LAYER M5 ;
        RECT  22.32 86.316 22.344 86.4 ;
    END
  END o[452]
  PIN o[453]
    DIRECTION OUTPUT ;
    USE SIGNAL ;
    PORT
      LAYER M5 ;
        RECT  22.416 86.316 22.44 86.4 ;
    END
  END o[453]
  PIN o[454]
    DIRECTION OUTPUT ;
    USE SIGNAL ;
    PORT
      LAYER M5 ;
        RECT  22.512 86.316 22.536 86.4 ;
    END
  END o[454]
  PIN o[455]
    DIRECTION OUTPUT ;
    USE SIGNAL ;
    PORT
      LAYER M5 ;
        RECT  22.608 86.316 22.632 86.4 ;
    END
  END o[455]
  PIN o[456]
    DIRECTION OUTPUT ;
    USE SIGNAL ;
    PORT
      LAYER M5 ;
        RECT  22.704 86.316 22.728 86.4 ;
    END
  END o[456]
  PIN o[457]
    DIRECTION OUTPUT ;
    USE SIGNAL ;
    PORT
      LAYER M5 ;
        RECT  22.8 86.316 22.824 86.4 ;
    END
  END o[457]
  PIN o[458]
    DIRECTION OUTPUT ;
    USE SIGNAL ;
    PORT
      LAYER M5 ;
        RECT  22.896 86.316 22.92 86.4 ;
    END
  END o[458]
  PIN o[459]
    DIRECTION OUTPUT ;
    USE SIGNAL ;
    PORT
      LAYER M5 ;
        RECT  22.992 86.316 23.016 86.4 ;
    END
  END o[459]
  PIN o[45]
    DIRECTION OUTPUT ;
    USE SIGNAL ;
    PORT
      LAYER M5 ;
        RECT  58.512 86.316 58.536 86.4 ;
    END
  END o[45]
  PIN o[460]
    DIRECTION OUTPUT ;
    USE SIGNAL ;
    PORT
      LAYER M5 ;
        RECT  23.088 86.316 23.112 86.4 ;
    END
  END o[460]
  PIN o[461]
    DIRECTION OUTPUT ;
    USE SIGNAL ;
    PORT
      LAYER M5 ;
        RECT  23.184 86.316 23.208 86.4 ;
    END
  END o[461]
  PIN o[462]
    DIRECTION OUTPUT ;
    USE SIGNAL ;
    PORT
      LAYER M5 ;
        RECT  23.28 86.316 23.304 86.4 ;
    END
  END o[462]
  PIN o[463]
    DIRECTION OUTPUT ;
    USE SIGNAL ;
    PORT
      LAYER M5 ;
        RECT  23.376 86.316 23.4 86.4 ;
    END
  END o[463]
  PIN o[464]
    DIRECTION OUTPUT ;
    USE SIGNAL ;
    PORT
      LAYER M5 ;
        RECT  23.472 86.316 23.496 86.4 ;
    END
  END o[464]
  PIN o[465]
    DIRECTION OUTPUT ;
    USE SIGNAL ;
    PORT
      LAYER M5 ;
        RECT  23.568 86.316 23.592 86.4 ;
    END
  END o[465]
  PIN o[466]
    DIRECTION OUTPUT ;
    USE SIGNAL ;
    PORT
      LAYER M5 ;
        RECT  23.664 86.316 23.688 86.4 ;
    END
  END o[466]
  PIN o[467]
    DIRECTION OUTPUT ;
    USE SIGNAL ;
    PORT
      LAYER M5 ;
        RECT  23.76 86.316 23.784 86.4 ;
    END
  END o[467]
  PIN o[468]
    DIRECTION OUTPUT ;
    USE SIGNAL ;
    PORT
      LAYER M5 ;
        RECT  23.856 86.316 23.88 86.4 ;
    END
  END o[468]
  PIN o[469]
    DIRECTION OUTPUT ;
    USE SIGNAL ;
    PORT
      LAYER M5 ;
        RECT  23.952 86.316 23.976 86.4 ;
    END
  END o[469]
  PIN o[46]
    DIRECTION OUTPUT ;
    USE SIGNAL ;
    PORT
      LAYER M5 ;
        RECT  58.608 86.316 58.632 86.4 ;
    END
  END o[46]
  PIN o[470]
    DIRECTION OUTPUT ;
    USE SIGNAL ;
    PORT
      LAYER M5 ;
        RECT  24.048 86.316 24.072 86.4 ;
    END
  END o[470]
  PIN o[471]
    DIRECTION OUTPUT ;
    USE SIGNAL ;
    PORT
      LAYER M5 ;
        RECT  24.144 86.316 24.168 86.4 ;
    END
  END o[471]
  PIN o[472]
    DIRECTION OUTPUT ;
    USE SIGNAL ;
    PORT
      LAYER M5 ;
        RECT  24.24 86.316 24.264 86.4 ;
    END
  END o[472]
  PIN o[473]
    DIRECTION OUTPUT ;
    USE SIGNAL ;
    PORT
      LAYER M5 ;
        RECT  24.336 86.316 24.36 86.4 ;
    END
  END o[473]
  PIN o[474]
    DIRECTION OUTPUT ;
    USE SIGNAL ;
    PORT
      LAYER M5 ;
        RECT  24.432 86.316 24.456 86.4 ;
    END
  END o[474]
  PIN o[475]
    DIRECTION OUTPUT ;
    USE SIGNAL ;
    PORT
      LAYER M5 ;
        RECT  24.528 86.316 24.552 86.4 ;
    END
  END o[475]
  PIN o[476]
    DIRECTION OUTPUT ;
    USE SIGNAL ;
    PORT
      LAYER M5 ;
        RECT  24.624 86.316 24.648 86.4 ;
    END
  END o[476]
  PIN o[477]
    DIRECTION OUTPUT ;
    USE SIGNAL ;
    PORT
      LAYER M5 ;
        RECT  24.72 86.316 24.744 86.4 ;
    END
  END o[477]
  PIN o[478]
    DIRECTION OUTPUT ;
    USE SIGNAL ;
    PORT
      LAYER M5 ;
        RECT  24.816 86.316 24.84 86.4 ;
    END
  END o[478]
  PIN o[479]
    DIRECTION OUTPUT ;
    USE SIGNAL ;
    PORT
      LAYER M5 ;
        RECT  24.912 86.316 24.936 86.4 ;
    END
  END o[479]
  PIN o[47]
    DIRECTION OUTPUT ;
    USE SIGNAL ;
    PORT
      LAYER M5 ;
        RECT  58.704 86.316 58.728 86.4 ;
    END
  END o[47]
  PIN o[480]
    DIRECTION OUTPUT ;
    USE SIGNAL ;
    PORT
      LAYER M5 ;
        RECT  25.008 86.316 25.032 86.4 ;
    END
  END o[480]
  PIN o[481]
    DIRECTION OUTPUT ;
    USE SIGNAL ;
    PORT
      LAYER M5 ;
        RECT  25.104 86.316 25.128 86.4 ;
    END
  END o[481]
  PIN o[482]
    DIRECTION OUTPUT ;
    USE SIGNAL ;
    PORT
      LAYER M5 ;
        RECT  25.2 86.316 25.224 86.4 ;
    END
  END o[482]
  PIN o[483]
    DIRECTION OUTPUT ;
    USE SIGNAL ;
    PORT
      LAYER M5 ;
        RECT  25.296 86.316 25.32 86.4 ;
    END
  END o[483]
  PIN o[484]
    DIRECTION OUTPUT ;
    USE SIGNAL ;
    PORT
      LAYER M5 ;
        RECT  25.392 86.316 25.416 86.4 ;
    END
  END o[484]
  PIN o[485]
    DIRECTION OUTPUT ;
    USE SIGNAL ;
    PORT
      LAYER M5 ;
        RECT  25.488 86.316 25.512 86.4 ;
    END
  END o[485]
  PIN o[486]
    DIRECTION OUTPUT ;
    USE SIGNAL ;
    PORT
      LAYER M5 ;
        RECT  25.584 86.316 25.608 86.4 ;
    END
  END o[486]
  PIN o[487]
    DIRECTION OUTPUT ;
    USE SIGNAL ;
    PORT
      LAYER M5 ;
        RECT  25.68 86.316 25.704 86.4 ;
    END
  END o[487]
  PIN o[488]
    DIRECTION OUTPUT ;
    USE SIGNAL ;
    PORT
      LAYER M5 ;
        RECT  25.776 86.316 25.8 86.4 ;
    END
  END o[488]
  PIN o[489]
    DIRECTION OUTPUT ;
    USE SIGNAL ;
    PORT
      LAYER M5 ;
        RECT  25.872 86.316 25.896 86.4 ;
    END
  END o[489]
  PIN o[48]
    DIRECTION OUTPUT ;
    USE SIGNAL ;
    PORT
      LAYER M5 ;
        RECT  58.8 86.316 58.824 86.4 ;
    END
  END o[48]
  PIN o[490]
    DIRECTION OUTPUT ;
    USE SIGNAL ;
    PORT
      LAYER M5 ;
        RECT  25.968 86.316 25.992 86.4 ;
    END
  END o[490]
  PIN o[491]
    DIRECTION OUTPUT ;
    USE SIGNAL ;
    PORT
      LAYER M5 ;
        RECT  26.064 86.316 26.088 86.4 ;
    END
  END o[491]
  PIN o[492]
    DIRECTION OUTPUT ;
    USE SIGNAL ;
    PORT
      LAYER M5 ;
        RECT  26.16 86.316 26.184 86.4 ;
    END
  END o[492]
  PIN o[493]
    DIRECTION OUTPUT ;
    USE SIGNAL ;
    PORT
      LAYER M5 ;
        RECT  26.256 86.316 26.28 86.4 ;
    END
  END o[493]
  PIN o[494]
    DIRECTION OUTPUT ;
    USE SIGNAL ;
    PORT
      LAYER M5 ;
        RECT  26.352 86.316 26.376 86.4 ;
    END
  END o[494]
  PIN o[495]
    DIRECTION OUTPUT ;
    USE SIGNAL ;
    PORT
      LAYER M5 ;
        RECT  26.448 86.316 26.472 86.4 ;
    END
  END o[495]
  PIN o[496]
    DIRECTION OUTPUT ;
    USE SIGNAL ;
    PORT
      LAYER M5 ;
        RECT  26.544 86.316 26.568 86.4 ;
    END
  END o[496]
  PIN o[497]
    DIRECTION OUTPUT ;
    USE SIGNAL ;
    PORT
      LAYER M5 ;
        RECT  26.64 86.316 26.664 86.4 ;
    END
  END o[497]
  PIN o[498]
    DIRECTION OUTPUT ;
    USE SIGNAL ;
    PORT
      LAYER M5 ;
        RECT  26.736 86.316 26.76 86.4 ;
    END
  END o[498]
  PIN o[499]
    DIRECTION OUTPUT ;
    USE SIGNAL ;
    PORT
      LAYER M5 ;
        RECT  26.832 86.316 26.856 86.4 ;
    END
  END o[499]
  PIN o[49]
    DIRECTION OUTPUT ;
    USE SIGNAL ;
    PORT
      LAYER M5 ;
        RECT  58.896 86.316 58.92 86.4 ;
    END
  END o[49]
  PIN o[4]
    DIRECTION OUTPUT ;
    USE SIGNAL ;
    PORT
      LAYER M5 ;
        RECT  32.304 86.316 32.328 86.4 ;
    END
  END o[4]
  PIN o[500]
    DIRECTION OUTPUT ;
    USE SIGNAL ;
    PORT
      LAYER M5 ;
        RECT  26.928 86.316 26.952 86.4 ;
    END
  END o[500]
  PIN o[501]
    DIRECTION OUTPUT ;
    USE SIGNAL ;
    PORT
      LAYER M5 ;
        RECT  27.024 86.316 27.048 86.4 ;
    END
  END o[501]
  PIN o[502]
    DIRECTION OUTPUT ;
    USE SIGNAL ;
    PORT
      LAYER M5 ;
        RECT  27.12 86.316 27.144 86.4 ;
    END
  END o[502]
  PIN o[503]
    DIRECTION OUTPUT ;
    USE SIGNAL ;
    PORT
      LAYER M5 ;
        RECT  27.216 86.316 27.24 86.4 ;
    END
  END o[503]
  PIN o[504]
    DIRECTION OUTPUT ;
    USE SIGNAL ;
    PORT
      LAYER M5 ;
        RECT  27.312 86.316 27.336 86.4 ;
    END
  END o[504]
  PIN o[505]
    DIRECTION OUTPUT ;
    USE SIGNAL ;
    PORT
      LAYER M5 ;
        RECT  27.408 86.316 27.432 86.4 ;
    END
  END o[505]
  PIN o[506]
    DIRECTION OUTPUT ;
    USE SIGNAL ;
    PORT
      LAYER M5 ;
        RECT  27.504 86.316 27.528 86.4 ;
    END
  END o[506]
  PIN o[507]
    DIRECTION OUTPUT ;
    USE SIGNAL ;
    PORT
      LAYER M5 ;
        RECT  27.6 86.316 27.624 86.4 ;
    END
  END o[507]
  PIN o[508]
    DIRECTION OUTPUT ;
    USE SIGNAL ;
    PORT
      LAYER M5 ;
        RECT  27.696 86.316 27.72 86.4 ;
    END
  END o[508]
  PIN o[509]
    DIRECTION OUTPUT ;
    USE SIGNAL ;
    PORT
      LAYER M5 ;
        RECT  27.792 86.316 27.816 86.4 ;
    END
  END o[509]
  PIN o[50]
    DIRECTION OUTPUT ;
    USE SIGNAL ;
    PORT
      LAYER M5 ;
        RECT  58.992 86.316 59.016 86.4 ;
    END
  END o[50]
  PIN o[510]
    DIRECTION OUTPUT ;
    USE SIGNAL ;
    PORT
      LAYER M5 ;
        RECT  27.888 86.316 27.912 86.4 ;
    END
  END o[510]
  PIN o[511]
    DIRECTION OUTPUT ;
    USE SIGNAL ;
    PORT
      LAYER M5 ;
        RECT  27.984 86.316 28.008 86.4 ;
    END
  END o[511]
  PIN o[512]
    DIRECTION OUTPUT ;
    USE SIGNAL ;
    PORT
      LAYER M5 ;
        RECT  14.16 86.316 14.184 86.4 ;
    END
  END o[512]
  PIN o[513]
    DIRECTION OUTPUT ;
    USE SIGNAL ;
    PORT
      LAYER M5 ;
        RECT  14.256 86.316 14.28 86.4 ;
    END
  END o[513]
  PIN o[514]
    DIRECTION OUTPUT ;
    USE SIGNAL ;
    PORT
      LAYER M5 ;
        RECT  14.352 86.316 14.376 86.4 ;
    END
  END o[514]
  PIN o[515]
    DIRECTION OUTPUT ;
    USE SIGNAL ;
    PORT
      LAYER M5 ;
        RECT  14.448 86.316 14.472 86.4 ;
    END
  END o[515]
  PIN o[516]
    DIRECTION OUTPUT ;
    USE SIGNAL ;
    PORT
      LAYER M5 ;
        RECT  14.544 86.316 14.568 86.4 ;
    END
  END o[516]
  PIN o[517]
    DIRECTION OUTPUT ;
    USE SIGNAL ;
    PORT
      LAYER M5 ;
        RECT  14.64 86.316 14.664 86.4 ;
    END
  END o[517]
  PIN o[518]
    DIRECTION OUTPUT ;
    USE SIGNAL ;
    PORT
      LAYER M5 ;
        RECT  14.736 86.316 14.76 86.4 ;
    END
  END o[518]
  PIN o[519]
    DIRECTION OUTPUT ;
    USE SIGNAL ;
    PORT
      LAYER M5 ;
        RECT  14.832 86.316 14.856 86.4 ;
    END
  END o[519]
  PIN o[51]
    DIRECTION OUTPUT ;
    USE SIGNAL ;
    PORT
      LAYER M5 ;
        RECT  59.088 86.316 59.112 86.4 ;
    END
  END o[51]
  PIN o[520]
    DIRECTION OUTPUT ;
    USE SIGNAL ;
    PORT
      LAYER M5 ;
        RECT  14.928 86.316 14.952 86.4 ;
    END
  END o[520]
  PIN o[521]
    DIRECTION OUTPUT ;
    USE SIGNAL ;
    PORT
      LAYER M5 ;
        RECT  15.024 86.316 15.048 86.4 ;
    END
  END o[521]
  PIN o[522]
    DIRECTION OUTPUT ;
    USE SIGNAL ;
    PORT
      LAYER M5 ;
        RECT  15.12 86.316 15.144 86.4 ;
    END
  END o[522]
  PIN o[523]
    DIRECTION OUTPUT ;
    USE SIGNAL ;
    PORT
      LAYER M5 ;
        RECT  15.216 86.316 15.24 86.4 ;
    END
  END o[523]
  PIN o[524]
    DIRECTION OUTPUT ;
    USE SIGNAL ;
    PORT
      LAYER M5 ;
        RECT  15.312 86.316 15.336 86.4 ;
    END
  END o[524]
  PIN o[525]
    DIRECTION OUTPUT ;
    USE SIGNAL ;
    PORT
      LAYER M5 ;
        RECT  15.408 86.316 15.432 86.4 ;
    END
  END o[525]
  PIN o[526]
    DIRECTION OUTPUT ;
    USE SIGNAL ;
    PORT
      LAYER M5 ;
        RECT  15.504 86.316 15.528 86.4 ;
    END
  END o[526]
  PIN o[527]
    DIRECTION OUTPUT ;
    USE SIGNAL ;
    PORT
      LAYER M5 ;
        RECT  15.6 86.316 15.624 86.4 ;
    END
  END o[527]
  PIN o[528]
    DIRECTION OUTPUT ;
    USE SIGNAL ;
    PORT
      LAYER M5 ;
        RECT  15.696 86.316 15.72 86.4 ;
    END
  END o[528]
  PIN o[52]
    DIRECTION OUTPUT ;
    USE SIGNAL ;
    PORT
      LAYER M5 ;
        RECT  59.184 86.316 59.208 86.4 ;
    END
  END o[52]
  PIN o[53]
    DIRECTION OUTPUT ;
    USE SIGNAL ;
    PORT
      LAYER M5 ;
        RECT  59.28 86.316 59.304 86.4 ;
    END
  END o[53]
  PIN o[54]
    DIRECTION OUTPUT ;
    USE SIGNAL ;
    PORT
      LAYER M5 ;
        RECT  59.376 86.316 59.4 86.4 ;
    END
  END o[54]
  PIN o[55]
    DIRECTION OUTPUT ;
    USE SIGNAL ;
    PORT
      LAYER M5 ;
        RECT  59.472 86.316 59.496 86.4 ;
    END
  END o[55]
  PIN o[56]
    DIRECTION OUTPUT ;
    USE SIGNAL ;
    PORT
      LAYER M5 ;
        RECT  59.568 86.316 59.592 86.4 ;
    END
  END o[56]
  PIN o[57]
    DIRECTION OUTPUT ;
    USE SIGNAL ;
    PORT
      LAYER M5 ;
        RECT  59.664 86.316 59.688 86.4 ;
    END
  END o[57]
  PIN o[58]
    DIRECTION OUTPUT ;
    USE SIGNAL ;
    PORT
      LAYER M5 ;
        RECT  59.76 86.316 59.784 86.4 ;
    END
  END o[58]
  PIN o[59]
    DIRECTION OUTPUT ;
    USE SIGNAL ;
    PORT
      LAYER M5 ;
        RECT  59.856 86.316 59.88 86.4 ;
    END
  END o[59]
  PIN o[5]
    DIRECTION OUTPUT ;
    USE SIGNAL ;
    PORT
      LAYER M5 ;
        RECT  32.4 86.316 32.424 86.4 ;
    END
  END o[5]
  PIN o[60]
    DIRECTION OUTPUT ;
    USE SIGNAL ;
    PORT
      LAYER M5 ;
        RECT  59.952 86.316 59.976 86.4 ;
    END
  END o[60]
  PIN o[61]
    DIRECTION OUTPUT ;
    USE SIGNAL ;
    PORT
      LAYER M5 ;
        RECT  60.048 86.316 60.072 86.4 ;
    END
  END o[61]
  PIN o[62]
    DIRECTION OUTPUT ;
    USE SIGNAL ;
    PORT
      LAYER M5 ;
        RECT  60.144 86.316 60.168 86.4 ;
    END
  END o[62]
  PIN o[63]
    DIRECTION OUTPUT ;
    USE SIGNAL ;
    PORT
      LAYER M5 ;
        RECT  60.24 86.316 60.264 86.4 ;
    END
  END o[63]
  PIN o[64]
    DIRECTION OUTPUT ;
    USE SIGNAL ;
    PORT
      LAYER M5 ;
        RECT  51.12 86.316 51.144 86.4 ;
    END
  END o[64]
  PIN o[65]
    DIRECTION OUTPUT ;
    USE SIGNAL ;
    PORT
      LAYER M5 ;
        RECT  51.216 86.316 51.24 86.4 ;
    END
  END o[65]
  PIN o[66]
    DIRECTION OUTPUT ;
    USE SIGNAL ;
    PORT
      LAYER M5 ;
        RECT  51.312 86.316 51.336 86.4 ;
    END
  END o[66]
  PIN o[67]
    DIRECTION OUTPUT ;
    USE SIGNAL ;
    PORT
      LAYER M5 ;
        RECT  51.408 86.316 51.432 86.4 ;
    END
  END o[67]
  PIN o[68]
    DIRECTION OUTPUT ;
    USE SIGNAL ;
    PORT
      LAYER M5 ;
        RECT  51.504 86.316 51.528 86.4 ;
    END
  END o[68]
  PIN o[69]
    DIRECTION OUTPUT ;
    USE SIGNAL ;
    PORT
      LAYER M5 ;
        RECT  51.6 86.316 51.624 86.4 ;
    END
  END o[69]
  PIN o[6]
    DIRECTION OUTPUT ;
    USE SIGNAL ;
    PORT
      LAYER M5 ;
        RECT  32.496 86.316 32.52 86.4 ;
    END
  END o[6]
  PIN o[70]
    DIRECTION OUTPUT ;
    USE SIGNAL ;
    PORT
      LAYER M5 ;
        RECT  51.696 86.316 51.72 86.4 ;
    END
  END o[70]
  PIN o[71]
    DIRECTION OUTPUT ;
    USE SIGNAL ;
    PORT
      LAYER M5 ;
        RECT  51.792 86.316 51.816 86.4 ;
    END
  END o[71]
  PIN o[72]
    DIRECTION OUTPUT ;
    USE SIGNAL ;
    PORT
      LAYER M5 ;
        RECT  51.888 86.316 51.912 86.4 ;
    END
  END o[72]
  PIN o[73]
    DIRECTION OUTPUT ;
    USE SIGNAL ;
    PORT
      LAYER M5 ;
        RECT  51.984 86.316 52.008 86.4 ;
    END
  END o[73]
  PIN o[74]
    DIRECTION OUTPUT ;
    USE SIGNAL ;
    PORT
      LAYER M5 ;
        RECT  52.08 86.316 52.104 86.4 ;
    END
  END o[74]
  PIN o[75]
    DIRECTION OUTPUT ;
    USE SIGNAL ;
    PORT
      LAYER M5 ;
        RECT  52.176 86.316 52.2 86.4 ;
    END
  END o[75]
  PIN o[76]
    DIRECTION OUTPUT ;
    USE SIGNAL ;
    PORT
      LAYER M5 ;
        RECT  52.272 86.316 52.296 86.4 ;
    END
  END o[76]
  PIN o[77]
    DIRECTION OUTPUT ;
    USE SIGNAL ;
    PORT
      LAYER M5 ;
        RECT  52.368 86.316 52.392 86.4 ;
    END
  END o[77]
  PIN o[78]
    DIRECTION OUTPUT ;
    USE SIGNAL ;
    PORT
      LAYER M5 ;
        RECT  52.464 86.316 52.488 86.4 ;
    END
  END o[78]
  PIN o[79]
    DIRECTION OUTPUT ;
    USE SIGNAL ;
    PORT
      LAYER M5 ;
        RECT  52.56 86.316 52.584 86.4 ;
    END
  END o[79]
  PIN o[7]
    DIRECTION OUTPUT ;
    USE SIGNAL ;
    PORT
      LAYER M5 ;
        RECT  32.592 86.316 32.616 86.4 ;
    END
  END o[7]
  PIN o[80]
    DIRECTION OUTPUT ;
    USE SIGNAL ;
    PORT
      LAYER M5 ;
        RECT  52.656 86.316 52.68 86.4 ;
    END
  END o[80]
  PIN o[81]
    DIRECTION OUTPUT ;
    USE SIGNAL ;
    PORT
      LAYER M5 ;
        RECT  52.752 86.316 52.776 86.4 ;
    END
  END o[81]
  PIN o[82]
    DIRECTION OUTPUT ;
    USE SIGNAL ;
    PORT
      LAYER M5 ;
        RECT  52.848 86.316 52.872 86.4 ;
    END
  END o[82]
  PIN o[83]
    DIRECTION OUTPUT ;
    USE SIGNAL ;
    PORT
      LAYER M5 ;
        RECT  52.944 86.316 52.968 86.4 ;
    END
  END o[83]
  PIN o[84]
    DIRECTION OUTPUT ;
    USE SIGNAL ;
    PORT
      LAYER M5 ;
        RECT  53.04 86.316 53.064 86.4 ;
    END
  END o[84]
  PIN o[85]
    DIRECTION OUTPUT ;
    USE SIGNAL ;
    PORT
      LAYER M5 ;
        RECT  53.136 86.316 53.16 86.4 ;
    END
  END o[85]
  PIN o[86]
    DIRECTION OUTPUT ;
    USE SIGNAL ;
    PORT
      LAYER M5 ;
        RECT  53.232 86.316 53.256 86.4 ;
    END
  END o[86]
  PIN o[87]
    DIRECTION OUTPUT ;
    USE SIGNAL ;
    PORT
      LAYER M5 ;
        RECT  53.328 86.316 53.352 86.4 ;
    END
  END o[87]
  PIN o[88]
    DIRECTION OUTPUT ;
    USE SIGNAL ;
    PORT
      LAYER M5 ;
        RECT  53.424 86.316 53.448 86.4 ;
    END
  END o[88]
  PIN o[89]
    DIRECTION OUTPUT ;
    USE SIGNAL ;
    PORT
      LAYER M5 ;
        RECT  53.52 86.316 53.544 86.4 ;
    END
  END o[89]
  PIN o[8]
    DIRECTION OUTPUT ;
    USE SIGNAL ;
    PORT
      LAYER M5 ;
        RECT  32.688 86.316 32.712 86.4 ;
    END
  END o[8]
  PIN o[90]
    DIRECTION OUTPUT ;
    USE SIGNAL ;
    PORT
      LAYER M5 ;
        RECT  53.616 86.316 53.64 86.4 ;
    END
  END o[90]
  PIN o[91]
    DIRECTION OUTPUT ;
    USE SIGNAL ;
    PORT
      LAYER M5 ;
        RECT  53.712 86.316 53.736 86.4 ;
    END
  END o[91]
  PIN o[92]
    DIRECTION OUTPUT ;
    USE SIGNAL ;
    PORT
      LAYER M5 ;
        RECT  53.808 86.316 53.832 86.4 ;
    END
  END o[92]
  PIN o[93]
    DIRECTION OUTPUT ;
    USE SIGNAL ;
    PORT
      LAYER M5 ;
        RECT  53.904 86.316 53.928 86.4 ;
    END
  END o[93]
  PIN o[94]
    DIRECTION OUTPUT ;
    USE SIGNAL ;
    PORT
      LAYER M5 ;
        RECT  54 86.316 54.024 86.4 ;
    END
  END o[94]
  PIN o[95]
    DIRECTION OUTPUT ;
    USE SIGNAL ;
    PORT
      LAYER M5 ;
        RECT  54.096 86.316 54.12 86.4 ;
    END
  END o[95]
  PIN o[96]
    DIRECTION OUTPUT ;
    USE SIGNAL ;
    PORT
      LAYER M5 ;
        RECT  63.408 86.316 63.432 86.4 ;
    END
  END o[96]
  PIN o[97]
    DIRECTION OUTPUT ;
    USE SIGNAL ;
    PORT
      LAYER M5 ;
        RECT  63.504 86.316 63.528 86.4 ;
    END
  END o[97]
  PIN o[98]
    DIRECTION OUTPUT ;
    USE SIGNAL ;
    PORT
      LAYER M5 ;
        RECT  63.6 86.316 63.624 86.4 ;
    END
  END o[98]
  PIN o[99]
    DIRECTION OUTPUT ;
    USE SIGNAL ;
    PORT
      LAYER M5 ;
        RECT  63.696 86.316 63.72 86.4 ;
    END
  END o[99]
  PIN o[9]
    DIRECTION OUTPUT ;
    USE SIGNAL ;
    PORT
      LAYER M5 ;
        RECT  32.784 86.316 32.808 86.4 ;
    END
  END o[9]
  PIN oflt[0]
    DIRECTION INPUT ;
    USE SIGNAL ;
    PORT
      LAYER M4 ;
        RECT  0 36.624 0.084 36.648 ;
    END
  END oflt[0]
  PIN oflt[10]
    DIRECTION INPUT ;
    USE SIGNAL ;
    PORT
      LAYER M4 ;
        RECT  0 37.584 0.084 37.608 ;
    END
  END oflt[10]
  PIN oflt[11]
    DIRECTION INPUT ;
    USE SIGNAL ;
    PORT
      LAYER M4 ;
        RECT  0 37.68 0.084 37.704 ;
    END
  END oflt[11]
  PIN oflt[12]
    DIRECTION INPUT ;
    USE SIGNAL ;
    PORT
      LAYER M4 ;
        RECT  0 37.776 0.084 37.8 ;
    END
  END oflt[12]
  PIN oflt[13]
    DIRECTION INPUT ;
    USE SIGNAL ;
    PORT
      LAYER M4 ;
        RECT  0 37.872 0.084 37.896 ;
    END
  END oflt[13]
  PIN oflt[14]
    DIRECTION INPUT ;
    USE SIGNAL ;
    PORT
      LAYER M4 ;
        RECT  0 37.968 0.084 37.992 ;
    END
  END oflt[14]
  PIN oflt[15]
    DIRECTION INPUT ;
    USE SIGNAL ;
    PORT
      LAYER M4 ;
        RECT  0 41.136 0.084 41.16 ;
    END
  END oflt[15]
  PIN oflt[1]
    DIRECTION INPUT ;
    USE SIGNAL ;
    PORT
      LAYER M4 ;
        RECT  0 36.72 0.084 36.744 ;
    END
  END oflt[1]
  PIN oflt[2]
    DIRECTION INPUT ;
    USE SIGNAL ;
    PORT
      LAYER M4 ;
        RECT  0 36.816 0.084 36.84 ;
    END
  END oflt[2]
  PIN oflt[3]
    DIRECTION INPUT ;
    USE SIGNAL ;
    PORT
      LAYER M4 ;
        RECT  0 36.912 0.084 36.936 ;
    END
  END oflt[3]
  PIN oflt[4]
    DIRECTION INPUT ;
    USE SIGNAL ;
    PORT
      LAYER M4 ;
        RECT  0 37.008 0.084 37.032 ;
    END
  END oflt[4]
  PIN oflt[5]
    DIRECTION INPUT ;
    USE SIGNAL ;
    PORT
      LAYER M4 ;
        RECT  0 37.104 0.084 37.128 ;
    END
  END oflt[5]
  PIN oflt[6]
    DIRECTION INPUT ;
    USE SIGNAL ;
    PORT
      LAYER M4 ;
        RECT  0 37.2 0.084 37.224 ;
    END
  END oflt[6]
  PIN oflt[7]
    DIRECTION INPUT ;
    USE SIGNAL ;
    PORT
      LAYER M4 ;
        RECT  0 37.296 0.084 37.32 ;
    END
  END oflt[7]
  PIN oflt[8]
    DIRECTION INPUT ;
    USE SIGNAL ;
    PORT
      LAYER M4 ;
        RECT  0 37.392 0.084 37.416 ;
    END
  END oflt[8]
  PIN oflt[9]
    DIRECTION INPUT ;
    USE SIGNAL ;
    PORT
      LAYER M4 ;
        RECT  0 37.488 0.084 37.512 ;
    END
  END oflt[9]
  PIN oy[0]
    DIRECTION INPUT ;
    USE SIGNAL ;
    PORT
      LAYER M4 ;
        RECT  0 41.232 0.084 41.256 ;
    END
  END oy[0]
  PIN oy[100]
    DIRECTION INPUT ;
    USE SIGNAL ;
    PORT
      LAYER M4 ;
        RECT  0 29.328 0.084 29.352 ;
    END
  END oy[100]
  PIN oy[101]
    DIRECTION INPUT ;
    USE SIGNAL ;
    PORT
      LAYER M4 ;
        RECT  0 29.424 0.084 29.448 ;
    END
  END oy[101]
  PIN oy[102]
    DIRECTION INPUT ;
    USE SIGNAL ;
    PORT
      LAYER M4 ;
        RECT  0 29.52 0.084 29.544 ;
    END
  END oy[102]
  PIN oy[103]
    DIRECTION INPUT ;
    USE SIGNAL ;
    PORT
      LAYER M4 ;
        RECT  0 29.616 0.084 29.64 ;
    END
  END oy[103]
  PIN oy[104]
    DIRECTION INPUT ;
    USE SIGNAL ;
    PORT
      LAYER M4 ;
        RECT  0 29.712 0.084 29.736 ;
    END
  END oy[104]
  PIN oy[105]
    DIRECTION INPUT ;
    USE SIGNAL ;
    PORT
      LAYER M4 ;
        RECT  0 29.808 0.084 29.832 ;
    END
  END oy[105]
  PIN oy[106]
    DIRECTION INPUT ;
    USE SIGNAL ;
    PORT
      LAYER M4 ;
        RECT  0 29.904 0.084 29.928 ;
    END
  END oy[106]
  PIN oy[107]
    DIRECTION INPUT ;
    USE SIGNAL ;
    PORT
      LAYER M4 ;
        RECT  0 30 0.084 30.024 ;
    END
  END oy[107]
  PIN oy[108]
    DIRECTION INPUT ;
    USE SIGNAL ;
    PORT
      LAYER M4 ;
        RECT  0 30.096 0.084 30.12 ;
    END
  END oy[108]
  PIN oy[109]
    DIRECTION INPUT ;
    USE SIGNAL ;
    PORT
      LAYER M4 ;
        RECT  0 30.192 0.084 30.216 ;
    END
  END oy[109]
  PIN oy[10]
    DIRECTION INPUT ;
    USE SIGNAL ;
    PORT
      LAYER M4 ;
        RECT  0 42.192 0.084 42.216 ;
    END
  END oy[10]
  PIN oy[110]
    DIRECTION INPUT ;
    USE SIGNAL ;
    PORT
      LAYER M4 ;
        RECT  0 30.288 0.084 30.312 ;
    END
  END oy[110]
  PIN oy[111]
    DIRECTION INPUT ;
    USE SIGNAL ;
    PORT
      LAYER M4 ;
        RECT  0 30.384 0.084 30.408 ;
    END
  END oy[111]
  PIN oy[112]
    DIRECTION INPUT ;
    USE SIGNAL ;
    PORT
      LAYER M4 ;
        RECT  0 30.48 0.084 30.504 ;
    END
  END oy[112]
  PIN oy[113]
    DIRECTION INPUT ;
    USE SIGNAL ;
    PORT
      LAYER M4 ;
        RECT  0 30.576 0.084 30.6 ;
    END
  END oy[113]
  PIN oy[114]
    DIRECTION INPUT ;
    USE SIGNAL ;
    PORT
      LAYER M4 ;
        RECT  0 30.672 0.084 30.696 ;
    END
  END oy[114]
  PIN oy[115]
    DIRECTION INPUT ;
    USE SIGNAL ;
    PORT
      LAYER M4 ;
        RECT  0 30.768 0.084 30.792 ;
    END
  END oy[115]
  PIN oy[116]
    DIRECTION INPUT ;
    USE SIGNAL ;
    PORT
      LAYER M4 ;
        RECT  0 30.864 0.084 30.888 ;
    END
  END oy[116]
  PIN oy[117]
    DIRECTION INPUT ;
    USE SIGNAL ;
    PORT
      LAYER M4 ;
        RECT  0 30.96 0.084 30.984 ;
    END
  END oy[117]
  PIN oy[118]
    DIRECTION INPUT ;
    USE SIGNAL ;
    PORT
      LAYER M4 ;
        RECT  0 31.056 0.084 31.08 ;
    END
  END oy[118]
  PIN oy[119]
    DIRECTION INPUT ;
    USE SIGNAL ;
    PORT
      LAYER M4 ;
        RECT  0 31.152 0.084 31.176 ;
    END
  END oy[119]
  PIN oy[11]
    DIRECTION INPUT ;
    USE SIGNAL ;
    PORT
      LAYER M4 ;
        RECT  0 42.288 0.084 42.312 ;
    END
  END oy[11]
  PIN oy[120]
    DIRECTION INPUT ;
    USE SIGNAL ;
    PORT
      LAYER M4 ;
        RECT  0 31.248 0.084 31.272 ;
    END
  END oy[120]
  PIN oy[121]
    DIRECTION INPUT ;
    USE SIGNAL ;
    PORT
      LAYER M4 ;
        RECT  0 31.344 0.084 31.368 ;
    END
  END oy[121]
  PIN oy[122]
    DIRECTION INPUT ;
    USE SIGNAL ;
    PORT
      LAYER M4 ;
        RECT  0 31.44 0.084 31.464 ;
    END
  END oy[122]
  PIN oy[123]
    DIRECTION INPUT ;
    USE SIGNAL ;
    PORT
      LAYER M4 ;
        RECT  0 31.536 0.084 31.56 ;
    END
  END oy[123]
  PIN oy[124]
    DIRECTION INPUT ;
    USE SIGNAL ;
    PORT
      LAYER M4 ;
        RECT  0 31.632 0.084 31.656 ;
    END
  END oy[124]
  PIN oy[125]
    DIRECTION INPUT ;
    USE SIGNAL ;
    PORT
      LAYER M4 ;
        RECT  0 31.728 0.084 31.752 ;
    END
  END oy[125]
  PIN oy[126]
    DIRECTION INPUT ;
    USE SIGNAL ;
    PORT
      LAYER M4 ;
        RECT  0 31.824 0.084 31.848 ;
    END
  END oy[126]
  PIN oy[127]
    DIRECTION INPUT ;
    USE SIGNAL ;
    PORT
      LAYER M4 ;
        RECT  0 44.208 0.084 44.232 ;
    END
  END oy[127]
  PIN oy[128]
    DIRECTION INPUT ;
    USE SIGNAL ;
    PORT
      LAYER M4 ;
        RECT  0 44.304 0.084 44.328 ;
    END
  END oy[128]
  PIN oy[129]
    DIRECTION INPUT ;
    USE SIGNAL ;
    PORT
      LAYER M4 ;
        RECT  0 44.4 0.084 44.424 ;
    END
  END oy[129]
  PIN oy[12]
    DIRECTION INPUT ;
    USE SIGNAL ;
    PORT
      LAYER M4 ;
        RECT  0 42.384 0.084 42.408 ;
    END
  END oy[12]
  PIN oy[130]
    DIRECTION INPUT ;
    USE SIGNAL ;
    PORT
      LAYER M4 ;
        RECT  0 44.496 0.084 44.52 ;
    END
  END oy[130]
  PIN oy[131]
    DIRECTION INPUT ;
    USE SIGNAL ;
    PORT
      LAYER M4 ;
        RECT  0 44.592 0.084 44.616 ;
    END
  END oy[131]
  PIN oy[132]
    DIRECTION INPUT ;
    USE SIGNAL ;
    PORT
      LAYER M4 ;
        RECT  0 44.688 0.084 44.712 ;
    END
  END oy[132]
  PIN oy[133]
    DIRECTION INPUT ;
    USE SIGNAL ;
    PORT
      LAYER M4 ;
        RECT  0 44.784 0.084 44.808 ;
    END
  END oy[133]
  PIN oy[134]
    DIRECTION INPUT ;
    USE SIGNAL ;
    PORT
      LAYER M4 ;
        RECT  0 44.88 0.084 44.904 ;
    END
  END oy[134]
  PIN oy[135]
    DIRECTION INPUT ;
    USE SIGNAL ;
    PORT
      LAYER M4 ;
        RECT  0 44.976 0.084 45 ;
    END
  END oy[135]
  PIN oy[136]
    DIRECTION INPUT ;
    USE SIGNAL ;
    PORT
      LAYER M4 ;
        RECT  0 45.072 0.084 45.096 ;
    END
  END oy[136]
  PIN oy[137]
    DIRECTION INPUT ;
    USE SIGNAL ;
    PORT
      LAYER M4 ;
        RECT  0 45.168 0.084 45.192 ;
    END
  END oy[137]
  PIN oy[138]
    DIRECTION INPUT ;
    USE SIGNAL ;
    PORT
      LAYER M4 ;
        RECT  0 45.264 0.084 45.288 ;
    END
  END oy[138]
  PIN oy[139]
    DIRECTION INPUT ;
    USE SIGNAL ;
    PORT
      LAYER M4 ;
        RECT  0 45.36 0.084 45.384 ;
    END
  END oy[139]
  PIN oy[13]
    DIRECTION INPUT ;
    USE SIGNAL ;
    PORT
      LAYER M4 ;
        RECT  0 42.48 0.084 42.504 ;
    END
  END oy[13]
  PIN oy[140]
    DIRECTION INPUT ;
    USE SIGNAL ;
    PORT
      LAYER M4 ;
        RECT  0 45.456 0.084 45.48 ;
    END
  END oy[140]
  PIN oy[141]
    DIRECTION INPUT ;
    USE SIGNAL ;
    PORT
      LAYER M4 ;
        RECT  0 45.552 0.084 45.576 ;
    END
  END oy[141]
  PIN oy[142]
    DIRECTION INPUT ;
    USE SIGNAL ;
    PORT
      LAYER M4 ;
        RECT  0 45.648 0.084 45.672 ;
    END
  END oy[142]
  PIN oy[143]
    DIRECTION INPUT ;
    USE SIGNAL ;
    PORT
      LAYER M4 ;
        RECT  0 45.744 0.084 45.768 ;
    END
  END oy[143]
  PIN oy[144]
    DIRECTION INPUT ;
    USE SIGNAL ;
    PORT
      LAYER M4 ;
        RECT  0 45.84 0.084 45.864 ;
    END
  END oy[144]
  PIN oy[145]
    DIRECTION INPUT ;
    USE SIGNAL ;
    PORT
      LAYER M4 ;
        RECT  0 45.936 0.084 45.96 ;
    END
  END oy[145]
  PIN oy[146]
    DIRECTION INPUT ;
    USE SIGNAL ;
    PORT
      LAYER M4 ;
        RECT  0 46.032 0.084 46.056 ;
    END
  END oy[146]
  PIN oy[147]
    DIRECTION INPUT ;
    USE SIGNAL ;
    PORT
      LAYER M4 ;
        RECT  0 46.128 0.084 46.152 ;
    END
  END oy[147]
  PIN oy[148]
    DIRECTION INPUT ;
    USE SIGNAL ;
    PORT
      LAYER M4 ;
        RECT  0 46.224 0.084 46.248 ;
    END
  END oy[148]
  PIN oy[149]
    DIRECTION INPUT ;
    USE SIGNAL ;
    PORT
      LAYER M4 ;
        RECT  0 46.32 0.084 46.344 ;
    END
  END oy[149]
  PIN oy[14]
    DIRECTION INPUT ;
    USE SIGNAL ;
    PORT
      LAYER M4 ;
        RECT  0 42.576 0.084 42.6 ;
    END
  END oy[14]
  PIN oy[150]
    DIRECTION INPUT ;
    USE SIGNAL ;
    PORT
      LAYER M4 ;
        RECT  0 46.416 0.084 46.44 ;
    END
  END oy[150]
  PIN oy[151]
    DIRECTION INPUT ;
    USE SIGNAL ;
    PORT
      LAYER M4 ;
        RECT  0 46.512 0.084 46.536 ;
    END
  END oy[151]
  PIN oy[152]
    DIRECTION INPUT ;
    USE SIGNAL ;
    PORT
      LAYER M4 ;
        RECT  0 46.608 0.084 46.632 ;
    END
  END oy[152]
  PIN oy[153]
    DIRECTION INPUT ;
    USE SIGNAL ;
    PORT
      LAYER M4 ;
        RECT  0 46.704 0.084 46.728 ;
    END
  END oy[153]
  PIN oy[154]
    DIRECTION INPUT ;
    USE SIGNAL ;
    PORT
      LAYER M4 ;
        RECT  0 46.8 0.084 46.824 ;
    END
  END oy[154]
  PIN oy[155]
    DIRECTION INPUT ;
    USE SIGNAL ;
    PORT
      LAYER M4 ;
        RECT  0 46.896 0.084 46.92 ;
    END
  END oy[155]
  PIN oy[156]
    DIRECTION INPUT ;
    USE SIGNAL ;
    PORT
      LAYER M4 ;
        RECT  0 46.992 0.084 47.016 ;
    END
  END oy[156]
  PIN oy[157]
    DIRECTION INPUT ;
    USE SIGNAL ;
    PORT
      LAYER M4 ;
        RECT  0 47.088 0.084 47.112 ;
    END
  END oy[157]
  PIN oy[158]
    DIRECTION INPUT ;
    USE SIGNAL ;
    PORT
      LAYER M4 ;
        RECT  0 47.184 0.084 47.208 ;
    END
  END oy[158]
  PIN oy[159]
    DIRECTION INPUT ;
    USE SIGNAL ;
    PORT
      LAYER M4 ;
        RECT  0 51.12 0.084 51.144 ;
    END
  END oy[159]
  PIN oy[15]
    DIRECTION INPUT ;
    USE SIGNAL ;
    PORT
      LAYER M4 ;
        RECT  0 42.672 0.084 42.696 ;
    END
  END oy[15]
  PIN oy[160]
    DIRECTION INPUT ;
    USE SIGNAL ;
    PORT
      LAYER M4 ;
        RECT  0 51.216 0.084 51.24 ;
    END
  END oy[160]
  PIN oy[161]
    DIRECTION INPUT ;
    USE SIGNAL ;
    PORT
      LAYER M4 ;
        RECT  0 51.312 0.084 51.336 ;
    END
  END oy[161]
  PIN oy[162]
    DIRECTION INPUT ;
    USE SIGNAL ;
    PORT
      LAYER M4 ;
        RECT  0 51.408 0.084 51.432 ;
    END
  END oy[162]
  PIN oy[163]
    DIRECTION INPUT ;
    USE SIGNAL ;
    PORT
      LAYER M4 ;
        RECT  0 51.504 0.084 51.528 ;
    END
  END oy[163]
  PIN oy[164]
    DIRECTION INPUT ;
    USE SIGNAL ;
    PORT
      LAYER M4 ;
        RECT  0 51.6 0.084 51.624 ;
    END
  END oy[164]
  PIN oy[165]
    DIRECTION INPUT ;
    USE SIGNAL ;
    PORT
      LAYER M4 ;
        RECT  0 51.696 0.084 51.72 ;
    END
  END oy[165]
  PIN oy[166]
    DIRECTION INPUT ;
    USE SIGNAL ;
    PORT
      LAYER M4 ;
        RECT  0 51.792 0.084 51.816 ;
    END
  END oy[166]
  PIN oy[167]
    DIRECTION INPUT ;
    USE SIGNAL ;
    PORT
      LAYER M4 ;
        RECT  0 51.888 0.084 51.912 ;
    END
  END oy[167]
  PIN oy[168]
    DIRECTION INPUT ;
    USE SIGNAL ;
    PORT
      LAYER M4 ;
        RECT  0 51.984 0.084 52.008 ;
    END
  END oy[168]
  PIN oy[169]
    DIRECTION INPUT ;
    USE SIGNAL ;
    PORT
      LAYER M4 ;
        RECT  0 52.08 0.084 52.104 ;
    END
  END oy[169]
  PIN oy[16]
    DIRECTION INPUT ;
    USE SIGNAL ;
    PORT
      LAYER M4 ;
        RECT  0 42.768 0.084 42.792 ;
    END
  END oy[16]
  PIN oy[170]
    DIRECTION INPUT ;
    USE SIGNAL ;
    PORT
      LAYER M4 ;
        RECT  0 52.176 0.084 52.2 ;
    END
  END oy[170]
  PIN oy[171]
    DIRECTION INPUT ;
    USE SIGNAL ;
    PORT
      LAYER M4 ;
        RECT  0 52.272 0.084 52.296 ;
    END
  END oy[171]
  PIN oy[172]
    DIRECTION INPUT ;
    USE SIGNAL ;
    PORT
      LAYER M4 ;
        RECT  0 52.368 0.084 52.392 ;
    END
  END oy[172]
  PIN oy[173]
    DIRECTION INPUT ;
    USE SIGNAL ;
    PORT
      LAYER M4 ;
        RECT  0 52.464 0.084 52.488 ;
    END
  END oy[173]
  PIN oy[174]
    DIRECTION INPUT ;
    USE SIGNAL ;
    PORT
      LAYER M4 ;
        RECT  0 52.56 0.084 52.584 ;
    END
  END oy[174]
  PIN oy[175]
    DIRECTION INPUT ;
    USE SIGNAL ;
    PORT
      LAYER M4 ;
        RECT  0 52.656 0.084 52.68 ;
    END
  END oy[175]
  PIN oy[176]
    DIRECTION INPUT ;
    USE SIGNAL ;
    PORT
      LAYER M4 ;
        RECT  0 52.752 0.084 52.776 ;
    END
  END oy[176]
  PIN oy[177]
    DIRECTION INPUT ;
    USE SIGNAL ;
    PORT
      LAYER M4 ;
        RECT  0 52.848 0.084 52.872 ;
    END
  END oy[177]
  PIN oy[178]
    DIRECTION INPUT ;
    USE SIGNAL ;
    PORT
      LAYER M4 ;
        RECT  0 52.944 0.084 52.968 ;
    END
  END oy[178]
  PIN oy[179]
    DIRECTION INPUT ;
    USE SIGNAL ;
    PORT
      LAYER M4 ;
        RECT  0 53.04 0.084 53.064 ;
    END
  END oy[179]
  PIN oy[17]
    DIRECTION INPUT ;
    USE SIGNAL ;
    PORT
      LAYER M4 ;
        RECT  0 42.864 0.084 42.888 ;
    END
  END oy[17]
  PIN oy[180]
    DIRECTION INPUT ;
    USE SIGNAL ;
    PORT
      LAYER M4 ;
        RECT  0 53.136 0.084 53.16 ;
    END
  END oy[180]
  PIN oy[181]
    DIRECTION INPUT ;
    USE SIGNAL ;
    PORT
      LAYER M4 ;
        RECT  0 53.232 0.084 53.256 ;
    END
  END oy[181]
  PIN oy[182]
    DIRECTION INPUT ;
    USE SIGNAL ;
    PORT
      LAYER M4 ;
        RECT  0 53.328 0.084 53.352 ;
    END
  END oy[182]
  PIN oy[183]
    DIRECTION INPUT ;
    USE SIGNAL ;
    PORT
      LAYER M4 ;
        RECT  0 53.424 0.084 53.448 ;
    END
  END oy[183]
  PIN oy[184]
    DIRECTION INPUT ;
    USE SIGNAL ;
    PORT
      LAYER M4 ;
        RECT  0 53.52 0.084 53.544 ;
    END
  END oy[184]
  PIN oy[185]
    DIRECTION INPUT ;
    USE SIGNAL ;
    PORT
      LAYER M4 ;
        RECT  0 53.616 0.084 53.64 ;
    END
  END oy[185]
  PIN oy[186]
    DIRECTION INPUT ;
    USE SIGNAL ;
    PORT
      LAYER M4 ;
        RECT  0 53.712 0.084 53.736 ;
    END
  END oy[186]
  PIN oy[187]
    DIRECTION INPUT ;
    USE SIGNAL ;
    PORT
      LAYER M4 ;
        RECT  0 53.808 0.084 53.832 ;
    END
  END oy[187]
  PIN oy[188]
    DIRECTION INPUT ;
    USE SIGNAL ;
    PORT
      LAYER M4 ;
        RECT  0 53.904 0.084 53.928 ;
    END
  END oy[188]
  PIN oy[189]
    DIRECTION INPUT ;
    USE SIGNAL ;
    PORT
      LAYER M4 ;
        RECT  0 54 0.084 54.024 ;
    END
  END oy[189]
  PIN oy[18]
    DIRECTION INPUT ;
    USE SIGNAL ;
    PORT
      LAYER M4 ;
        RECT  0 42.96 0.084 42.984 ;
    END
  END oy[18]
  PIN oy[190]
    DIRECTION INPUT ;
    USE SIGNAL ;
    PORT
      LAYER M4 ;
        RECT  0 54.096 0.084 54.12 ;
    END
  END oy[190]
  PIN oy[191]
    DIRECTION INPUT ;
    USE SIGNAL ;
    PORT
      LAYER M4 ;
        RECT  0 48.048 0.084 48.072 ;
    END
  END oy[191]
  PIN oy[192]
    DIRECTION INPUT ;
    USE SIGNAL ;
    PORT
      LAYER M4 ;
        RECT  0 48.144 0.084 48.168 ;
    END
  END oy[192]
  PIN oy[193]
    DIRECTION INPUT ;
    USE SIGNAL ;
    PORT
      LAYER M4 ;
        RECT  0 48.24 0.084 48.264 ;
    END
  END oy[193]
  PIN oy[194]
    DIRECTION INPUT ;
    USE SIGNAL ;
    PORT
      LAYER M4 ;
        RECT  0 48.336 0.084 48.36 ;
    END
  END oy[194]
  PIN oy[195]
    DIRECTION INPUT ;
    USE SIGNAL ;
    PORT
      LAYER M4 ;
        RECT  0 48.432 0.084 48.456 ;
    END
  END oy[195]
  PIN oy[196]
    DIRECTION INPUT ;
    USE SIGNAL ;
    PORT
      LAYER M4 ;
        RECT  0 48.528 0.084 48.552 ;
    END
  END oy[196]
  PIN oy[197]
    DIRECTION INPUT ;
    USE SIGNAL ;
    PORT
      LAYER M4 ;
        RECT  0 48.624 0.084 48.648 ;
    END
  END oy[197]
  PIN oy[198]
    DIRECTION INPUT ;
    USE SIGNAL ;
    PORT
      LAYER M4 ;
        RECT  0 48.72 0.084 48.744 ;
    END
  END oy[198]
  PIN oy[199]
    DIRECTION INPUT ;
    USE SIGNAL ;
    PORT
      LAYER M4 ;
        RECT  0 48.816 0.084 48.84 ;
    END
  END oy[199]
  PIN oy[19]
    DIRECTION INPUT ;
    USE SIGNAL ;
    PORT
      LAYER M4 ;
        RECT  0 43.056 0.084 43.08 ;
    END
  END oy[19]
  PIN oy[1]
    DIRECTION INPUT ;
    USE SIGNAL ;
    PORT
      LAYER M4 ;
        RECT  0 41.328 0.084 41.352 ;
    END
  END oy[1]
  PIN oy[200]
    DIRECTION INPUT ;
    USE SIGNAL ;
    PORT
      LAYER M4 ;
        RECT  0 48.912 0.084 48.936 ;
    END
  END oy[200]
  PIN oy[201]
    DIRECTION INPUT ;
    USE SIGNAL ;
    PORT
      LAYER M4 ;
        RECT  0 49.008 0.084 49.032 ;
    END
  END oy[201]
  PIN oy[202]
    DIRECTION INPUT ;
    USE SIGNAL ;
    PORT
      LAYER M4 ;
        RECT  0 49.104 0.084 49.128 ;
    END
  END oy[202]
  PIN oy[203]
    DIRECTION INPUT ;
    USE SIGNAL ;
    PORT
      LAYER M4 ;
        RECT  0 49.2 0.084 49.224 ;
    END
  END oy[203]
  PIN oy[204]
    DIRECTION INPUT ;
    USE SIGNAL ;
    PORT
      LAYER M4 ;
        RECT  0 49.296 0.084 49.32 ;
    END
  END oy[204]
  PIN oy[205]
    DIRECTION INPUT ;
    USE SIGNAL ;
    PORT
      LAYER M4 ;
        RECT  0 49.392 0.084 49.416 ;
    END
  END oy[205]
  PIN oy[206]
    DIRECTION INPUT ;
    USE SIGNAL ;
    PORT
      LAYER M4 ;
        RECT  0 49.488 0.084 49.512 ;
    END
  END oy[206]
  PIN oy[207]
    DIRECTION INPUT ;
    USE SIGNAL ;
    PORT
      LAYER M4 ;
        RECT  0 49.584 0.084 49.608 ;
    END
  END oy[207]
  PIN oy[208]
    DIRECTION INPUT ;
    USE SIGNAL ;
    PORT
      LAYER M4 ;
        RECT  0 49.68 0.084 49.704 ;
    END
  END oy[208]
  PIN oy[209]
    DIRECTION INPUT ;
    USE SIGNAL ;
    PORT
      LAYER M4 ;
        RECT  0 49.776 0.084 49.8 ;
    END
  END oy[209]
  PIN oy[20]
    DIRECTION INPUT ;
    USE SIGNAL ;
    PORT
      LAYER M4 ;
        RECT  0 43.152 0.084 43.176 ;
    END
  END oy[20]
  PIN oy[210]
    DIRECTION INPUT ;
    USE SIGNAL ;
    PORT
      LAYER M4 ;
        RECT  0 49.872 0.084 49.896 ;
    END
  END oy[210]
  PIN oy[211]
    DIRECTION INPUT ;
    USE SIGNAL ;
    PORT
      LAYER M4 ;
        RECT  0 49.968 0.084 49.992 ;
    END
  END oy[211]
  PIN oy[212]
    DIRECTION INPUT ;
    USE SIGNAL ;
    PORT
      LAYER M4 ;
        RECT  0 50.064 0.084 50.088 ;
    END
  END oy[212]
  PIN oy[213]
    DIRECTION INPUT ;
    USE SIGNAL ;
    PORT
      LAYER M4 ;
        RECT  0 50.16 0.084 50.184 ;
    END
  END oy[213]
  PIN oy[214]
    DIRECTION INPUT ;
    USE SIGNAL ;
    PORT
      LAYER M4 ;
        RECT  0 50.256 0.084 50.28 ;
    END
  END oy[214]
  PIN oy[215]
    DIRECTION INPUT ;
    USE SIGNAL ;
    PORT
      LAYER M4 ;
        RECT  0 50.352 0.084 50.376 ;
    END
  END oy[215]
  PIN oy[216]
    DIRECTION INPUT ;
    USE SIGNAL ;
    PORT
      LAYER M4 ;
        RECT  0 50.448 0.084 50.472 ;
    END
  END oy[216]
  PIN oy[217]
    DIRECTION INPUT ;
    USE SIGNAL ;
    PORT
      LAYER M4 ;
        RECT  0 50.544 0.084 50.568 ;
    END
  END oy[217]
  PIN oy[218]
    DIRECTION INPUT ;
    USE SIGNAL ;
    PORT
      LAYER M4 ;
        RECT  0 50.64 0.084 50.664 ;
    END
  END oy[218]
  PIN oy[219]
    DIRECTION INPUT ;
    USE SIGNAL ;
    PORT
      LAYER M4 ;
        RECT  0 50.736 0.084 50.76 ;
    END
  END oy[219]
  PIN oy[21]
    DIRECTION INPUT ;
    USE SIGNAL ;
    PORT
      LAYER M4 ;
        RECT  0 43.248 0.084 43.272 ;
    END
  END oy[21]
  PIN oy[220]
    DIRECTION INPUT ;
    USE SIGNAL ;
    PORT
      LAYER M4 ;
        RECT  0 50.832 0.084 50.856 ;
    END
  END oy[220]
  PIN oy[221]
    DIRECTION INPUT ;
    USE SIGNAL ;
    PORT
      LAYER M4 ;
        RECT  0 50.928 0.084 50.952 ;
    END
  END oy[221]
  PIN oy[222]
    DIRECTION INPUT ;
    USE SIGNAL ;
    PORT
      LAYER M4 ;
        RECT  0 51.024 0.084 51.048 ;
    END
  END oy[222]
  PIN oy[223]
    DIRECTION INPUT ;
    USE SIGNAL ;
    PORT
      LAYER M4 ;
        RECT  0 54.192 0.084 54.216 ;
    END
  END oy[223]
  PIN oy[224]
    DIRECTION INPUT ;
    USE SIGNAL ;
    PORT
      LAYER M4 ;
        RECT  0 54.288 0.084 54.312 ;
    END
  END oy[224]
  PIN oy[225]
    DIRECTION INPUT ;
    USE SIGNAL ;
    PORT
      LAYER M4 ;
        RECT  0 54.384 0.084 54.408 ;
    END
  END oy[225]
  PIN oy[226]
    DIRECTION INPUT ;
    USE SIGNAL ;
    PORT
      LAYER M4 ;
        RECT  0 54.48 0.084 54.504 ;
    END
  END oy[226]
  PIN oy[227]
    DIRECTION INPUT ;
    USE SIGNAL ;
    PORT
      LAYER M4 ;
        RECT  0 54.576 0.084 54.6 ;
    END
  END oy[227]
  PIN oy[228]
    DIRECTION INPUT ;
    USE SIGNAL ;
    PORT
      LAYER M4 ;
        RECT  0 54.672 0.084 54.696 ;
    END
  END oy[228]
  PIN oy[229]
    DIRECTION INPUT ;
    USE SIGNAL ;
    PORT
      LAYER M4 ;
        RECT  0 54.768 0.084 54.792 ;
    END
  END oy[229]
  PIN oy[22]
    DIRECTION INPUT ;
    USE SIGNAL ;
    PORT
      LAYER M4 ;
        RECT  0 43.344 0.084 43.368 ;
    END
  END oy[22]
  PIN oy[230]
    DIRECTION INPUT ;
    USE SIGNAL ;
    PORT
      LAYER M4 ;
        RECT  0 54.864 0.084 54.888 ;
    END
  END oy[230]
  PIN oy[231]
    DIRECTION INPUT ;
    USE SIGNAL ;
    PORT
      LAYER M4 ;
        RECT  0 54.96 0.084 54.984 ;
    END
  END oy[231]
  PIN oy[232]
    DIRECTION INPUT ;
    USE SIGNAL ;
    PORT
      LAYER M4 ;
        RECT  0 55.056 0.084 55.08 ;
    END
  END oy[232]
  PIN oy[233]
    DIRECTION INPUT ;
    USE SIGNAL ;
    PORT
      LAYER M4 ;
        RECT  0 55.152 0.084 55.176 ;
    END
  END oy[233]
  PIN oy[234]
    DIRECTION INPUT ;
    USE SIGNAL ;
    PORT
      LAYER M4 ;
        RECT  0 55.248 0.084 55.272 ;
    END
  END oy[234]
  PIN oy[235]
    DIRECTION INPUT ;
    USE SIGNAL ;
    PORT
      LAYER M4 ;
        RECT  0 55.344 0.084 55.368 ;
    END
  END oy[235]
  PIN oy[236]
    DIRECTION INPUT ;
    USE SIGNAL ;
    PORT
      LAYER M4 ;
        RECT  0 55.44 0.084 55.464 ;
    END
  END oy[236]
  PIN oy[237]
    DIRECTION INPUT ;
    USE SIGNAL ;
    PORT
      LAYER M4 ;
        RECT  0 55.536 0.084 55.56 ;
    END
  END oy[237]
  PIN oy[238]
    DIRECTION INPUT ;
    USE SIGNAL ;
    PORT
      LAYER M4 ;
        RECT  0 55.632 0.084 55.656 ;
    END
  END oy[238]
  PIN oy[239]
    DIRECTION INPUT ;
    USE SIGNAL ;
    PORT
      LAYER M4 ;
        RECT  0 55.728 0.084 55.752 ;
    END
  END oy[239]
  PIN oy[23]
    DIRECTION INPUT ;
    USE SIGNAL ;
    PORT
      LAYER M4 ;
        RECT  0 43.44 0.084 43.464 ;
    END
  END oy[23]
  PIN oy[240]
    DIRECTION INPUT ;
    USE SIGNAL ;
    PORT
      LAYER M4 ;
        RECT  0 55.824 0.084 55.848 ;
    END
  END oy[240]
  PIN oy[241]
    DIRECTION INPUT ;
    USE SIGNAL ;
    PORT
      LAYER M4 ;
        RECT  0 55.92 0.084 55.944 ;
    END
  END oy[241]
  PIN oy[242]
    DIRECTION INPUT ;
    USE SIGNAL ;
    PORT
      LAYER M4 ;
        RECT  0 56.016 0.084 56.04 ;
    END
  END oy[242]
  PIN oy[243]
    DIRECTION INPUT ;
    USE SIGNAL ;
    PORT
      LAYER M4 ;
        RECT  0 56.112 0.084 56.136 ;
    END
  END oy[243]
  PIN oy[244]
    DIRECTION INPUT ;
    USE SIGNAL ;
    PORT
      LAYER M4 ;
        RECT  0 56.208 0.084 56.232 ;
    END
  END oy[244]
  PIN oy[245]
    DIRECTION INPUT ;
    USE SIGNAL ;
    PORT
      LAYER M4 ;
        RECT  0 56.304 0.084 56.328 ;
    END
  END oy[245]
  PIN oy[246]
    DIRECTION INPUT ;
    USE SIGNAL ;
    PORT
      LAYER M4 ;
        RECT  0 56.4 0.084 56.424 ;
    END
  END oy[246]
  PIN oy[247]
    DIRECTION INPUT ;
    USE SIGNAL ;
    PORT
      LAYER M4 ;
        RECT  0 56.496 0.084 56.52 ;
    END
  END oy[247]
  PIN oy[248]
    DIRECTION INPUT ;
    USE SIGNAL ;
    PORT
      LAYER M4 ;
        RECT  0 56.592 0.084 56.616 ;
    END
  END oy[248]
  PIN oy[249]
    DIRECTION INPUT ;
    USE SIGNAL ;
    PORT
      LAYER M4 ;
        RECT  0 56.688 0.084 56.712 ;
    END
  END oy[249]
  PIN oy[24]
    DIRECTION INPUT ;
    USE SIGNAL ;
    PORT
      LAYER M4 ;
        RECT  0 43.536 0.084 43.56 ;
    END
  END oy[24]
  PIN oy[250]
    DIRECTION INPUT ;
    USE SIGNAL ;
    PORT
      LAYER M4 ;
        RECT  0 56.784 0.084 56.808 ;
    END
  END oy[250]
  PIN oy[251]
    DIRECTION INPUT ;
    USE SIGNAL ;
    PORT
      LAYER M4 ;
        RECT  0 56.88 0.084 56.904 ;
    END
  END oy[251]
  PIN oy[252]
    DIRECTION INPUT ;
    USE SIGNAL ;
    PORT
      LAYER M4 ;
        RECT  0 56.976 0.084 57 ;
    END
  END oy[252]
  PIN oy[253]
    DIRECTION INPUT ;
    USE SIGNAL ;
    PORT
      LAYER M4 ;
        RECT  0 57.072 0.084 57.096 ;
    END
  END oy[253]
  PIN oy[254]
    DIRECTION INPUT ;
    USE SIGNAL ;
    PORT
      LAYER M4 ;
        RECT  0 57.168 0.084 57.192 ;
    END
  END oy[254]
  PIN oy[255]
    DIRECTION INPUT ;
    USE SIGNAL ;
    PORT
      LAYER M4 ;
        RECT  0 57.264 0.084 57.288 ;
    END
  END oy[255]
  PIN oy[256]
    DIRECTION INPUT ;
    USE SIGNAL ;
    PORT
      LAYER M4 ;
        RECT  0 57.36 0.084 57.384 ;
    END
  END oy[256]
  PIN oy[257]
    DIRECTION INPUT ;
    USE SIGNAL ;
    PORT
      LAYER M4 ;
        RECT  0 57.456 0.084 57.48 ;
    END
  END oy[257]
  PIN oy[258]
    DIRECTION INPUT ;
    USE SIGNAL ;
    PORT
      LAYER M4 ;
        RECT  0 57.552 0.084 57.576 ;
    END
  END oy[258]
  PIN oy[259]
    DIRECTION INPUT ;
    USE SIGNAL ;
    PORT
      LAYER M4 ;
        RECT  0 57.648 0.084 57.672 ;
    END
  END oy[259]
  PIN oy[25]
    DIRECTION INPUT ;
    USE SIGNAL ;
    PORT
      LAYER M4 ;
        RECT  0 43.632 0.084 43.656 ;
    END
  END oy[25]
  PIN oy[260]
    DIRECTION INPUT ;
    USE SIGNAL ;
    PORT
      LAYER M4 ;
        RECT  0 57.744 0.084 57.768 ;
    END
  END oy[260]
  PIN oy[261]
    DIRECTION INPUT ;
    USE SIGNAL ;
    PORT
      LAYER M4 ;
        RECT  0 57.84 0.084 57.864 ;
    END
  END oy[261]
  PIN oy[262]
    DIRECTION INPUT ;
    USE SIGNAL ;
    PORT
      LAYER M4 ;
        RECT  0 57.936 0.084 57.96 ;
    END
  END oy[262]
  PIN oy[263]
    DIRECTION INPUT ;
    USE SIGNAL ;
    PORT
      LAYER M4 ;
        RECT  0 58.032 0.084 58.056 ;
    END
  END oy[263]
  PIN oy[264]
    DIRECTION INPUT ;
    USE SIGNAL ;
    PORT
      LAYER M4 ;
        RECT  0 58.128 0.084 58.152 ;
    END
  END oy[264]
  PIN oy[265]
    DIRECTION INPUT ;
    USE SIGNAL ;
    PORT
      LAYER M4 ;
        RECT  0 58.224 0.084 58.248 ;
    END
  END oy[265]
  PIN oy[266]
    DIRECTION INPUT ;
    USE SIGNAL ;
    PORT
      LAYER M4 ;
        RECT  0 58.32 0.084 58.344 ;
    END
  END oy[266]
  PIN oy[267]
    DIRECTION INPUT ;
    USE SIGNAL ;
    PORT
      LAYER M4 ;
        RECT  0 58.416 0.084 58.44 ;
    END
  END oy[267]
  PIN oy[268]
    DIRECTION INPUT ;
    USE SIGNAL ;
    PORT
      LAYER M4 ;
        RECT  0 58.512 0.084 58.536 ;
    END
  END oy[268]
  PIN oy[269]
    DIRECTION INPUT ;
    USE SIGNAL ;
    PORT
      LAYER M4 ;
        RECT  0 58.608 0.084 58.632 ;
    END
  END oy[269]
  PIN oy[26]
    DIRECTION INPUT ;
    USE SIGNAL ;
    PORT
      LAYER M4 ;
        RECT  0 43.728 0.084 43.752 ;
    END
  END oy[26]
  PIN oy[270]
    DIRECTION INPUT ;
    USE SIGNAL ;
    PORT
      LAYER M4 ;
        RECT  0 58.704 0.084 58.728 ;
    END
  END oy[270]
  PIN oy[271]
    DIRECTION INPUT ;
    USE SIGNAL ;
    PORT
      LAYER M4 ;
        RECT  0 58.8 0.084 58.824 ;
    END
  END oy[271]
  PIN oy[272]
    DIRECTION INPUT ;
    USE SIGNAL ;
    PORT
      LAYER M4 ;
        RECT  0 58.896 0.084 58.92 ;
    END
  END oy[272]
  PIN oy[273]
    DIRECTION INPUT ;
    USE SIGNAL ;
    PORT
      LAYER M4 ;
        RECT  0 58.992 0.084 59.016 ;
    END
  END oy[273]
  PIN oy[274]
    DIRECTION INPUT ;
    USE SIGNAL ;
    PORT
      LAYER M4 ;
        RECT  0 59.088 0.084 59.112 ;
    END
  END oy[274]
  PIN oy[275]
    DIRECTION INPUT ;
    USE SIGNAL ;
    PORT
      LAYER M4 ;
        RECT  0 59.184 0.084 59.208 ;
    END
  END oy[275]
  PIN oy[276]
    DIRECTION INPUT ;
    USE SIGNAL ;
    PORT
      LAYER M4 ;
        RECT  0 59.28 0.084 59.304 ;
    END
  END oy[276]
  PIN oy[277]
    DIRECTION INPUT ;
    USE SIGNAL ;
    PORT
      LAYER M4 ;
        RECT  0 59.376 0.084 59.4 ;
    END
  END oy[277]
  PIN oy[278]
    DIRECTION INPUT ;
    USE SIGNAL ;
    PORT
      LAYER M4 ;
        RECT  0 59.472 0.084 59.496 ;
    END
  END oy[278]
  PIN oy[279]
    DIRECTION INPUT ;
    USE SIGNAL ;
    PORT
      LAYER M4 ;
        RECT  0 59.568 0.084 59.592 ;
    END
  END oy[279]
  PIN oy[27]
    DIRECTION INPUT ;
    USE SIGNAL ;
    PORT
      LAYER M4 ;
        RECT  0 43.824 0.084 43.848 ;
    END
  END oy[27]
  PIN oy[280]
    DIRECTION INPUT ;
    USE SIGNAL ;
    PORT
      LAYER M4 ;
        RECT  0 59.664 0.084 59.688 ;
    END
  END oy[280]
  PIN oy[281]
    DIRECTION INPUT ;
    USE SIGNAL ;
    PORT
      LAYER M4 ;
        RECT  0 59.76 0.084 59.784 ;
    END
  END oy[281]
  PIN oy[282]
    DIRECTION INPUT ;
    USE SIGNAL ;
    PORT
      LAYER M4 ;
        RECT  0 59.856 0.084 59.88 ;
    END
  END oy[282]
  PIN oy[283]
    DIRECTION INPUT ;
    USE SIGNAL ;
    PORT
      LAYER M4 ;
        RECT  0 59.952 0.084 59.976 ;
    END
  END oy[283]
  PIN oy[284]
    DIRECTION INPUT ;
    USE SIGNAL ;
    PORT
      LAYER M4 ;
        RECT  0 60.048 0.084 60.072 ;
    END
  END oy[284]
  PIN oy[285]
    DIRECTION INPUT ;
    USE SIGNAL ;
    PORT
      LAYER M4 ;
        RECT  0 60.144 0.084 60.168 ;
    END
  END oy[285]
  PIN oy[286]
    DIRECTION INPUT ;
    USE SIGNAL ;
    PORT
      LAYER M4 ;
        RECT  0 60.24 0.084 60.264 ;
    END
  END oy[286]
  PIN oy[287]
    DIRECTION INPUT ;
    USE SIGNAL ;
    PORT
      LAYER M4 ;
        RECT  0 63.408 0.084 63.432 ;
    END
  END oy[287]
  PIN oy[288]
    DIRECTION INPUT ;
    USE SIGNAL ;
    PORT
      LAYER M4 ;
        RECT  0 63.504 0.084 63.528 ;
    END
  END oy[288]
  PIN oy[289]
    DIRECTION INPUT ;
    USE SIGNAL ;
    PORT
      LAYER M4 ;
        RECT  0 63.6 0.084 63.624 ;
    END
  END oy[289]
  PIN oy[28]
    DIRECTION INPUT ;
    USE SIGNAL ;
    PORT
      LAYER M4 ;
        RECT  0 43.92 0.084 43.944 ;
    END
  END oy[28]
  PIN oy[290]
    DIRECTION INPUT ;
    USE SIGNAL ;
    PORT
      LAYER M4 ;
        RECT  0 63.696 0.084 63.72 ;
    END
  END oy[290]
  PIN oy[291]
    DIRECTION INPUT ;
    USE SIGNAL ;
    PORT
      LAYER M4 ;
        RECT  0 63.792 0.084 63.816 ;
    END
  END oy[291]
  PIN oy[292]
    DIRECTION INPUT ;
    USE SIGNAL ;
    PORT
      LAYER M4 ;
        RECT  0 63.888 0.084 63.912 ;
    END
  END oy[292]
  PIN oy[293]
    DIRECTION INPUT ;
    USE SIGNAL ;
    PORT
      LAYER M4 ;
        RECT  0 63.984 0.084 64.008 ;
    END
  END oy[293]
  PIN oy[294]
    DIRECTION INPUT ;
    USE SIGNAL ;
    PORT
      LAYER M4 ;
        RECT  0 64.08 0.084 64.104 ;
    END
  END oy[294]
  PIN oy[295]
    DIRECTION INPUT ;
    USE SIGNAL ;
    PORT
      LAYER M4 ;
        RECT  0 64.176 0.084 64.2 ;
    END
  END oy[295]
  PIN oy[296]
    DIRECTION INPUT ;
    USE SIGNAL ;
    PORT
      LAYER M4 ;
        RECT  0 64.272 0.084 64.296 ;
    END
  END oy[296]
  PIN oy[297]
    DIRECTION INPUT ;
    USE SIGNAL ;
    PORT
      LAYER M4 ;
        RECT  0 64.368 0.084 64.392 ;
    END
  END oy[297]
  PIN oy[298]
    DIRECTION INPUT ;
    USE SIGNAL ;
    PORT
      LAYER M4 ;
        RECT  0 64.464 0.084 64.488 ;
    END
  END oy[298]
  PIN oy[299]
    DIRECTION INPUT ;
    USE SIGNAL ;
    PORT
      LAYER M4 ;
        RECT  0 64.56 0.084 64.584 ;
    END
  END oy[299]
  PIN oy[29]
    DIRECTION INPUT ;
    USE SIGNAL ;
    PORT
      LAYER M4 ;
        RECT  0 44.016 0.084 44.04 ;
    END
  END oy[29]
  PIN oy[2]
    DIRECTION INPUT ;
    USE SIGNAL ;
    PORT
      LAYER M4 ;
        RECT  0 41.424 0.084 41.448 ;
    END
  END oy[2]
  PIN oy[300]
    DIRECTION INPUT ;
    USE SIGNAL ;
    PORT
      LAYER M4 ;
        RECT  0 64.656 0.084 64.68 ;
    END
  END oy[300]
  PIN oy[301]
    DIRECTION INPUT ;
    USE SIGNAL ;
    PORT
      LAYER M4 ;
        RECT  0 64.752 0.084 64.776 ;
    END
  END oy[301]
  PIN oy[302]
    DIRECTION INPUT ;
    USE SIGNAL ;
    PORT
      LAYER M4 ;
        RECT  0 64.848 0.084 64.872 ;
    END
  END oy[302]
  PIN oy[303]
    DIRECTION INPUT ;
    USE SIGNAL ;
    PORT
      LAYER M4 ;
        RECT  0 64.944 0.084 64.968 ;
    END
  END oy[303]
  PIN oy[304]
    DIRECTION INPUT ;
    USE SIGNAL ;
    PORT
      LAYER M4 ;
        RECT  0 65.04 0.084 65.064 ;
    END
  END oy[304]
  PIN oy[305]
    DIRECTION INPUT ;
    USE SIGNAL ;
    PORT
      LAYER M4 ;
        RECT  0 65.136 0.084 65.16 ;
    END
  END oy[305]
  PIN oy[306]
    DIRECTION INPUT ;
    USE SIGNAL ;
    PORT
      LAYER M4 ;
        RECT  0 65.232 0.084 65.256 ;
    END
  END oy[306]
  PIN oy[307]
    DIRECTION INPUT ;
    USE SIGNAL ;
    PORT
      LAYER M4 ;
        RECT  0 65.328 0.084 65.352 ;
    END
  END oy[307]
  PIN oy[308]
    DIRECTION INPUT ;
    USE SIGNAL ;
    PORT
      LAYER M4 ;
        RECT  0 65.424 0.084 65.448 ;
    END
  END oy[308]
  PIN oy[309]
    DIRECTION INPUT ;
    USE SIGNAL ;
    PORT
      LAYER M4 ;
        RECT  0 65.52 0.084 65.544 ;
    END
  END oy[309]
  PIN oy[30]
    DIRECTION INPUT ;
    USE SIGNAL ;
    PORT
      LAYER M4 ;
        RECT  0 44.112 0.084 44.136 ;
    END
  END oy[30]
  PIN oy[310]
    DIRECTION INPUT ;
    USE SIGNAL ;
    PORT
      LAYER M4 ;
        RECT  0 65.616 0.084 65.64 ;
    END
  END oy[310]
  PIN oy[311]
    DIRECTION INPUT ;
    USE SIGNAL ;
    PORT
      LAYER M4 ;
        RECT  0 65.712 0.084 65.736 ;
    END
  END oy[311]
  PIN oy[312]
    DIRECTION INPUT ;
    USE SIGNAL ;
    PORT
      LAYER M4 ;
        RECT  0 65.808 0.084 65.832 ;
    END
  END oy[312]
  PIN oy[313]
    DIRECTION INPUT ;
    USE SIGNAL ;
    PORT
      LAYER M4 ;
        RECT  0 65.904 0.084 65.928 ;
    END
  END oy[313]
  PIN oy[314]
    DIRECTION INPUT ;
    USE SIGNAL ;
    PORT
      LAYER M4 ;
        RECT  0 66 0.084 66.024 ;
    END
  END oy[314]
  PIN oy[315]
    DIRECTION INPUT ;
    USE SIGNAL ;
    PORT
      LAYER M4 ;
        RECT  0 66.096 0.084 66.12 ;
    END
  END oy[315]
  PIN oy[316]
    DIRECTION INPUT ;
    USE SIGNAL ;
    PORT
      LAYER M4 ;
        RECT  0 66.192 0.084 66.216 ;
    END
  END oy[316]
  PIN oy[317]
    DIRECTION INPUT ;
    USE SIGNAL ;
    PORT
      LAYER M4 ;
        RECT  0 66.288 0.084 66.312 ;
    END
  END oy[317]
  PIN oy[318]
    DIRECTION INPUT ;
    USE SIGNAL ;
    PORT
      LAYER M4 ;
        RECT  0 66.384 0.084 66.408 ;
    END
  END oy[318]
  PIN oy[319]
    DIRECTION INPUT ;
    USE SIGNAL ;
    PORT
      LAYER M4 ;
        RECT  0 60.336 0.084 60.36 ;
    END
  END oy[319]
  PIN oy[31]
    DIRECTION INPUT ;
    USE SIGNAL ;
    PORT
      LAYER M4 ;
        RECT  0 38.064 0.084 38.088 ;
    END
  END oy[31]
  PIN oy[320]
    DIRECTION INPUT ;
    USE SIGNAL ;
    PORT
      LAYER M4 ;
        RECT  0 60.432 0.084 60.456 ;
    END
  END oy[320]
  PIN oy[321]
    DIRECTION INPUT ;
    USE SIGNAL ;
    PORT
      LAYER M4 ;
        RECT  0 60.528 0.084 60.552 ;
    END
  END oy[321]
  PIN oy[322]
    DIRECTION INPUT ;
    USE SIGNAL ;
    PORT
      LAYER M4 ;
        RECT  0 60.624 0.084 60.648 ;
    END
  END oy[322]
  PIN oy[323]
    DIRECTION INPUT ;
    USE SIGNAL ;
    PORT
      LAYER M4 ;
        RECT  0 60.72 0.084 60.744 ;
    END
  END oy[323]
  PIN oy[324]
    DIRECTION INPUT ;
    USE SIGNAL ;
    PORT
      LAYER M4 ;
        RECT  0 60.816 0.084 60.84 ;
    END
  END oy[324]
  PIN oy[325]
    DIRECTION INPUT ;
    USE SIGNAL ;
    PORT
      LAYER M4 ;
        RECT  0 60.912 0.084 60.936 ;
    END
  END oy[325]
  PIN oy[326]
    DIRECTION INPUT ;
    USE SIGNAL ;
    PORT
      LAYER M4 ;
        RECT  0 61.008 0.084 61.032 ;
    END
  END oy[326]
  PIN oy[327]
    DIRECTION INPUT ;
    USE SIGNAL ;
    PORT
      LAYER M4 ;
        RECT  0 61.104 0.084 61.128 ;
    END
  END oy[327]
  PIN oy[328]
    DIRECTION INPUT ;
    USE SIGNAL ;
    PORT
      LAYER M4 ;
        RECT  0 61.2 0.084 61.224 ;
    END
  END oy[328]
  PIN oy[329]
    DIRECTION INPUT ;
    USE SIGNAL ;
    PORT
      LAYER M4 ;
        RECT  0 61.296 0.084 61.32 ;
    END
  END oy[329]
  PIN oy[32]
    DIRECTION INPUT ;
    USE SIGNAL ;
    PORT
      LAYER M4 ;
        RECT  0 38.16 0.084 38.184 ;
    END
  END oy[32]
  PIN oy[330]
    DIRECTION INPUT ;
    USE SIGNAL ;
    PORT
      LAYER M4 ;
        RECT  0 61.392 0.084 61.416 ;
    END
  END oy[330]
  PIN oy[331]
    DIRECTION INPUT ;
    USE SIGNAL ;
    PORT
      LAYER M4 ;
        RECT  0 61.488 0.084 61.512 ;
    END
  END oy[331]
  PIN oy[332]
    DIRECTION INPUT ;
    USE SIGNAL ;
    PORT
      LAYER M4 ;
        RECT  0 61.584 0.084 61.608 ;
    END
  END oy[332]
  PIN oy[333]
    DIRECTION INPUT ;
    USE SIGNAL ;
    PORT
      LAYER M4 ;
        RECT  0 61.68 0.084 61.704 ;
    END
  END oy[333]
  PIN oy[334]
    DIRECTION INPUT ;
    USE SIGNAL ;
    PORT
      LAYER M4 ;
        RECT  0 61.776 0.084 61.8 ;
    END
  END oy[334]
  PIN oy[335]
    DIRECTION INPUT ;
    USE SIGNAL ;
    PORT
      LAYER M4 ;
        RECT  0 61.872 0.084 61.896 ;
    END
  END oy[335]
  PIN oy[336]
    DIRECTION INPUT ;
    USE SIGNAL ;
    PORT
      LAYER M4 ;
        RECT  0 61.968 0.084 61.992 ;
    END
  END oy[336]
  PIN oy[337]
    DIRECTION INPUT ;
    USE SIGNAL ;
    PORT
      LAYER M4 ;
        RECT  0 62.064 0.084 62.088 ;
    END
  END oy[337]
  PIN oy[338]
    DIRECTION INPUT ;
    USE SIGNAL ;
    PORT
      LAYER M4 ;
        RECT  0 62.16 0.084 62.184 ;
    END
  END oy[338]
  PIN oy[339]
    DIRECTION INPUT ;
    USE SIGNAL ;
    PORT
      LAYER M4 ;
        RECT  0 62.256 0.084 62.28 ;
    END
  END oy[339]
  PIN oy[33]
    DIRECTION INPUT ;
    USE SIGNAL ;
    PORT
      LAYER M4 ;
        RECT  0 38.256 0.084 38.28 ;
    END
  END oy[33]
  PIN oy[340]
    DIRECTION INPUT ;
    USE SIGNAL ;
    PORT
      LAYER M4 ;
        RECT  0 62.352 0.084 62.376 ;
    END
  END oy[340]
  PIN oy[341]
    DIRECTION INPUT ;
    USE SIGNAL ;
    PORT
      LAYER M4 ;
        RECT  0 62.448 0.084 62.472 ;
    END
  END oy[341]
  PIN oy[342]
    DIRECTION INPUT ;
    USE SIGNAL ;
    PORT
      LAYER M4 ;
        RECT  0 62.544 0.084 62.568 ;
    END
  END oy[342]
  PIN oy[343]
    DIRECTION INPUT ;
    USE SIGNAL ;
    PORT
      LAYER M4 ;
        RECT  0 62.64 0.084 62.664 ;
    END
  END oy[343]
  PIN oy[344]
    DIRECTION INPUT ;
    USE SIGNAL ;
    PORT
      LAYER M4 ;
        RECT  0 62.736 0.084 62.76 ;
    END
  END oy[344]
  PIN oy[345]
    DIRECTION INPUT ;
    USE SIGNAL ;
    PORT
      LAYER M4 ;
        RECT  0 62.832 0.084 62.856 ;
    END
  END oy[345]
  PIN oy[346]
    DIRECTION INPUT ;
    USE SIGNAL ;
    PORT
      LAYER M4 ;
        RECT  0 62.928 0.084 62.952 ;
    END
  END oy[346]
  PIN oy[347]
    DIRECTION INPUT ;
    USE SIGNAL ;
    PORT
      LAYER M4 ;
        RECT  0 63.024 0.084 63.048 ;
    END
  END oy[347]
  PIN oy[348]
    DIRECTION INPUT ;
    USE SIGNAL ;
    PORT
      LAYER M4 ;
        RECT  0 63.12 0.084 63.144 ;
    END
  END oy[348]
  PIN oy[349]
    DIRECTION INPUT ;
    USE SIGNAL ;
    PORT
      LAYER M4 ;
        RECT  0 63.216 0.084 63.24 ;
    END
  END oy[349]
  PIN oy[34]
    DIRECTION INPUT ;
    USE SIGNAL ;
    PORT
      LAYER M4 ;
        RECT  0 38.352 0.084 38.376 ;
    END
  END oy[34]
  PIN oy[350]
    DIRECTION INPUT ;
    USE SIGNAL ;
    PORT
      LAYER M4 ;
        RECT  0 63.312 0.084 63.336 ;
    END
  END oy[350]
  PIN oy[351]
    DIRECTION INPUT ;
    USE SIGNAL ;
    PORT
      LAYER M4 ;
        RECT  0 15.792 0.084 15.816 ;
    END
  END oy[351]
  PIN oy[352]
    DIRECTION INPUT ;
    USE SIGNAL ;
    PORT
      LAYER M4 ;
        RECT  0 15.888 0.084 15.912 ;
    END
  END oy[352]
  PIN oy[353]
    DIRECTION INPUT ;
    USE SIGNAL ;
    PORT
      LAYER M4 ;
        RECT  0 15.984 0.084 16.008 ;
    END
  END oy[353]
  PIN oy[354]
    DIRECTION INPUT ;
    USE SIGNAL ;
    PORT
      LAYER M4 ;
        RECT  0 16.08 0.084 16.104 ;
    END
  END oy[354]
  PIN oy[355]
    DIRECTION INPUT ;
    USE SIGNAL ;
    PORT
      LAYER M4 ;
        RECT  0 16.176 0.084 16.2 ;
    END
  END oy[355]
  PIN oy[356]
    DIRECTION INPUT ;
    USE SIGNAL ;
    PORT
      LAYER M4 ;
        RECT  0 16.272 0.084 16.296 ;
    END
  END oy[356]
  PIN oy[357]
    DIRECTION INPUT ;
    USE SIGNAL ;
    PORT
      LAYER M4 ;
        RECT  0 16.368 0.084 16.392 ;
    END
  END oy[357]
  PIN oy[358]
    DIRECTION INPUT ;
    USE SIGNAL ;
    PORT
      LAYER M4 ;
        RECT  0 16.464 0.084 16.488 ;
    END
  END oy[358]
  PIN oy[359]
    DIRECTION INPUT ;
    USE SIGNAL ;
    PORT
      LAYER M4 ;
        RECT  0 16.56 0.084 16.584 ;
    END
  END oy[359]
  PIN oy[35]
    DIRECTION INPUT ;
    USE SIGNAL ;
    PORT
      LAYER M4 ;
        RECT  0 38.448 0.084 38.472 ;
    END
  END oy[35]
  PIN oy[360]
    DIRECTION INPUT ;
    USE SIGNAL ;
    PORT
      LAYER M4 ;
        RECT  0 16.656 0.084 16.68 ;
    END
  END oy[360]
  PIN oy[361]
    DIRECTION INPUT ;
    USE SIGNAL ;
    PORT
      LAYER M4 ;
        RECT  0 16.752 0.084 16.776 ;
    END
  END oy[361]
  PIN oy[362]
    DIRECTION INPUT ;
    USE SIGNAL ;
    PORT
      LAYER M4 ;
        RECT  0 16.848 0.084 16.872 ;
    END
  END oy[362]
  PIN oy[363]
    DIRECTION INPUT ;
    USE SIGNAL ;
    PORT
      LAYER M4 ;
        RECT  0 16.944 0.084 16.968 ;
    END
  END oy[363]
  PIN oy[364]
    DIRECTION INPUT ;
    USE SIGNAL ;
    PORT
      LAYER M4 ;
        RECT  0 17.04 0.084 17.064 ;
    END
  END oy[364]
  PIN oy[365]
    DIRECTION INPUT ;
    USE SIGNAL ;
    PORT
      LAYER M4 ;
        RECT  0 17.136 0.084 17.16 ;
    END
  END oy[365]
  PIN oy[366]
    DIRECTION INPUT ;
    USE SIGNAL ;
    PORT
      LAYER M4 ;
        RECT  0 17.232 0.084 17.256 ;
    END
  END oy[366]
  PIN oy[367]
    DIRECTION INPUT ;
    USE SIGNAL ;
    PORT
      LAYER M4 ;
        RECT  0 17.328 0.084 17.352 ;
    END
  END oy[367]
  PIN oy[368]
    DIRECTION INPUT ;
    USE SIGNAL ;
    PORT
      LAYER M4 ;
        RECT  0 17.424 0.084 17.448 ;
    END
  END oy[368]
  PIN oy[369]
    DIRECTION INPUT ;
    USE SIGNAL ;
    PORT
      LAYER M4 ;
        RECT  0 17.52 0.084 17.544 ;
    END
  END oy[369]
  PIN oy[36]
    DIRECTION INPUT ;
    USE SIGNAL ;
    PORT
      LAYER M4 ;
        RECT  0 38.544 0.084 38.568 ;
    END
  END oy[36]
  PIN oy[370]
    DIRECTION INPUT ;
    USE SIGNAL ;
    PORT
      LAYER M4 ;
        RECT  0 17.616 0.084 17.64 ;
    END
  END oy[370]
  PIN oy[371]
    DIRECTION INPUT ;
    USE SIGNAL ;
    PORT
      LAYER M4 ;
        RECT  0 17.712 0.084 17.736 ;
    END
  END oy[371]
  PIN oy[372]
    DIRECTION INPUT ;
    USE SIGNAL ;
    PORT
      LAYER M4 ;
        RECT  0 17.808 0.084 17.832 ;
    END
  END oy[372]
  PIN oy[373]
    DIRECTION INPUT ;
    USE SIGNAL ;
    PORT
      LAYER M4 ;
        RECT  0 17.904 0.084 17.928 ;
    END
  END oy[373]
  PIN oy[374]
    DIRECTION INPUT ;
    USE SIGNAL ;
    PORT
      LAYER M4 ;
        RECT  0 18 0.084 18.024 ;
    END
  END oy[374]
  PIN oy[375]
    DIRECTION INPUT ;
    USE SIGNAL ;
    PORT
      LAYER M4 ;
        RECT  0 18.096 0.084 18.12 ;
    END
  END oy[375]
  PIN oy[376]
    DIRECTION INPUT ;
    USE SIGNAL ;
    PORT
      LAYER M4 ;
        RECT  0 18.192 0.084 18.216 ;
    END
  END oy[376]
  PIN oy[377]
    DIRECTION INPUT ;
    USE SIGNAL ;
    PORT
      LAYER M4 ;
        RECT  0 18.288 0.084 18.312 ;
    END
  END oy[377]
  PIN oy[378]
    DIRECTION INPUT ;
    USE SIGNAL ;
    PORT
      LAYER M4 ;
        RECT  0 18.384 0.084 18.408 ;
    END
  END oy[378]
  PIN oy[379]
    DIRECTION INPUT ;
    USE SIGNAL ;
    PORT
      LAYER M4 ;
        RECT  0 18.48 0.084 18.504 ;
    END
  END oy[379]
  PIN oy[37]
    DIRECTION INPUT ;
    USE SIGNAL ;
    PORT
      LAYER M4 ;
        RECT  0 38.64 0.084 38.664 ;
    END
  END oy[37]
  PIN oy[380]
    DIRECTION INPUT ;
    USE SIGNAL ;
    PORT
      LAYER M4 ;
        RECT  0 18.576 0.084 18.6 ;
    END
  END oy[380]
  PIN oy[381]
    DIRECTION INPUT ;
    USE SIGNAL ;
    PORT
      LAYER M4 ;
        RECT  0 18.672 0.084 18.696 ;
    END
  END oy[381]
  PIN oy[382]
    DIRECTION INPUT ;
    USE SIGNAL ;
    PORT
      LAYER M4 ;
        RECT  0 18.768 0.084 18.792 ;
    END
  END oy[382]
  PIN oy[383]
    DIRECTION INPUT ;
    USE SIGNAL ;
    PORT
      LAYER M4 ;
        RECT  0 21.936 0.084 21.96 ;
    END
  END oy[383]
  PIN oy[384]
    DIRECTION INPUT ;
    USE SIGNAL ;
    PORT
      LAYER M4 ;
        RECT  0 22.032 0.084 22.056 ;
    END
  END oy[384]
  PIN oy[385]
    DIRECTION INPUT ;
    USE SIGNAL ;
    PORT
      LAYER M4 ;
        RECT  0 22.128 0.084 22.152 ;
    END
  END oy[385]
  PIN oy[386]
    DIRECTION INPUT ;
    USE SIGNAL ;
    PORT
      LAYER M4 ;
        RECT  0 22.224 0.084 22.248 ;
    END
  END oy[386]
  PIN oy[387]
    DIRECTION INPUT ;
    USE SIGNAL ;
    PORT
      LAYER M4 ;
        RECT  0 22.32 0.084 22.344 ;
    END
  END oy[387]
  PIN oy[388]
    DIRECTION INPUT ;
    USE SIGNAL ;
    PORT
      LAYER M4 ;
        RECT  0 22.416 0.084 22.44 ;
    END
  END oy[388]
  PIN oy[389]
    DIRECTION INPUT ;
    USE SIGNAL ;
    PORT
      LAYER M4 ;
        RECT  0 22.512 0.084 22.536 ;
    END
  END oy[389]
  PIN oy[38]
    DIRECTION INPUT ;
    USE SIGNAL ;
    PORT
      LAYER M4 ;
        RECT  0 38.736 0.084 38.76 ;
    END
  END oy[38]
  PIN oy[390]
    DIRECTION INPUT ;
    USE SIGNAL ;
    PORT
      LAYER M4 ;
        RECT  0 22.608 0.084 22.632 ;
    END
  END oy[390]
  PIN oy[391]
    DIRECTION INPUT ;
    USE SIGNAL ;
    PORT
      LAYER M4 ;
        RECT  0 22.704 0.084 22.728 ;
    END
  END oy[391]
  PIN oy[392]
    DIRECTION INPUT ;
    USE SIGNAL ;
    PORT
      LAYER M4 ;
        RECT  0 22.8 0.084 22.824 ;
    END
  END oy[392]
  PIN oy[393]
    DIRECTION INPUT ;
    USE SIGNAL ;
    PORT
      LAYER M4 ;
        RECT  0 22.896 0.084 22.92 ;
    END
  END oy[393]
  PIN oy[394]
    DIRECTION INPUT ;
    USE SIGNAL ;
    PORT
      LAYER M4 ;
        RECT  0 22.992 0.084 23.016 ;
    END
  END oy[394]
  PIN oy[395]
    DIRECTION INPUT ;
    USE SIGNAL ;
    PORT
      LAYER M4 ;
        RECT  0 23.088 0.084 23.112 ;
    END
  END oy[395]
  PIN oy[396]
    DIRECTION INPUT ;
    USE SIGNAL ;
    PORT
      LAYER M4 ;
        RECT  0 23.184 0.084 23.208 ;
    END
  END oy[396]
  PIN oy[397]
    DIRECTION INPUT ;
    USE SIGNAL ;
    PORT
      LAYER M4 ;
        RECT  0 23.28 0.084 23.304 ;
    END
  END oy[397]
  PIN oy[398]
    DIRECTION INPUT ;
    USE SIGNAL ;
    PORT
      LAYER M4 ;
        RECT  0 23.376 0.084 23.4 ;
    END
  END oy[398]
  PIN oy[399]
    DIRECTION INPUT ;
    USE SIGNAL ;
    PORT
      LAYER M4 ;
        RECT  0 23.472 0.084 23.496 ;
    END
  END oy[399]
  PIN oy[39]
    DIRECTION INPUT ;
    USE SIGNAL ;
    PORT
      LAYER M4 ;
        RECT  0 38.832 0.084 38.856 ;
    END
  END oy[39]
  PIN oy[3]
    DIRECTION INPUT ;
    USE SIGNAL ;
    PORT
      LAYER M4 ;
        RECT  0 41.52 0.084 41.544 ;
    END
  END oy[3]
  PIN oy[400]
    DIRECTION INPUT ;
    USE SIGNAL ;
    PORT
      LAYER M4 ;
        RECT  0 23.568 0.084 23.592 ;
    END
  END oy[400]
  PIN oy[401]
    DIRECTION INPUT ;
    USE SIGNAL ;
    PORT
      LAYER M4 ;
        RECT  0 23.664 0.084 23.688 ;
    END
  END oy[401]
  PIN oy[402]
    DIRECTION INPUT ;
    USE SIGNAL ;
    PORT
      LAYER M4 ;
        RECT  0 23.76 0.084 23.784 ;
    END
  END oy[402]
  PIN oy[403]
    DIRECTION INPUT ;
    USE SIGNAL ;
    PORT
      LAYER M4 ;
        RECT  0 23.856 0.084 23.88 ;
    END
  END oy[403]
  PIN oy[404]
    DIRECTION INPUT ;
    USE SIGNAL ;
    PORT
      LAYER M4 ;
        RECT  0 23.952 0.084 23.976 ;
    END
  END oy[404]
  PIN oy[405]
    DIRECTION INPUT ;
    USE SIGNAL ;
    PORT
      LAYER M4 ;
        RECT  0 24.048 0.084 24.072 ;
    END
  END oy[405]
  PIN oy[406]
    DIRECTION INPUT ;
    USE SIGNAL ;
    PORT
      LAYER M4 ;
        RECT  0 24.144 0.084 24.168 ;
    END
  END oy[406]
  PIN oy[407]
    DIRECTION INPUT ;
    USE SIGNAL ;
    PORT
      LAYER M4 ;
        RECT  0 24.24 0.084 24.264 ;
    END
  END oy[407]
  PIN oy[408]
    DIRECTION INPUT ;
    USE SIGNAL ;
    PORT
      LAYER M4 ;
        RECT  0 24.336 0.084 24.36 ;
    END
  END oy[408]
  PIN oy[409]
    DIRECTION INPUT ;
    USE SIGNAL ;
    PORT
      LAYER M4 ;
        RECT  0 24.432 0.084 24.456 ;
    END
  END oy[409]
  PIN oy[40]
    DIRECTION INPUT ;
    USE SIGNAL ;
    PORT
      LAYER M4 ;
        RECT  0 38.928 0.084 38.952 ;
    END
  END oy[40]
  PIN oy[410]
    DIRECTION INPUT ;
    USE SIGNAL ;
    PORT
      LAYER M4 ;
        RECT  0 24.528 0.084 24.552 ;
    END
  END oy[410]
  PIN oy[411]
    DIRECTION INPUT ;
    USE SIGNAL ;
    PORT
      LAYER M4 ;
        RECT  0 24.624 0.084 24.648 ;
    END
  END oy[411]
  PIN oy[412]
    DIRECTION INPUT ;
    USE SIGNAL ;
    PORT
      LAYER M4 ;
        RECT  0 24.72 0.084 24.744 ;
    END
  END oy[412]
  PIN oy[413]
    DIRECTION INPUT ;
    USE SIGNAL ;
    PORT
      LAYER M4 ;
        RECT  0 24.816 0.084 24.84 ;
    END
  END oy[413]
  PIN oy[414]
    DIRECTION INPUT ;
    USE SIGNAL ;
    PORT
      LAYER M4 ;
        RECT  0 24.912 0.084 24.936 ;
    END
  END oy[414]
  PIN oy[415]
    DIRECTION INPUT ;
    USE SIGNAL ;
    PORT
      LAYER M4 ;
        RECT  0 25.008 0.084 25.032 ;
    END
  END oy[415]
  PIN oy[416]
    DIRECTION INPUT ;
    USE SIGNAL ;
    PORT
      LAYER M4 ;
        RECT  0 25.104 0.084 25.128 ;
    END
  END oy[416]
  PIN oy[417]
    DIRECTION INPUT ;
    USE SIGNAL ;
    PORT
      LAYER M4 ;
        RECT  0 25.2 0.084 25.224 ;
    END
  END oy[417]
  PIN oy[418]
    DIRECTION INPUT ;
    USE SIGNAL ;
    PORT
      LAYER M4 ;
        RECT  0 25.296 0.084 25.32 ;
    END
  END oy[418]
  PIN oy[419]
    DIRECTION INPUT ;
    USE SIGNAL ;
    PORT
      LAYER M4 ;
        RECT  0 25.392 0.084 25.416 ;
    END
  END oy[419]
  PIN oy[41]
    DIRECTION INPUT ;
    USE SIGNAL ;
    PORT
      LAYER M4 ;
        RECT  0 39.024 0.084 39.048 ;
    END
  END oy[41]
  PIN oy[420]
    DIRECTION INPUT ;
    USE SIGNAL ;
    PORT
      LAYER M4 ;
        RECT  0 25.488 0.084 25.512 ;
    END
  END oy[420]
  PIN oy[421]
    DIRECTION INPUT ;
    USE SIGNAL ;
    PORT
      LAYER M4 ;
        RECT  0 25.584 0.084 25.608 ;
    END
  END oy[421]
  PIN oy[422]
    DIRECTION INPUT ;
    USE SIGNAL ;
    PORT
      LAYER M4 ;
        RECT  0 25.68 0.084 25.704 ;
    END
  END oy[422]
  PIN oy[423]
    DIRECTION INPUT ;
    USE SIGNAL ;
    PORT
      LAYER M4 ;
        RECT  0 25.776 0.084 25.8 ;
    END
  END oy[423]
  PIN oy[424]
    DIRECTION INPUT ;
    USE SIGNAL ;
    PORT
      LAYER M4 ;
        RECT  0 25.872 0.084 25.896 ;
    END
  END oy[424]
  PIN oy[425]
    DIRECTION INPUT ;
    USE SIGNAL ;
    PORT
      LAYER M4 ;
        RECT  0 25.968 0.084 25.992 ;
    END
  END oy[425]
  PIN oy[426]
    DIRECTION INPUT ;
    USE SIGNAL ;
    PORT
      LAYER M4 ;
        RECT  0 26.064 0.084 26.088 ;
    END
  END oy[426]
  PIN oy[427]
    DIRECTION INPUT ;
    USE SIGNAL ;
    PORT
      LAYER M4 ;
        RECT  0 26.16 0.084 26.184 ;
    END
  END oy[427]
  PIN oy[428]
    DIRECTION INPUT ;
    USE SIGNAL ;
    PORT
      LAYER M4 ;
        RECT  0 26.256 0.084 26.28 ;
    END
  END oy[428]
  PIN oy[429]
    DIRECTION INPUT ;
    USE SIGNAL ;
    PORT
      LAYER M4 ;
        RECT  0 26.352 0.084 26.376 ;
    END
  END oy[429]
  PIN oy[42]
    DIRECTION INPUT ;
    USE SIGNAL ;
    PORT
      LAYER M4 ;
        RECT  0 39.12 0.084 39.144 ;
    END
  END oy[42]
  PIN oy[430]
    DIRECTION INPUT ;
    USE SIGNAL ;
    PORT
      LAYER M4 ;
        RECT  0 26.448 0.084 26.472 ;
    END
  END oy[430]
  PIN oy[431]
    DIRECTION INPUT ;
    USE SIGNAL ;
    PORT
      LAYER M4 ;
        RECT  0 26.544 0.084 26.568 ;
    END
  END oy[431]
  PIN oy[432]
    DIRECTION INPUT ;
    USE SIGNAL ;
    PORT
      LAYER M4 ;
        RECT  0 26.64 0.084 26.664 ;
    END
  END oy[432]
  PIN oy[433]
    DIRECTION INPUT ;
    USE SIGNAL ;
    PORT
      LAYER M4 ;
        RECT  0 26.736 0.084 26.76 ;
    END
  END oy[433]
  PIN oy[434]
    DIRECTION INPUT ;
    USE SIGNAL ;
    PORT
      LAYER M4 ;
        RECT  0 26.832 0.084 26.856 ;
    END
  END oy[434]
  PIN oy[435]
    DIRECTION INPUT ;
    USE SIGNAL ;
    PORT
      LAYER M4 ;
        RECT  0 26.928 0.084 26.952 ;
    END
  END oy[435]
  PIN oy[436]
    DIRECTION INPUT ;
    USE SIGNAL ;
    PORT
      LAYER M4 ;
        RECT  0 27.024 0.084 27.048 ;
    END
  END oy[436]
  PIN oy[437]
    DIRECTION INPUT ;
    USE SIGNAL ;
    PORT
      LAYER M4 ;
        RECT  0 27.12 0.084 27.144 ;
    END
  END oy[437]
  PIN oy[438]
    DIRECTION INPUT ;
    USE SIGNAL ;
    PORT
      LAYER M4 ;
        RECT  0 27.216 0.084 27.24 ;
    END
  END oy[438]
  PIN oy[439]
    DIRECTION INPUT ;
    USE SIGNAL ;
    PORT
      LAYER M4 ;
        RECT  0 27.312 0.084 27.336 ;
    END
  END oy[439]
  PIN oy[43]
    DIRECTION INPUT ;
    USE SIGNAL ;
    PORT
      LAYER M4 ;
        RECT  0 39.216 0.084 39.24 ;
    END
  END oy[43]
  PIN oy[440]
    DIRECTION INPUT ;
    USE SIGNAL ;
    PORT
      LAYER M4 ;
        RECT  0 27.408 0.084 27.432 ;
    END
  END oy[440]
  PIN oy[441]
    DIRECTION INPUT ;
    USE SIGNAL ;
    PORT
      LAYER M4 ;
        RECT  0 27.504 0.084 27.528 ;
    END
  END oy[441]
  PIN oy[442]
    DIRECTION INPUT ;
    USE SIGNAL ;
    PORT
      LAYER M4 ;
        RECT  0 27.6 0.084 27.624 ;
    END
  END oy[442]
  PIN oy[443]
    DIRECTION INPUT ;
    USE SIGNAL ;
    PORT
      LAYER M4 ;
        RECT  0 27.696 0.084 27.72 ;
    END
  END oy[443]
  PIN oy[444]
    DIRECTION INPUT ;
    USE SIGNAL ;
    PORT
      LAYER M4 ;
        RECT  0 27.792 0.084 27.816 ;
    END
  END oy[444]
  PIN oy[445]
    DIRECTION INPUT ;
    USE SIGNAL ;
    PORT
      LAYER M4 ;
        RECT  0 27.888 0.084 27.912 ;
    END
  END oy[445]
  PIN oy[446]
    DIRECTION INPUT ;
    USE SIGNAL ;
    PORT
      LAYER M4 ;
        RECT  0 27.984 0.084 28.008 ;
    END
  END oy[446]
  PIN oy[447]
    DIRECTION INPUT ;
    USE SIGNAL ;
    PORT
      LAYER M4 ;
        RECT  0 67.248 0.084 67.272 ;
    END
  END oy[447]
  PIN oy[448]
    DIRECTION INPUT ;
    USE SIGNAL ;
    PORT
      LAYER M4 ;
        RECT  0 67.344 0.084 67.368 ;
    END
  END oy[448]
  PIN oy[449]
    DIRECTION INPUT ;
    USE SIGNAL ;
    PORT
      LAYER M4 ;
        RECT  0 67.44 0.084 67.464 ;
    END
  END oy[449]
  PIN oy[44]
    DIRECTION INPUT ;
    USE SIGNAL ;
    PORT
      LAYER M4 ;
        RECT  0 39.312 0.084 39.336 ;
    END
  END oy[44]
  PIN oy[450]
    DIRECTION INPUT ;
    USE SIGNAL ;
    PORT
      LAYER M4 ;
        RECT  0 67.536 0.084 67.56 ;
    END
  END oy[450]
  PIN oy[451]
    DIRECTION INPUT ;
    USE SIGNAL ;
    PORT
      LAYER M4 ;
        RECT  0 67.632 0.084 67.656 ;
    END
  END oy[451]
  PIN oy[452]
    DIRECTION INPUT ;
    USE SIGNAL ;
    PORT
      LAYER M4 ;
        RECT  0 67.728 0.084 67.752 ;
    END
  END oy[452]
  PIN oy[453]
    DIRECTION INPUT ;
    USE SIGNAL ;
    PORT
      LAYER M4 ;
        RECT  0 67.824 0.084 67.848 ;
    END
  END oy[453]
  PIN oy[454]
    DIRECTION INPUT ;
    USE SIGNAL ;
    PORT
      LAYER M4 ;
        RECT  0 67.92 0.084 67.944 ;
    END
  END oy[454]
  PIN oy[455]
    DIRECTION INPUT ;
    USE SIGNAL ;
    PORT
      LAYER M4 ;
        RECT  0 68.016 0.084 68.04 ;
    END
  END oy[455]
  PIN oy[456]
    DIRECTION INPUT ;
    USE SIGNAL ;
    PORT
      LAYER M4 ;
        RECT  0 68.112 0.084 68.136 ;
    END
  END oy[456]
  PIN oy[457]
    DIRECTION INPUT ;
    USE SIGNAL ;
    PORT
      LAYER M4 ;
        RECT  0 68.208 0.084 68.232 ;
    END
  END oy[457]
  PIN oy[458]
    DIRECTION INPUT ;
    USE SIGNAL ;
    PORT
      LAYER M4 ;
        RECT  0 68.304 0.084 68.328 ;
    END
  END oy[458]
  PIN oy[459]
    DIRECTION INPUT ;
    USE SIGNAL ;
    PORT
      LAYER M4 ;
        RECT  0 68.4 0.084 68.424 ;
    END
  END oy[459]
  PIN oy[45]
    DIRECTION INPUT ;
    USE SIGNAL ;
    PORT
      LAYER M4 ;
        RECT  0 39.408 0.084 39.432 ;
    END
  END oy[45]
  PIN oy[460]
    DIRECTION INPUT ;
    USE SIGNAL ;
    PORT
      LAYER M4 ;
        RECT  0 68.496 0.084 68.52 ;
    END
  END oy[460]
  PIN oy[461]
    DIRECTION INPUT ;
    USE SIGNAL ;
    PORT
      LAYER M4 ;
        RECT  0 68.592 0.084 68.616 ;
    END
  END oy[461]
  PIN oy[462]
    DIRECTION INPUT ;
    USE SIGNAL ;
    PORT
      LAYER M4 ;
        RECT  0 68.688 0.084 68.712 ;
    END
  END oy[462]
  PIN oy[463]
    DIRECTION INPUT ;
    USE SIGNAL ;
    PORT
      LAYER M4 ;
        RECT  0 68.784 0.084 68.808 ;
    END
  END oy[463]
  PIN oy[464]
    DIRECTION INPUT ;
    USE SIGNAL ;
    PORT
      LAYER M4 ;
        RECT  0 68.88 0.084 68.904 ;
    END
  END oy[464]
  PIN oy[465]
    DIRECTION INPUT ;
    USE SIGNAL ;
    PORT
      LAYER M4 ;
        RECT  0 68.976 0.084 69 ;
    END
  END oy[465]
  PIN oy[466]
    DIRECTION INPUT ;
    USE SIGNAL ;
    PORT
      LAYER M4 ;
        RECT  0 69.072 0.084 69.096 ;
    END
  END oy[466]
  PIN oy[467]
    DIRECTION INPUT ;
    USE SIGNAL ;
    PORT
      LAYER M4 ;
        RECT  0 69.168 0.084 69.192 ;
    END
  END oy[467]
  PIN oy[468]
    DIRECTION INPUT ;
    USE SIGNAL ;
    PORT
      LAYER M4 ;
        RECT  0 69.264 0.084 69.288 ;
    END
  END oy[468]
  PIN oy[469]
    DIRECTION INPUT ;
    USE SIGNAL ;
    PORT
      LAYER M4 ;
        RECT  0 69.36 0.084 69.384 ;
    END
  END oy[469]
  PIN oy[46]
    DIRECTION INPUT ;
    USE SIGNAL ;
    PORT
      LAYER M4 ;
        RECT  0 39.504 0.084 39.528 ;
    END
  END oy[46]
  PIN oy[470]
    DIRECTION INPUT ;
    USE SIGNAL ;
    PORT
      LAYER M4 ;
        RECT  0 69.456 0.084 69.48 ;
    END
  END oy[470]
  PIN oy[471]
    DIRECTION INPUT ;
    USE SIGNAL ;
    PORT
      LAYER M4 ;
        RECT  0 69.552 0.084 69.576 ;
    END
  END oy[471]
  PIN oy[472]
    DIRECTION INPUT ;
    USE SIGNAL ;
    PORT
      LAYER M4 ;
        RECT  0 69.648 0.084 69.672 ;
    END
  END oy[472]
  PIN oy[473]
    DIRECTION INPUT ;
    USE SIGNAL ;
    PORT
      LAYER M4 ;
        RECT  0 69.744 0.084 69.768 ;
    END
  END oy[473]
  PIN oy[474]
    DIRECTION INPUT ;
    USE SIGNAL ;
    PORT
      LAYER M4 ;
        RECT  0 69.84 0.084 69.864 ;
    END
  END oy[474]
  PIN oy[475]
    DIRECTION INPUT ;
    USE SIGNAL ;
    PORT
      LAYER M4 ;
        RECT  0 69.936 0.084 69.96 ;
    END
  END oy[475]
  PIN oy[476]
    DIRECTION INPUT ;
    USE SIGNAL ;
    PORT
      LAYER M4 ;
        RECT  0 70.032 0.084 70.056 ;
    END
  END oy[476]
  PIN oy[477]
    DIRECTION INPUT ;
    USE SIGNAL ;
    PORT
      LAYER M4 ;
        RECT  0 70.128 0.084 70.152 ;
    END
  END oy[477]
  PIN oy[478]
    DIRECTION INPUT ;
    USE SIGNAL ;
    PORT
      LAYER M4 ;
        RECT  0 70.224 0.084 70.248 ;
    END
  END oy[478]
  PIN oy[479]
    DIRECTION INPUT ;
    USE SIGNAL ;
    PORT
      LAYER M4 ;
        RECT  0 18.864 0.084 18.888 ;
    END
  END oy[479]
  PIN oy[47]
    DIRECTION INPUT ;
    USE SIGNAL ;
    PORT
      LAYER M4 ;
        RECT  0 39.6 0.084 39.624 ;
    END
  END oy[47]
  PIN oy[480]
    DIRECTION INPUT ;
    USE SIGNAL ;
    PORT
      LAYER M4 ;
        RECT  0 18.96 0.084 18.984 ;
    END
  END oy[480]
  PIN oy[481]
    DIRECTION INPUT ;
    USE SIGNAL ;
    PORT
      LAYER M4 ;
        RECT  0 19.056 0.084 19.08 ;
    END
  END oy[481]
  PIN oy[482]
    DIRECTION INPUT ;
    USE SIGNAL ;
    PORT
      LAYER M4 ;
        RECT  0 19.152 0.084 19.176 ;
    END
  END oy[482]
  PIN oy[483]
    DIRECTION INPUT ;
    USE SIGNAL ;
    PORT
      LAYER M4 ;
        RECT  0 19.248 0.084 19.272 ;
    END
  END oy[483]
  PIN oy[484]
    DIRECTION INPUT ;
    USE SIGNAL ;
    PORT
      LAYER M4 ;
        RECT  0 19.344 0.084 19.368 ;
    END
  END oy[484]
  PIN oy[485]
    DIRECTION INPUT ;
    USE SIGNAL ;
    PORT
      LAYER M4 ;
        RECT  0 19.44 0.084 19.464 ;
    END
  END oy[485]
  PIN oy[486]
    DIRECTION INPUT ;
    USE SIGNAL ;
    PORT
      LAYER M4 ;
        RECT  0 19.536 0.084 19.56 ;
    END
  END oy[486]
  PIN oy[487]
    DIRECTION INPUT ;
    USE SIGNAL ;
    PORT
      LAYER M4 ;
        RECT  0 19.632 0.084 19.656 ;
    END
  END oy[487]
  PIN oy[488]
    DIRECTION INPUT ;
    USE SIGNAL ;
    PORT
      LAYER M4 ;
        RECT  0 19.728 0.084 19.752 ;
    END
  END oy[488]
  PIN oy[489]
    DIRECTION INPUT ;
    USE SIGNAL ;
    PORT
      LAYER M4 ;
        RECT  0 19.824 0.084 19.848 ;
    END
  END oy[489]
  PIN oy[48]
    DIRECTION INPUT ;
    USE SIGNAL ;
    PORT
      LAYER M4 ;
        RECT  0 39.696 0.084 39.72 ;
    END
  END oy[48]
  PIN oy[490]
    DIRECTION INPUT ;
    USE SIGNAL ;
    PORT
      LAYER M4 ;
        RECT  0 19.92 0.084 19.944 ;
    END
  END oy[490]
  PIN oy[491]
    DIRECTION INPUT ;
    USE SIGNAL ;
    PORT
      LAYER M4 ;
        RECT  0 20.016 0.084 20.04 ;
    END
  END oy[491]
  PIN oy[492]
    DIRECTION INPUT ;
    USE SIGNAL ;
    PORT
      LAYER M4 ;
        RECT  0 20.112 0.084 20.136 ;
    END
  END oy[492]
  PIN oy[493]
    DIRECTION INPUT ;
    USE SIGNAL ;
    PORT
      LAYER M4 ;
        RECT  0 20.208 0.084 20.232 ;
    END
  END oy[493]
  PIN oy[494]
    DIRECTION INPUT ;
    USE SIGNAL ;
    PORT
      LAYER M4 ;
        RECT  0 20.304 0.084 20.328 ;
    END
  END oy[494]
  PIN oy[495]
    DIRECTION INPUT ;
    USE SIGNAL ;
    PORT
      LAYER M4 ;
        RECT  0 20.4 0.084 20.424 ;
    END
  END oy[495]
  PIN oy[496]
    DIRECTION INPUT ;
    USE SIGNAL ;
    PORT
      LAYER M4 ;
        RECT  0 20.496 0.084 20.52 ;
    END
  END oy[496]
  PIN oy[497]
    DIRECTION INPUT ;
    USE SIGNAL ;
    PORT
      LAYER M4 ;
        RECT  0 20.592 0.084 20.616 ;
    END
  END oy[497]
  PIN oy[498]
    DIRECTION INPUT ;
    USE SIGNAL ;
    PORT
      LAYER M4 ;
        RECT  0 20.688 0.084 20.712 ;
    END
  END oy[498]
  PIN oy[499]
    DIRECTION INPUT ;
    USE SIGNAL ;
    PORT
      LAYER M4 ;
        RECT  0 20.784 0.084 20.808 ;
    END
  END oy[499]
  PIN oy[49]
    DIRECTION INPUT ;
    USE SIGNAL ;
    PORT
      LAYER M4 ;
        RECT  0 39.792 0.084 39.816 ;
    END
  END oy[49]
  PIN oy[4]
    DIRECTION INPUT ;
    USE SIGNAL ;
    PORT
      LAYER M4 ;
        RECT  0 41.616 0.084 41.64 ;
    END
  END oy[4]
  PIN oy[500]
    DIRECTION INPUT ;
    USE SIGNAL ;
    PORT
      LAYER M4 ;
        RECT  0 20.88 0.084 20.904 ;
    END
  END oy[500]
  PIN oy[501]
    DIRECTION INPUT ;
    USE SIGNAL ;
    PORT
      LAYER M4 ;
        RECT  0 20.976 0.084 21 ;
    END
  END oy[501]
  PIN oy[502]
    DIRECTION INPUT ;
    USE SIGNAL ;
    PORT
      LAYER M4 ;
        RECT  0 21.072 0.084 21.096 ;
    END
  END oy[502]
  PIN oy[503]
    DIRECTION INPUT ;
    USE SIGNAL ;
    PORT
      LAYER M4 ;
        RECT  0 21.168 0.084 21.192 ;
    END
  END oy[503]
  PIN oy[504]
    DIRECTION INPUT ;
    USE SIGNAL ;
    PORT
      LAYER M4 ;
        RECT  0 21.264 0.084 21.288 ;
    END
  END oy[504]
  PIN oy[505]
    DIRECTION INPUT ;
    USE SIGNAL ;
    PORT
      LAYER M4 ;
        RECT  0 21.36 0.084 21.384 ;
    END
  END oy[505]
  PIN oy[506]
    DIRECTION INPUT ;
    USE SIGNAL ;
    PORT
      LAYER M4 ;
        RECT  0 21.456 0.084 21.48 ;
    END
  END oy[506]
  PIN oy[507]
    DIRECTION INPUT ;
    USE SIGNAL ;
    PORT
      LAYER M4 ;
        RECT  0 21.552 0.084 21.576 ;
    END
  END oy[507]
  PIN oy[508]
    DIRECTION INPUT ;
    USE SIGNAL ;
    PORT
      LAYER M4 ;
        RECT  0 21.648 0.084 21.672 ;
    END
  END oy[508]
  PIN oy[509]
    DIRECTION INPUT ;
    USE SIGNAL ;
    PORT
      LAYER M4 ;
        RECT  0 21.744 0.084 21.768 ;
    END
  END oy[509]
  PIN oy[50]
    DIRECTION INPUT ;
    USE SIGNAL ;
    PORT
      LAYER M4 ;
        RECT  0 39.888 0.084 39.912 ;
    END
  END oy[50]
  PIN oy[510]
    DIRECTION INPUT ;
    USE SIGNAL ;
    PORT
      LAYER M4 ;
        RECT  0 21.84 0.084 21.864 ;
    END
  END oy[510]
  PIN oy[511]
    DIRECTION INPUT ;
    USE SIGNAL ;
    PORT
      LAYER M4 ;
        RECT  0 28.752 0.084 28.776 ;
    END
  END oy[511]
  PIN oy[51]
    DIRECTION INPUT ;
    USE SIGNAL ;
    PORT
      LAYER M4 ;
        RECT  0 39.984 0.084 40.008 ;
    END
  END oy[51]
  PIN oy[52]
    DIRECTION INPUT ;
    USE SIGNAL ;
    PORT
      LAYER M4 ;
        RECT  0 40.08 0.084 40.104 ;
    END
  END oy[52]
  PIN oy[53]
    DIRECTION INPUT ;
    USE SIGNAL ;
    PORT
      LAYER M4 ;
        RECT  0 40.176 0.084 40.2 ;
    END
  END oy[53]
  PIN oy[54]
    DIRECTION INPUT ;
    USE SIGNAL ;
    PORT
      LAYER M4 ;
        RECT  0 40.272 0.084 40.296 ;
    END
  END oy[54]
  PIN oy[55]
    DIRECTION INPUT ;
    USE SIGNAL ;
    PORT
      LAYER M4 ;
        RECT  0 40.368 0.084 40.392 ;
    END
  END oy[55]
  PIN oy[56]
    DIRECTION INPUT ;
    USE SIGNAL ;
    PORT
      LAYER M4 ;
        RECT  0 40.464 0.084 40.488 ;
    END
  END oy[56]
  PIN oy[57]
    DIRECTION INPUT ;
    USE SIGNAL ;
    PORT
      LAYER M4 ;
        RECT  0 40.56 0.084 40.584 ;
    END
  END oy[57]
  PIN oy[58]
    DIRECTION INPUT ;
    USE SIGNAL ;
    PORT
      LAYER M4 ;
        RECT  0 40.656 0.084 40.68 ;
    END
  END oy[58]
  PIN oy[59]
    DIRECTION INPUT ;
    USE SIGNAL ;
    PORT
      LAYER M4 ;
        RECT  0 40.752 0.084 40.776 ;
    END
  END oy[59]
  PIN oy[5]
    DIRECTION INPUT ;
    USE SIGNAL ;
    PORT
      LAYER M4 ;
        RECT  0 41.712 0.084 41.736 ;
    END
  END oy[5]
  PIN oy[60]
    DIRECTION INPUT ;
    USE SIGNAL ;
    PORT
      LAYER M4 ;
        RECT  0 40.848 0.084 40.872 ;
    END
  END oy[60]
  PIN oy[61]
    DIRECTION INPUT ;
    USE SIGNAL ;
    PORT
      LAYER M4 ;
        RECT  0 40.944 0.084 40.968 ;
    END
  END oy[61]
  PIN oy[62]
    DIRECTION INPUT ;
    USE SIGNAL ;
    PORT
      LAYER M4 ;
        RECT  0 41.04 0.084 41.064 ;
    END
  END oy[62]
  PIN oy[63]
    DIRECTION INPUT ;
    USE SIGNAL ;
    PORT
      LAYER M4 ;
        RECT  0 31.92 0.084 31.944 ;
    END
  END oy[63]
  PIN oy[64]
    DIRECTION INPUT ;
    USE SIGNAL ;
    PORT
      LAYER M4 ;
        RECT  0 32.016 0.084 32.04 ;
    END
  END oy[64]
  PIN oy[65]
    DIRECTION INPUT ;
    USE SIGNAL ;
    PORT
      LAYER M4 ;
        RECT  0 32.112 0.084 32.136 ;
    END
  END oy[65]
  PIN oy[66]
    DIRECTION INPUT ;
    USE SIGNAL ;
    PORT
      LAYER M4 ;
        RECT  0 32.208 0.084 32.232 ;
    END
  END oy[66]
  PIN oy[67]
    DIRECTION INPUT ;
    USE SIGNAL ;
    PORT
      LAYER M4 ;
        RECT  0 32.304 0.084 32.328 ;
    END
  END oy[67]
  PIN oy[68]
    DIRECTION INPUT ;
    USE SIGNAL ;
    PORT
      LAYER M4 ;
        RECT  0 32.4 0.084 32.424 ;
    END
  END oy[68]
  PIN oy[69]
    DIRECTION INPUT ;
    USE SIGNAL ;
    PORT
      LAYER M4 ;
        RECT  0 32.496 0.084 32.52 ;
    END
  END oy[69]
  PIN oy[6]
    DIRECTION INPUT ;
    USE SIGNAL ;
    PORT
      LAYER M4 ;
        RECT  0 41.808 0.084 41.832 ;
    END
  END oy[6]
  PIN oy[70]
    DIRECTION INPUT ;
    USE SIGNAL ;
    PORT
      LAYER M4 ;
        RECT  0 32.592 0.084 32.616 ;
    END
  END oy[70]
  PIN oy[71]
    DIRECTION INPUT ;
    USE SIGNAL ;
    PORT
      LAYER M4 ;
        RECT  0 32.688 0.084 32.712 ;
    END
  END oy[71]
  PIN oy[72]
    DIRECTION INPUT ;
    USE SIGNAL ;
    PORT
      LAYER M4 ;
        RECT  0 32.784 0.084 32.808 ;
    END
  END oy[72]
  PIN oy[73]
    DIRECTION INPUT ;
    USE SIGNAL ;
    PORT
      LAYER M4 ;
        RECT  0 32.88 0.084 32.904 ;
    END
  END oy[73]
  PIN oy[74]
    DIRECTION INPUT ;
    USE SIGNAL ;
    PORT
      LAYER M4 ;
        RECT  0 32.976 0.084 33 ;
    END
  END oy[74]
  PIN oy[75]
    DIRECTION INPUT ;
    USE SIGNAL ;
    PORT
      LAYER M4 ;
        RECT  0 33.072 0.084 33.096 ;
    END
  END oy[75]
  PIN oy[76]
    DIRECTION INPUT ;
    USE SIGNAL ;
    PORT
      LAYER M4 ;
        RECT  0 33.168 0.084 33.192 ;
    END
  END oy[76]
  PIN oy[77]
    DIRECTION INPUT ;
    USE SIGNAL ;
    PORT
      LAYER M4 ;
        RECT  0 33.264 0.084 33.288 ;
    END
  END oy[77]
  PIN oy[78]
    DIRECTION INPUT ;
    USE SIGNAL ;
    PORT
      LAYER M4 ;
        RECT  0 33.36 0.084 33.384 ;
    END
  END oy[78]
  PIN oy[79]
    DIRECTION INPUT ;
    USE SIGNAL ;
    PORT
      LAYER M4 ;
        RECT  0 33.456 0.084 33.48 ;
    END
  END oy[79]
  PIN oy[7]
    DIRECTION INPUT ;
    USE SIGNAL ;
    PORT
      LAYER M4 ;
        RECT  0 41.904 0.084 41.928 ;
    END
  END oy[7]
  PIN oy[80]
    DIRECTION INPUT ;
    USE SIGNAL ;
    PORT
      LAYER M4 ;
        RECT  0 33.552 0.084 33.576 ;
    END
  END oy[80]
  PIN oy[81]
    DIRECTION INPUT ;
    USE SIGNAL ;
    PORT
      LAYER M4 ;
        RECT  0 33.648 0.084 33.672 ;
    END
  END oy[81]
  PIN oy[82]
    DIRECTION INPUT ;
    USE SIGNAL ;
    PORT
      LAYER M4 ;
        RECT  0 33.744 0.084 33.768 ;
    END
  END oy[82]
  PIN oy[83]
    DIRECTION INPUT ;
    USE SIGNAL ;
    PORT
      LAYER M4 ;
        RECT  0 33.84 0.084 33.864 ;
    END
  END oy[83]
  PIN oy[84]
    DIRECTION INPUT ;
    USE SIGNAL ;
    PORT
      LAYER M4 ;
        RECT  0 33.936 0.084 33.96 ;
    END
  END oy[84]
  PIN oy[85]
    DIRECTION INPUT ;
    USE SIGNAL ;
    PORT
      LAYER M4 ;
        RECT  0 34.032 0.084 34.056 ;
    END
  END oy[85]
  PIN oy[86]
    DIRECTION INPUT ;
    USE SIGNAL ;
    PORT
      LAYER M4 ;
        RECT  0 34.128 0.084 34.152 ;
    END
  END oy[86]
  PIN oy[87]
    DIRECTION INPUT ;
    USE SIGNAL ;
    PORT
      LAYER M4 ;
        RECT  0 34.224 0.084 34.248 ;
    END
  END oy[87]
  PIN oy[88]
    DIRECTION INPUT ;
    USE SIGNAL ;
    PORT
      LAYER M4 ;
        RECT  0 34.32 0.084 34.344 ;
    END
  END oy[88]
  PIN oy[89]
    DIRECTION INPUT ;
    USE SIGNAL ;
    PORT
      LAYER M4 ;
        RECT  0 34.416 0.084 34.44 ;
    END
  END oy[89]
  PIN oy[8]
    DIRECTION INPUT ;
    USE SIGNAL ;
    PORT
      LAYER M4 ;
        RECT  0 42 0.084 42.024 ;
    END
  END oy[8]
  PIN oy[90]
    DIRECTION INPUT ;
    USE SIGNAL ;
    PORT
      LAYER M4 ;
        RECT  0 34.512 0.084 34.536 ;
    END
  END oy[90]
  PIN oy[91]
    DIRECTION INPUT ;
    USE SIGNAL ;
    PORT
      LAYER M4 ;
        RECT  0 34.608 0.084 34.632 ;
    END
  END oy[91]
  PIN oy[92]
    DIRECTION INPUT ;
    USE SIGNAL ;
    PORT
      LAYER M4 ;
        RECT  0 34.704 0.084 34.728 ;
    END
  END oy[92]
  PIN oy[93]
    DIRECTION INPUT ;
    USE SIGNAL ;
    PORT
      LAYER M4 ;
        RECT  0 34.8 0.084 34.824 ;
    END
  END oy[93]
  PIN oy[94]
    DIRECTION INPUT ;
    USE SIGNAL ;
    PORT
      LAYER M4 ;
        RECT  0 34.896 0.084 34.92 ;
    END
  END oy[94]
  PIN oy[95]
    DIRECTION INPUT ;
    USE SIGNAL ;
    PORT
      LAYER M4 ;
        RECT  0 28.848 0.084 28.872 ;
    END
  END oy[95]
  PIN oy[96]
    DIRECTION INPUT ;
    USE SIGNAL ;
    PORT
      LAYER M4 ;
        RECT  0 28.944 0.084 28.968 ;
    END
  END oy[96]
  PIN oy[97]
    DIRECTION INPUT ;
    USE SIGNAL ;
    PORT
      LAYER M4 ;
        RECT  0 29.04 0.084 29.064 ;
    END
  END oy[97]
  PIN oy[98]
    DIRECTION INPUT ;
    USE SIGNAL ;
    PORT
      LAYER M4 ;
        RECT  0 29.136 0.084 29.16 ;
    END
  END oy[98]
  PIN oy[99]
    DIRECTION INPUT ;
    USE SIGNAL ;
    PORT
      LAYER M4 ;
        RECT  0 29.232 0.084 29.256 ;
    END
  END oy[99]
  PIN oy[9]
    DIRECTION INPUT ;
    USE SIGNAL ;
    PORT
      LAYER M4 ;
        RECT  0 42.096 0.084 42.12 ;
    END
  END oy[9]
  PIN VDD
    DIRECTION INOUT ;
    USE POWER ;
    PORT
      LAYER M5 ;
        RECT  83.592 2.151 83.712 84.249 ;
        RECT  78.192 2.151 78.312 84.249 ;
        RECT  72.792 2.151 72.912 84.249 ;
        RECT  67.392 2.151 67.512 84.249 ;
        RECT  61.992 2.151 62.112 84.249 ;
        RECT  56.592 2.151 56.712 84.249 ;
        RECT  51.192 2.151 51.312 84.249 ;
        RECT  45.792 2.151 45.912 84.249 ;
        RECT  40.392 2.151 40.512 84.249 ;
        RECT  34.992 2.151 35.112 84.249 ;
        RECT  29.592 2.151 29.712 84.249 ;
        RECT  24.192 2.151 24.312 84.249 ;
        RECT  18.792 2.151 18.912 84.249 ;
        RECT  13.392 2.151 13.512 84.249 ;
        RECT  7.992 2.151 8.112 84.249 ;
        RECT  2.592 2.151 2.712 84.249 ;
    END
  END VDD
  PIN VSS
    DIRECTION INOUT ;
    USE GROUND ;
    PORT
      LAYER M5 ;
        RECT  83.4 2.137 83.52 84.263 ;
        RECT  78 2.137 78.12 84.263 ;
        RECT  72.6 2.137 72.72 84.263 ;
        RECT  67.2 2.137 67.32 84.263 ;
        RECT  61.8 2.137 61.92 84.263 ;
        RECT  56.4 2.137 56.52 84.263 ;
        RECT  51 2.137 51.12 84.263 ;
        RECT  45.6 2.137 45.72 84.263 ;
        RECT  40.2 2.137 40.32 84.263 ;
        RECT  34.8 2.137 34.92 84.263 ;
        RECT  29.4 2.137 29.52 84.263 ;
        RECT  24 2.137 24.12 84.263 ;
        RECT  18.6 2.137 18.72 84.263 ;
        RECT  13.2 2.137 13.32 84.263 ;
        RECT  7.8 2.137 7.92 84.263 ;
        RECT  2.4 2.137 2.52 84.263 ;
    END
  END VSS
  OBS
    LAYER RVTN ;
     RECT  2.16 2.16 84.24 2.295 ;
     RECT  2.16 2.565 84.24 2.835 ;
     RECT  2.16 3.105 84.24 3.375 ;
     RECT  2.16 3.645 84.24 3.915 ;
     RECT  2.16 4.185 84.24 4.455 ;
     RECT  2.16 4.725 84.24 4.995 ;
     RECT  2.16 5.265 84.24 5.535 ;
     RECT  2.16 5.805 84.24 6.075 ;
     RECT  2.16 6.345 84.24 6.615 ;
     RECT  2.16 6.885 84.24 7.155 ;
     RECT  2.16 7.425 84.24 7.695 ;
     RECT  2.16 7.965 84.24 8.235 ;
     RECT  2.16 8.505 84.24 8.775 ;
     RECT  2.16 9.045 84.24 9.315 ;
     RECT  2.16 9.585 84.24 9.855 ;
     RECT  2.16 10.125 84.24 10.395 ;
     RECT  2.16 10.665 84.24 10.935 ;
     RECT  2.16 11.205 84.24 11.475 ;
     RECT  2.16 11.745 84.24 12.015 ;
     RECT  2.16 12.285 84.24 12.555 ;
     RECT  2.16 12.825 84.24 13.095 ;
     RECT  2.16 13.365 84.24 13.635 ;
     RECT  2.16 13.905 84.24 14.175 ;
     RECT  2.16 14.445 84.24 14.715 ;
     RECT  2.16 14.985 84.24 15.255 ;
     RECT  2.16 15.525 84.24 15.795 ;
     RECT  2.16 16.065 84.24 16.335 ;
     RECT  2.16 16.605 84.24 16.875 ;
     RECT  2.16 17.145 84.24 17.415 ;
     RECT  2.16 17.685 84.24 17.955 ;
     RECT  2.16 18.225 84.24 18.495 ;
     RECT  2.16 18.765 84.24 19.035 ;
     RECT  2.16 19.305 84.24 19.575 ;
     RECT  2.16 19.845 84.24 20.115 ;
     RECT  2.16 20.385 84.24 20.655 ;
     RECT  2.16 20.925 84.24 21.195 ;
     RECT  2.16 21.465 84.24 21.735 ;
     RECT  2.16 22.005 84.24 22.275 ;
     RECT  2.16 22.545 84.24 22.815 ;
     RECT  2.16 23.085 84.24 23.355 ;
     RECT  2.16 23.625 84.24 23.895 ;
     RECT  2.16 24.165 84.24 24.435 ;
     RECT  2.16 24.705 84.24 24.975 ;
     RECT  2.16 25.245 84.24 25.515 ;
     RECT  2.16 25.785 84.24 26.055 ;
     RECT  2.16 26.325 84.24 26.595 ;
     RECT  2.16 26.865 84.24 27.135 ;
     RECT  2.16 27.405 84.24 27.675 ;
     RECT  2.16 27.945 84.24 28.215 ;
     RECT  2.16 28.485 84.24 28.755 ;
     RECT  2.16 29.025 84.24 29.295 ;
     RECT  2.16 29.565 84.24 29.835 ;
     RECT  2.16 30.105 84.24 30.375 ;
     RECT  2.16 30.645 84.24 30.915 ;
     RECT  2.16 31.185 84.24 31.455 ;
     RECT  2.16 31.725 84.24 31.995 ;
     RECT  2.16 32.265 84.24 32.535 ;
     RECT  2.16 32.805 84.24 33.075 ;
     RECT  2.16 33.345 84.24 33.615 ;
     RECT  2.16 33.885 84.24 34.155 ;
     RECT  2.16 34.425 84.24 34.695 ;
     RECT  2.16 34.965 84.24 35.235 ;
     RECT  2.16 35.505 84.24 35.775 ;
     RECT  2.16 36.045 84.24 36.315 ;
     RECT  2.16 36.585 84.24 36.855 ;
     RECT  2.16 37.125 84.24 37.395 ;
     RECT  2.16 37.665 84.24 37.935 ;
     RECT  2.16 38.205 84.24 38.475 ;
     RECT  2.16 38.745 84.24 39.015 ;
     RECT  2.16 39.285 84.24 39.555 ;
     RECT  2.16 39.825 84.24 40.095 ;
     RECT  2.16 40.365 84.24 40.635 ;
     RECT  2.16 40.905 84.24 41.175 ;
     RECT  2.16 41.445 84.24 41.715 ;
     RECT  2.16 41.985 84.24 42.255 ;
     RECT  2.16 42.525 84.24 42.795 ;
     RECT  2.16 43.065 84.24 43.335 ;
     RECT  2.16 43.605 84.24 43.875 ;
     RECT  2.16 44.145 84.24 44.415 ;
     RECT  2.16 44.685 84.24 44.955 ;
     RECT  2.16 45.225 84.24 45.495 ;
     RECT  2.16 45.765 84.24 46.035 ;
     RECT  2.16 46.305 84.24 46.575 ;
     RECT  2.16 46.845 84.24 47.115 ;
     RECT  2.16 47.385 84.24 47.655 ;
     RECT  2.16 47.925 84.24 48.195 ;
     RECT  2.16 48.465 84.24 48.735 ;
     RECT  2.16 49.005 84.24 49.275 ;
     RECT  2.16 49.545 84.24 49.815 ;
     RECT  2.16 50.085 84.24 50.355 ;
     RECT  2.16 50.625 84.24 50.895 ;
     RECT  2.16 51.165 84.24 51.435 ;
     RECT  2.16 51.705 84.24 51.975 ;
     RECT  2.16 52.245 84.24 52.515 ;
     RECT  2.16 52.785 84.24 53.055 ;
     RECT  2.16 53.325 84.24 53.595 ;
     RECT  2.16 53.865 84.24 54.135 ;
     RECT  2.16 54.405 84.24 54.675 ;
     RECT  2.16 54.945 84.24 55.215 ;
     RECT  2.16 55.485 84.24 55.755 ;
     RECT  2.16 56.025 84.24 56.295 ;
     RECT  2.16 56.565 84.24 56.835 ;
     RECT  2.16 57.105 84.24 57.375 ;
     RECT  2.16 57.645 84.24 57.915 ;
     RECT  2.16 58.185 84.24 58.455 ;
     RECT  2.16 58.725 84.24 58.995 ;
     RECT  2.16 59.265 84.24 59.535 ;
     RECT  2.16 59.805 84.24 60.075 ;
     RECT  2.16 60.345 84.24 60.615 ;
     RECT  2.16 60.885 84.24 61.155 ;
     RECT  2.16 61.425 84.24 61.695 ;
     RECT  2.16 61.965 84.24 62.235 ;
     RECT  2.16 62.505 84.24 62.775 ;
     RECT  2.16 63.045 84.24 63.315 ;
     RECT  2.16 63.585 84.24 63.855 ;
     RECT  2.16 64.125 84.24 64.395 ;
     RECT  2.16 64.665 84.24 64.935 ;
     RECT  2.16 65.205 84.24 65.475 ;
     RECT  2.16 65.745 84.24 66.015 ;
     RECT  2.16 66.285 84.24 66.555 ;
     RECT  2.16 66.825 84.24 67.095 ;
     RECT  2.16 67.365 84.24 67.635 ;
     RECT  2.16 67.905 84.24 68.175 ;
     RECT  2.16 68.445 84.24 68.715 ;
     RECT  2.16 68.985 84.24 69.255 ;
     RECT  2.16 69.525 84.24 69.795 ;
     RECT  2.16 70.065 84.24 70.335 ;
     RECT  2.16 70.605 84.24 70.875 ;
     RECT  2.16 71.145 84.24 71.415 ;
     RECT  2.16 71.685 84.24 71.955 ;
     RECT  2.16 72.225 84.24 72.495 ;
     RECT  2.16 72.765 84.24 73.035 ;
     RECT  2.16 73.305 84.24 73.575 ;
     RECT  2.16 73.845 84.24 74.115 ;
     RECT  2.16 74.385 84.24 74.655 ;
     RECT  2.16 74.925 84.24 75.195 ;
     RECT  2.16 75.465 84.24 75.735 ;
     RECT  2.16 76.005 84.24 76.275 ;
     RECT  2.16 76.545 84.24 76.815 ;
     RECT  2.16 77.085 84.24 77.355 ;
     RECT  2.16 77.625 84.24 77.895 ;
     RECT  2.16 78.165 84.24 78.435 ;
     RECT  2.16 78.705 84.24 78.975 ;
     RECT  2.16 79.245 84.24 79.515 ;
     RECT  2.16 79.785 84.24 80.055 ;
     RECT  2.16 80.325 84.24 80.595 ;
     RECT  2.16 80.865 84.24 81.135 ;
     RECT  2.16 81.405 84.24 81.675 ;
     RECT  2.16 81.945 84.24 82.215 ;
     RECT  2.16 82.485 84.24 82.755 ;
     RECT  2.16 83.025 84.24 83.295 ;
     RECT  2.16 83.565 84.24 83.835 ;
     RECT  2.16 84.105 84.24 84.24 ;
    LAYER RVTP ;
     RECT  2.16 2.295 84.24 2.565 ;
     RECT  2.16 2.835 84.24 3.105 ;
     RECT  2.16 3.375 84.24 3.645 ;
     RECT  2.16 3.915 84.24 4.185 ;
     RECT  2.16 4.455 84.24 4.725 ;
     RECT  2.16 4.995 84.24 5.265 ;
     RECT  2.16 5.535 84.24 5.805 ;
     RECT  2.16 6.075 84.24 6.345 ;
     RECT  2.16 6.615 84.24 6.885 ;
     RECT  2.16 7.155 84.24 7.425 ;
     RECT  2.16 7.695 84.24 7.965 ;
     RECT  2.16 8.235 84.24 8.505 ;
     RECT  2.16 8.775 84.24 9.045 ;
     RECT  2.16 9.315 84.24 9.585 ;
     RECT  2.16 9.855 84.24 10.125 ;
     RECT  2.16 10.395 84.24 10.665 ;
     RECT  2.16 10.935 84.24 11.205 ;
     RECT  2.16 11.475 84.24 11.745 ;
     RECT  2.16 12.015 84.24 12.285 ;
     RECT  2.16 12.555 84.24 12.825 ;
     RECT  2.16 13.095 84.24 13.365 ;
     RECT  2.16 13.635 84.24 13.905 ;
     RECT  2.16 14.175 84.24 14.445 ;
     RECT  2.16 14.715 84.24 14.985 ;
     RECT  2.16 15.255 84.24 15.525 ;
     RECT  2.16 15.795 84.24 16.065 ;
     RECT  2.16 16.335 84.24 16.605 ;
     RECT  2.16 16.875 84.24 17.145 ;
     RECT  2.16 17.415 84.24 17.685 ;
     RECT  2.16 17.955 84.24 18.225 ;
     RECT  2.16 18.495 84.24 18.765 ;
     RECT  2.16 19.035 84.24 19.305 ;
     RECT  2.16 19.575 84.24 19.845 ;
     RECT  2.16 20.115 84.24 20.385 ;
     RECT  2.16 20.655 84.24 20.925 ;
     RECT  2.16 21.195 84.24 21.465 ;
     RECT  2.16 21.735 84.24 22.005 ;
     RECT  2.16 22.275 84.24 22.545 ;
     RECT  2.16 22.815 84.24 23.085 ;
     RECT  2.16 23.355 84.24 23.625 ;
     RECT  2.16 23.895 84.24 24.165 ;
     RECT  2.16 24.435 84.24 24.705 ;
     RECT  2.16 24.975 84.24 25.245 ;
     RECT  2.16 25.515 84.24 25.785 ;
     RECT  2.16 26.055 84.24 26.325 ;
     RECT  2.16 26.595 84.24 26.865 ;
     RECT  2.16 27.135 84.24 27.405 ;
     RECT  2.16 27.675 84.24 27.945 ;
     RECT  2.16 28.215 84.24 28.485 ;
     RECT  2.16 28.755 84.24 29.025 ;
     RECT  2.16 29.295 84.24 29.565 ;
     RECT  2.16 29.835 84.24 30.105 ;
     RECT  2.16 30.375 84.24 30.645 ;
     RECT  2.16 30.915 84.24 31.185 ;
     RECT  2.16 31.455 84.24 31.725 ;
     RECT  2.16 31.995 84.24 32.265 ;
     RECT  2.16 32.535 84.24 32.805 ;
     RECT  2.16 33.075 84.24 33.345 ;
     RECT  2.16 33.615 84.24 33.885 ;
     RECT  2.16 34.155 84.24 34.425 ;
     RECT  2.16 34.695 84.24 34.965 ;
     RECT  2.16 35.235 84.24 35.505 ;
     RECT  2.16 35.775 84.24 36.045 ;
     RECT  2.16 36.315 84.24 36.585 ;
     RECT  2.16 36.855 84.24 37.125 ;
     RECT  2.16 37.395 84.24 37.665 ;
     RECT  2.16 37.935 84.24 38.205 ;
     RECT  2.16 38.475 84.24 38.745 ;
     RECT  2.16 39.015 84.24 39.285 ;
     RECT  2.16 39.555 84.24 39.825 ;
     RECT  2.16 40.095 84.24 40.365 ;
     RECT  2.16 40.635 84.24 40.905 ;
     RECT  2.16 41.175 84.24 41.445 ;
     RECT  2.16 41.715 84.24 41.985 ;
     RECT  2.16 42.255 84.24 42.525 ;
     RECT  2.16 42.795 84.24 43.065 ;
     RECT  2.16 43.335 84.24 43.605 ;
     RECT  2.16 43.875 84.24 44.145 ;
     RECT  2.16 44.415 84.24 44.685 ;
     RECT  2.16 44.955 84.24 45.225 ;
     RECT  2.16 45.495 84.24 45.765 ;
     RECT  2.16 46.035 84.24 46.305 ;
     RECT  2.16 46.575 84.24 46.845 ;
     RECT  2.16 47.115 84.24 47.385 ;
     RECT  2.16 47.655 84.24 47.925 ;
     RECT  2.16 48.195 84.24 48.465 ;
     RECT  2.16 48.735 84.24 49.005 ;
     RECT  2.16 49.275 84.24 49.545 ;
     RECT  2.16 49.815 84.24 50.085 ;
     RECT  2.16 50.355 84.24 50.625 ;
     RECT  2.16 50.895 84.24 51.165 ;
     RECT  2.16 51.435 84.24 51.705 ;
     RECT  2.16 51.975 84.24 52.245 ;
     RECT  2.16 52.515 84.24 52.785 ;
     RECT  2.16 53.055 84.24 53.325 ;
     RECT  2.16 53.595 84.24 53.865 ;
     RECT  2.16 54.135 84.24 54.405 ;
     RECT  2.16 54.675 84.24 54.945 ;
     RECT  2.16 55.215 84.24 55.485 ;
     RECT  2.16 55.755 84.24 56.025 ;
     RECT  2.16 56.295 84.24 56.565 ;
     RECT  2.16 56.835 84.24 57.105 ;
     RECT  2.16 57.375 84.24 57.645 ;
     RECT  2.16 57.915 84.24 58.185 ;
     RECT  2.16 58.455 84.24 58.725 ;
     RECT  2.16 58.995 84.24 59.265 ;
     RECT  2.16 59.535 84.24 59.805 ;
     RECT  2.16 60.075 84.24 60.345 ;
     RECT  2.16 60.615 84.24 60.885 ;
     RECT  2.16 61.155 84.24 61.425 ;
     RECT  2.16 61.695 84.24 61.965 ;
     RECT  2.16 62.235 84.24 62.505 ;
     RECT  2.16 62.775 84.24 63.045 ;
     RECT  2.16 63.315 84.24 63.585 ;
     RECT  2.16 63.855 84.24 64.125 ;
     RECT  2.16 64.395 84.24 64.665 ;
     RECT  2.16 64.935 84.24 65.205 ;
     RECT  2.16 65.475 84.24 65.745 ;
     RECT  2.16 66.015 84.24 66.285 ;
     RECT  2.16 66.555 84.24 66.825 ;
     RECT  2.16 67.095 84.24 67.365 ;
     RECT  2.16 67.635 84.24 67.905 ;
     RECT  2.16 68.175 84.24 68.445 ;
     RECT  2.16 68.715 84.24 68.985 ;
     RECT  2.16 69.255 84.24 69.525 ;
     RECT  2.16 69.795 84.24 70.065 ;
     RECT  2.16 70.335 84.24 70.605 ;
     RECT  2.16 70.875 84.24 71.145 ;
     RECT  2.16 71.415 84.24 71.685 ;
     RECT  2.16 71.955 84.24 72.225 ;
     RECT  2.16 72.495 84.24 72.765 ;
     RECT  2.16 73.035 84.24 73.305 ;
     RECT  2.16 73.575 84.24 73.845 ;
     RECT  2.16 74.115 84.24 74.385 ;
     RECT  2.16 74.655 84.24 74.925 ;
     RECT  2.16 75.195 84.24 75.465 ;
     RECT  2.16 75.735 84.24 76.005 ;
     RECT  2.16 76.275 84.24 76.545 ;
     RECT  2.16 76.815 84.24 77.085 ;
     RECT  2.16 77.355 84.24 77.625 ;
     RECT  2.16 77.895 84.24 78.165 ;
     RECT  2.16 78.435 84.24 78.705 ;
     RECT  2.16 78.975 84.24 79.245 ;
     RECT  2.16 79.515 84.24 79.785 ;
     RECT  2.16 80.055 84.24 80.325 ;
     RECT  2.16 80.595 84.24 80.865 ;
     RECT  2.16 81.135 84.24 81.405 ;
     RECT  2.16 81.675 84.24 81.945 ;
     RECT  2.16 82.215 84.24 82.485 ;
     RECT  2.16 82.755 84.24 83.025 ;
     RECT  2.16 83.295 84.24 83.565 ;
     RECT  2.16 83.835 84.24 84.105 ;
    LAYER M1 ;
     RECT  2.16 2.151 84.24 84.249 ;
    LAYER M2 ;
     RECT  0.031 22.356 0.103 22.374 ;
     RECT  0.031 28.188 0.103 28.206 ;
     RECT  0.103 23.868 0.139 23.886 ;
     RECT  0.103 57.501 0.139 57.519 ;
     RECT  0.103 58.662 0.139 60.678 ;
     RECT  0.103 62.091 0.139 62.532 ;
     RECT  0.103 21.942 0.175 22.536 ;
     RECT  0.103 25.488 0.175 25.929 ;
     RECT  0.103 28.188 0.175 28.854 ;
     RECT  0.139 34.362 0.175 34.38 ;
     RECT  0.103 16.002 0.203 16.524 ;
     RECT  0.103 17.271 0.203 17.289 ;
     RECT  0.175 21.366 0.203 22.536 ;
     RECT  0.175 24.984 0.203 25.929 ;
     RECT  0.103 38.106 0.203 39.312 ;
     RECT  0.103 41.526 0.203 41.544 ;
     RECT  0.103 45.396 0.203 46.494 ;
     RECT  0.103 50.706 0.203 52.578 ;
     RECT  0.103 53.568 0.203 53.586 ;
     RECT  0.103 54.342 0.203 56.25 ;
     RECT  0.139 57.348 0.203 57.519 ;
     RECT  0.139 58.662 0.203 63.036 ;
     RECT  0.103 64.026 0.203 65.034 ;
     RECT  0.103 65.871 0.203 66.114 ;
     RECT  0.103 68.796 0.203 68.814 ;
     RECT  0.175 27.612 0.211 28.854 ;
     RECT  0.175 34.056 0.211 34.38 ;
     RECT  0.103 18.162 0.239 18.99 ;
     RECT  0.203 21.366 0.239 22.419 ;
     RECT  0.203 57.348 0.239 57.474 ;
     RECT  0.203 60.156 0.239 63.036 ;
     RECT  0.139 70.002 0.239 70.02 ;
     RECT  0.103 36.126 0.247 36.144 ;
     RECT  0.211 27.036 0.275 28.854 ;
     RECT  0.247 36.126 0.283 36.342 ;
     RECT  0.275 27.036 0.311 27.234 ;
     RECT  0.203 54.648 0.311 55.674 ;
     RECT  0.203 24.984 0.347 25.884 ;
     RECT  0.311 27.216 0.347 27.234 ;
     RECT  0.239 62.514 0.347 62.532 ;
     RECT  0.211 33.624 0.427 34.38 ;
     RECT  0.103 48.366 0.427 48.384 ;
     RECT  0.203 51.48 0.427 52.578 ;
     RECT  0.427 33.624 0.463 34.524 ;
     RECT  0.283 35.442 0.463 36.342 ;
     RECT  0.103 43.002 0.499 43.254 ;
     RECT  0.103 44.271 0.499 44.289 ;
     RECT  0.427 51.48 0.527 53.388 ;
     RECT  0.275 28.188 0.535 28.854 ;
     RECT  0.139 31.806 0.535 32.598 ;
     RECT  0.463 33.624 0.535 36.342 ;
     RECT  0.499 43.002 0.535 43.29 ;
     RECT  0.427 47.628 0.535 49.104 ;
     RECT  0.535 47.088 0.563 49.104 ;
     RECT  0.499 44.271 0.599 44.406 ;
     RECT  0.535 28.188 1.111 29.052 ;
     RECT  0.499 50.634 1.147 50.652 ;
     RECT  0.311 55.656 1.399 55.674 ;
     RECT  0.239 21.366 2.16 21.96 ;
     RECT  0.139 23.868 2.16 24.084 ;
     RECT  0.347 25.416 2.16 25.884 ;
     RECT  1.111 28.188 2.16 29.592 ;
     RECT  0.535 31.806 2.16 36.342 ;
     RECT  0.203 39.294 2.16 39.312 ;
     RECT  0.535 42.606 2.16 43.29 ;
     RECT  0.599 44.316 2.16 44.406 ;
     RECT  0.203 45.972 2.16 46.26 ;
     RECT  0.563 47.088 2.16 48.798 ;
     RECT  1.147 50.634 2.16 50.724 ;
     RECT  0.527 51.48 2.16 52.614 ;
     RECT  0.527 53.37 2.16 53.388 ;
     RECT  1.399 55.656 2.16 56.124 ;
     RECT  0.203 59.076 2.16 59.094 ;
     RECT  0.203 64.296 2.16 65.034 ;
     RECT  2.16 2.151 84.24 84.249 ;
     RECT  84.24 41.148 84.371 55.854 ;
     RECT  84.24 26.262 84.911 40.086 ;
     RECT  84.371 52.866 84.911 55.854 ;
     RECT  84.371 41.148 84.947 52.074 ;
     RECT  84.911 52.866 84.947 53.118 ;
     RECT  84.24 62.01 84.983 64.728 ;
     RECT  84.983 62.82 85.019 64.728 ;
     RECT  84.947 41.148 85.235 50.814 ;
     RECT  84.24 68.49 85.271 69.894 ;
     RECT  85.271 69.876 85.307 69.894 ;
     RECT  85.235 41.148 85.451 44.37 ;
     RECT  84.911 26.262 85.487 28.206 ;
     RECT  85.451 41.454 85.487 44.37 ;
     RECT  85.235 45.162 85.487 50.814 ;
     RECT  84.947 53.1 85.487 53.118 ;
     RECT  84.911 53.91 85.487 55.854 ;
     RECT  85.487 45.306 85.523 50.184 ;
     RECT  84.24 56.646 85.523 60.912 ;
     RECT  85.271 68.49 85.523 68.814 ;
     RECT  85.523 48.276 85.559 48.294 ;
     RECT  85.019 62.82 85.559 63.072 ;
     RECT  85.523 68.526 85.559 68.814 ;
     RECT  84.911 28.962 85.595 40.086 ;
     RECT  85.523 45.306 85.595 47.412 ;
     RECT  85.523 49.05 85.595 49.068 ;
     RECT  85.559 62.82 85.595 62.838 ;
     RECT  85.595 33.426 85.883 40.086 ;
     RECT  85.595 28.962 85.919 32.526 ;
     RECT  85.919 30.186 86.027 32.526 ;
     RECT  86.027 30.186 86.135 30.6 ;
     RECT  85.595 45.306 86.135 46.674 ;
     RECT  85.487 43.92 86.143 44.37 ;
     RECT  85.919 28.962 86.171 29.394 ;
     RECT  85.883 33.426 86.171 39.114 ;
     RECT  85.523 56.646 86.171 57.636 ;
     RECT  84.947 51.642 86.215 52.038 ;
     RECT  86.179 53.181 86.215 53.199 ;
     RECT  85.487 53.946 86.215 55.854 ;
     RECT  86.171 56.646 86.215 57.168 ;
     RECT  85.019 63.9 86.215 64.728 ;
     RECT  84.24 65.484 86.215 67.662 ;
     RECT  84.24 16.308 86.243 18.72 ;
     RECT  85.487 26.406 86.243 28.206 ;
     RECT  86.171 28.962 86.243 29.322 ;
     RECT  86.243 16.344 86.279 16.83 ;
     RECT  86.243 17.622 86.279 18.72 ;
     RECT  84.24 21.366 86.279 23.076 ;
     RECT  86.243 27.342 86.279 28.206 ;
     RECT  86.027 31.356 86.279 32.526 ;
     RECT  86.171 33.426 86.279 37.188 ;
     RECT  86.171 37.944 86.279 39.114 ;
     RECT  86.135 45.972 86.279 46.674 ;
     RECT  86.215 53.136 86.279 53.199 ;
     RECT  86.215 53.946 86.279 57.168 ;
     RECT  85.523 58.428 86.279 60.912 ;
     RECT  86.215 63.9 86.279 67.662 ;
     RECT  86.215 24.066 86.287 24.084 ;
     RECT  84.24 19.656 86.315 19.674 ;
     RECT  86.279 23.058 86.315 23.076 ;
     RECT  86.287 23.976 86.315 24.084 ;
     RECT  86.243 26.406 86.315 26.424 ;
     RECT  86.279 27.342 86.315 28.17 ;
     RECT  86.243 29.232 86.315 29.322 ;
     RECT  86.279 32.436 86.315 32.526 ;
     RECT  86.279 33.426 86.315 33.444 ;
     RECT  86.279 34.74 86.315 37.188 ;
     RECT  86.279 38.484 86.315 39.114 ;
     RECT  86.215 40.176 86.315 40.194 ;
     RECT  85.487 41.958 86.315 42.894 ;
     RECT  86.143 43.92 86.315 44.478 ;
     RECT  86.279 46.008 86.315 46.674 ;
     RECT  86.215 51.642 86.315 52.2 ;
     RECT  86.279 53.136 86.315 53.154 ;
     RECT  86.279 53.946 86.315 54.972 ;
     RECT  86.279 55.836 86.315 57.168 ;
     RECT  86.279 58.536 86.315 60.912 ;
     RECT  84.983 62.01 86.315 62.028 ;
     RECT  86.279 64.17 86.315 67.662 ;
     RECT  85.559 68.526 86.315 68.544 ;
     RECT  86.251 25.101 86.351 25.119 ;
     RECT  86.315 42.876 86.351 42.894 ;
     RECT  86.315 23.976 86.387 23.994 ;
     RECT  86.315 44.082 86.387 44.1 ;
     RECT  86.315 59.976 86.387 59.994 ;
     RECT  86.315 64.17 86.387 64.188 ;
    LAYER M3 ;
     RECT  2.415 2.143 2.505 2.413 ;
     RECT  7.815 2.143 7.905 2.413 ;
     RECT  13.215 2.143 13.305 2.413 ;
     RECT  18.615 2.143 18.705 2.413 ;
     RECT  24.015 2.143 24.105 2.413 ;
     RECT  29.415 2.143 29.505 2.413 ;
     RECT  34.815 2.143 34.905 2.413 ;
     RECT  40.215 2.143 40.305 2.413 ;
     RECT  45.615 2.143 45.705 2.413 ;
     RECT  51.015 2.143 51.105 2.413 ;
     RECT  56.415 2.143 56.505 2.413 ;
     RECT  61.815 2.143 61.905 2.413 ;
     RECT  67.215 2.143 67.305 2.413 ;
     RECT  72.615 2.143 72.705 2.413 ;
     RECT  78.015 2.143 78.105 2.413 ;
     RECT  83.415 2.143 83.505 2.413 ;
     RECT  34.815 2.413 35.097 15.787 ;
     RECT  34.776 15.787 35.097 15.835 ;
     RECT  0.18 15.835 0.198 15.883 ;
     RECT  34.776 15.835 35.334 16.027 ;
     RECT  13.215 2.413 13.497 16.123 ;
     RECT  24.015 2.413 24.297 16.123 ;
     RECT  34.776 16.027 35.622 16.123 ;
     RECT  2.415 2.413 2.697 16.141 ;
     RECT  37.224 16.075 37.242 16.141 ;
     RECT  13.104 16.123 13.497 16.169 ;
     RECT  23.904 16.123 24.297 16.169 ;
     RECT  86.292 16.075 86.31 16.171 ;
     RECT  2.304 16.141 2.697 16.205 ;
     RECT  86.256 16.171 86.31 16.267 ;
     RECT  86.22 16.267 86.31 16.315 ;
     RECT  18.615 2.413 18.897 16.339 ;
     RECT  2.415 16.205 2.697 16.363 ;
     RECT  18.216 16.339 18.897 16.363 ;
     RECT  40.215 2.413 40.497 16.501 ;
     RECT  38.268 15.979 38.286 16.507 ;
     RECT  2.415 16.363 2.79 16.541 ;
     RECT  34.704 16.123 35.622 16.565 ;
     RECT  17.424 16.303 17.442 16.573 ;
     RECT  18.18 16.363 18.897 16.573 ;
     RECT  38.268 16.507 38.538 16.573 ;
     RECT  36.36 16.141 37.242 16.651 ;
     RECT  38.268 16.573 38.61 16.651 ;
     RECT  86.148 16.315 86.31 16.747 ;
     RECT  17.424 16.573 18.897 16.807 ;
     RECT  17.424 16.807 18.918 16.951 ;
     RECT  21.42 16.843 21.438 16.951 ;
     RECT  85.464 16.747 86.31 16.973 ;
     RECT  83.415 2.413 83.697 17.032 ;
     RECT  19.872 16.843 19.89 17.041 ;
     RECT  36.36 16.651 38.61 17.041 ;
     RECT  39.6 16.501 40.497 17.041 ;
     RECT  17.424 16.951 18.99 17.069 ;
     RECT  83.415 17.032 83.79 17.069 ;
     RECT  22.644 16.315 22.662 17.077 ;
     RECT  20.772 16.951 21.438 17.105 ;
     RECT  22.644 17.077 22.878 17.105 ;
     RECT  0.108 15.883 0.198 17.131 ;
     RECT  19.728 17.041 19.89 17.185 ;
     RECT  85.464 16.973 85.482 17.185 ;
     RECT  19.728 17.185 20.466 17.221 ;
     RECT  1.116 17.083 1.134 17.261 ;
     RECT  85.428 17.185 85.482 17.261 ;
     RECT  2.415 16.541 2.697 17.311 ;
     RECT  13.215 16.169 13.497 17.311 ;
     RECT  24.015 16.169 24.297 17.311 ;
     RECT  34.776 16.565 35.622 17.311 ;
     RECT  45.615 2.413 45.897 17.311 ;
     RECT  56.415 2.413 56.697 17.311 ;
     RECT  67.215 2.413 67.497 17.311 ;
     RECT  78.015 2.413 78.297 17.311 ;
     RECT  2.304 17.311 2.697 17.357 ;
     RECT  13.104 17.311 13.497 17.357 ;
     RECT  23.904 17.311 24.297 17.357 ;
     RECT  34.704 17.311 35.622 17.357 ;
     RECT  45.504 17.311 45.897 17.357 ;
     RECT  56.304 17.311 56.697 17.357 ;
     RECT  67.104 17.311 67.497 17.357 ;
     RECT  77.904 17.311 78.297 17.357 ;
     RECT  29.415 2.413 29.697 17.371 ;
     RECT  34.776 17.357 35.622 17.405 ;
     RECT  42.732 16.939 42.75 17.453 ;
     RECT  4.392 17.419 4.41 17.467 ;
     RECT  21.312 17.105 21.438 17.467 ;
     RECT  21.312 17.467 21.654 17.581 ;
     RECT  4.284 17.467 4.41 17.707 ;
     RECT  86.22 16.973 86.31 17.707 ;
     RECT  17.424 17.069 18.897 17.851 ;
     RECT  19.62 17.221 20.466 17.851 ;
     RECT  21.312 17.581 21.834 17.851 ;
     RECT  2.415 17.357 2.697 17.899 ;
     RECT  22.788 17.105 22.878 17.923 ;
     RECT  2.415 17.899 3.15 17.947 ;
     RECT  7.815 2.413 8.097 17.995 ;
     RECT  85.572 17.707 86.31 17.995 ;
     RECT  22.608 17.923 22.878 18.121 ;
     RECT  85.5 17.995 86.31 18.125 ;
     RECT  7.164 17.995 8.097 18.187 ;
     RECT  2.415 17.947 3.33 18.221 ;
     RECT  85.572 18.125 86.31 18.221 ;
     RECT  2.415 18.221 3.258 18.283 ;
     RECT  6.12 17.611 6.138 18.283 ;
     RECT  17.424 17.851 21.834 18.301 ;
     RECT  22.572 18.121 22.878 18.301 ;
     RECT  2.304 18.283 3.258 18.329 ;
     RECT  86.076 18.221 86.31 18.461 ;
     RECT  17.424 18.301 22.878 18.661 ;
     RECT  86.148 18.461 86.31 18.689 ;
     RECT  17.424 18.661 22.986 18.955 ;
     RECT  24.015 17.357 24.297 18.955 ;
     RECT  0.108 17.131 0.342 18.989 ;
     RECT  25.2 18.811 25.218 19.003 ;
     RECT  0.108 18.989 0.234 19.037 ;
     RECT  86.22 18.689 86.31 19.037 ;
     RECT  17.424 18.955 24.297 19.243 ;
     RECT  25.2 19.003 25.29 19.243 ;
     RECT  17.424 19.243 25.29 19.339 ;
     RECT  26.064 19.003 26.082 19.339 ;
     RECT  2.415 18.329 3.258 19.435 ;
     RECT  13.215 17.357 13.497 19.471 ;
     RECT  17.424 19.339 26.082 19.579 ;
     RECT  17.424 19.579 26.298 19.651 ;
     RECT  86.292 19.037 86.31 19.679 ;
     RECT  33.624 16.795 33.642 19.805 ;
     RECT  45.615 17.357 45.897 19.912 ;
     RECT  56.415 17.357 56.697 19.912 ;
     RECT  67.215 17.357 67.497 19.912 ;
     RECT  78.015 17.357 78.297 19.912 ;
     RECT  34.815 17.405 35.622 19.915 ;
     RECT  36.36 17.041 40.497 19.915 ;
     RECT  27.972 19.915 27.99 20.011 ;
     RECT  13.104 19.471 13.497 20.048 ;
     RECT  27.972 20.011 28.134 20.107 ;
     RECT  0.108 19.037 0.162 20.203 ;
     RECT  29.376 17.371 29.697 20.299 ;
     RECT  29.376 20.299 30.222 20.347 ;
     RECT  83.415 17.069 83.697 20.443 ;
     RECT  45.504 19.912 45.897 20.489 ;
     RECT  56.304 19.912 56.697 20.489 ;
     RECT  67.104 19.912 67.497 20.489 ;
     RECT  77.904 19.912 78.297 20.489 ;
     RECT  83.304 20.443 83.697 20.489 ;
     RECT  2.304 19.435 3.258 20.525 ;
     RECT  86.22 20.203 86.238 20.587 ;
     RECT  17.424 19.651 26.802 20.615 ;
     RECT  34.815 19.915 40.497 20.615 ;
     RECT  14.832 20.587 14.85 20.683 ;
     RECT  45.615 20.489 45.897 20.683 ;
     RECT  83.415 20.489 83.697 20.779 ;
     RECT  13.215 20.048 13.497 20.827 ;
     RECT  83.415 20.779 83.79 20.849 ;
     RECT  12.204 20.443 12.222 20.875 ;
     RECT  13.176 20.827 13.497 20.875 ;
     RECT  36.324 20.615 40.497 20.875 ;
     RECT  36.324 20.875 41.094 20.923 ;
     RECT  42.768 20.683 42.786 20.923 ;
     RECT  45.615 20.683 46.098 20.957 ;
     RECT  42.768 20.923 43.254 20.971 ;
     RECT  11.16 20.923 11.178 21.163 ;
     RECT  6.084 18.283 6.138 21.259 ;
     RECT  7.092 18.187 8.097 21.259 ;
     RECT  2.415 20.525 3.258 21.361 ;
     RECT  4.248 17.707 4.41 21.361 ;
     RECT  2.415 21.361 4.41 21.437 ;
     RECT  14.328 20.683 14.85 21.451 ;
     RECT  36.324 20.923 41.274 21.451 ;
     RECT  36.324 21.451 41.526 21.541 ;
     RECT  42.264 20.971 43.254 21.541 ;
     RECT  2.415 21.437 3.258 21.631 ;
     RECT  45.615 20.957 45.897 21.631 ;
     RECT  56.415 20.489 56.697 21.631 ;
     RECT  67.215 20.489 67.497 21.631 ;
     RECT  78.015 20.489 78.297 21.631 ;
     RECT  11.16 21.163 11.394 21.643 ;
     RECT  45.504 21.631 45.897 21.677 ;
     RECT  56.304 21.631 56.697 21.677 ;
     RECT  67.104 21.631 67.497 21.677 ;
     RECT  77.904 21.631 78.297 21.677 ;
     RECT  14.328 21.451 15.138 21.739 ;
     RECT  16.272 21.499 16.29 21.739 ;
     RECT  83.415 20.849 83.697 21.739 ;
     RECT  10.944 21.643 11.394 21.773 ;
     RECT  17.424 20.615 26.298 21.811 ;
     RECT  83.415 21.739 84.402 21.901 ;
     RECT  9.252 21.403 9.27 21.931 ;
     RECT  36.324 21.541 43.254 21.965 ;
     RECT  83.415 21.901 84.438 21.973 ;
     RECT  85.176 21.259 85.194 21.973 ;
     RECT  86.22 20.587 86.31 21.979 ;
     RECT  14.328 21.739 16.29 22.027 ;
     RECT  36.324 21.965 41.274 22.073 ;
     RECT  86.184 21.979 86.31 22.157 ;
     RECT  2.304 21.631 3.258 22.199 ;
     RECT  37.08 22.073 41.274 22.199 ;
     RECT  82.044 21.979 82.062 22.199 ;
     RECT  9 21.931 9.27 22.235 ;
     RECT  83.415 21.973 85.194 22.253 ;
     RECT  0.108 20.203 0.198 22.351 ;
     RECT  17.352 21.811 26.298 22.351 ;
     RECT  0.036 22.351 0.198 22.396 ;
     RECT  85.176 22.253 85.194 22.411 ;
     RECT  0.036 22.396 0.234 22.493 ;
     RECT  12.204 20.875 13.497 22.621 ;
     RECT  14.256 22.027 16.29 22.621 ;
     RECT  85.176 22.411 85.482 22.649 ;
     RECT  83.415 22.253 84.402 22.747 ;
     RECT  0.036 22.493 0.198 22.781 ;
     RECT  11.16 21.773 11.394 22.891 ;
     RECT  12.204 22.621 16.29 22.891 ;
     RECT  86.256 22.157 86.31 22.891 ;
     RECT  5.184 22.795 5.202 23.035 ;
     RECT  83.196 22.747 84.402 23.035 ;
     RECT  37.332 22.199 41.274 23.053 ;
     RECT  42.264 21.965 43.254 23.053 ;
     RECT  86.22 22.891 86.31 23.081 ;
     RECT  17.316 22.351 26.298 23.083 ;
     RECT  6.084 21.259 8.097 23.125 ;
     RECT  9.252 22.235 9.27 23.125 ;
     RECT  11.16 22.891 16.29 23.125 ;
     RECT  17.028 23.083 26.298 23.125 ;
     RECT  56.415 21.677 56.697 23.275 ;
     RECT  11.16 23.125 26.298 23.359 ;
     RECT  10.836 23.359 26.298 23.395 ;
     RECT  83.16 23.035 84.402 23.467 ;
     RECT  85.176 22.649 85.194 23.467 ;
     RECT  10.728 23.395 26.298 23.585 ;
     RECT  83.16 23.467 85.194 23.585 ;
     RECT  37.332 23.053 43.254 23.621 ;
     RECT  10.728 23.585 11.394 23.629 ;
     RECT  2.415 22.199 3.258 23.755 ;
     RECT  10.368 23.629 11.394 23.827 ;
     RECT  4.248 21.437 4.41 23.899 ;
     RECT  5.184 23.035 5.238 23.899 ;
     RECT  86.22 23.081 86.274 23.947 ;
     RECT  86.22 23.947 86.31 23.971 ;
     RECT  2.304 23.755 3.258 24.061 ;
     RECT  4.248 23.899 5.238 24.061 ;
     RECT  6.084 23.125 9.27 24.097 ;
     RECT  10.152 23.827 11.394 24.097 ;
     RECT  2.304 24.061 5.238 24.125 ;
     RECT  86.22 23.971 86.382 24.139 ;
     RECT  79.488 24.091 79.506 24.235 ;
     RECT  4.248 24.125 5.238 24.269 ;
     RECT  83.415 23.585 85.194 24.331 ;
     RECT  2.304 24.125 3.258 24.359 ;
     RECT  0.036 22.781 0.162 24.523 ;
     RECT  83.415 24.331 85.23 24.523 ;
     RECT  86.148 24.139 86.382 24.523 ;
     RECT  5.148 24.269 5.238 24.629 ;
     RECT  32.652 23.593 32.67 24.629 ;
     RECT  4.248 24.269 4.374 24.665 ;
     RECT  2.304 24.359 3.186 24.773 ;
     RECT  2.304 24.773 3.114 24.899 ;
     RECT  83.415 24.523 86.382 24.907 ;
     RECT  2.415 24.899 3.114 24.935 ;
     RECT  6.084 24.097 11.394 24.989 ;
     RECT  0.036 24.523 0.342 25.037 ;
     RECT  2.415 24.935 2.934 25.037 ;
     RECT  6.084 24.989 8.514 25.079 ;
     RECT  2.415 25.037 2.79 25.181 ;
     RECT  4.248 24.665 4.338 25.411 ;
     RECT  3.96 25.411 4.338 25.435 ;
     RECT  5.184 24.629 5.238 25.435 ;
     RECT  0.036 25.037 0.234 25.439 ;
     RECT  82.944 24.907 86.382 25.483 ;
     RECT  3.96 25.435 5.238 25.745 ;
     RECT  37.656 23.621 43.254 25.825 ;
     RECT  3.96 25.745 3.978 25.889 ;
     RECT  2.415 25.181 2.697 25.951 ;
     RECT  6.084 25.079 8.442 26.015 ;
     RECT  9.252 24.989 11.394 26.023 ;
     RECT  12.204 23.585 26.298 26.023 ;
     RECT  80.64 24.427 80.658 26.059 ;
     RECT  0.036 25.439 0.198 26.141 ;
     RECT  6.264 26.015 8.442 26.285 ;
     RECT  64.98 26.257 64.998 26.357 ;
     RECT  61.815 2.413 62.097 26.401 ;
     RECT  62.856 26.221 62.874 26.401 ;
     RECT  2.304 25.951 2.697 26.477 ;
     RECT  5.22 25.745 5.238 26.555 ;
     RECT  37.62 25.825 43.254 26.555 ;
     RECT  61.815 26.401 62.874 26.555 ;
     RECT  60.696 25.003 60.714 26.563 ;
     RECT  61.815 26.555 62.097 26.563 ;
     RECT  9.252 26.023 26.298 26.635 ;
     RECT  82.332 25.483 86.382 26.635 ;
     RECT  6.624 26.285 8.442 26.669 ;
     RECT  62.856 26.555 62.874 26.671 ;
     RECT  63.864 26.527 63.882 26.671 ;
     RECT  7.668 26.669 8.442 26.789 ;
     RECT  9.216 26.635 26.298 26.825 ;
     RECT  62.856 26.671 63.882 26.825 ;
     RECT  37.656 26.555 43.254 26.861 ;
     RECT  82.044 26.635 86.382 26.861 ;
     RECT  0.036 26.141 0.162 27.019 ;
     RECT  0.036 27.019 0.234 27.031 ;
     RECT  80.64 26.059 80.694 27.067 ;
     RECT  81.504 27.103 81.522 27.149 ;
     RECT  0.036 27.031 0.306 27.163 ;
     RECT  65.412 26.761 65.43 27.211 ;
     RECT  65.412 27.211 65.574 27.301 ;
     RECT  63 26.825 63.882 27.337 ;
     RECT  64.728 27.301 65.61 27.337 ;
     RECT  80.352 27.067 80.694 27.509 ;
     RECT  60.696 26.563 62.097 27.571 ;
     RECT  63 27.337 65.61 27.571 ;
     RECT  0.036 27.163 0.342 27.629 ;
     RECT  0.036 27.629 0.27 27.677 ;
     RECT  2.415 26.477 2.697 27.739 ;
     RECT  60.696 27.571 65.61 27.751 ;
     RECT  66.348 27.067 66.366 27.751 ;
     RECT  2.415 27.739 2.79 27.779 ;
     RECT  60.696 27.751 66.366 27.905 ;
     RECT  80.64 27.509 80.694 28.171 ;
     RECT  81.468 27.883 81.486 28.171 ;
     RECT  0.036 27.677 0.234 28.211 ;
     RECT  0.108 28.211 0.234 28.283 ;
     RECT  80.64 28.171 81.486 28.283 ;
     RECT  66.348 27.905 66.366 28.291 ;
     RECT  67.215 21.677 67.497 28.291 ;
     RECT  80.64 28.283 80.946 28.481 ;
     RECT  60.696 27.905 65.61 28.759 ;
     RECT  66.348 28.291 67.497 28.759 ;
     RECT  58.644 28.525 58.662 28.789 ;
     RECT  58.464 28.789 58.662 28.829 ;
     RECT  3.96 28.795 3.978 28.859 ;
     RECT  0.108 28.283 0.126 28.877 ;
     RECT  60.552 28.759 65.61 28.921 ;
     RECT  66.348 28.759 68.202 28.921 ;
     RECT  60.552 28.921 68.274 28.993 ;
     RECT  34.815 20.615 35.097 29.083 ;
     RECT  45.615 21.677 45.897 29.083 ;
     RECT  55.62 23.323 55.638 29.083 ;
     RECT  56.415 23.275 57.222 29.083 ;
     RECT  2.415 27.779 2.697 29.101 ;
     RECT  60.336 28.993 68.274 29.101 ;
     RECT  34.704 29.083 35.097 29.129 ;
     RECT  45.504 29.083 45.897 29.129 ;
     RECT  55.62 29.083 57.222 29.129 ;
     RECT  2.304 29.101 2.697 29.165 ;
     RECT  60.048 29.101 68.274 29.219 ;
     RECT  60.696 29.219 68.274 29.255 ;
     RECT  56.415 29.129 57.222 29.323 ;
     RECT  59.868 29.323 59.922 29.363 ;
     RECT  70.704 28.957 70.722 29.363 ;
     RECT  56.415 29.323 57.618 29.371 ;
     RECT  68.256 29.255 68.274 29.371 ;
     RECT  0.54 29.029 0.558 29.453 ;
     RECT  56.415 29.371 57.798 29.489 ;
     RECT  56.415 29.489 57.618 29.525 ;
     RECT  1.404 26.923 1.422 29.569 ;
     RECT  51.015 2.413 51.297 29.611 ;
     RECT  51.015 29.611 51.894 29.641 ;
     RECT  50.976 29.641 51.894 29.731 ;
     RECT  1.116 29.569 1.422 29.741 ;
     RECT  82.332 26.861 86.382 29.803 ;
     RECT  49.212 29.461 49.23 29.899 ;
     RECT  80.64 28.481 80.694 29.899 ;
     RECT  50.4 29.731 51.894 29.911 ;
     RECT  59.904 29.363 59.922 29.939 ;
     RECT  49.104 29.899 49.23 30.001 ;
     RECT  50.364 29.911 51.894 30.043 ;
     RECT  52.92 29.911 52.938 30.073 ;
     RECT  49.104 30.001 49.266 30.109 ;
     RECT  50.364 30.043 52.002 30.109 ;
     RECT  49.104 30.109 52.002 30.139 ;
     RECT  52.92 30.073 53.01 30.139 ;
     RECT  82.044 29.803 86.382 30.173 ;
     RECT  2.415 29.165 2.697 30.271 ;
     RECT  34.815 29.129 35.097 30.271 ;
     RECT  45.615 29.129 45.897 30.271 ;
     RECT  54.792 29.767 54.81 30.271 ;
     RECT  80.352 29.899 80.694 30.299 ;
     RECT  2.304 30.271 2.697 30.317 ;
     RECT  49.104 30.139 53.01 30.379 ;
     RECT  60.696 29.255 67.497 30.509 ;
     RECT  68.256 29.371 68.382 30.569 ;
     RECT  9.252 26.825 26.298 30.605 ;
     RECT  68.328 30.569 68.382 30.605 ;
     RECT  58.716 29.083 58.878 30.677 ;
     RECT  82.08 30.173 86.382 30.701 ;
     RECT  34.704 30.271 35.097 30.712 ;
     RECT  34.632 30.712 35.097 30.749 ;
     RECT  49.104 30.379 53.586 30.811 ;
     RECT  54.576 30.271 54.81 30.811 ;
     RECT  49.104 30.811 54.81 30.955 ;
     RECT  0.144 29.851 0.234 31.051 ;
     RECT  49.104 30.955 54.882 31.099 ;
     RECT  49.032 31.099 54.882 31.109 ;
     RECT  59.76 30.955 59.778 31.145 ;
     RECT  0.144 31.051 0.306 31.147 ;
     RECT  58.104 30.907 58.662 31.147 ;
     RECT  2.415 30.317 2.697 31.243 ;
     RECT  67.215 30.509 67.497 31.243 ;
     RECT  78.015 21.677 78.297 31.243 ;
     RECT  34.704 30.749 35.097 31.277 ;
     RECT  45.504 30.271 45.897 31.277 ;
     RECT  2.304 31.243 2.697 31.289 ;
     RECT  77.904 31.243 78.297 31.289 ;
     RECT  9.252 30.605 9.954 31.351 ;
     RECT  67.104 31.243 67.497 31.387 ;
     RECT  68.364 30.605 68.382 31.387 ;
     RECT  70.74 31.351 70.758 31.387 ;
     RECT  58.068 31.147 58.662 31.423 ;
     RECT  6.624 26.669 6.642 31.435 ;
     RECT  7.815 26.789 8.442 31.451 ;
     RECT  67.104 31.387 68.382 31.469 ;
     RECT  70.74 31.387 70.83 31.487 ;
     RECT  60.696 30.509 66.366 31.495 ;
     RECT  70.74 31.487 70.758 31.523 ;
     RECT  7.815 31.451 8.37 31.559 ;
     RECT  60.048 31.495 66.366 31.559 ;
     RECT  58.068 31.423 58.734 31.649 ;
     RECT  69.552 31.081 69.57 31.649 ;
     RECT  27.9 20.107 28.134 31.657 ;
     RECT  58.716 31.649 58.734 31.685 ;
     RECT  45.615 31.277 45.897 31.693 ;
     RECT  9.252 31.351 10.062 31.757 ;
     RECT  49.032 31.109 54.81 31.771 ;
     RECT  55.62 29.129 55.638 31.801 ;
     RECT  56.415 29.525 57.222 31.801 ;
     RECT  48.888 31.771 54.81 31.891 ;
     RECT  48.888 31.891 54.846 31.915 ;
     RECT  55.62 31.801 57.222 31.915 ;
     RECT  45.615 31.693 45.918 31.919 ;
     RECT  37.764 26.861 43.254 31.963 ;
     RECT  60.984 31.559 66.366 31.963 ;
     RECT  67.104 31.469 67.497 31.963 ;
     RECT  10.836 30.605 26.298 31.999 ;
     RECT  27.864 31.657 28.134 31.999 ;
     RECT  34.815 31.277 35.097 31.999 ;
     RECT  48.888 31.915 57.222 31.999 ;
     RECT  2.415 31.289 2.697 32.059 ;
     RECT  2.415 32.059 2.79 32.099 ;
     RECT  60.984 31.963 67.497 32.099 ;
     RECT  60.984 32.099 66.438 32.189 ;
     RECT  68.364 31.469 68.382 32.189 ;
     RECT  10.836 31.999 26.694 32.197 ;
     RECT  27.72 31.999 28.134 32.197 ;
     RECT  3.96 31.771 3.978 32.431 ;
     RECT  10.836 32.197 28.134 32.459 ;
     RECT  3.96 32.431 4.554 32.525 ;
     RECT  48.888 31.999 57.582 32.567 ;
     RECT  47.592 32.575 47.61 32.611 ;
     RECT  58.788 31.927 58.806 32.639 ;
     RECT  47.592 32.611 47.826 32.729 ;
     RECT  3.96 32.525 4.302 32.737 ;
     RECT  37.764 31.963 43.362 32.737 ;
     RECT  44.424 32.539 44.442 32.737 ;
     RECT  47.592 32.729 47.61 32.765 ;
     RECT  29.196 20.347 30.222 32.809 ;
     RECT  60.048 31.559 60.066 32.809 ;
     RECT  60.984 32.189 66.366 32.809 ;
     RECT  37.764 32.737 44.442 32.837 ;
     RECT  2.415 32.099 2.697 32.872 ;
     RECT  34.776 31.999 35.097 32.872 ;
     RECT  10.836 32.459 26.766 32.873 ;
     RECT  45.615 31.919 45.897 32.971 ;
     RECT  29.196 32.809 30.798 32.999 ;
     RECT  34.704 32.872 35.097 33.005 ;
     RECT  2.304 32.872 2.697 33.008 ;
     RECT  45.504 32.971 45.897 33.008 ;
     RECT  46.8 31.723 46.818 33.019 ;
     RECT  9.252 31.757 9.81 33.035 ;
     RECT  58.248 32.881 58.266 33.035 ;
     RECT  0.108 31.147 0.306 33.043 ;
     RECT  3.636 32.737 4.302 33.071 ;
     RECT  60.048 32.809 66.366 33.079 ;
     RECT  0.108 33.043 0.558 33.115 ;
     RECT  0.108 33.115 0.63 33.179 ;
     RECT  60.048 33.079 66.438 33.179 ;
     RECT  0.108 33.179 0.558 33.197 ;
     RECT  37.764 32.837 43.974 33.269 ;
     RECT  46.8 33.019 47.322 33.305 ;
     RECT  29.196 32.999 30.222 33.307 ;
     RECT  29.088 33.307 30.222 33.437 ;
     RECT  34.776 33.005 35.097 33.539 ;
     RECT  48.888 32.567 57.402 33.611 ;
     RECT  11.16 32.873 26.298 33.719 ;
     RECT  46.8 33.305 46.854 33.817 ;
     RECT  44.316 33.595 44.334 33.889 ;
     RECT  46.764 33.817 46.854 33.917 ;
     RECT  60.048 33.179 66.402 34.051 ;
     RECT  11.16 33.719 11.394 34.075 ;
     RECT  12.132 33.719 26.298 34.079 ;
     RECT  44.316 33.889 44.514 34.079 ;
     RECT  48.888 33.611 55.674 34.079 ;
     RECT  44.316 34.079 44.334 34.115 ;
     RECT  46.8 33.917 46.854 34.157 ;
     RECT  0.108 33.197 0.45 34.159 ;
     RECT  12.132 34.079 25.326 34.187 ;
     RECT  10.836 34.075 11.394 34.205 ;
     RECT  67.215 32.099 67.497 34.219 ;
     RECT  2.415 33.008 2.697 34.231 ;
     RECT  3.636 33.071 4.266 34.231 ;
     RECT  60.048 34.051 66.438 34.385 ;
     RECT  27.54 32.459 28.134 34.393 ;
     RECT  67.215 34.219 67.59 34.397 ;
     RECT  56.415 33.611 57.402 34.465 ;
     RECT  27.54 34.393 28.314 34.493 ;
     RECT  56.415 34.465 57.942 34.655 ;
     RECT  27.54 34.493 28.242 34.691 ;
     RECT  29.268 33.437 30.222 34.771 ;
     RECT  2.415 34.231 4.266 34.897 ;
     RECT  27.54 34.691 28.134 34.933 ;
     RECT  29.124 34.771 30.222 34.933 ;
     RECT  2.415 34.897 4.302 34.969 ;
     RECT  29.088 34.933 30.222 35.041 ;
     RECT  31.392 34.933 31.41 35.041 ;
     RECT  46.8 34.157 46.818 35.041 ;
     RECT  27.216 34.933 28.134 35.069 ;
     RECT  60.804 34.385 66.438 35.069 ;
     RECT  29.088 35.041 30.438 35.083 ;
     RECT  31.32 35.041 31.41 35.083 ;
     RECT  59.256 35.041 59.274 35.083 ;
     RECT  60.048 34.385 60.066 35.083 ;
     RECT  34.815 33.539 35.097 35.125 ;
     RECT  45.615 33.008 45.897 35.131 ;
     RECT  48.888 34.079 55.638 35.131 ;
     RECT  56.415 34.655 57.726 35.131 ;
     RECT  60.984 35.069 66.438 35.131 ;
     RECT  67.215 34.397 67.497 35.131 ;
     RECT  78.015 31.289 78.297 35.131 ;
     RECT  58.86 35.083 60.066 35.159 ;
     RECT  34.704 35.125 35.097 35.165 ;
     RECT  2.415 34.969 4.374 35.179 ;
     RECT  46.764 35.041 46.818 35.195 ;
     RECT  29.088 35.083 31.41 35.401 ;
     RECT  36.324 22.073 36.342 35.401 ;
     RECT  2.304 35.179 4.374 35.509 ;
     RECT  58.86 35.159 58.986 35.545 ;
     RECT  68.94 35.473 68.958 35.545 ;
     RECT  29.088 35.401 31.482 35.573 ;
     RECT  29.088 35.573 30.906 35.581 ;
     RECT  32.616 24.745 32.634 35.581 ;
     RECT  45.504 35.131 45.897 35.609 ;
     RECT  48.888 35.131 57.726 35.609 ;
     RECT  60.984 35.131 67.497 35.609 ;
     RECT  68.904 35.545 68.958 35.609 ;
     RECT  74.664 35.509 74.682 35.609 ;
     RECT  77.904 35.131 78.297 35.609 ;
     RECT  32.616 35.581 33.066 35.671 ;
     RECT  36.288 35.401 36.342 35.671 ;
     RECT  2.232 35.509 4.374 35.693 ;
     RECT  68.904 35.609 68.922 35.699 ;
     RECT  12.132 34.187 25.29 35.707 ;
     RECT  26.1 34.079 26.298 35.707 ;
     RECT  27.792 35.069 28.134 35.707 ;
     RECT  48.888 35.609 55.638 35.735 ;
     RECT  58.608 35.545 58.986 35.735 ;
     RECT  60.984 35.609 66.438 35.735 ;
     RECT  31.824 35.671 33.066 35.743 ;
     RECT  35.964 35.671 36.342 35.743 ;
     RECT  2.304 35.693 4.374 35.771 ;
     RECT  34.74 35.165 35.097 35.815 ;
     RECT  35.928 35.743 36.342 35.815 ;
     RECT  27.792 35.707 28.278 35.851 ;
     RECT  29.052 35.581 30.906 35.851 ;
     RECT  31.824 35.743 33.642 35.879 ;
     RECT  27.792 35.851 30.906 35.941 ;
     RECT  27.54 35.941 30.906 36.013 ;
     RECT  12.132 35.707 26.298 36.049 ;
     RECT  0.108 34.159 0.558 36.149 ;
     RECT  0.144 36.149 0.558 36.173 ;
     RECT  60.984 35.735 61.002 36.211 ;
     RECT  12.132 36.049 26.658 36.235 ;
     RECT  34.74 35.815 36.342 36.247 ;
     RECT  58.788 35.735 58.986 36.277 ;
     RECT  60.048 35.159 60.066 36.277 ;
     RECT  58.788 36.277 60.066 36.283 ;
     RECT  60.912 36.211 61.002 36.283 ;
     RECT  61.776 35.735 66.438 36.311 ;
     RECT  58.788 36.283 61.002 36.317 ;
     RECT  0.144 36.173 0.522 36.365 ;
     RECT  2.304 35.771 4.338 36.365 ;
     RECT  34.668 36.247 36.522 36.383 ;
     RECT  49.032 35.735 55.638 36.383 ;
     RECT  80.64 30.299 80.694 36.391 ;
     RECT  2.304 36.365 4.302 36.419 ;
     RECT  49.068 36.383 55.638 36.419 ;
     RECT  27.504 36.013 30.906 36.481 ;
     RECT  34.815 36.383 36.522 36.481 ;
     RECT  59.868 36.317 61.002 36.481 ;
     RECT  61.776 36.311 62.097 36.481 ;
     RECT  12.132 36.235 26.73 36.517 ;
     RECT  27.468 36.481 30.906 36.517 ;
     RECT  2.304 36.419 4.266 36.523 ;
     RECT  49.104 36.419 55.638 36.557 ;
     RECT  31.86 35.879 33.642 36.751 ;
     RECT  49.212 36.557 55.638 36.751 ;
     RECT  56.415 35.609 57.726 36.751 ;
     RECT  62.82 36.311 66.438 36.751 ;
     RECT  67.215 35.609 67.497 36.751 ;
     RECT  78.015 35.609 78.297 36.751 ;
     RECT  2.268 36.523 4.266 36.779 ;
     RECT  62.82 36.751 67.497 36.815 ;
     RECT  49.212 36.751 57.726 36.823 ;
     RECT  58.788 36.317 58.986 36.823 ;
     RECT  34.815 36.481 36.774 36.851 ;
     RECT  31.644 36.751 33.642 36.923 ;
     RECT  34.815 36.851 36.342 36.959 ;
     RECT  59.868 36.481 62.097 36.989 ;
     RECT  32.4 36.923 33.642 37.021 ;
     RECT  2.268 36.779 4.122 37.049 ;
     RECT  82.332 30.701 86.382 37.121 ;
     RECT  49.212 36.823 58.986 37.147 ;
     RECT  3.528 37.049 4.122 37.157 ;
     RECT  32.4 37.021 33.822 37.165 ;
     RECT  34.815 36.959 35.406 37.165 ;
     RECT  49.212 37.147 59.13 37.201 ;
     RECT  59.868 36.989 61.002 37.201 ;
     RECT  74.736 37.129 74.754 37.229 ;
     RECT  77.904 36.751 78.297 37.229 ;
     RECT  61.776 36.989 62.097 37.291 ;
     RECT  61.776 37.291 62.154 37.319 ;
     RECT  2.268 37.049 2.79 37.328 ;
     RECT  0.144 36.365 0.162 37.339 ;
     RECT  79.488 24.235 79.578 37.387 ;
     RECT  80.64 36.391 80.982 37.387 ;
     RECT  6.516 31.435 6.642 37.391 ;
     RECT  3.528 37.157 3.906 37.427 ;
     RECT  62.892 36.815 67.497 37.463 ;
     RECT  12.132 36.517 30.906 37.471 ;
     RECT  31.644 36.923 31.662 37.471 ;
     RECT  0.144 37.339 0.234 37.517 ;
     RECT  2.304 37.328 2.79 37.589 ;
     RECT  3.636 37.427 3.906 37.589 ;
     RECT  3.744 37.589 3.906 37.625 ;
     RECT  3.744 37.625 3.87 37.661 ;
     RECT  49.212 37.201 61.002 37.669 ;
     RECT  3.852 37.661 3.87 37.697 ;
     RECT  2.304 37.589 2.697 37.805 ;
     RECT  2.34 37.805 2.697 37.859 ;
     RECT  61.815 37.319 62.154 37.903 ;
     RECT  62.892 37.463 66.438 37.903 ;
     RECT  75.492 23.371 75.51 37.903 ;
     RECT  12.132 37.471 31.662 37.939 ;
     RECT  32.4 37.165 35.406 37.939 ;
     RECT  49.104 37.669 61.002 37.975 ;
     RECT  12.132 37.939 35.406 38.039 ;
     RECT  0.144 37.517 0.198 38.092 ;
     RECT  12.132 38.039 26.802 38.189 ;
     RECT  27.612 38.039 35.406 38.189 ;
     RECT  12.132 38.189 26.586 38.309 ;
     RECT  46.8 35.195 46.818 38.435 ;
     RECT  61.815 37.903 66.438 38.435 ;
     RECT  0.108 38.092 0.198 38.491 ;
     RECT  49.032 37.975 61.002 38.821 ;
     RECT  27.828 38.189 35.406 38.849 ;
     RECT  75.24 37.903 75.51 38.849 ;
     RECT  62.892 38.435 66.438 38.947 ;
     RECT  67.215 37.463 67.497 38.947 ;
     RECT  0.108 38.491 0.27 39.019 ;
     RECT  45.615 35.609 45.897 39.019 ;
     RECT  0.108 39.019 0.378 39.149 ;
     RECT  45.615 39.019 45.99 39.149 ;
     RECT  79.488 37.387 80.982 39.209 ;
     RECT  12.132 38.309 26.298 39.211 ;
     RECT  47.916 39.163 47.934 39.259 ;
     RECT  49.032 38.821 61.038 39.289 ;
     RECT  61.815 38.435 62.154 39.289 ;
     RECT  49.032 39.289 62.154 39.325 ;
     RECT  62.892 38.947 67.497 39.325 ;
     RECT  45.615 39.149 45.897 39.352 ;
     RECT  2.415 37.859 2.697 39.361 ;
     RECT  45.504 39.352 45.897 39.389 ;
     RECT  82.908 37.121 86.382 39.389 ;
     RECT  2.304 39.361 2.697 39.437 ;
     RECT  49.032 39.325 67.497 39.547 ;
     RECT  80.964 39.209 80.982 39.581 ;
     RECT  72.615 2.413 72.897 39.595 ;
     RECT  75.24 38.849 75.258 39.629 ;
     RECT  47.88 39.259 47.934 39.631 ;
     RECT  48.888 39.547 67.497 39.631 ;
     RECT  0.108 39.149 0.342 39.821 ;
     RECT  47.88 39.631 67.497 39.821 ;
     RECT  47.88 39.821 66.438 39.865 ;
     RECT  2.415 39.437 2.697 39.883 ;
     RECT  78.015 37.229 78.297 39.883 ;
     RECT  37.764 33.269 43.254 39.901 ;
     RECT  77.904 39.883 78.678 39.929 ;
     RECT  37.764 39.901 43.974 40.019 ;
     RECT  74.664 39.901 74.682 40.019 ;
     RECT  12.132 39.211 26.802 40.027 ;
     RECT  45.615 39.389 45.897 40.027 ;
     RECT  2.415 39.883 2.862 40.061 ;
     RECT  78.015 39.929 78.678 40.061 ;
     RECT  27.828 38.849 28.134 40.135 ;
     RECT  28.908 38.849 35.406 40.135 ;
     RECT  47.664 39.865 66.438 40.157 ;
     RECT  82.08 40.099 82.098 40.157 ;
     RECT  79.488 39.209 80.082 40.199 ;
     RECT  12.132 40.027 26.982 40.397 ;
     RECT  0.144 39.821 0.234 40.445 ;
     RECT  12.132 40.397 26.91 40.445 ;
     RECT  45.615 40.027 46.206 40.531 ;
     RECT  72.615 39.595 73.566 40.589 ;
     RECT  27.828 40.135 35.406 40.603 ;
     RECT  36.324 36.959 36.342 40.603 ;
     RECT  47.124 40.567 47.214 40.603 ;
     RECT  27.828 40.603 36.342 40.631 ;
     RECT  45.615 40.531 46.242 40.675 ;
     RECT  46.98 40.603 47.214 40.675 ;
     RECT  35.892 40.631 36.342 40.739 ;
     RECT  45.615 40.675 47.214 40.739 ;
     RECT  0.144 40.445 0.198 40.781 ;
     RECT  48.24 40.157 66.438 40.865 ;
     RECT  45.615 40.739 47.07 40.925 ;
     RECT  83.415 39.389 86.382 40.939 ;
     RECT  47.052 40.925 47.07 40.973 ;
     RECT  49.14 40.865 66.438 41.009 ;
     RECT  49.14 41.009 62.097 41.117 ;
     RECT  27.828 40.631 35.097 41.243 ;
     RECT  81.468 40.843 81.486 41.279 ;
     RECT  12.132 40.445 26.298 41.377 ;
     RECT  49.284 41.117 62.097 41.405 ;
     RECT  83.196 40.939 86.382 41.419 ;
     RECT  82.62 41.419 86.382 41.441 ;
     RECT  49.356 41.405 62.097 41.477 ;
     RECT  2.415 40.061 2.697 41.512 ;
     RECT  0.144 40.781 0.162 41.521 ;
     RECT  12.132 41.377 26.802 41.611 ;
     RECT  2.304 41.512 2.697 41.648 ;
     RECT  12.132 41.611 26.91 41.659 ;
     RECT  49.896 41.477 62.097 41.675 ;
     RECT  27.9 41.243 35.097 41.683 ;
     RECT  0.108 41.521 0.198 41.789 ;
     RECT  82.62 41.441 84.15 41.819 ;
     RECT  0.108 41.789 0.162 41.837 ;
     RECT  27.9 41.683 35.406 41.945 ;
     RECT  27.9 41.945 35.334 41.981 ;
     RECT  63.108 41.009 66.438 42.043 ;
     RECT  67.215 39.821 67.497 42.043 ;
     RECT  78.015 40.061 78.297 42.043 ;
     RECT  63.108 42.043 67.497 42.089 ;
     RECT  77.904 42.043 78.297 42.089 ;
     RECT  29.196 41.981 35.334 42.179 ;
     RECT  68.508 42.151 68.526 42.187 ;
     RECT  49.968 41.675 62.097 42.223 ;
     RECT  63.108 42.089 66.438 42.223 ;
     RECT  12.132 41.659 27.018 42.235 ;
     RECT  27.9 41.981 28.134 42.235 ;
     RECT  83.196 41.819 84.15 42.287 ;
     RECT  67.215 42.089 67.497 42.331 ;
     RECT  68.4 42.187 68.526 42.359 ;
     RECT  12.132 42.235 28.134 42.485 ;
     RECT  83.196 42.287 84.078 42.557 ;
     RECT  84.888 41.441 86.382 42.593 ;
     RECT  0.144 41.837 0.162 42.601 ;
     RECT  79.488 40.199 79.578 42.715 ;
     RECT  45.615 40.925 46.17 42.727 ;
     RECT  82.62 42.571 82.638 42.763 ;
     RECT  82.08 42.763 82.638 42.791 ;
     RECT  36.324 40.739 36.342 42.811 ;
     RECT  37.764 40.019 43.254 42.811 ;
     RECT  82.08 42.791 82.098 42.863 ;
     RECT  45.615 42.727 46.638 42.871 ;
     RECT  0.144 42.601 0.558 42.988 ;
     RECT  36.324 42.811 43.254 42.989 ;
     RECT  29.196 42.179 35.19 43.025 ;
     RECT  79.488 42.715 79.722 43.051 ;
     RECT  45.615 42.871 46.89 43.069 ;
     RECT  47.7 42.799 47.718 43.069 ;
     RECT  37.584 42.989 43.254 43.085 ;
     RECT  79.488 43.051 80.37 43.097 ;
     RECT  79.488 43.097 79.722 43.133 ;
     RECT  34.704 43.025 35.19 43.141 ;
     RECT  12.132 42.485 26.838 43.169 ;
     RECT  34.704 43.141 35.37 43.181 ;
     RECT  45.615 43.069 47.718 43.259 ;
     RECT  0.108 42.988 0.558 43.277 ;
     RECT  12.132 43.169 26.802 43.295 ;
     RECT  45.615 43.259 46.854 43.295 ;
     RECT  49.968 42.223 66.438 43.295 ;
     RECT  45.615 43.295 46.17 43.331 ;
     RECT  84.924 42.593 86.382 43.339 ;
     RECT  0.108 43.277 0.522 43.373 ;
     RECT  34.704 43.181 35.154 43.403 ;
     RECT  84.888 43.339 86.382 43.435 ;
     RECT  50.148 43.295 66.438 43.501 ;
     RECT  67.215 42.331 67.554 43.501 ;
     RECT  84.852 43.435 86.382 43.565 ;
     RECT  45.615 43.331 46.062 43.672 ;
     RECT  2.415 41.648 2.697 43.681 ;
     RECT  45.504 43.672 46.062 43.709 ;
     RECT  83.415 42.557 84.078 43.723 ;
     RECT  84.852 43.565 85.23 43.723 ;
     RECT  29.196 43.025 33.714 43.771 ;
     RECT  34.704 43.403 35.097 43.771 ;
     RECT  83.415 43.723 85.23 43.819 ;
     RECT  83.196 43.819 85.23 43.835 ;
     RECT  50.148 43.501 67.554 43.871 ;
     RECT  79.488 43.133 79.578 43.915 ;
     RECT  86.076 43.565 86.382 44.105 ;
     RECT  45.615 43.709 46.062 44.149 ;
     RECT  2.304 43.681 2.697 44.185 ;
     RECT  49.248 44.113 49.266 44.221 ;
     RECT  50.148 43.871 66.438 44.221 ;
     RECT  2.304 44.185 2.862 44.249 ;
     RECT  0.108 43.373 0.342 44.266 ;
     RECT  0.108 44.266 0.594 44.3 ;
     RECT  2.415 44.249 2.862 44.339 ;
     RECT  0.144 44.3 0.594 44.381 ;
     RECT  45.615 44.149 46.53 44.381 ;
     RECT  83.196 43.835 84.366 44.383 ;
     RECT  79.2 43.915 79.578 44.447 ;
     RECT  82.8 44.383 84.366 44.477 ;
     RECT  86.076 44.105 86.31 44.483 ;
     RECT  0.144 44.381 0.558 44.525 ;
     RECT  0.144 44.525 0.522 44.621 ;
     RECT  45.615 44.381 46.062 44.683 ;
     RECT  83.16 44.477 84.366 44.789 ;
     RECT  86.076 44.483 86.238 44.957 ;
     RECT  49.248 44.221 66.438 44.971 ;
     RECT  85.176 43.835 85.23 44.971 ;
     RECT  86.076 44.957 86.13 44.971 ;
     RECT  29.196 43.771 35.097 45.019 ;
     RECT  2.415 44.339 2.79 45.059 ;
     RECT  79.74 44.587 79.794 45.059 ;
     RECT  83.415 44.789 84.366 45.067 ;
     RECT  85.176 44.971 86.13 45.067 ;
     RECT  45.036 44.683 46.062 45.121 ;
     RECT  29.196 45.019 35.19 45.163 ;
     RECT  48.852 44.971 66.438 45.185 ;
     RECT  83.415 45.067 86.13 45.185 ;
     RECT  49.032 45.185 66.438 45.197 ;
     RECT  45.036 45.121 46.746 45.211 ;
     RECT  79.776 45.059 79.794 45.221 ;
     RECT  12.132 43.295 26.298 45.259 ;
     RECT  29.196 45.163 35.298 45.259 ;
     RECT  44.532 45.211 46.746 45.293 ;
     RECT  47.844 43.645 47.862 45.301 ;
     RECT  49.032 45.197 49.194 45.302 ;
     RECT  86.112 45.185 86.13 45.329 ;
     RECT  0.144 44.621 0.162 45.388 ;
     RECT  47.772 45.301 47.934 45.419 ;
     RECT  45.615 45.293 46.746 45.427 ;
     RECT  47.844 45.419 47.934 45.451 ;
     RECT  49.032 45.302 49.158 45.491 ;
     RECT  49.968 45.197 66.438 45.527 ;
     RECT  83.415 45.185 85.194 45.527 ;
     RECT  12.132 45.259 26.802 45.533 ;
     RECT  29.196 45.259 35.406 45.533 ;
     RECT  47.844 45.451 48.222 45.563 ;
     RECT  37.764 43.085 43.254 45.661 ;
     RECT  44.532 45.293 44.874 45.661 ;
     RECT  45.615 45.427 46.818 45.661 ;
     RECT  50.148 45.527 66.438 45.661 ;
     RECT  67.215 43.871 67.554 45.661 ;
     RECT  82.044 43.099 82.062 45.689 ;
     RECT  48.132 45.563 48.222 45.725 ;
     RECT  45.615 45.661 46.854 45.797 ;
     RECT  48.204 45.725 48.222 45.797 ;
     RECT  2.415 45.059 2.697 45.832 ;
     RECT  50.148 45.661 67.554 45.833 ;
     RECT  2.304 45.832 2.697 45.869 ;
     RECT  78.015 42.089 78.297 45.931 ;
     RECT  50.148 45.833 67.497 45.968 ;
     RECT  77.904 45.931 78.297 45.968 ;
     RECT  29.196 45.533 35.097 45.995 ;
     RECT  3.96 45.967 3.978 46.013 ;
     RECT  49.032 45.491 49.122 46.031 ;
     RECT  86.256 45.739 86.31 46.075 ;
     RECT  37.764 45.661 44.874 46.111 ;
     RECT  45.615 45.797 46.818 46.111 ;
     RECT  49.032 46.031 49.086 46.139 ;
     RECT  68.508 42.359 68.526 46.139 ;
     RECT  84.888 45.527 85.194 46.219 ;
     RECT  0.108 45.388 0.198 46.237 ;
     RECT  50.148 45.968 66.438 46.499 ;
     RECT  49.068 46.139 49.086 46.535 ;
     RECT  0.108 46.237 0.486 46.541 ;
     RECT  82.62 46.075 82.638 46.555 ;
     RECT  84.888 46.219 85.482 46.555 ;
     RECT  86.22 46.075 86.31 46.555 ;
     RECT  27.9 42.485 28.134 46.579 ;
     RECT  37.764 46.111 46.818 46.603 ;
     RECT  82.044 46.555 82.638 46.603 ;
     RECT  83.415 45.527 83.697 46.603 ;
     RECT  27.144 46.579 28.134 46.651 ;
     RECT  84.888 46.555 86.31 46.679 ;
     RECT  29.196 45.995 33.714 46.741 ;
     RECT  34.524 45.995 35.097 46.741 ;
     RECT  37.764 46.603 47.502 46.741 ;
     RECT  12.132 45.533 26.298 46.747 ;
     RECT  27.144 46.651 28.386 46.747 ;
     RECT  82.044 46.603 83.697 46.805 ;
     RECT  37.764 46.741 47.682 46.891 ;
     RECT  82.044 46.805 82.098 46.913 ;
     RECT  12.132 46.747 28.386 46.949 ;
     RECT  27.18 46.949 28.386 47.069 ;
     RECT  0.144 46.541 0.486 47.083 ;
     RECT  37.764 46.891 47.718 47.083 ;
     RECT  0.144 47.083 0.558 47.165 ;
     RECT  82.044 46.913 82.062 47.219 ;
     RECT  50.364 46.499 66.438 47.309 ;
     RECT  84.888 46.679 86.238 47.309 ;
     RECT  0.432 47.165 0.558 47.323 ;
     RECT  0.432 47.323 0.594 47.371 ;
     RECT  1.404 29.741 1.422 47.371 ;
     RECT  37.764 47.083 48.51 47.389 ;
     RECT  37.764 47.389 49.05 47.551 ;
     RECT  37.764 47.551 49.23 47.645 ;
     RECT  37.764 47.645 49.158 47.687 ;
     RECT  50.436 47.309 66.438 47.885 ;
     RECT  84.888 47.309 85.59 47.885 ;
     RECT  0.432 47.371 1.422 47.947 ;
     RECT  83.196 46.805 83.697 47.947 ;
     RECT  84.888 47.885 85.554 47.947 ;
     RECT  2.415 45.869 2.697 47.995 ;
     RECT  83.196 47.947 85.554 48.029 ;
     RECT  50.58 47.885 66.438 48.155 ;
     RECT  0.108 47.947 1.422 48.389 ;
     RECT  3.96 48.361 3.978 48.413 ;
     RECT  2.415 47.995 2.754 48.461 ;
     RECT  37.764 47.687 49.086 48.461 ;
     RECT  0.144 48.389 1.422 48.653 ;
     RECT  83.415 48.029 85.554 48.845 ;
     RECT  50.832 48.155 66.438 48.937 ;
     RECT  50.796 48.937 66.438 49.009 ;
     RECT  84.924 48.845 85.554 49.045 ;
     RECT  86.292 48.907 86.31 49.045 ;
     RECT  0.18 48.653 1.422 49.133 ;
     RECT  50.58 49.009 66.438 49.207 ;
     RECT  0.18 49.133 0.27 49.229 ;
     RECT  2.415 48.461 2.697 49.291 ;
     RECT  2.415 49.291 2.718 49.315 ;
     RECT  84.924 49.045 86.31 49.325 ;
     RECT  37.764 48.461 49.05 49.351 ;
     RECT  50.436 49.207 66.438 49.351 ;
     RECT  2.415 49.315 2.79 49.373 ;
     RECT  37.764 49.351 66.438 49.505 ;
     RECT  84.924 49.325 85.518 49.579 ;
     RECT  36.324 42.989 36.342 49.621 ;
     RECT  84.888 49.579 85.518 49.649 ;
     RECT  2.415 49.373 2.697 49.675 ;
     RECT  83.415 48.845 83.79 49.675 ;
     RECT  36.324 49.621 36.954 49.739 ;
     RECT  37.764 49.505 49.662 49.747 ;
     RECT  12.132 46.949 26.298 49.819 ;
     RECT  29.196 46.741 35.097 49.819 ;
     RECT  36.324 49.739 36.342 49.855 ;
     RECT  12.132 49.819 26.802 50.045 ;
     RECT  29.196 49.819 35.154 50.045 ;
     RECT  83.415 49.675 84.366 50.059 ;
     RECT  83.196 50.059 84.366 50.153 ;
     RECT  37.584 49.747 49.662 50.251 ;
     RECT  50.688 49.505 66.438 50.251 ;
     RECT  85.176 49.649 85.518 50.285 ;
     RECT  2.304 49.675 2.697 50.288 ;
     RECT  29.196 50.045 35.097 50.381 ;
     RECT  35.892 49.855 36.342 50.381 ;
     RECT  0.144 49.387 0.162 50.395 ;
     RECT  0.144 50.395 0.198 50.443 ;
     RECT  0.108 50.443 0.198 50.629 ;
     RECT  1.152 49.133 1.422 50.629 ;
     RECT  37.584 50.251 66.438 50.635 ;
     RECT  81.468 50.635 81.486 50.693 ;
     RECT  0.108 50.629 1.422 50.729 ;
     RECT  29.196 50.381 30.798 50.729 ;
     RECT  85.176 50.285 85.482 50.731 ;
     RECT  83.196 50.153 83.826 50.791 ;
     RECT  84.924 50.731 85.482 50.819 ;
     RECT  37.188 50.635 66.438 50.855 ;
     RECT  82.656 50.791 83.826 50.923 ;
     RECT  84.924 50.819 85.194 50.999 ;
     RECT  86.292 49.325 86.31 51.019 ;
     RECT  2.415 50.288 2.697 51.061 ;
     RECT  2.415 51.061 2.79 51.101 ;
     RECT  82.62 50.923 83.826 51.125 ;
     RECT  86.112 51.019 86.31 51.149 ;
     RECT  83.196 51.125 83.826 51.197 ;
     RECT  83.415 51.197 83.826 51.211 ;
     RECT  37.224 50.855 66.438 51.431 ;
     RECT  82.044 51.403 82.062 51.467 ;
     RECT  0.108 50.729 0.522 51.475 ;
     RECT  37.44 51.431 66.438 51.809 ;
     RECT  86.148 51.149 86.31 51.821 ;
     RECT  3.96 51.907 3.978 51.965 ;
     RECT  83.415 51.211 84.366 51.973 ;
     RECT  85.176 50.999 85.194 51.973 ;
     RECT  83.415 51.973 85.194 52.109 ;
     RECT  86.22 51.821 86.31 52.205 ;
     RECT  86.22 52.205 86.238 52.253 ;
     RECT  2.415 51.101 2.697 52.285 ;
     RECT  2.415 52.285 2.862 52.321 ;
     RECT  2.304 52.321 2.862 52.397 ;
     RECT  83.415 52.109 84.366 52.405 ;
     RECT  83.304 52.405 84.366 52.411 ;
     RECT  2.415 52.397 2.862 52.439 ;
     RECT  82.62 52.411 84.366 52.589 ;
     RECT  0.108 51.475 0.558 52.685 ;
     RECT  0.144 52.685 0.558 52.795 ;
     RECT  83.415 52.589 84.366 52.843 ;
     RECT  85.176 52.109 85.194 52.843 ;
     RECT  83.415 52.843 85.194 53.035 ;
     RECT  86.22 53.083 86.238 53.131 ;
     RECT  83.415 53.035 85.482 53.158 ;
     RECT  86.22 53.131 86.31 53.158 ;
     RECT  80.352 53.083 80.37 53.159 ;
     RECT  83.415 53.158 86.31 53.453 ;
     RECT  0.144 52.795 0.594 53.548 ;
     RECT  36.324 50.381 36.342 53.563 ;
     RECT  37.764 51.809 66.438 53.563 ;
     RECT  0.108 53.548 0.594 53.645 ;
     RECT  2.415 52.439 2.697 53.659 ;
     RECT  2.415 53.659 2.79 53.699 ;
     RECT  82.62 52.589 82.638 53.803 ;
     RECT  83.415 53.453 85.482 53.803 ;
     RECT  86.22 53.453 86.31 53.885 ;
     RECT  36.324 53.563 66.438 53.933 ;
     RECT  82.62 53.803 85.482 53.933 ;
     RECT  0.108 53.645 0.558 54.029 ;
     RECT  31.608 50.381 35.097 54.067 ;
     RECT  0.108 54.029 0.342 54.125 ;
     RECT  82.62 53.933 85.194 54.131 ;
     RECT  12.132 50.045 26.298 54.331 ;
     RECT  81.468 53.899 81.486 54.379 ;
     RECT  82.62 54.131 82.638 54.437 ;
     RECT  74.664 54.379 74.682 54.509 ;
     RECT  81.468 54.379 81.774 54.509 ;
     RECT  37.764 53.933 66.438 54.571 ;
     RECT  67.215 45.968 67.497 54.571 ;
     RECT  78.015 45.968 78.297 54.571 ;
     RECT  37.764 54.571 67.497 54.608 ;
     RECT  77.904 54.571 78.297 54.608 ;
     RECT  27.9 47.069 28.134 54.667 ;
     RECT  12.132 54.331 26.91 54.701 ;
     RECT  31.608 54.067 35.334 54.715 ;
     RECT  36.324 53.933 36.774 54.715 ;
     RECT  86.256 53.885 86.31 54.715 ;
     RECT  31.608 54.715 36.774 54.751 ;
     RECT  37.764 54.608 66.438 54.751 ;
     RECT  83.415 54.131 85.194 54.751 ;
     RECT  86.148 54.715 86.31 54.751 ;
     RECT  83.415 54.751 86.31 54.989 ;
     RECT  0.108 54.125 0.306 55.051 ;
     RECT  2.415 53.699 2.697 55.099 ;
     RECT  2.304 55.099 2.697 55.111 ;
     RECT  2.304 55.111 2.718 55.139 ;
     RECT  0.108 55.051 0.378 55.181 ;
     RECT  27.9 54.667 28.386 55.183 ;
     RECT  29.196 50.729 30.582 55.183 ;
     RECT  0.108 55.181 0.306 55.247 ;
     RECT  2.415 55.139 2.718 55.381 ;
     RECT  2.415 55.381 2.79 55.421 ;
     RECT  12.132 54.701 26.442 55.561 ;
     RECT  78.015 54.608 78.297 55.675 ;
     RECT  3.96 55.651 3.978 55.709 ;
     RECT  86.076 54.989 86.31 55.709 ;
     RECT  1.404 50.729 1.422 56.129 ;
     RECT  2.415 55.421 2.697 56.191 ;
     RECT  31.608 54.751 66.438 56.191 ;
     RECT  67.215 54.608 67.497 56.191 ;
     RECT  78.015 55.675 78.354 56.191 ;
     RECT  83.415 54.989 85.194 56.191 ;
     RECT  27.9 55.183 30.582 56.203 ;
     RECT  31.608 56.191 67.497 56.203 ;
     RECT  27.9 56.203 67.497 56.237 ;
     RECT  77.904 56.191 78.354 56.237 ;
     RECT  0.108 55.247 0.198 56.255 ;
     RECT  27.9 56.237 66.438 56.333 ;
     RECT  83.304 56.191 85.194 56.491 ;
     RECT  86.112 55.709 86.31 56.491 ;
     RECT  74.664 56.539 74.682 56.669 ;
     RECT  83.304 56.491 86.31 56.669 ;
     RECT  0.144 56.255 0.198 56.827 ;
     RECT  27.9 56.333 30.798 56.861 ;
     RECT  12.132 55.561 26.658 56.875 ;
     RECT  27.9 56.861 30.582 56.875 ;
     RECT  83.415 56.669 86.31 57.173 ;
     RECT  2.304 56.191 2.697 57.209 ;
     RECT  12.132 56.875 30.582 57.335 ;
     RECT  0.144 56.827 0.234 57.479 ;
     RECT  0.144 57.479 0.198 57.487 ;
     RECT  83.415 57.173 86.274 57.641 ;
     RECT  0.108 57.487 0.198 57.725 ;
     RECT  0.108 57.725 0.162 57.773 ;
     RECT  83.415 57.641 85.518 57.947 ;
     RECT  27.9 57.335 30.582 57.991 ;
     RECT  12.132 57.335 26.658 58.123 ;
     RECT  27.9 57.991 30.762 58.225 ;
     RECT  86.256 57.641 86.274 58.507 ;
     RECT  12.132 58.123 26.766 58.621 ;
     RECT  27.504 58.225 30.762 58.621 ;
     RECT  0.144 57.773 0.162 58.657 ;
     RECT  12.132 58.621 30.762 58.685 ;
     RECT  0.108 58.657 0.198 58.781 ;
     RECT  2.415 57.209 2.697 58.792 ;
     RECT  81.756 54.509 81.774 58.829 ;
     RECT  84.636 57.947 85.518 58.927 ;
     RECT  86.256 58.507 86.31 58.927 ;
     RECT  84.636 58.927 86.31 58.955 ;
     RECT  27.792 58.685 30.762 59.071 ;
     RECT  31.608 56.333 66.438 59.071 ;
     RECT  3.96 59.035 3.978 59.099 ;
     RECT  27.792 59.071 66.438 59.213 ;
     RECT  85.176 58.955 86.31 59.261 ;
     RECT  2.304 58.792 2.697 59.405 ;
     RECT  14.328 58.685 26.946 59.431 ;
     RECT  27.792 59.213 29.79 59.431 ;
     RECT  0.108 58.781 0.126 59.515 ;
     RECT  78.015 56.237 78.354 59.639 ;
     RECT  0.108 59.515 0.162 59.692 ;
     RECT  85.176 59.261 85.518 59.693 ;
     RECT  2.415 59.405 2.697 59.707 ;
     RECT  14.328 59.431 29.79 59.741 ;
     RECT  2.415 59.707 2.79 59.765 ;
     RECT  2.415 59.765 2.718 59.789 ;
     RECT  86.256 59.261 86.31 59.971 ;
     RECT  0.108 59.692 0.198 60.091 ;
     RECT  86.256 59.971 86.382 60.091 ;
     RECT  29.088 59.741 29.79 60.283 ;
     RECT  2.415 59.789 2.697 60.331 ;
     RECT  30.564 59.213 66.438 60.413 ;
     RECT  7.815 31.559 8.097 60.421 ;
     RECT  85.176 59.693 85.194 60.421 ;
     RECT  86.112 60.091 86.382 60.421 ;
     RECT  7.704 60.421 8.097 60.461 ;
     RECT  85.176 60.421 86.382 60.461 ;
     RECT  31.608 60.413 66.438 60.511 ;
     RECT  67.215 56.237 67.497 60.511 ;
     RECT  78.015 59.639 78.297 60.511 ;
     RECT  0.108 60.091 0.234 60.523 ;
     RECT  31.608 60.511 67.497 60.557 ;
     RECT  77.904 60.511 78.297 60.557 ;
     RECT  29.088 60.283 29.826 60.583 ;
     RECT  30.564 60.413 30.762 60.583 ;
     RECT  0.108 60.523 0.342 60.653 ;
     RECT  0.108 60.653 0.27 60.683 ;
     RECT  14.328 59.741 28.278 60.925 ;
     RECT  29.088 60.583 30.762 60.925 ;
     RECT  0.144 60.683 0.27 60.941 ;
     RECT  14.328 60.925 30.762 61.195 ;
     RECT  31.608 60.557 66.438 61.195 ;
     RECT  14.328 61.195 66.438 61.483 ;
     RECT  67.215 60.557 67.497 61.483 ;
     RECT  78.015 60.557 78.297 61.483 ;
     RECT  14.328 61.483 67.497 61.529 ;
     RECT  77.904 61.483 78.297 61.529 ;
     RECT  7.815 60.461 8.097 61.579 ;
     RECT  86.22 60.461 86.382 61.579 ;
     RECT  2.304 60.331 2.697 61.619 ;
     RECT  7.704 61.579 8.097 61.619 ;
     RECT  83.415 57.947 83.697 61.675 ;
     RECT  2.415 61.619 2.697 61.765 ;
     RECT  7.815 61.619 8.097 61.765 ;
     RECT  12.132 58.685 13.497 61.765 ;
     RECT  83.412 61.675 83.697 61.771 ;
     RECT  83.412 61.771 83.79 61.799 ;
     RECT  83.415 61.799 83.79 61.808 ;
     RECT  0.144 60.941 0.234 61.963 ;
     RECT  86.04 61.579 86.382 62.093 ;
     RECT  85.176 60.461 85.194 62.155 ;
     RECT  2.415 61.765 2.79 62.203 ;
     RECT  6.624 37.391 6.642 62.203 ;
     RECT  7.815 61.765 8.19 62.203 ;
     RECT  11.16 34.205 11.394 62.203 ;
     RECT  12.132 61.765 13.59 62.203 ;
     RECT  14.328 61.529 66.438 62.203 ;
     RECT  0.108 61.963 0.234 62.347 ;
     RECT  6.624 62.203 6.858 62.347 ;
     RECT  85.176 62.155 85.482 62.443 ;
     RECT  6.624 62.347 7.038 62.477 ;
     RECT  12.132 62.203 66.438 62.477 ;
     RECT  0.108 62.347 0.342 62.537 ;
     RECT  0.144 62.537 0.342 62.573 ;
     RECT  2.415 62.203 3.006 62.573 ;
     RECT  7.815 62.203 8.478 62.573 ;
     RECT  2.415 62.573 2.97 62.813 ;
     RECT  6.624 62.477 6.966 62.813 ;
     RECT  84.636 62.443 85.482 62.815 ;
     RECT  86.22 62.093 86.382 62.815 ;
     RECT  2.415 62.813 2.862 62.909 ;
     RECT  6.624 62.813 6.858 63.053 ;
     RECT  10.836 62.203 11.394 63.053 ;
     RECT  2.415 62.909 2.697 63.112 ;
     RECT  2.304 63.112 2.697 63.149 ;
     RECT  0.144 62.573 0.27 63.245 ;
     RECT  0.144 63.245 0.234 63.533 ;
     RECT  0.144 63.533 0.198 64.012 ;
     RECT  84.636 62.815 86.382 64.193 ;
     RECT  14.328 62.477 66.438 64.355 ;
     RECT  2.415 63.149 2.697 64.555 ;
     RECT  7.815 62.573 8.097 64.555 ;
     RECT  12.132 62.477 13.497 64.555 ;
     RECT  84.636 64.193 86.31 64.589 ;
     RECT  2.415 64.555 2.79 64.595 ;
     RECT  7.815 64.555 8.19 64.595 ;
     RECT  12.132 64.555 13.59 64.595 ;
     RECT  0.108 64.012 0.198 64.925 ;
     RECT  86.04 64.589 86.31 64.973 ;
     RECT  3.96 64.291 3.978 65.039 ;
     RECT  2.415 64.595 2.697 65.281 ;
     RECT  83.415 61.808 83.697 65.365 ;
     RECT  14.58 64.355 66.438 65.371 ;
     RECT  67.215 61.529 67.497 65.371 ;
     RECT  78.015 61.529 78.297 65.371 ;
     RECT  14.58 65.371 67.497 65.408 ;
     RECT  77.904 65.371 78.297 65.408 ;
     RECT  84.636 64.589 85.302 65.479 ;
     RECT  68.364 65.131 68.382 65.579 ;
     RECT  0.108 64.925 0.126 65.659 ;
     RECT  83.304 65.365 83.697 65.707 ;
     RECT  84.636 65.479 85.518 65.713 ;
     RECT  0.108 65.659 0.198 65.755 ;
     RECT  84.636 65.713 85.554 65.803 ;
     RECT  86.292 64.973 86.31 65.803 ;
     RECT  2.304 65.281 2.697 65.849 ;
     RECT  12.132 64.595 13.497 65.899 ;
     RECT  14.58 65.408 66.438 65.899 ;
     RECT  0.108 65.755 0.234 66.125 ;
     RECT  12.132 65.899 66.438 66.245 ;
     RECT  83.196 65.707 83.697 66.281 ;
     RECT  0.108 66.125 0.198 66.365 ;
     RECT  0.108 66.365 0.126 66.413 ;
     RECT  83.415 66.281 83.697 66.631 ;
     RECT  83.415 66.631 83.79 66.701 ;
     RECT  12.6 66.245 66.438 66.785 ;
     RECT  12.708 66.785 66.438 67.055 ;
     RECT  12.816 67.055 66.438 67.127 ;
     RECT  11.16 63.053 11.394 67.291 ;
     RECT  2.415 65.849 2.697 67.432 ;
     RECT  12.888 67.127 66.438 67.432 ;
     RECT  67.215 65.408 67.497 67.432 ;
     RECT  78.015 65.408 78.297 67.432 ;
     RECT  74.664 67.297 74.682 67.469 ;
     RECT  2.304 67.432 2.697 67.568 ;
     RECT  9.252 33.035 9.27 67.595 ;
     RECT  84.636 65.803 86.31 67.667 ;
     RECT  10.836 67.291 11.394 67.837 ;
     RECT  10.728 67.837 11.394 67.901 ;
     RECT  83.415 66.701 83.697 67.963 ;
     RECT  12.888 67.432 67.497 68.009 ;
     RECT  77.904 67.432 78.297 68.009 ;
     RECT  83.304 67.963 83.697 68.107 ;
     RECT  83.196 68.107 83.697 68.237 ;
     RECT  2.415 67.568 2.697 68.299 ;
     RECT  7.815 64.595 8.097 68.299 ;
     RECT  2.415 68.299 2.79 68.369 ;
     RECT  7.815 68.299 8.19 68.369 ;
     RECT  84.636 67.667 85.662 68.395 ;
     RECT  0.144 67.243 0.162 68.443 ;
     RECT  0.144 68.443 0.234 68.621 ;
     RECT  10.836 67.901 11.394 68.675 ;
     RECT  10.836 68.675 10.962 68.683 ;
     RECT  0.144 68.621 0.198 68.791 ;
     RECT  6.624 63.053 6.642 68.881 ;
     RECT  0.108 68.791 0.198 68.909 ;
     RECT  6.624 68.881 6.822 68.945 ;
     RECT  10.44 68.683 10.962 68.945 ;
     RECT  12.888 68.009 66.438 68.953 ;
     RECT  6.804 68.945 6.822 68.981 ;
     RECT  84.636 68.395 86.31 69.053 ;
     RECT  86.112 69.053 86.31 69.101 ;
     RECT  2.415 68.369 2.697 69.151 ;
     RECT  10.656 68.945 10.962 69.245 ;
     RECT  86.292 69.101 86.31 69.341 ;
     RECT  0.144 68.909 0.198 69.355 ;
     RECT  12.528 68.953 66.438 69.449 ;
     RECT  84.636 69.053 85.302 69.629 ;
     RECT  10.836 69.245 10.962 69.821 ;
     RECT  85.284 69.629 85.302 69.899 ;
     RECT  0.144 69.355 0.234 70.025 ;
     RECT  12.888 69.449 66.438 70.025 ;
     RECT  0.144 70.025 0.162 70.061 ;
     RECT  10.836 69.821 10.854 70.061 ;
     RECT  2.304 69.151 2.697 70.169 ;
     RECT  13.104 70.025 66.438 70.169 ;
     RECT  0.108 70.219 0.126 70.349 ;
     RECT  13.215 70.169 66.438 74.075 ;
     RECT  14.22 74.075 66.438 77.549 ;
     RECT  48.6 77.549 66.438 78.653 ;
     RECT  14.22 77.549 47.61 80.285 ;
     RECT  14.292 80.285 47.61 80.381 ;
     RECT  14.508 80.381 47.61 80.555 ;
     RECT  14.544 80.555 47.61 80.909 ;
     RECT  14.544 80.909 47.178 80.957 ;
     RECT  48.636 78.653 66.438 81.485 ;
     RECT  50.76 81.485 60.318 82.109 ;
     RECT  14.544 80.957 46.602 82.637 ;
     RECT  50.832 82.109 60.318 82.637 ;
     RECT  14.544 82.637 46.062 83.213 ;
     RECT  48.636 81.485 49.986 83.213 ;
     RECT  48.636 83.213 49.23 83.261 ;
     RECT  14.544 83.213 33.354 83.291 ;
     RECT  34.416 83.213 46.062 83.563 ;
     RECT  28.908 83.291 33.354 83.741 ;
     RECT  14.544 83.291 28.17 83.789 ;
     RECT  28.908 83.741 31.59 83.789 ;
     RECT  34.416 83.563 46.134 83.789 ;
     RECT  49.212 83.261 49.23 83.789 ;
     RECT  34.416 83.789 38.43 83.837 ;
     RECT  39.24 83.789 42.21 83.837 ;
     RECT  2.415 70.169 2.697 83.987 ;
     RECT  7.815 68.369 8.097 83.987 ;
     RECT  13.215 74.075 13.497 83.987 ;
     RECT  67.215 68.009 67.497 83.987 ;
     RECT  72.615 40.589 72.897 83.987 ;
     RECT  78.015 68.009 78.297 83.987 ;
     RECT  83.415 68.237 83.697 83.987 ;
     RECT  2.415 83.987 2.505 84.257 ;
     RECT  7.815 83.987 7.905 84.257 ;
     RECT  13.215 83.987 13.305 84.257 ;
     RECT  67.215 83.987 67.305 84.257 ;
     RECT  72.615 83.987 72.705 84.257 ;
     RECT  78.015 83.987 78.105 84.257 ;
     RECT  83.415 83.987 83.505 84.257 ;
     RECT  14.616 83.789 28.17 84.365 ;
     RECT  28.908 83.789 31.266 84.365 ;
     RECT  32.328 83.741 33.354 84.365 ;
     RECT  49.968 83.213 49.986 84.365 ;
     RECT  50.832 82.637 60.066 84.365 ;
     RECT  29.232 84.365 31.194 84.413 ;
     RECT  59.436 84.365 60.066 84.413 ;
     RECT  14.76 84.365 14.778 84.941 ;
     RECT  15.516 84.365 26.73 84.941 ;
     RECT  32.508 84.365 33.354 84.941 ;
     RECT  34.416 83.837 38.106 84.941 ;
     RECT  43.92 83.789 46.134 84.941 ;
     RECT  50.832 84.365 58.698 84.941 ;
     RECT  61.164 81.485 66.438 84.941 ;
     RECT  15.516 84.941 22.482 84.989 ;
     RECT  23.292 84.941 26.55 84.989 ;
     RECT  32.508 84.941 32.526 84.989 ;
     RECT  43.92 84.941 43.938 84.989 ;
     RECT  44.82 84.941 45.018 84.989 ;
     RECT  50.832 84.941 50.958 84.989 ;
     RECT  52.488 84.941 58.698 85.037 ;
     RECT  15.516 84.989 16.65 85.517 ;
     RECT  17.712 84.989 22.482 85.517 ;
     RECT  24.84 84.989 26.55 85.517 ;
     RECT  29.304 84.413 31.194 85.517 ;
     RECT  34.416 84.941 35.946 85.517 ;
     RECT  36.684 84.941 38.106 85.517 ;
     RECT  39.24 83.837 42.066 85.517 ;
     RECT  45 84.989 45.018 85.517 ;
     RECT  50.94 84.989 50.958 85.517 ;
     RECT  52.488 85.037 57.006 85.517 ;
     RECT  59.436 84.413 59.994 85.517 ;
     RECT  61.164 84.941 62.586 85.517 ;
     RECT  16.632 85.517 16.65 85.565 ;
     RECT  17.784 85.517 22.482 85.565 ;
     RECT  52.488 85.517 55.314 85.565 ;
     RECT  58.212 85.037 58.698 85.565 ;
     RECT  61.164 85.517 61.686 85.565 ;
     RECT  46.116 84.941 46.134 86.155 ;
     RECT  62.532 85.517 62.586 86.189 ;
     RECT  17.82 85.565 22.482 86.237 ;
     RECT  24.876 85.517 26.226 86.237 ;
     RECT  27.468 84.365 27.81 86.237 ;
     RECT  30.348 85.517 31.194 86.237 ;
     RECT  36.684 85.517 37.458 86.237 ;
     RECT  17.82 86.237 20.718 86.285 ;
     RECT  21.6 86.237 22.482 86.285 ;
     RECT  23.292 84.989 23.922 86.285 ;
     RECT  24.876 86.237 25.902 86.285 ;
     RECT  27.468 86.237 27.486 86.285 ;
     RECT  29.304 85.517 29.322 86.285 ;
     RECT  30.348 86.237 30.69 86.285 ;
     RECT  33.336 84.941 33.354 86.285 ;
     RECT  34.416 85.517 34.434 86.285 ;
     RECT  35.208 85.517 35.226 86.285 ;
     RECT  36.792 86.237 37.458 86.285 ;
     RECT  39.24 85.517 41.67 86.285 ;
     RECT  45.684 86.155 46.134 86.285 ;
     RECT  52.596 85.565 54.63 86.285 ;
     RECT  56.124 85.517 56.142 86.285 ;
     RECT  58.68 85.565 58.698 86.285 ;
     RECT  59.508 85.517 59.994 86.285 ;
     RECT  61.164 85.565 61.542 86.285 ;
     RECT  62.532 86.189 62.55 86.285 ;
     RECT  63.504 84.941 66.438 86.285 ;
     RECT  30.564 86.285 30.582 86.381 ;
     RECT  31.896 86.251 31.914 86.381 ;
    LAYER M4 ;
     RECT  0.06 15.792 0.097 70.248 ;
     RECT  0.097 15.792 0.173 70.344 ;
     RECT  0.173 15.792 2.408 66.36 ;
     RECT  0.173 67.344 2.408 70.344 ;
     RECT  2.408 2.148 2.512 84.252 ;
     RECT  2.512 2.418 2.704 83.982 ;
     RECT  2.704 15.792 3.341 66.36 ;
     RECT  3.341 36.336 4.349 66.36 ;
     RECT  3.341 15.792 7.808 35.256 ;
     RECT  4.349 36.576 7.808 66.36 ;
     RECT  2.704 67.344 7.808 70.344 ;
     RECT  7.808 2.148 7.912 84.252 ;
     RECT  7.912 2.418 8.104 83.982 ;
     RECT  8.104 19.008 8.453 35.256 ;
     RECT  8.453 24.96 8.561 35.256 ;
     RECT  8.561 25.488 9.893 35.256 ;
     RECT  8.453 19.008 10.253 23.976 ;
     RECT  9.893 25.488 10.253 25.512 ;
     RECT  8.104 36.576 10.825 66.36 ;
     RECT  8.104 67.344 10.825 70.344 ;
     RECT  10.253 19.008 10.829 23.88 ;
     RECT  9.893 26.496 10.937 35.256 ;
     RECT  10.829 19.008 12.017 23.448 ;
     RECT  10.937 26.592 13.121 35.256 ;
     RECT  8.104 15.792 13.208 17.4 ;
     RECT  12.017 19.008 13.208 23.4 ;
     RECT  13.121 26.592 13.208 35.304 ;
     RECT  10.825 36.576 13.208 70.344 ;
     RECT  13.208 2.148 13.312 84.252 ;
     RECT  13.312 2.418 13.504 83.982 ;
     RECT  13.504 80.256 14.321 80.376 ;
     RECT  13.504 83.76 14.341 83.982 ;
     RECT  14.341 83.76 14.533 84.36 ;
     RECT  14.533 83.76 14.573 84.936 ;
     RECT  14.321 80.256 14.629 80.28 ;
     RECT  14.573 84.24 14.789 84.936 ;
     RECT  13.504 26.592 14.821 35.304 ;
     RECT  13.504 19.008 14.861 23.4 ;
     RECT  14.629 80.16 14.861 80.28 ;
     RECT  14.861 80.256 14.933 80.28 ;
     RECT  14.861 21.456 15.149 23.4 ;
     RECT  14.789 84.24 15.365 84.36 ;
     RECT  14.821 82.08 15.397 82.104 ;
     RECT  14.917 83.184 15.397 83.208 ;
     RECT  15.365 84.336 15.401 84.36 ;
     RECT  13.504 36.576 15.437 70.344 ;
     RECT  14.821 26.256 15.473 35.304 ;
     RECT  15.301 80.352 15.617 80.376 ;
     RECT  15.505 85.488 15.793 85.512 ;
     RECT  15.397 82.08 15.905 83.208 ;
     RECT  15.793 84.96 15.923 85.512 ;
     RECT  15.905 82.656 15.973 83.208 ;
     RECT  15.973 82.656 16.115 83.256 ;
     RECT  15.589 78.624 16.265 78.648 ;
     RECT  15.149 21.504 16.301 23.4 ;
     RECT  16.189 81.504 16.307 81.528 ;
     RECT  15.923 85.392 16.549 85.512 ;
     RECT  16.549 85.392 16.661 85.56 ;
     RECT  16.661 85.392 16.691 85.512 ;
     RECT  15.437 36.576 16.693 66.36 ;
     RECT  15.437 67.344 16.693 70.344 ;
     RECT  16.369 24.912 16.837 24.936 ;
     RECT  16.301 22.176 16.877 23.4 ;
     RECT  16.115 82.656 16.883 82.728 ;
     RECT  16.693 36.576 16.913 70.344 ;
     RECT  16.883 82.704 16.979 82.728 ;
     RECT  16.913 36.576 17.125 66.36 ;
     RECT  16.837 24.912 17.161 25.512 ;
     RECT  16.405 83.808 17.171 83.832 ;
     RECT  17.161 24.672 17.197 25.512 ;
     RECT  15.473 26.592 17.201 35.304 ;
     RECT  17.197 24.384 17.593 25.512 ;
     RECT  17.201 26.592 17.593 35.256 ;
     RECT  17.161 84.96 17.66 84.984 ;
     RECT  17.66 84.96 17.746 85.512 ;
     RECT  17.746 84.96 17.765 85.56 ;
     RECT  16.877 22.176 17.845 23.352 ;
     RECT  17.593 24.384 17.845 35.256 ;
     RECT  17.765 84.96 17.939 86.28 ;
     RECT  17.939 84.96 18.035 84.984 ;
     RECT  18.053 82.608 18.341 82.632 ;
     RECT  17.845 22.176 18.349 35.256 ;
     RECT  17.125 36.528 18.349 66.36 ;
     RECT  18.133 83.808 18.565 83.832 ;
     RECT  13.504 15.792 18.608 17.4 ;
     RECT  14.861 19.008 18.608 20.424 ;
     RECT  18.349 22.176 18.608 66.36 ;
     RECT  16.913 67.344 18.608 70.344 ;
     RECT  18.341 82.032 18.608 82.632 ;
     RECT  18.565 83.808 18.608 84.408 ;
     RECT  18.608 2.148 18.712 84.408 ;
     RECT  18.712 2.418 18.904 84.408 ;
     RECT  17.939 86.064 18.956 86.28 ;
     RECT  18.956 86.016 18.997 86.28 ;
     RECT  18.904 18.816 19.145 20.424 ;
     RECT  18.997 85.488 19.237 86.28 ;
     RECT  18.904 22.752 19.397 66.36 ;
     RECT  19.397 22.752 19.505 23.016 ;
     RECT  19.397 24.336 19.901 66.36 ;
     RECT  18.904 67.632 19.933 70.344 ;
     RECT  19.901 36.528 20.081 66.36 ;
     RECT  19.237 84.912 20.225 86.28 ;
     RECT  19.145 19.008 20.257 20.424 ;
     RECT  18.904 15.792 20.437 17.4 ;
     RECT  20.437 15.792 20.617 17.64 ;
     RECT  20.257 18.768 20.617 20.424 ;
     RECT  19.901 24.336 20.873 35.256 ;
     RECT  19.505 22.992 21.109 23.016 ;
     RECT  20.873 24.336 21.109 26.664 ;
     RECT  21.109 22.992 21.125 26.664 ;
     RECT  21.125 22.992 21.155 24.6 ;
     RECT  19.933 67.44 21.229 70.344 ;
     RECT  20.081 36.576 21.445 66.36 ;
     RECT  21.229 67.344 21.445 70.344 ;
     RECT  21.155 22.992 21.449 23.928 ;
     RECT  21.125 26.208 21.881 26.664 ;
     RECT  21.881 26.64 22.313 26.664 ;
     RECT  20.225 85.488 22.355 86.28 ;
     RECT  21.925 84.336 22.457 84.36 ;
     RECT  22.117 76.368 22.501 76.392 ;
     RECT  22.501 76.32 22.693 76.392 ;
     RECT  21.445 36.576 22.741 70.344 ;
     RECT  22.741 36.528 22.813 70.344 ;
     RECT  22.693 75.84 22.817 76.392 ;
     RECT  22.817 76.32 22.853 76.392 ;
     RECT  22.789 82.032 22.961 82.056 ;
     RECT  22.885 74.016 23.173 74.04 ;
     RECT  22.355 86.256 23.365 86.28 ;
     RECT  22.813 36.528 23.461 70.824 ;
     RECT  22.597 84.912 23.533 84.936 ;
     RECT  23.365 86.208 23.533 86.28 ;
     RECT  20.617 15.792 24.008 20.424 ;
     RECT  20.873 27.648 24.008 35.256 ;
     RECT  23.461 36.528 24.008 70.92 ;
     RECT  23.173 74.016 24.008 74.088 ;
     RECT  22.853 76.368 24.008 76.392 ;
     RECT  23.653 77.52 24.008 77.544 ;
     RECT  22.981 79.776 24.008 79.8 ;
     RECT  23.533 84.912 24.008 86.28 ;
     RECT  24.008 2.148 24.112 86.28 ;
     RECT  24.112 2.418 24.304 86.28 ;
     RECT  24.304 36.528 24.545 70.92 ;
     RECT  24.304 72.384 24.553 72.408 ;
     RECT  24.304 83.76 24.659 86.28 ;
     RECT  24.304 74.064 24.697 74.088 ;
     RECT  24.304 82.656 24.947 82.68 ;
     RECT  24.304 15.792 25.049 20.424 ;
     RECT  24.304 75.216 25.121 75.24 ;
     RECT  24.659 83.76 25.765 84.408 ;
     RECT  24.659 85.488 25.765 86.28 ;
     RECT  24.545 36.528 25.801 70.824 ;
     RECT  25.801 36.384 25.909 70.824 ;
     RECT  25.765 83.76 25.913 86.28 ;
     RECT  25.909 36.24 26.093 70.824 ;
     RECT  26.093 70.608 26.165 70.824 ;
     RECT  25.913 83.76 26.237 86.232 ;
     RECT  26.093 36.24 26.273 69.336 ;
     RECT  26.053 80.352 26.345 80.376 ;
     RECT  26.237 83.76 26.533 85.512 ;
     RECT  26.533 83.712 26.561 85.512 ;
     RECT  26.273 36.24 26.741 36.552 ;
     RECT  26.561 83.712 26.741 84.936 ;
     RECT  26.437 82.608 26.876 82.632 ;
     RECT  26.741 83.712 26.876 84.36 ;
     RECT  26.725 78.048 26.957 78.072 ;
     RECT  26.273 37.728 27.029 69.336 ;
     RECT  26.876 82.608 27.097 84.36 ;
     RECT  27.097 82.08 27.209 84.36 ;
     RECT  27.209 82.08 27.251 82.104 ;
     RECT  26.165 70.656 27.301 70.824 ;
     RECT  27.209 83.184 27.317 84.36 ;
     RECT  27.301 70.656 27.347 71.064 ;
     RECT  26.809 72.672 27.347 72.696 ;
     RECT  27.317 83.808 27.347 84.36 ;
     RECT  27.397 86.208 27.497 86.28 ;
     RECT  27.497 86.208 27.821 86.232 ;
     RECT  27.347 84.192 27.857 84.36 ;
     RECT  27.857 84.288 27.893 84.36 ;
     RECT  26.741 36.528 27.925 36.552 ;
     RECT  27.347 70.8 28.109 71.064 ;
     RECT  24.304 28.8 28.141 35.256 ;
     RECT  27.925 36.24 28.141 36.552 ;
     RECT  25.049 15.792 28.145 20.376 ;
     RECT  27.893 84.336 29.125 84.36 ;
     RECT  27.029 37.92 29.149 69.336 ;
     RECT  28.141 28.8 29.185 36.552 ;
     RECT  29.149 37.68 29.185 69.336 ;
     RECT  29.221 86.256 29.269 86.28 ;
     RECT  29.125 84.336 29.365 84.936 ;
     RECT  28.145 15.792 29.408 19.08 ;
     RECT  28.145 20.304 29.408 20.376 ;
     RECT  29.185 28.8 29.408 69.336 ;
     RECT  28.109 70.8 29.408 70.824 ;
     RECT  28.321 72.384 29.408 72.408 ;
     RECT  29.257 75.696 29.408 75.72 ;
     RECT  28.933 78 29.408 78.024 ;
     RECT  27.877 80.352 29.408 80.376 ;
     RECT  28.861 83.232 29.408 83.256 ;
     RECT  29.365 84.336 29.408 85.032 ;
     RECT  29.408 2.148 29.512 85.032 ;
     RECT  29.512 2.418 29.701 85.032 ;
     RECT  29.269 86.16 29.701 86.28 ;
     RECT  29.701 2.418 29.704 86.28 ;
     RECT  29.704 28.8 29.945 70.056 ;
     RECT  29.704 83.712 29.981 86.28 ;
     RECT  29.981 83.712 30.089 84.36 ;
     RECT  29.704 20.304 30.233 20.328 ;
     RECT  29.704 80.16 30.233 80.376 ;
     RECT  30.233 80.352 30.341 80.376 ;
     RECT  29.704 72.72 30.377 72.744 ;
     RECT  29.945 28.8 30.413 69.768 ;
     RECT  29.981 85.488 30.553 86.28 ;
     RECT  30.413 28.8 30.881 69.336 ;
     RECT  30.089 83.76 31.045 84.36 ;
     RECT  30.553 85.488 31.045 86.376 ;
     RECT  31.045 83.76 31.061 86.376 ;
     RECT  31.061 83.76 31.169 84.936 ;
     RECT  31.061 86.208 31.205 86.376 ;
     RECT  31.196 82.656 31.333 82.68 ;
     RECT  30.881 37.68 31.453 69.336 ;
     RECT  31.169 83.76 31.525 84.36 ;
     RECT  31.453 37.68 31.529 69.384 ;
     RECT  31.333 82.224 31.529 82.68 ;
     RECT  31.525 83.712 31.621 84.36 ;
     RECT  31.717 78.528 31.777 78.552 ;
     RECT  31.777 78.528 31.813 78.696 ;
     RECT  31.621 83.136 31.817 84.36 ;
     RECT  31.529 67.536 31.853 69.384 ;
     RECT  31.205 86.256 31.925 86.376 ;
     RECT  31.925 86.256 31.969 86.28 ;
     RECT  31.813 78.048 32.033 78.696 ;
     RECT  31.957 80.4 32.051 80.424 ;
     RECT  31.817 83.232 32.357 84.36 ;
     RECT  32.033 78.672 32.435 78.696 ;
     RECT  32.389 77.52 32.531 77.544 ;
     RECT  31.529 37.68 32.677 66.264 ;
     RECT  31.853 67.536 32.677 69.336 ;
     RECT  32.497 84.912 32.723 84.984 ;
     RECT  32.723 84.912 32.825 84.936 ;
     RECT  30.881 28.8 32.965 36.552 ;
     RECT  32.677 37.68 32.965 69.336 ;
     RECT  32.773 81.456 33.005 81.48 ;
     RECT  32.357 83.232 33.077 83.784 ;
     RECT  33.029 76.368 33.113 76.392 ;
     RECT  33.253 75.792 33.289 75.816 ;
     RECT  33.289 75.264 33.395 75.816 ;
     RECT  33.395 75.792 33.401 75.816 ;
     RECT  33.445 73.536 33.617 73.56 ;
     RECT  33.637 79.776 33.901 79.8 ;
     RECT  33.733 82.608 34.012 83.208 ;
     RECT  34.012 82.56 34.076 83.208 ;
     RECT  33.157 86.256 34.46 86.28 ;
     RECT  33.901 78.912 34.765 79.8 ;
     RECT  29.704 15.792 34.808 19.08 ;
     RECT  32.965 28.8 34.808 69.336 ;
     RECT  34.765 78.672 34.808 79.8 ;
     RECT  34.076 82.08 34.808 83.208 ;
     RECT  34.808 2.148 34.885 84.252 ;
     RECT  34.885 2.148 34.912 84.408 ;
     RECT  34.912 2.418 35.104 84.408 ;
     RECT  35.104 82.032 35.165 84.408 ;
     RECT  35.104 78.672 35.219 78.936 ;
     RECT  34.46 85.488 35.237 86.28 ;
     RECT  35.219 78.912 35.267 78.936 ;
     RECT  35.237 85.488 35.267 86.136 ;
     RECT  35.104 70.512 35.309 70.68 ;
     RECT  35.104 15.84 35.345 19.08 ;
     RECT  35.104 75.84 35.356 75.864 ;
     RECT  35.165 82.032 35.813 83.832 ;
     RECT  35.104 73.536 35.921 73.56 ;
     RECT  35.813 82.08 35.987 83.832 ;
     RECT  35.267 85.488 36.133 85.512 ;
     RECT  35.309 70.56 36.209 70.68 ;
     RECT  36.133 84.912 36.284 85.512 ;
     RECT  35.345 15.984 36.313 19.08 ;
     RECT  36.209 70.656 36.317 70.68 ;
     RECT  36.284 84.384 36.371 85.512 ;
     RECT  36.371 84.912 36.389 85.512 ;
     RECT  35.987 82.08 36.497 83.208 ;
     RECT  36.389 85.488 36.517 85.512 ;
     RECT  36.497 82.08 36.755 82.632 ;
     RECT  36.755 82.608 37.001 82.632 ;
     RECT  37.177 21.984 37.249 22.008 ;
     RECT  36.517 85.488 37.381 86.28 ;
     RECT  37.381 85.44 37.469 86.28 ;
     RECT  36.901 78.048 37.477 78.072 ;
     RECT  37.249 21.744 37.501 22.008 ;
     RECT  35.104 28.8 37.685 69.336 ;
     RECT  36.313 15.984 37.753 19.944 ;
     RECT  37.477 78.048 37.757 78.648 ;
     RECT  37.757 78.048 37.765 78.552 ;
     RECT  37.765 77.52 37.829 78.552 ;
     RECT  37.501 21.744 37.897 22.104 ;
     RECT  37.469 85.44 37.937 85.512 ;
     RECT  37.897 21.744 38.005 22.2 ;
     RECT  37.753 15.984 38.041 20.376 ;
     RECT  37.829 77.52 38.045 77.592 ;
     RECT  37.685 28.8 38.113 49.896 ;
     RECT  37.937 85.488 38.117 85.512 ;
     RECT  38.053 75.84 38.189 75.864 ;
     RECT  37.825 82.08 38.195 82.104 ;
     RECT  38.041 15.984 38.297 20.424 ;
     RECT  38.245 83.76 38.321 83.784 ;
     RECT  38.321 83.664 38.368 83.784 ;
     RECT  38.045 77.52 38.369 77.544 ;
     RECT  38.368 83.664 38.405 83.832 ;
     RECT  38.113 27.888 38.473 49.896 ;
     RECT  38.405 83.76 38.483 83.832 ;
     RECT  38.473 27.312 38.557 49.896 ;
     RECT  38.629 74.64 38.725 74.664 ;
     RECT  38.483 83.76 38.729 83.784 ;
     RECT  37.685 50.88 38.765 69.336 ;
     RECT  38.725 74.112 38.837 74.664 ;
     RECT  38.005 21.648 38.941 22.2 ;
     RECT  38.557 27.888 38.945 49.896 ;
     RECT  37.789 25.056 38.981 25.08 ;
     RECT  38.689 26.256 38.981 26.28 ;
     RECT  38.917 86.256 39.109 86.28 ;
     RECT  38.297 16.32 39.409 20.424 ;
     RECT  39.397 84.912 39.481 84.936 ;
     RECT  39.109 86.208 39.481 86.28 ;
     RECT  39.481 84.912 39.805 86.28 ;
     RECT  38.945 28.8 39.985 49.896 ;
     RECT  38.765 50.928 39.985 69.336 ;
     RECT  39.805 84.384 40.019 86.28 ;
     RECT  39.589 25.632 40.049 25.656 ;
     RECT  39.409 16.32 40.208 20.472 ;
     RECT  38.941 21.648 40.208 23.112 ;
     RECT  40.049 25.632 40.208 26.232 ;
     RECT  39.985 28.8 40.208 69.336 ;
     RECT  39.733 70.656 40.208 70.68 ;
     RECT  38.837 74.112 40.208 74.136 ;
     RECT  38.821 76.368 40.208 76.392 ;
     RECT  39.013 77.904 40.208 78.072 ;
     RECT  40.208 2.148 40.312 84.252 ;
     RECT  40.312 2.418 40.504 84.252 ;
     RECT  40.504 25.2 40.643 25.224 ;
     RECT  40.504 27.312 40.717 27.336 ;
     RECT  40.504 28.8 40.835 69.336 ;
     RECT  40.019 85.488 41.221 86.28 ;
     RECT  41.221 84.384 41.465 86.28 ;
     RECT  41.465 85.488 41.681 86.28 ;
     RECT  41.669 84.336 41.753 84.36 ;
     RECT  41.681 85.488 42.077 85.512 ;
     RECT  41.797 83.184 42.14 83.208 ;
     RECT  42.14 83.184 42.185 83.832 ;
     RECT  42.185 83.76 42.227 83.832 ;
     RECT  42.085 76.368 42.565 76.392 ;
     RECT  42.469 77.52 42.565 77.544 ;
     RECT  40.835 42.864 42.757 69.336 ;
     RECT  42.565 76.368 42.905 77.544 ;
     RECT  42.277 82.608 42.949 82.632 ;
     RECT  42.949 82.032 43.085 82.632 ;
     RECT  42.901 80.928 43.091 80.952 ;
     RECT  42.227 83.76 43.265 83.784 ;
     RECT  43.237 73.536 43.337 73.56 ;
     RECT  42.905 76.368 43.337 76.92 ;
     RECT  43.337 76.848 43.589 76.92 ;
     RECT  43.525 75.792 43.613 75.816 ;
     RECT  43.613 75.744 43.696 75.816 ;
     RECT  43.085 82.608 43.733 82.632 ;
     RECT  43.696 75.696 43.772 75.816 ;
     RECT  43.772 75.264 43.859 75.816 ;
     RECT  43.859 75.696 43.877 75.816 ;
     RECT  43.877 75.792 43.913 75.816 ;
     RECT  44.197 77.52 44.339 77.544 ;
     RECT  43.333 81.456 44.345 81.48 ;
     RECT  44.233 83.808 44.435 83.832 ;
     RECT  43.909 84.96 44.485 84.984 ;
     RECT  44.581 83.184 44.773 83.208 ;
     RECT  42.757 42.768 44.965 69.336 ;
     RECT  44.485 84.912 44.989 84.984 ;
     RECT  44.989 84.912 45.203 85.512 ;
     RECT  45.203 84.912 45.313 84.936 ;
     RECT  45.493 85.92 45.541 86.184 ;
     RECT  45.313 84.432 45.569 84.936 ;
     RECT  40.504 16.32 45.608 21.672 ;
     RECT  40.835 28.8 45.608 41.208 ;
     RECT  44.965 42.768 45.608 70.104 ;
     RECT  45.445 71.184 45.608 71.208 ;
     RECT  43.909 74.016 45.608 74.088 ;
     RECT  44.636 80.928 45.608 80.952 ;
     RECT  44.773 83.136 45.608 83.208 ;
     RECT  45.569 84.432 45.608 84.456 ;
     RECT  45.608 2.148 45.712 84.456 ;
     RECT  45.712 2.418 45.904 84.456 ;
     RECT  45.904 82.032 45.971 84.456 ;
     RECT  45.541 85.92 46.067 86.28 ;
     RECT  45.971 82.032 46.073 83.784 ;
     RECT  46.073 82.032 46.163 83.688 ;
     RECT  46.067 86.112 46.163 86.28 ;
     RECT  46.163 86.256 46.189 86.28 ;
     RECT  45.904 72.384 46.204 73.512 ;
     RECT  45.904 75.264 46.217 75.288 ;
     RECT  46.163 82.032 46.505 82.632 ;
     RECT  46.505 82.608 46.613 82.632 ;
     RECT  45.904 42.768 46.649 45.48 ;
     RECT  45.904 76.368 46.721 76.488 ;
     RECT  46.204 72.384 46.757 72.408 ;
     RECT  46.721 76.368 46.757 76.392 ;
     RECT  45.904 80.352 46.885 80.376 ;
     RECT  46.885 80.304 46.981 80.376 ;
     RECT  46.981 80.304 47.077 80.952 ;
     RECT  47.077 80.208 47.189 80.952 ;
     RECT  46.204 73.488 47.261 73.512 ;
     RECT  47.189 80.208 47.261 80.904 ;
     RECT  47.261 80.88 47.621 80.904 ;
     RECT  45.904 46.608 47.729 69.336 ;
     RECT  47.869 77.52 47.905 77.544 ;
     RECT  47.729 47.184 47.909 69.336 ;
     RECT  46.649 43.104 47.941 45.48 ;
     RECT  47.905 76.944 48.133 77.544 ;
     RECT  48.133 76.368 48.269 77.544 ;
     RECT  48.269 76.896 48.275 77.544 ;
     RECT  48.293 75.792 48.377 75.816 ;
     RECT  48.38 71.28 48.467 71.304 ;
     RECT  48.517 78.624 48.629 78.648 ;
     RECT  48.613 81.456 48.701 81.48 ;
     RECT  48.275 76.896 48.989 76.92 ;
     RECT  48.625 83.232 48.997 83.256 ;
     RECT  48.805 71.808 49.025 71.832 ;
     RECT  48.997 83.232 49.093 83.784 ;
     RECT  49.093 83.184 49.189 83.784 ;
     RECT  49.189 83.136 49.241 83.784 ;
     RECT  49.244 79.248 49.331 79.272 ;
     RECT  49.241 83.136 49.349 83.208 ;
     RECT  49.349 83.136 49.421 83.16 ;
     RECT  49.381 80.352 49.573 80.376 ;
     RECT  49.477 70.656 49.601 70.68 ;
     RECT  49.573 80.352 49.741 80.952 ;
     RECT  49.741 80.352 49.861 81.048 ;
     RECT  49.765 84.336 49.997 84.36 ;
     RECT  47.941 43.104 50.245 46.104 ;
     RECT  49.861 80.352 50.32 81.48 ;
     RECT  45.904 28.8 50.397 41.208 ;
     RECT  50.437 75.216 50.533 75.24 ;
     RECT  50.533 75.168 50.629 75.24 ;
     RECT  50.053 76.368 50.629 76.392 ;
     RECT  50.245 43.104 50.677 46.296 ;
     RECT  47.909 47.328 50.677 69.336 ;
     RECT  50.677 43.104 50.713 69.336 ;
     RECT  50.32 80.304 50.732 81.48 ;
     RECT  50.732 80.304 50.785 82.104 ;
     RECT  50.785 79.824 50.813 82.104 ;
     RECT  50.773 86.16 50.821 86.184 ;
     RECT  45.904 16.32 51.008 21.672 ;
     RECT  50.397 28.8 51.008 42.024 ;
     RECT  50.713 43.008 51.008 69.336 ;
     RECT  50.629 75.168 51.008 76.392 ;
     RECT  50.813 79.776 51.008 82.104 ;
     RECT  50.821 84.96 51.008 86.184 ;
     RECT  51.008 2.148 51.112 86.184 ;
     RECT  51.112 2.418 51.155 86.184 ;
     RECT  51.155 2.418 51.251 84.984 ;
     RECT  51.251 2.418 51.304 84.936 ;
     RECT  51.304 79.824 51.731 79.848 ;
     RECT  51.304 83.232 51.761 84.936 ;
     RECT  51.761 83.232 51.827 83.256 ;
     RECT  51.304 28.8 52.229 69.336 ;
     RECT  52.229 51.216 52.301 69.336 ;
     RECT  52.301 51.312 52.337 69.336 ;
     RECT  51.761 84.336 52.373 84.936 ;
     RECT  51.304 82.032 52.409 82.056 ;
     RECT  52.373 84.912 52.477 84.936 ;
     RECT  52.477 84.912 52.541 85.56 ;
     RECT  52.229 28.8 52.553 50.04 ;
     RECT  52.541 84.912 52.985 86.28 ;
     RECT  52.553 42.528 53.057 50.04 ;
     RECT  52.553 28.8 53.557 41.112 ;
     RECT  53.557 28.8 53.885 41.64 ;
     RECT  53.885 31.152 54.169 41.64 ;
     RECT  53.057 42.912 54.169 50.04 ;
     RECT  54.169 31.152 54.173 50.04 ;
     RECT  54.277 84.336 54.529 84.36 ;
     RECT  52.985 85.392 54.529 86.28 ;
     RECT  54.529 84.336 54.572 86.28 ;
     RECT  54.572 83.808 54.641 86.28 ;
     RECT  54.173 31.872 54.707 50.04 ;
     RECT  54.641 83.808 54.757 85.56 ;
     RECT  54.757 83.184 55.253 85.56 ;
     RECT  55.253 83.76 55.283 85.56 ;
     RECT  54.707 31.92 55.861 50.04 ;
     RECT  52.337 51.408 55.861 69.336 ;
     RECT  55.321 79.824 55.861 79.848 ;
     RECT  55.283 85.488 56.005 85.56 ;
     RECT  56.005 85.488 56.153 86.28 ;
     RECT  55.283 83.76 56.329 84.408 ;
     RECT  56.153 85.488 56.329 86.232 ;
     RECT  51.304 16.32 56.408 21.672 ;
     RECT  55.609 23.328 56.408 23.352 ;
     RECT  53.885 28.8 56.408 30.168 ;
     RECT  55.861 31.92 56.408 69.336 ;
     RECT  55.141 78.096 56.408 78.12 ;
     RECT  55.861 79.248 56.408 79.848 ;
     RECT  55.933 82.656 56.408 82.68 ;
     RECT  56.329 83.76 56.408 86.232 ;
     RECT  56.408 2.148 56.512 86.232 ;
     RECT  56.512 2.418 56.704 86.232 ;
     RECT  56.704 83.76 56.963 86.232 ;
     RECT  56.963 83.76 57.017 85.512 ;
     RECT  56.704 81.504 57.299 81.528 ;
     RECT  57.017 83.76 57.587 85.032 ;
     RECT  57.587 83.76 57.683 84.408 ;
     RECT  56.704 31.68 57.841 44.472 ;
     RECT  56.704 45.456 57.841 69.336 ;
     RECT  57.925 75.216 58.013 75.24 ;
     RECT  57.841 31.68 58.057 69.336 ;
     RECT  56.704 28.8 58.093 30.168 ;
     RECT  58.057 31.152 58.093 69.336 ;
     RECT  58.013 75.12 58.097 75.24 ;
     RECT  58.093 28.8 58.133 69.336 ;
     RECT  58.097 75.216 58.133 75.24 ;
     RECT  58.133 43.68 58.205 69.336 ;
     RECT  58.133 28.8 58.241 42.6 ;
     RECT  58.241 28.8 58.277 42.216 ;
     RECT  58.277 28.8 58.493 42.024 ;
     RECT  58.201 85.488 58.501 85.56 ;
     RECT  58.813 72.384 58.931 72.408 ;
     RECT  57.683 83.76 59.077 84.36 ;
     RECT  59.077 83.712 59.165 84.36 ;
     RECT  59.165 83.616 59.249 84.36 ;
     RECT  58.205 44.112 59.285 69.336 ;
     RECT  59.249 83.712 59.285 84.36 ;
     RECT  58.501 85.488 59.465 86.28 ;
     RECT  58.493 28.944 59.497 42.024 ;
     RECT  59.497 28.944 59.609 42.072 ;
     RECT  59.285 83.808 59.788 84.36 ;
     RECT  59.788 84.336 59.789 84.36 ;
     RECT  59.285 45.024 59.861 69.336 ;
     RECT  59.609 28.944 59.969 42.024 ;
     RECT  59.845 84.384 59.969 84.936 ;
     RECT  59.465 86.256 60.005 86.28 ;
     RECT  59.701 43.92 60.037 43.944 ;
     RECT  59.969 84.384 60.179 84.408 ;
     RECT  60.229 82.608 60.329 82.632 ;
     RECT  60.037 43.344 60.361 43.944 ;
     RECT  60.421 80.928 60.497 80.952 ;
     RECT  60.361 43.344 60.545 44.328 ;
     RECT  60.497 80.928 60.581 81.48 ;
     RECT  60.325 73.536 60.86 73.56 ;
     RECT  60.545 44.304 60.865 44.328 ;
     RECT  59.861 45.312 60.865 69.336 ;
     RECT  60.709 79.776 61.189 79.8 ;
     RECT  60.581 80.928 61.189 80.952 ;
     RECT  59.969 28.944 61.297 41.256 ;
     RECT  60.997 86.256 61.381 86.28 ;
     RECT  61.381 86.16 61.573 86.28 ;
     RECT  61.621 84.336 61.669 84.36 ;
     RECT  61.297 28.944 61.693 41.976 ;
     RECT  61.669 83.76 61.693 84.408 ;
     RECT  56.704 16.32 61.808 21.672 ;
     RECT  56.704 23.28 61.808 23.352 ;
     RECT  60.685 25.008 61.808 25.032 ;
     RECT  61.693 28.896 61.808 41.976 ;
     RECT  60.865 44.304 61.808 69.336 ;
     RECT  60.86 73.536 61.808 73.656 ;
     RECT  61.189 79.776 61.808 80.952 ;
     RECT  61.693 83.76 61.808 84.456 ;
     RECT  61.808 2.148 61.912 84.456 ;
     RECT  61.912 2.418 61.916 84.456 ;
     RECT  61.573 85.488 61.916 86.28 ;
     RECT  61.916 2.418 62.104 86.28 ;
     RECT  62.104 84.816 62.201 86.28 ;
     RECT  62.201 86.16 62.597 86.28 ;
     RECT  62.104 45.024 62.921 69.336 ;
     RECT  62.921 45.456 63.029 69.336 ;
     RECT  62.104 83.808 63.097 83.832 ;
     RECT  62.201 84.816 63.097 84.936 ;
     RECT  63.097 83.808 63.133 84.936 ;
     RECT  63.029 45.456 63.137 53.4 ;
     RECT  63.133 83.232 63.155 84.936 ;
     RECT  63.137 49.056 63.245 53.4 ;
     RECT  62.104 74.064 63.245 74.088 ;
     RECT  63.155 83.232 63.251 83.256 ;
     RECT  63.137 45.456 63.353 47.448 ;
     RECT  63.245 51.12 63.353 53.4 ;
     RECT  63.353 45.456 63.497 47.4 ;
     RECT  63.353 51.168 63.497 53.4 ;
     RECT  62.104 28.752 63.565 42.072 ;
     RECT  63.155 84.336 63.569 84.936 ;
     RECT  63.569 84.384 63.637 84.936 ;
     RECT  63.637 84.384 63.731 84.984 ;
     RECT  63.565 28.704 63.781 42.072 ;
     RECT  63.245 49.056 63.785 49.8 ;
     RECT  63.785 49.056 63.821 49.08 ;
     RECT  63.731 84.912 63.853 84.984 ;
     RECT  62.597 86.208 63.853 86.28 ;
     RECT  63.781 28.464 64.325 42.072 ;
     RECT  63.853 84.912 64.541 86.28 ;
     RECT  64.325 29.136 64.901 42.072 ;
     RECT  64.901 29.184 65.333 42.072 ;
     RECT  65.333 29.616 66.017 42.072 ;
     RECT  64.541 85.488 66.131 86.28 ;
     RECT  66.131 86.208 66.341 86.28 ;
     RECT  66.341 86.256 66.449 86.28 ;
     RECT  62.104 16.32 67.208 21.672 ;
     RECT  62.104 23.28 67.208 23.352 ;
     RECT  62.104 25.008 67.208 25.032 ;
     RECT  66.049 27.792 67.208 27.816 ;
     RECT  66.017 29.856 67.208 42.072 ;
     RECT  63.497 45.456 67.208 47.208 ;
     RECT  64.933 49.008 67.208 49.032 ;
     RECT  63.497 51.456 67.208 53.4 ;
     RECT  63.029 54.384 67.208 69.336 ;
     RECT  67.208 2.148 67.312 84.252 ;
     RECT  67.312 2.418 67.504 83.982 ;
     RECT  67.504 16.32 72.608 21.672 ;
     RECT  67.504 23.28 72.608 23.352 ;
     RECT  67.504 25.008 72.608 25.032 ;
     RECT  67.504 29.856 72.608 42.072 ;
     RECT  67.504 45.456 72.608 47.208 ;
     RECT  67.504 49.008 72.608 49.032 ;
     RECT  67.504 51.456 72.608 53.4 ;
     RECT  67.504 54.48 72.608 69.336 ;
     RECT  72.608 2.148 72.712 84.252 ;
     RECT  72.712 2.418 72.904 83.982 ;
     RECT  72.904 54.48 74.653 69.336 ;
     RECT  72.904 23.28 75.481 23.352 ;
     RECT  72.904 16.32 78.008 21.672 ;
     RECT  75.481 23.28 78.008 23.4 ;
     RECT  72.904 25.008 78.008 25.032 ;
     RECT  72.904 29.856 78.008 42.072 ;
     RECT  72.904 45.456 78.008 47.208 ;
     RECT  72.904 49.008 78.008 49.032 ;
     RECT  72.904 51.456 78.008 53.4 ;
     RECT  74.653 54.384 78.008 69.336 ;
     RECT  78.008 2.148 78.112 84.252 ;
     RECT  78.112 2.418 78.304 83.982 ;
     RECT  78.304 23.28 79.477 23.4 ;
     RECT  78.304 25.008 79.477 25.032 ;
     RECT  78.304 29.856 79.693 42.072 ;
     RECT  78.304 45.456 79.729 47.208 ;
     RECT  78.304 43.92 79.765 43.944 ;
     RECT  79.729 44.928 79.765 47.208 ;
     RECT  79.693 29.856 80.341 42.744 ;
     RECT  79.765 43.92 80.341 47.208 ;
     RECT  80.341 27.072 81.457 27.096 ;
     RECT  80.917 28.176 81.457 28.2 ;
     RECT  78.304 51.456 81.457 53.4 ;
     RECT  78.304 54.48 81.457 69.336 ;
     RECT  78.304 16.32 82.033 21.672 ;
     RECT  80.665 26.064 82.033 26.088 ;
     RECT  81.457 27.072 82.033 28.2 ;
     RECT  80.341 29.856 82.033 47.208 ;
     RECT  79.477 23.28 82.321 25.032 ;
     RECT  82.033 26.064 82.321 28.2 ;
     RECT  82.033 29.808 82.573 47.208 ;
     RECT  82.573 29.616 82.609 47.208 ;
     RECT  82.321 23.28 83.149 28.2 ;
     RECT  82.033 16.32 83.185 22.008 ;
     RECT  83.149 23.04 83.185 28.2 ;
     RECT  82.609 29.472 83.185 47.208 ;
     RECT  81.457 50.64 83.185 69.336 ;
     RECT  83.185 16.32 83.408 28.296 ;
     RECT  83.185 29.472 83.408 47.688 ;
     RECT  78.304 49.008 83.408 49.032 ;
     RECT  83.185 50.064 83.408 69.336 ;
     RECT  83.408 2.148 83.512 84.252 ;
     RECT  83.512 2.418 83.704 83.982 ;
     RECT  83.704 16.32 83.837 69.336 ;
     RECT  83.837 39.408 84.913 69.336 ;
     RECT  84.913 39.312 84.985 69.336 ;
     RECT  83.837 16.32 86.209 38.184 ;
     RECT  86.209 16.272 86.245 38.184 ;
     RECT  84.985 39.216 86.245 69.336 ;
     RECT  86.245 16.176 86.281 69.336 ;
     RECT  86.281 16.08 86.321 69.336 ;
     RECT  86.321 16.08 86.364 69.096 ;
    LAYER M5 ;
     RECT  2.4 2.137 2.52 2.151 ;
     RECT  7.8 2.137 7.92 2.151 ;
     RECT  13.2 2.137 13.32 2.151 ;
     RECT  18.6 2.137 18.72 2.151 ;
     RECT  24 2.137 24.12 2.151 ;
     RECT  29.4 2.137 29.52 2.151 ;
     RECT  34.8 2.137 34.92 2.151 ;
     RECT  40.2 2.137 40.32 2.151 ;
     RECT  45.6 2.137 45.72 2.151 ;
     RECT  51 2.137 51.12 2.151 ;
     RECT  56.4 2.137 56.52 2.151 ;
     RECT  61.8 2.137 61.92 2.151 ;
     RECT  67.2 2.137 67.32 2.151 ;
     RECT  72.6 2.137 72.72 2.151 ;
     RECT  78 2.137 78.12 2.151 ;
     RECT  83.4 2.137 83.52 2.151 ;
     RECT  86.208 17.461 86.232 17.699 ;
     RECT  0.144 17.221 0.168 18.755 ;
     RECT  22.8 19.141 22.824 19.283 ;
     RECT  0.192 21.493 0.216 21.731 ;
     RECT  10.848 21.733 10.872 21.971 ;
     RECT  21.12 23.893 21.144 24.611 ;
     RECT  0.144 22.597 0.168 24.707 ;
     RECT  7.8 2.151 8.112 24.901 ;
     RECT  0.192 24.853 0.216 25.043 ;
     RECT  40.2 2.151 40.512 25.189 ;
     RECT  17.328 24.373 17.352 25.477 ;
     RECT  40.2 25.189 40.632 25.621 ;
     RECT  21.072 25.381 21.096 26.243 ;
     RECT  9.312 26.293 9.336 26.675 ;
     RECT  7.8 24.901 8.232 26.867 ;
     RECT  39.6 25.621 40.632 27.301 ;
     RECT  14.832 27.781 14.856 27.923 ;
     RECT  38.496 27.301 38.52 28.453 ;
     RECT  63.792 28.453 63.816 29.075 ;
     RECT  38.208 28.453 38.52 29.459 ;
     RECT  18.6 2.151 18.912 29.605 ;
     RECT  58.704 30.037 58.728 30.227 ;
     RECT  61.8 2.151 62.112 30.325 ;
     RECT  49.008 30.037 49.032 30.515 ;
     RECT  86.208 30.757 86.232 30.947 ;
     RECT  51 2.151 51.312 31.141 ;
     RECT  51 31.141 52.104 31.283 ;
     RECT  21.456 30.805 21.48 31.285 ;
     RECT  16.848 25.477 17.352 31.379 ;
     RECT  39.6 27.301 40.68 31.381 ;
     RECT  15.6 31.429 15.624 31.621 ;
     RECT  15.504 31.621 15.624 31.763 ;
     RECT  54.672 31.861 54.696 32.005 ;
     RECT  54.144 32.005 54.696 32.051 ;
     RECT  18.384 29.605 18.912 32.197 ;
     RECT  13.2 2.151 13.512 32.245 ;
     RECT  38.496 29.459 38.52 32.341 ;
     RECT  39.6 31.381 40.776 32.341 ;
     RECT  18.24 32.197 18.912 32.435 ;
     RECT  21.456 31.285 21.816 32.437 ;
     RECT  51 31.283 51.312 32.437 ;
     RECT  14.928 31.861 14.952 32.483 ;
     RECT  21.36 32.437 21.816 32.533 ;
     RECT  20.976 32.533 21.816 32.771 ;
     RECT  52.8 32.485 52.824 32.771 ;
     RECT  16.848 31.379 16.872 33.061 ;
     RECT  18.384 32.435 18.912 33.061 ;
     RECT  51 32.437 51.672 33.205 ;
     RECT  51 33.205 52.392 33.347 ;
     RECT  54.144 32.051 54.168 33.539 ;
     RECT  0.672 33.061 0.696 33.587 ;
     RECT  63.792 32.341 63.816 33.589 ;
     RECT  65.52 30.325 65.544 33.589 ;
     RECT  16.656 33.061 16.872 33.733 ;
     RECT  13.104 32.245 13.512 33.875 ;
     RECT  16.272 33.733 16.872 33.877 ;
     RECT  15.6 33.877 16.872 33.971 ;
     RECT  18.384 33.061 19.32 33.973 ;
     RECT  20.304 33.013 20.328 33.973 ;
     RECT  15.6 33.971 15.624 34.115 ;
     RECT  54.384 33.733 54.552 34.163 ;
     RECT  18.384 33.973 20.328 34.211 ;
     RECT  24 2.151 24.312 34.453 ;
     RECT  51 33.347 52.248 34.453 ;
     RECT  16.848 33.971 16.872 34.499 ;
     RECT  54.384 34.163 54.504 34.549 ;
     RECT  53.904 34.549 54.504 34.739 ;
     RECT  51 34.453 52.68 34.885 ;
     RECT  63.792 33.589 65.544 34.931 ;
     RECT  51 34.885 52.776 35.173 ;
     RECT  64.368 34.931 65.544 35.411 ;
     RECT  64.368 35.411 64.44 35.459 ;
     RECT  51 35.173 53.064 35.555 ;
     RECT  51 35.555 51.864 35.699 ;
     RECT  38.496 32.341 40.776 35.701 ;
     RECT  54.384 34.739 54.504 35.845 ;
     RECT  86.064 35.749 86.088 35.891 ;
     RECT  38.208 35.701 40.776 35.893 ;
     RECT  54.096 35.845 54.504 35.939 ;
     RECT  29.4 2.151 29.712 36.133 ;
     RECT  52.944 35.555 53.064 36.229 ;
     RECT  54.096 35.939 54.12 36.229 ;
     RECT  56.4 2.151 56.712 36.277 ;
     RECT  38.208 35.893 41.064 36.515 ;
     RECT  29.28 36.133 29.712 36.755 ;
     RECT  17.136 36.517 17.16 36.899 ;
     RECT  24 34.453 24.6 36.901 ;
     RECT  52.944 36.229 54.12 37.141 ;
     RECT  23.616 36.901 24.6 37.333 ;
     RECT  56.4 36.277 57.432 37.427 ;
     RECT  22.8 37.333 24.6 37.523 ;
     RECT  18.384 34.211 18.912 37.573 ;
     RECT  52.944 37.141 54.552 38.245 ;
     RECT  56.4 37.427 56.808 38.245 ;
     RECT  52.944 38.245 56.808 38.387 ;
     RECT  52.944 38.387 54.552 38.533 ;
     RECT  59.904 35.989 59.928 38.675 ;
     RECT  58.704 37.141 58.728 38.915 ;
     RECT  39.168 36.515 41.064 39.011 ;
     RECT  18.24 37.573 18.912 39.253 ;
     RECT  51 35.699 51.528 39.397 ;
     RECT  52.848 38.533 54.552 39.397 ;
     RECT  18.144 39.253 18.912 39.445 ;
     RECT  33.744 36.661 33.768 39.589 ;
     RECT  36.432 36.325 36.456 39.635 ;
     RECT  50.448 39.397 54.552 39.829 ;
     RECT  17.52 39.445 18.912 39.877 ;
     RECT  15.696 36.757 15.72 40.069 ;
     RECT  50.448 39.829 54.648 40.117 ;
     RECT  61.632 30.325 62.112 40.163 ;
     RECT  14.928 40.069 15.72 40.355 ;
     RECT  50.448 40.117 55.416 40.595 ;
     RECT  33.408 39.589 33.768 40.741 ;
     RECT  34.8 2.151 35.112 40.741 ;
     RECT  52.944 40.595 55.416 41.123 ;
     RECT  23.616 37.523 24.6 41.267 ;
     RECT  15.696 40.355 15.72 41.605 ;
     RECT  26.784 41.557 26.904 41.939 ;
     RECT  22.8 41.701 22.824 41.987 ;
     RECT  26.784 41.939 26.808 42.035 ;
     RECT  33.408 40.741 35.112 42.035 ;
     RECT  50.448 40.595 51.912 42.035 ;
     RECT  15.696 41.605 16.392 42.133 ;
     RECT  17.424 39.877 18.912 42.133 ;
     RECT  51 42.035 51.912 42.469 ;
     RECT  52.944 41.123 55.08 42.469 ;
     RECT  56.4 38.387 56.808 42.611 ;
     RECT  56.4 42.611 56.712 42.709 ;
     RECT  33.408 42.035 33.768 42.803 ;
     RECT  59.664 41.653 59.688 43.333 ;
     RECT  51 42.469 55.08 43.429 ;
     RECT  83.4 2.151 83.712 44.101 ;
     RECT  56.304 42.709 56.712 44.195 ;
     RECT  83.088 44.101 83.712 44.387 ;
     RECT  86.208 44.101 86.232 44.387 ;
     RECT  33.552 42.803 33.768 44.437 ;
     RECT  34.8 42.035 35.112 44.437 ;
     RECT  51 43.429 55.32 44.723 ;
     RECT  59.664 43.333 60.072 45.013 ;
     RECT  51 44.723 55.08 45.059 ;
     RECT  30.864 45.157 30.888 45.299 ;
     RECT  61.8 40.163 62.112 45.685 ;
     RECT  31.92 45.013 31.944 45.877 ;
     RECT  31.92 45.877 32.28 45.923 ;
     RECT  61.296 45.685 62.112 46.451 ;
     RECT  56.4 44.195 56.712 46.549 ;
     RECT  24 41.267 24.6 46.741 ;
     RECT  32.256 45.923 32.28 46.787 ;
     RECT  61.584 46.451 62.112 46.835 ;
     RECT  56.4 46.549 56.808 46.837 ;
     RECT  64.368 35.459 64.392 46.837 ;
     RECT  56.4 46.837 57.048 46.979 ;
     RECT  63.456 46.837 64.392 47.123 ;
     RECT  0.192 34.981 0.216 47.413 ;
     RECT  0.192 47.413 0.552 47.459 ;
     RECT  15.696 42.133 18.912 47.893 ;
     RECT  19.92 34.211 20.328 47.893 ;
     RECT  59.568 45.013 60.072 47.989 ;
     RECT  47.952 46.069 47.976 48.083 ;
     RECT  45.6 2.151 45.912 48.085 ;
     RECT  56.4 46.979 56.808 48.613 ;
     RECT  61.8 46.835 62.112 48.661 ;
     RECT  45.6 48.085 46.008 48.853 ;
     RECT  56.4 48.613 56.856 48.901 ;
     RECT  59.52 47.989 60.072 48.901 ;
     RECT  61.8 48.661 62.616 48.901 ;
     RECT  32.496 48.421 32.52 48.947 ;
     RECT  43.728 47.845 43.752 48.995 ;
     RECT  44.976 48.853 46.008 49.043 ;
     RECT  56.4 48.901 57.048 49.043 ;
     RECT  45.504 49.043 46.008 49.091 ;
     RECT  0.528 47.459 0.552 49.139 ;
     RECT  59.52 48.901 62.616 49.139 ;
     RECT  29.4 36.755 29.712 49.237 ;
     RECT  27.264 46.645 27.288 49.283 ;
     RECT  59.52 49.139 62.112 49.379 ;
     RECT  49.488 49.429 49.512 49.571 ;
     RECT  39.6 39.011 41.064 49.861 ;
     RECT  29.4 49.237 29.928 50.341 ;
     RECT  59.52 49.379 60.072 50.485 ;
     RECT  29.4 50.341 30.888 50.579 ;
     RECT  58.32 45.013 58.344 50.629 ;
     RECT  59.52 50.485 60.12 50.629 ;
     RECT  58.32 50.629 60.12 50.675 ;
     RECT  48.96 49.909 48.984 50.771 ;
     RECT  47.712 48.757 47.736 50.917 ;
     RECT  51 45.059 51.528 51.301 ;
     RECT  44.304 51.541 44.328 51.589 ;
     RECT  50.832 51.301 51.528 51.589 ;
     RECT  50.832 51.589 51.672 51.637 ;
     RECT  43.92 51.589 44.328 51.683 ;
     RECT  50.16 51.637 51.672 51.875 ;
     RECT  39.6 49.861 41.64 51.923 ;
     RECT  59.136 50.675 60.12 51.923 ;
     RECT  47.712 50.917 48.36 51.973 ;
     RECT  50.16 51.875 51.312 51.973 ;
     RECT  47.712 51.973 51.312 52.115 ;
     RECT  45.504 49.091 45.912 52.117 ;
     RECT  43.92 51.683 43.944 52.403 ;
     RECT  0.192 52.309 0.216 52.547 ;
     RECT  59.664 51.923 60.12 52.693 ;
     RECT  59.664 52.693 60.6 52.835 ;
     RECT  47.712 52.115 48.648 52.883 ;
     RECT  44.976 52.117 45.912 52.981 ;
     RECT  47.712 52.883 48.312 53.027 ;
     RECT  56.4 49.043 56.712 53.173 ;
     RECT  56.4 53.173 56.808 53.315 ;
     RECT  44.544 52.981 45.912 53.507 ;
     RECT  59.664 52.835 60.168 53.555 ;
     RECT  50.16 52.115 51.312 53.603 ;
     RECT  43.92 53.509 43.944 53.699 ;
     RECT  47.712 53.027 48.072 54.179 ;
     RECT  26.784 54.229 26.808 54.371 ;
     RECT  45.504 53.507 45.912 54.371 ;
     RECT  39.6 51.923 41.208 54.421 ;
     RECT  42.192 54.037 42.216 54.421 ;
     RECT  39.6 54.421 42.216 54.707 ;
     RECT  39.6 54.707 41.064 54.949 ;
     RECT  39.408 54.949 41.064 55.235 ;
     RECT  0.24 55.141 0.264 55.283 ;
     RECT  42.192 54.707 42.216 55.525 ;
     RECT  44.448 55.141 44.472 55.525 ;
     RECT  45.6 54.371 45.912 55.525 ;
     RECT  42.192 55.525 43.032 55.667 ;
     RECT  44.448 55.525 45.912 55.715 ;
     RECT  43.008 55.667 43.032 55.859 ;
     RECT  44.448 55.715 44.472 55.907 ;
     RECT  45.6 55.715 45.912 55.957 ;
     RECT  37.2 56.197 37.224 56.339 ;
     RECT  15.696 47.893 20.328 56.389 ;
     RECT  21.36 32.771 21.816 56.389 ;
     RECT  48.048 54.179 48.072 56.483 ;
     RECT  45.6 55.957 46.056 56.725 ;
     RECT  39.6 55.235 41.064 57.011 ;
     RECT  39.6 57.011 41.112 57.109 ;
     RECT  39.6 57.109 41.64 57.491 ;
     RECT  50.64 53.603 51.312 57.541 ;
     RECT  15.696 56.389 21.816 58.117 ;
     RECT  50.64 57.541 51.48 58.163 ;
     RECT  15.696 58.117 22.728 58.259 ;
     RECT  50.88 58.163 51.48 58.259 ;
     RECT  44.352 57.925 44.376 58.307 ;
     RECT  26.736 58.213 26.76 58.355 ;
     RECT  22.8 58.357 22.92 58.643 ;
     RECT  33.552 44.437 35.112 59.269 ;
     RECT  45.6 56.725 46.2 59.365 ;
     RECT  33.456 59.269 35.112 59.411 ;
     RECT  48.192 58.741 48.216 59.411 ;
     RECT  33.552 59.411 35.112 59.461 ;
     RECT  45.6 59.365 46.728 60.035 ;
     RECT  22.944 58.645 22.968 60.275 ;
     RECT  29.4 50.579 29.928 60.613 ;
     RECT  26.784 60.565 26.808 60.755 ;
     RECT  29.184 60.613 29.928 60.805 ;
     RECT  22.8 60.805 22.824 60.947 ;
     RECT  29.088 60.805 29.928 60.995 ;
     RECT  37.056 61.573 37.08 61.907 ;
     RECT  24 46.741 24.792 62.195 ;
     RECT  15.696 58.259 21.816 62.197 ;
     RECT  2.4 2.151 2.712 62.341 ;
     RECT  13.2 33.875 13.512 62.341 ;
     RECT  2.4 62.341 2.808 62.437 ;
     RECT  13.2 62.341 13.608 62.483 ;
     RECT  2.4 62.437 2.904 62.579 ;
     RECT  27.36 60.949 27.384 62.629 ;
     RECT  7.8 26.867 8.112 62.773 ;
     RECT  10.704 62.677 10.728 62.773 ;
     RECT  14.832 62.197 21.816 62.773 ;
     RECT  10.704 62.773 10.824 62.819 ;
     RECT  26.736 62.629 27.384 62.819 ;
     RECT  26.928 62.819 27.384 62.869 ;
     RECT  6.816 62.773 8.112 62.915 ;
     RECT  24 62.195 24.504 63.011 ;
     RECT  10.8 62.819 10.824 63.059 ;
     RECT  14.784 62.773 21.816 63.059 ;
     RECT  26.928 62.869 27.72 63.157 ;
     RECT  39.6 57.491 41.16 63.157 ;
     RECT  26.928 63.157 27.912 63.203 ;
     RECT  32.352 62.965 32.376 63.251 ;
     RECT  29.4 60.995 29.928 63.829 ;
     RECT  29.4 63.829 30.024 64.021 ;
     RECT  27.024 63.203 27.912 64.067 ;
     RECT  33.552 59.461 35.736 64.405 ;
     RECT  24 63.011 24.312 64.549 ;
     RECT  39.024 63.157 41.16 64.595 ;
     RECT  13.2 62.483 13.512 64.597 ;
     RECT  24 64.549 24.408 64.597 ;
     RECT  33.552 64.405 36.408 64.643 ;
     RECT  24 64.597 24.6 64.645 ;
     RECT  24 64.645 25.128 64.787 ;
     RECT  29.136 64.021 30.024 64.789 ;
     RECT  86.208 64.645 86.232 64.835 ;
     RECT  29.136 64.789 30.072 64.885 ;
     RECT  28.656 64.885 30.072 64.979 ;
     RECT  39.6 64.595 41.16 64.979 ;
     RECT  33.552 64.643 35.832 65.603 ;
     RECT  33.552 65.603 35.304 65.843 ;
     RECT  51 58.259 51.312 66.133 ;
     RECT  52.944 45.059 55.08 66.133 ;
     RECT  15.696 63.059 21.816 66.709 ;
     RECT  13.2 64.597 14.28 66.899 ;
     RECT  61.8 49.379 62.112 67.093 ;
     RECT  56.4 53.315 56.712 67.237 ;
     RECT  57.84 64.933 57.864 67.237 ;
     RECT  24 64.787 25.032 67.283 ;
     RECT  28.656 64.979 30.024 67.283 ;
     RECT  83.4 44.387 83.712 67.861 ;
     RECT  0.144 67.717 0.168 67.907 ;
     RECT  15.696 66.709 22.056 68.005 ;
     RECT  14.784 68.005 22.056 68.147 ;
     RECT  83.088 67.861 83.712 68.243 ;
     RECT  56.4 67.237 57.864 68.293 ;
     RECT  27.024 64.067 27.048 68.339 ;
     RECT  39.6 64.979 41.064 68.341 ;
     RECT  24 67.283 24.792 68.677 ;
     RECT  23.424 68.677 24.792 69.395 ;
     RECT  23.424 69.395 24.504 69.443 ;
     RECT  15.696 68.147 22.056 69.445 ;
     RECT  14.832 69.445 22.056 69.731 ;
     RECT  45.6 60.035 45.912 70.069 ;
     RECT  33.552 65.843 35.112 70.501 ;
     RECT  33.552 70.501 35.256 70.643 ;
     RECT  28.656 67.283 29.712 70.835 ;
     RECT  23.472 69.443 24.504 70.931 ;
     RECT  48.432 71.269 48.456 71.797 ;
     RECT  49.488 70.645 49.512 71.797 ;
     RECT  44.976 70.069 45.912 72.373 ;
     RECT  56.4 68.293 58.632 72.373 ;
     RECT  59.664 53.555 60.072 72.373 ;
     RECT  24 70.931 24.504 72.419 ;
     RECT  27.312 70.645 27.336 72.707 ;
     RECT  33.552 70.643 35.112 73.525 ;
     RECT  56.4 72.373 60.072 73.525 ;
     RECT  61.8 67.093 62.664 73.525 ;
     RECT  15.696 69.731 22.056 74.005 ;
     RECT  43.248 73.525 43.272 74.005 ;
     RECT  44.976 72.373 46.728 74.005 ;
     RECT  15.696 74.005 22.92 74.053 ;
     RECT  24 72.419 24.312 74.053 ;
     RECT  56.4 73.525 62.664 74.053 ;
     RECT  39.6 68.341 41.544 74.101 ;
     RECT  38.736 74.101 41.544 74.629 ;
     RECT  51 66.133 55.08 75.157 ;
     RECT  48.432 71.797 49.512 75.205 ;
     RECT  50.544 75.157 55.08 75.205 ;
     RECT  15.696 74.053 24.648 75.251 ;
     RECT  33.456 73.525 35.688 75.253 ;
     RECT  33.36 75.253 35.688 75.781 ;
     RECT  48.432 75.205 55.08 75.781 ;
     RECT  38.64 74.629 41.544 75.829 ;
     RECT  33.264 75.781 35.688 76.357 ;
     RECT  38.064 75.829 41.544 76.357 ;
     RECT  43.248 74.005 46.728 76.357 ;
     RECT  48.336 75.781 55.08 76.357 ;
     RECT  38.064 76.357 42.12 76.837 ;
     RECT  43.152 76.357 46.728 76.837 ;
     RECT  48.144 76.357 55.08 76.933 ;
     RECT  33.072 76.357 35.688 77.509 ;
     RECT  38.064 76.837 46.728 77.509 ;
     RECT  29.4 70.835 29.712 77.989 ;
     RECT  32.496 77.509 35.688 78.037 ;
     RECT  37.776 77.509 46.728 78.037 ;
     RECT  48.048 76.933 55.08 78.085 ;
     RECT  56.4 74.053 63.048 78.085 ;
     RECT  31.824 78.037 35.688 78.517 ;
     RECT  15.696 75.251 24.312 78.613 ;
     RECT  15.6 78.613 24.312 80.149 ;
     RECT  28.944 77.989 29.712 80.149 ;
     RECT  36.912 78.037 46.728 80.197 ;
     RECT  48.048 78.085 63.048 80.197 ;
     RECT  13.2 66.899 13.512 80.245 ;
     RECT  14.64 80.149 24.312 80.245 ;
     RECT  26.736 78.037 26.76 80.341 ;
     RECT  28.944 80.149 30.12 80.341 ;
     RECT  26.064 80.341 26.76 82.069 ;
     RECT  27.888 80.341 27.912 82.069 ;
     RECT  36.912 80.197 63.048 82.069 ;
     RECT  31.728 78.517 35.688 82.213 ;
     RECT  31.344 82.213 35.688 82.597 ;
     RECT  36.72 82.069 63.048 82.597 ;
     RECT  13.2 80.245 24.312 82.645 ;
     RECT  31.344 82.597 63.048 82.645 ;
     RECT  31.248 82.645 63.048 83.221 ;
     RECT  13.2 82.645 24.936 83.749 ;
     RECT  26.064 82.069 27.912 83.749 ;
     RECT  28.944 80.341 30.216 83.749 ;
     RECT  31.248 83.221 63.24 83.749 ;
     RECT  2.4 62.579 2.712 84.249 ;
     RECT  7.8 62.915 8.112 84.249 ;
     RECT  67.2 2.151 67.512 84.249 ;
     RECT  72.6 2.151 72.912 84.249 ;
     RECT  78 2.151 78.312 84.249 ;
     RECT  83.4 68.243 83.712 84.249 ;
     RECT  2.4 84.249 2.52 84.263 ;
     RECT  7.8 84.249 7.92 84.263 ;
     RECT  13.2 83.749 27.912 84.263 ;
     RECT  67.2 84.249 67.32 84.263 ;
     RECT  72.6 84.249 72.72 84.263 ;
     RECT  78 84.249 78.12 84.263 ;
     RECT  83.4 84.249 83.52 84.263 ;
     RECT  14.16 84.263 27.912 84.325 ;
     RECT  28.944 83.749 63.24 84.325 ;
     RECT  14.16 84.325 63.336 84.373 ;
     RECT  64.368 47.123 64.392 84.373 ;
     RECT  14.16 84.373 64.392 84.901 ;
     RECT  14.16 84.901 64.488 85.477 ;
     RECT  65.52 35.411 65.544 85.477 ;
     RECT  14.16 85.477 66.12 86.197 ;
     RECT  14.16 86.197 66.312 86.245 ;
     RECT  14.16 86.245 66.408 86.352 ;
  END
END ot_attn_hi_merge
END LIBRARY
